# MODELED licensed PHY: geometry/timing assumptions, not silicon signoff
VERSION 5.8 ;
BUSBITCHARS "[]" ;
DIVIDERCHAR "/" ;
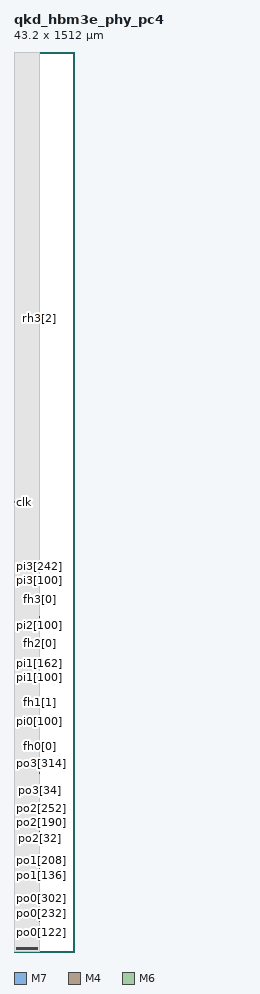
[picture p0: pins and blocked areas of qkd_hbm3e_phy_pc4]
MACRO qkd_hbm3e_phy_pc4
 CLASS BLOCK ;
 ORIGIN 0 0 ;
 SYMMETRY X Y ;
 SIZE 43.2 BY 1512 ;
 PIN clk
  DIRECTION INPUT ;
  USE CLOCK ;
  PORT
   LAYER M7 ;
   RECT 0.000000 755.904000 0.024000 756.096000 ;
  END
 END clk
 PIN rst_n
  DIRECTION INPUT ;
  USE SIGNAL ;
  PORT
   LAYER M7 ;
   RECT 0.000000 755.520000 0.024000 755.712000 ;
   RECT 0.000000 1485.984000 0.024000 1486.176000 ;
  END
 END rst_n
 PIN po0[0]
  DIRECTION INPUT ;
  USE SIGNAL ;
  PORT
   LAYER M4 ;
   RECT 43.008000 26.508000 43.200000 26.532000 ;
  END
 END po0[0]
 PIN po0[1]
  DIRECTION INPUT ;
  USE SIGNAL ;
  PORT
   LAYER M6 ;
   RECT 43.008000 26.352000 43.200000 26.384000 ;
  END
 END po0[1]
 PIN po0[2]
  DIRECTION INPUT ;
  USE SIGNAL ;
  PORT
   LAYER M4 ;
   RECT 43.008000 26.844000 43.200000 26.868000 ;
  END
 END po0[2]
 PIN po0[3]
  DIRECTION INPUT ;
  USE SIGNAL ;
  PORT
   LAYER M6 ;
   RECT 43.008000 26.608000 43.200000 26.640000 ;
  END
 END po0[3]
 PIN po0[4]
  DIRECTION INPUT ;
  USE SIGNAL ;
  PORT
   LAYER M4 ;
   RECT 43.008000 27.180000 43.200000 27.204000 ;
  END
 END po0[4]
 PIN po0[5]
  DIRECTION INPUT ;
  USE SIGNAL ;
  PORT
   LAYER M6 ;
   RECT 43.008000 26.864000 43.200000 26.896000 ;
  END
 END po0[5]
 PIN po0[6]
  DIRECTION INPUT ;
  USE SIGNAL ;
  PORT
   LAYER M4 ;
   RECT 43.008000 27.516000 43.200000 27.540000 ;
  END
 END po0[6]
 PIN po0[7]
  DIRECTION INPUT ;
  USE SIGNAL ;
  PORT
   LAYER M6 ;
   RECT 43.008000 27.120000 43.200000 27.152000 ;
  END
 END po0[7]
 PIN po0[8]
  DIRECTION INPUT ;
  USE SIGNAL ;
  PORT
   LAYER M4 ;
   RECT 43.008000 27.804000 43.200000 27.828000 ;
  END
 END po0[8]
 PIN po0[9]
  DIRECTION INPUT ;
  USE SIGNAL ;
  PORT
   LAYER M6 ;
   RECT 43.008000 27.376000 43.200000 27.408000 ;
  END
 END po0[9]
 PIN po0[10]
  DIRECTION INPUT ;
  USE SIGNAL ;
  PORT
   LAYER M4 ;
   RECT 43.008000 28.140000 43.200000 28.164000 ;
  END
 END po0[10]
 PIN po0[11]
  DIRECTION INPUT ;
  USE SIGNAL ;
  PORT
   LAYER M6 ;
   RECT 43.008000 28.592000 43.200000 28.624000 ;
  END
 END po0[11]
 PIN po0[12]
  DIRECTION INPUT ;
  USE SIGNAL ;
  PORT
   LAYER M4 ;
   RECT 43.008000 28.476000 43.200000 28.500000 ;
  END
 END po0[12]
 PIN po0[13]
  DIRECTION INPUT ;
  USE SIGNAL ;
  PORT
   LAYER M6 ;
   RECT 43.008000 28.848000 43.200000 28.880000 ;
  END
 END po0[13]
 PIN po0[14]
  DIRECTION INPUT ;
  USE SIGNAL ;
  PORT
   LAYER M4 ;
   RECT 43.008000 28.812000 43.200000 28.836000 ;
  END
 END po0[14]
 PIN po0[15]
  DIRECTION INPUT ;
  USE SIGNAL ;
  PORT
   LAYER M6 ;
   RECT 43.008000 29.104000 43.200000 29.136000 ;
  END
 END po0[15]
 PIN po0[16]
  DIRECTION INPUT ;
  USE SIGNAL ;
  PORT
   LAYER M4 ;
   RECT 43.008000 29.148000 43.200000 29.172000 ;
  END
 END po0[16]
 PIN po0[17]
  DIRECTION INPUT ;
  USE SIGNAL ;
  PORT
   LAYER M6 ;
   RECT 43.008000 29.360000 43.200000 29.392000 ;
  END
 END po0[17]
 PIN po0[18]
  DIRECTION INPUT ;
  USE SIGNAL ;
  PORT
   LAYER M4 ;
   RECT 43.008000 29.484000 43.200000 29.508000 ;
  END
 END po0[18]
 PIN po0[19]
  DIRECTION INPUT ;
  USE SIGNAL ;
  PORT
   LAYER M6 ;
   RECT 43.008000 29.616000 43.200000 29.648000 ;
  END
 END po0[19]
 PIN po0[20]
  DIRECTION INPUT ;
  USE SIGNAL ;
  PORT
   LAYER M4 ;
   RECT 43.008000 29.820000 43.200000 29.844000 ;
  END
 END po0[20]
 PIN po0[21]
  DIRECTION INPUT ;
  USE SIGNAL ;
  PORT
   LAYER M6 ;
   RECT 43.008000 29.872000 43.200000 29.904000 ;
  END
 END po0[21]
 PIN po0[22]
  DIRECTION INPUT ;
  USE SIGNAL ;
  PORT
   LAYER M4 ;
   RECT 43.008000 30.156000 43.200000 30.180000 ;
  END
 END po0[22]
 PIN po0[23]
  DIRECTION INPUT ;
  USE SIGNAL ;
  PORT
   LAYER M6 ;
   RECT 43.008000 30.128000 43.200000 30.160000 ;
  END
 END po0[23]
 PIN po0[24]
  DIRECTION INPUT ;
  USE SIGNAL ;
  PORT
   LAYER M4 ;
   RECT 43.008000 30.492000 43.200000 30.516000 ;
  END
 END po0[24]
 PIN po0[25]
  DIRECTION INPUT ;
  USE SIGNAL ;
  PORT
   LAYER M6 ;
   RECT 43.008000 30.384000 43.200000 30.416000 ;
  END
 END po0[25]
 PIN po0[26]
  DIRECTION INPUT ;
  USE SIGNAL ;
  PORT
   LAYER M4 ;
   RECT 43.008000 30.828000 43.200000 30.852000 ;
  END
 END po0[26]
 PIN po0[27]
  DIRECTION INPUT ;
  USE SIGNAL ;
  PORT
   LAYER M6 ;
   RECT 43.008000 30.640000 43.200000 30.672000 ;
  END
 END po0[27]
 PIN po0[28]
  DIRECTION INPUT ;
  USE SIGNAL ;
  PORT
   LAYER M4 ;
   RECT 43.008000 31.164000 43.200000 31.188000 ;
  END
 END po0[28]
 PIN po0[29]
  DIRECTION INPUT ;
  USE SIGNAL ;
  PORT
   LAYER M6 ;
   RECT 43.008000 30.896000 43.200000 30.928000 ;
  END
 END po0[29]
 PIN po0[30]
  DIRECTION INPUT ;
  USE SIGNAL ;
  PORT
   LAYER M4 ;
   RECT 43.008000 31.500000 43.200000 31.524000 ;
  END
 END po0[30]
 PIN po0[31]
  DIRECTION INPUT ;
  USE SIGNAL ;
  PORT
   LAYER M6 ;
   RECT 43.008000 31.152000 43.200000 31.184000 ;
  END
 END po0[31]
 PIN po0[32]
  DIRECTION INPUT ;
  USE SIGNAL ;
  PORT
   LAYER M4 ;
   RECT 43.008000 31.836000 43.200000 31.860000 ;
  END
 END po0[32]
 PIN po0[33]
  DIRECTION INPUT ;
  USE SIGNAL ;
  PORT
   LAYER M6 ;
   RECT 43.008000 31.408000 43.200000 31.440000 ;
  END
 END po0[33]
 PIN po0[34]
  DIRECTION INPUT ;
  USE SIGNAL ;
  PORT
   LAYER M4 ;
   RECT 43.008000 32.124000 43.200000 32.148000 ;
  END
 END po0[34]
 PIN po0[35]
  DIRECTION INPUT ;
  USE SIGNAL ;
  PORT
   LAYER M6 ;
   RECT 43.008000 31.664000 43.200000 31.696000 ;
  END
 END po0[35]
 PIN po0[36]
  DIRECTION INPUT ;
  USE SIGNAL ;
  PORT
   LAYER M4 ;
   RECT 43.008000 32.460000 43.200000 32.484000 ;
  END
 END po0[36]
 PIN po0[37]
  DIRECTION INPUT ;
  USE SIGNAL ;
  PORT
   LAYER M6 ;
   RECT 43.008000 32.880000 43.200000 32.912000 ;
  END
 END po0[37]
 PIN po0[38]
  DIRECTION INPUT ;
  USE SIGNAL ;
  PORT
   LAYER M4 ;
   RECT 43.008000 32.796000 43.200000 32.820000 ;
  END
 END po0[38]
 PIN po0[39]
  DIRECTION INPUT ;
  USE SIGNAL ;
  PORT
   LAYER M6 ;
   RECT 43.008000 33.200000 43.200000 33.232000 ;
  END
 END po0[39]
 PIN po0[40]
  DIRECTION INPUT ;
  USE SIGNAL ;
  PORT
   LAYER M4 ;
   RECT 43.008000 33.132000 43.200000 33.156000 ;
  END
 END po0[40]
 PIN po0[41]
  DIRECTION INPUT ;
  USE SIGNAL ;
  PORT
   LAYER M6 ;
   RECT 43.008000 33.456000 43.200000 33.488000 ;
  END
 END po0[41]
 PIN po0[42]
  DIRECTION INPUT ;
  USE SIGNAL ;
  PORT
   LAYER M4 ;
   RECT 43.008000 33.468000 43.200000 33.492000 ;
  END
 END po0[42]
 PIN po0[43]
  DIRECTION INPUT ;
  USE SIGNAL ;
  PORT
   LAYER M6 ;
   RECT 43.008000 33.712000 43.200000 33.744000 ;
  END
 END po0[43]
 PIN po0[44]
  DIRECTION INPUT ;
  USE SIGNAL ;
  PORT
   LAYER M4 ;
   RECT 43.008000 33.804000 43.200000 33.828000 ;
  END
 END po0[44]
 PIN po0[45]
  DIRECTION INPUT ;
  USE SIGNAL ;
  PORT
   LAYER M6 ;
   RECT 43.008000 33.968000 43.200000 34.000000 ;
  END
 END po0[45]
 PIN po0[46]
  DIRECTION INPUT ;
  USE SIGNAL ;
  PORT
   LAYER M4 ;
   RECT 43.008000 34.140000 43.200000 34.164000 ;
  END
 END po0[46]
 PIN po0[47]
  DIRECTION INPUT ;
  USE SIGNAL ;
  PORT
   LAYER M6 ;
   RECT 43.008000 34.224000 43.200000 34.256000 ;
  END
 END po0[47]
 PIN po0[48]
  DIRECTION INPUT ;
  USE SIGNAL ;
  PORT
   LAYER M4 ;
   RECT 43.008000 34.476000 43.200000 34.500000 ;
  END
 END po0[48]
 PIN po0[49]
  DIRECTION INPUT ;
  USE SIGNAL ;
  PORT
   LAYER M6 ;
   RECT 43.008000 34.480000 43.200000 34.512000 ;
  END
 END po0[49]
 PIN po0[50]
  DIRECTION INPUT ;
  USE SIGNAL ;
  PORT
   LAYER M4 ;
   RECT 43.008000 34.812000 43.200000 34.836000 ;
  END
 END po0[50]
 PIN po0[51]
  DIRECTION INPUT ;
  USE SIGNAL ;
  PORT
   LAYER M6 ;
   RECT 43.008000 34.736000 43.200000 34.768000 ;
  END
 END po0[51]
 PIN po0[52]
  DIRECTION INPUT ;
  USE SIGNAL ;
  PORT
   LAYER M4 ;
   RECT 43.008000 35.148000 43.200000 35.172000 ;
  END
 END po0[52]
 PIN po0[53]
  DIRECTION INPUT ;
  USE SIGNAL ;
  PORT
   LAYER M6 ;
   RECT 43.008000 34.992000 43.200000 35.024000 ;
  END
 END po0[53]
 PIN po0[54]
  DIRECTION INPUT ;
  USE SIGNAL ;
  PORT
   LAYER M4 ;
   RECT 43.008000 35.484000 43.200000 35.508000 ;
  END
 END po0[54]
 PIN po0[55]
  DIRECTION INPUT ;
  USE SIGNAL ;
  PORT
   LAYER M6 ;
   RECT 43.008000 35.248000 43.200000 35.280000 ;
  END
 END po0[55]
 PIN po0[56]
  DIRECTION INPUT ;
  USE SIGNAL ;
  PORT
   LAYER M4 ;
   RECT 43.008000 35.820000 43.200000 35.844000 ;
  END
 END po0[56]
 PIN po0[57]
  DIRECTION INPUT ;
  USE SIGNAL ;
  PORT
   LAYER M6 ;
   RECT 43.008000 35.504000 43.200000 35.536000 ;
  END
 END po0[57]
 PIN po0[58]
  DIRECTION INPUT ;
  USE SIGNAL ;
  PORT
   LAYER M4 ;
   RECT 43.008000 36.156000 43.200000 36.180000 ;
  END
 END po0[58]
 PIN po0[59]
  DIRECTION INPUT ;
  USE SIGNAL ;
  PORT
   LAYER M6 ;
   RECT 43.008000 35.760000 43.200000 35.792000 ;
  END
 END po0[59]
 PIN po0[60]
  DIRECTION INPUT ;
  USE SIGNAL ;
  PORT
   LAYER M4 ;
   RECT 43.008000 36.444000 43.200000 36.468000 ;
  END
 END po0[60]
 PIN po0[61]
  DIRECTION INPUT ;
  USE SIGNAL ;
  PORT
   LAYER M6 ;
   RECT 43.008000 36.016000 43.200000 36.048000 ;
  END
 END po0[61]
 PIN po0[62]
  DIRECTION INPUT ;
  USE SIGNAL ;
  PORT
   LAYER M4 ;
   RECT 43.008000 36.780000 43.200000 36.804000 ;
  END
 END po0[62]
 PIN po0[63]
  DIRECTION INPUT ;
  USE SIGNAL ;
  PORT
   LAYER M6 ;
   RECT 43.008000 37.232000 43.200000 37.264000 ;
  END
 END po0[63]
 PIN po0[64]
  DIRECTION INPUT ;
  USE SIGNAL ;
  PORT
   LAYER M4 ;
   RECT 43.008000 37.116000 43.200000 37.140000 ;
  END
 END po0[64]
 PIN po0[65]
  DIRECTION INPUT ;
  USE SIGNAL ;
  PORT
   LAYER M6 ;
   RECT 43.008000 37.488000 43.200000 37.520000 ;
  END
 END po0[65]
 PIN po0[66]
  DIRECTION INPUT ;
  USE SIGNAL ;
  PORT
   LAYER M4 ;
   RECT 43.008000 37.452000 43.200000 37.476000 ;
  END
 END po0[66]
 PIN po0[67]
  DIRECTION INPUT ;
  USE SIGNAL ;
  PORT
   LAYER M6 ;
   RECT 43.008000 37.744000 43.200000 37.776000 ;
  END
 END po0[67]
 PIN po0[68]
  DIRECTION INPUT ;
  USE SIGNAL ;
  PORT
   LAYER M4 ;
   RECT 43.008000 37.788000 43.200000 37.812000 ;
  END
 END po0[68]
 PIN po0[69]
  DIRECTION INPUT ;
  USE SIGNAL ;
  PORT
   LAYER M6 ;
   RECT 43.008000 38.000000 43.200000 38.032000 ;
  END
 END po0[69]
 PIN po0[70]
  DIRECTION INPUT ;
  USE SIGNAL ;
  PORT
   LAYER M4 ;
   RECT 43.008000 38.124000 43.200000 38.148000 ;
  END
 END po0[70]
 PIN po0[71]
  DIRECTION INPUT ;
  USE SIGNAL ;
  PORT
   LAYER M6 ;
   RECT 43.008000 38.256000 43.200000 38.288000 ;
  END
 END po0[71]
 PIN po0[72]
  DIRECTION INPUT ;
  USE SIGNAL ;
  PORT
   LAYER M4 ;
   RECT 43.008000 38.460000 43.200000 38.484000 ;
  END
 END po0[72]
 PIN po0[73]
  DIRECTION INPUT ;
  USE SIGNAL ;
  PORT
   LAYER M6 ;
   RECT 43.008000 38.512000 43.200000 38.544000 ;
  END
 END po0[73]
 PIN po0[74]
  DIRECTION INPUT ;
  USE SIGNAL ;
  PORT
   LAYER M4 ;
   RECT 43.008000 38.796000 43.200000 38.820000 ;
  END
 END po0[74]
 PIN po0[75]
  DIRECTION INPUT ;
  USE SIGNAL ;
  PORT
   LAYER M6 ;
   RECT 43.008000 38.832000 43.200000 38.864000 ;
  END
 END po0[75]
 PIN po0[76]
  DIRECTION INPUT ;
  USE SIGNAL ;
  PORT
   LAYER M4 ;
   RECT 43.008000 39.132000 43.200000 39.156000 ;
  END
 END po0[76]
 PIN po0[77]
  DIRECTION INPUT ;
  USE SIGNAL ;
  PORT
   LAYER M6 ;
   RECT 43.008000 39.088000 43.200000 39.120000 ;
  END
 END po0[77]
 PIN po0[78]
  DIRECTION INPUT ;
  USE SIGNAL ;
  PORT
   LAYER M4 ;
   RECT 43.008000 39.468000 43.200000 39.492000 ;
  END
 END po0[78]
 PIN po0[79]
  DIRECTION INPUT ;
  USE SIGNAL ;
  PORT
   LAYER M6 ;
   RECT 43.008000 39.344000 43.200000 39.376000 ;
  END
 END po0[79]
 PIN po0[80]
  DIRECTION INPUT ;
  USE SIGNAL ;
  PORT
   LAYER M4 ;
   RECT 43.008000 39.804000 43.200000 39.828000 ;
  END
 END po0[80]
 PIN po0[81]
  DIRECTION INPUT ;
  USE SIGNAL ;
  PORT
   LAYER M6 ;
   RECT 43.008000 39.600000 43.200000 39.632000 ;
  END
 END po0[81]
 PIN po0[82]
  DIRECTION INPUT ;
  USE SIGNAL ;
  PORT
   LAYER M4 ;
   RECT 43.008000 40.140000 43.200000 40.164000 ;
  END
 END po0[82]
 PIN po0[83]
  DIRECTION INPUT ;
  USE SIGNAL ;
  PORT
   LAYER M6 ;
   RECT 43.008000 39.856000 43.200000 39.888000 ;
  END
 END po0[83]
 PIN po0[84]
  DIRECTION INPUT ;
  USE SIGNAL ;
  PORT
   LAYER M4 ;
   RECT 43.008000 40.476000 43.200000 40.500000 ;
  END
 END po0[84]
 PIN po0[85]
  DIRECTION INPUT ;
  USE SIGNAL ;
  PORT
   LAYER M6 ;
   RECT 43.008000 40.112000 43.200000 40.144000 ;
  END
 END po0[85]
 PIN po0[86]
  DIRECTION INPUT ;
  USE SIGNAL ;
  PORT
   LAYER M4 ;
   RECT 43.008000 40.812000 43.200000 40.836000 ;
  END
 END po0[86]
 PIN po0[87]
  DIRECTION INPUT ;
  USE SIGNAL ;
  PORT
   LAYER M6 ;
   RECT 43.008000 40.368000 43.200000 40.400000 ;
  END
 END po0[87]
 PIN po0[88]
  DIRECTION INPUT ;
  USE SIGNAL ;
  PORT
   LAYER M4 ;
   RECT 43.008000 41.100000 43.200000 41.124000 ;
  END
 END po0[88]
 PIN po0[89]
  DIRECTION INPUT ;
  USE SIGNAL ;
  PORT
   LAYER M6 ;
   RECT 43.008000 41.584000 43.200000 41.616000 ;
  END
 END po0[89]
 PIN po0[90]
  DIRECTION INPUT ;
  USE SIGNAL ;
  PORT
   LAYER M4 ;
   RECT 43.008000 41.436000 43.200000 41.460000 ;
  END
 END po0[90]
 PIN po0[91]
  DIRECTION INPUT ;
  USE SIGNAL ;
  PORT
   LAYER M6 ;
   RECT 43.008000 41.840000 43.200000 41.872000 ;
  END
 END po0[91]
 PIN po0[92]
  DIRECTION INPUT ;
  USE SIGNAL ;
  PORT
   LAYER M4 ;
   RECT 43.008000 41.772000 43.200000 41.796000 ;
  END
 END po0[92]
 PIN po0[93]
  DIRECTION INPUT ;
  USE SIGNAL ;
  PORT
   LAYER M6 ;
   RECT 43.008000 42.096000 43.200000 42.128000 ;
  END
 END po0[93]
 PIN po0[94]
  DIRECTION INPUT ;
  USE SIGNAL ;
  PORT
   LAYER M4 ;
   RECT 43.008000 42.108000 43.200000 42.132000 ;
  END
 END po0[94]
 PIN po0[95]
  DIRECTION INPUT ;
  USE SIGNAL ;
  PORT
   LAYER M6 ;
   RECT 43.008000 42.352000 43.200000 42.384000 ;
  END
 END po0[95]
 PIN po0[96]
  DIRECTION INPUT ;
  USE SIGNAL ;
  PORT
   LAYER M4 ;
   RECT 43.008000 42.444000 43.200000 42.468000 ;
  END
 END po0[96]
 PIN po0[97]
  DIRECTION INPUT ;
  USE SIGNAL ;
  PORT
   LAYER M6 ;
   RECT 43.008000 42.608000 43.200000 42.640000 ;
  END
 END po0[97]
 PIN po0[98]
  DIRECTION INPUT ;
  USE SIGNAL ;
  PORT
   LAYER M4 ;
   RECT 43.008000 42.780000 43.200000 42.804000 ;
  END
 END po0[98]
 PIN po0[99]
  DIRECTION INPUT ;
  USE SIGNAL ;
  PORT
   LAYER M6 ;
   RECT 43.008000 42.864000 43.200000 42.896000 ;
  END
 END po0[99]
 PIN po0[100]
  DIRECTION INPUT ;
  USE SIGNAL ;
  PORT
   LAYER M4 ;
   RECT 43.008000 43.116000 43.200000 43.140000 ;
  END
 END po0[100]
 PIN po0[101]
  DIRECTION INPUT ;
  USE SIGNAL ;
  PORT
   LAYER M6 ;
   RECT 43.008000 43.120000 43.200000 43.152000 ;
  END
 END po0[101]
 PIN po0[102]
  DIRECTION INPUT ;
  USE SIGNAL ;
  PORT
   LAYER M4 ;
   RECT 43.008000 43.452000 43.200000 43.476000 ;
  END
 END po0[102]
 PIN po0[103]
  DIRECTION INPUT ;
  USE SIGNAL ;
  PORT
   LAYER M6 ;
   RECT 43.008000 43.376000 43.200000 43.408000 ;
  END
 END po0[103]
 PIN po0[104]
  DIRECTION INPUT ;
  USE SIGNAL ;
  PORT
   LAYER M4 ;
   RECT 43.008000 43.788000 43.200000 43.812000 ;
  END
 END po0[104]
 PIN po0[105]
  DIRECTION INPUT ;
  USE SIGNAL ;
  PORT
   LAYER M6 ;
   RECT 43.008000 43.632000 43.200000 43.664000 ;
  END
 END po0[105]
 PIN po0[106]
  DIRECTION INPUT ;
  USE SIGNAL ;
  PORT
   LAYER M4 ;
   RECT 43.008000 44.124000 43.200000 44.148000 ;
  END
 END po0[106]
 PIN po0[107]
  DIRECTION INPUT ;
  USE SIGNAL ;
  PORT
   LAYER M6 ;
   RECT 43.008000 43.888000 43.200000 43.920000 ;
  END
 END po0[107]
 PIN po0[108]
  DIRECTION INPUT ;
  USE SIGNAL ;
  PORT
   LAYER M4 ;
   RECT 43.008000 44.460000 43.200000 44.484000 ;
  END
 END po0[108]
 PIN po0[109]
  DIRECTION INPUT ;
  USE SIGNAL ;
  PORT
   LAYER M6 ;
   RECT 43.008000 44.144000 43.200000 44.176000 ;
  END
 END po0[109]
 PIN po0[110]
  DIRECTION INPUT ;
  USE SIGNAL ;
  PORT
   LAYER M4 ;
   RECT 43.008000 44.796000 43.200000 44.820000 ;
  END
 END po0[110]
 PIN po0[111]
  DIRECTION INPUT ;
  USE SIGNAL ;
  PORT
   LAYER M6 ;
   RECT 43.008000 44.464000 43.200000 44.496000 ;
  END
 END po0[111]
 PIN po0[112]
  DIRECTION INPUT ;
  USE SIGNAL ;
  PORT
   LAYER M4 ;
   RECT 43.008000 45.132000 43.200000 45.156000 ;
  END
 END po0[112]
 PIN po0[113]
  DIRECTION INPUT ;
  USE SIGNAL ;
  PORT
   LAYER M6 ;
   RECT 43.008000 44.720000 43.200000 44.752000 ;
  END
 END po0[113]
 PIN po0[114]
  DIRECTION INPUT ;
  USE SIGNAL ;
  PORT
   LAYER M4 ;
   RECT 43.008000 45.420000 43.200000 45.444000 ;
  END
 END po0[114]
 PIN po0[115]
  DIRECTION INPUT ;
  USE SIGNAL ;
  PORT
   LAYER M6 ;
   RECT 43.008000 45.936000 43.200000 45.968000 ;
  END
 END po0[115]
 PIN po0[116]
  DIRECTION INPUT ;
  USE SIGNAL ;
  PORT
   LAYER M4 ;
   RECT 43.008000 45.756000 43.200000 45.780000 ;
  END
 END po0[116]
 PIN po0[117]
  DIRECTION INPUT ;
  USE SIGNAL ;
  PORT
   LAYER M6 ;
   RECT 43.008000 46.192000 43.200000 46.224000 ;
  END
 END po0[117]
 PIN po0[118]
  DIRECTION INPUT ;
  USE SIGNAL ;
  PORT
   LAYER M4 ;
   RECT 43.008000 46.092000 43.200000 46.116000 ;
  END
 END po0[118]
 PIN po0[119]
  DIRECTION INPUT ;
  USE SIGNAL ;
  PORT
   LAYER M6 ;
   RECT 43.008000 46.448000 43.200000 46.480000 ;
  END
 END po0[119]
 PIN po0[120]
  DIRECTION INPUT ;
  USE SIGNAL ;
  PORT
   LAYER M4 ;
   RECT 43.008000 46.428000 43.200000 46.452000 ;
  END
 END po0[120]
 PIN po0[121]
  DIRECTION INPUT ;
  USE SIGNAL ;
  PORT
   LAYER M6 ;
   RECT 43.008000 46.704000 43.200000 46.736000 ;
  END
 END po0[121]
 PIN po0[122]
  DIRECTION INPUT ;
  USE SIGNAL ;
  PORT
   LAYER M4 ;
   RECT 43.008000 46.764000 43.200000 46.788000 ;
  END
 END po0[122]
 PIN po0[123]
  DIRECTION INPUT ;
  USE SIGNAL ;
  PORT
   LAYER M6 ;
   RECT 43.008000 46.960000 43.200000 46.992000 ;
  END
 END po0[123]
 PIN po0[124]
  DIRECTION INPUT ;
  USE SIGNAL ;
  PORT
   LAYER M4 ;
   RECT 43.008000 47.100000 43.200000 47.124000 ;
  END
 END po0[124]
 PIN po0[125]
  DIRECTION INPUT ;
  USE SIGNAL ;
  PORT
   LAYER M6 ;
   RECT 43.008000 47.216000 43.200000 47.248000 ;
  END
 END po0[125]
 PIN po0[126]
  DIRECTION INPUT ;
  USE SIGNAL ;
  PORT
   LAYER M4 ;
   RECT 43.008000 47.436000 43.200000 47.460000 ;
  END
 END po0[126]
 PIN po0[127]
  DIRECTION INPUT ;
  USE SIGNAL ;
  PORT
   LAYER M6 ;
   RECT 43.008000 47.472000 43.200000 47.504000 ;
  END
 END po0[127]
 PIN po0[128]
  DIRECTION INPUT ;
  USE SIGNAL ;
  PORT
   LAYER M4 ;
   RECT 43.008000 47.772000 43.200000 47.796000 ;
  END
 END po0[128]
 PIN po0[129]
  DIRECTION INPUT ;
  USE SIGNAL ;
  PORT
   LAYER M6 ;
   RECT 43.008000 47.728000 43.200000 47.760000 ;
  END
 END po0[129]
 PIN po0[130]
  DIRECTION INPUT ;
  USE SIGNAL ;
  PORT
   LAYER M4 ;
   RECT 43.008000 48.108000 43.200000 48.132000 ;
  END
 END po0[130]
 PIN po0[131]
  DIRECTION INPUT ;
  USE SIGNAL ;
  PORT
   LAYER M6 ;
   RECT 43.008000 47.984000 43.200000 48.016000 ;
  END
 END po0[131]
 PIN po0[132]
  DIRECTION INPUT ;
  USE SIGNAL ;
  PORT
   LAYER M4 ;
   RECT 43.008000 48.444000 43.200000 48.468000 ;
  END
 END po0[132]
 PIN po0[133]
  DIRECTION INPUT ;
  USE SIGNAL ;
  PORT
   LAYER M6 ;
   RECT 43.008000 48.240000 43.200000 48.272000 ;
  END
 END po0[133]
 PIN po0[134]
  DIRECTION INPUT ;
  USE SIGNAL ;
  PORT
   LAYER M4 ;
   RECT 43.008000 48.780000 43.200000 48.804000 ;
  END
 END po0[134]
 PIN po0[135]
  DIRECTION INPUT ;
  USE SIGNAL ;
  PORT
   LAYER M6 ;
   RECT 43.008000 48.496000 43.200000 48.528000 ;
  END
 END po0[135]
 PIN po0[136]
  DIRECTION INPUT ;
  USE SIGNAL ;
  PORT
   LAYER M4 ;
   RECT 43.008000 49.116000 43.200000 49.140000 ;
  END
 END po0[136]
 PIN po0[137]
  DIRECTION INPUT ;
  USE SIGNAL ;
  PORT
   LAYER M6 ;
   RECT 43.008000 48.752000 43.200000 48.784000 ;
  END
 END po0[137]
 PIN po0[138]
  DIRECTION INPUT ;
  USE SIGNAL ;
  PORT
   LAYER M4 ;
   RECT 43.008000 49.452000 43.200000 49.476000 ;
  END
 END po0[138]
 PIN po0[139]
  DIRECTION INPUT ;
  USE SIGNAL ;
  PORT
   LAYER M6 ;
   RECT 43.008000 49.008000 43.200000 49.040000 ;
  END
 END po0[139]
 PIN po0[140]
  DIRECTION INPUT ;
  USE SIGNAL ;
  PORT
   LAYER M4 ;
   RECT 43.008000 49.740000 43.200000 49.764000 ;
  END
 END po0[140]
 PIN po0[141]
  DIRECTION INPUT ;
  USE SIGNAL ;
  PORT
   LAYER M6 ;
   RECT 43.008000 50.224000 43.200000 50.256000 ;
  END
 END po0[141]
 PIN po0[142]
  DIRECTION INPUT ;
  USE SIGNAL ;
  PORT
   LAYER M4 ;
   RECT 43.008000 50.076000 43.200000 50.100000 ;
  END
 END po0[142]
 PIN po0[143]
  DIRECTION INPUT ;
  USE SIGNAL ;
  PORT
   LAYER M6 ;
   RECT 43.008000 50.480000 43.200000 50.512000 ;
  END
 END po0[143]
 PIN po0[144]
  DIRECTION INPUT ;
  USE SIGNAL ;
  PORT
   LAYER M4 ;
   RECT 43.008000 50.412000 43.200000 50.436000 ;
  END
 END po0[144]
 PIN po0[145]
  DIRECTION INPUT ;
  USE SIGNAL ;
  PORT
   LAYER M6 ;
   RECT 43.008000 50.736000 43.200000 50.768000 ;
  END
 END po0[145]
 PIN po0[146]
  DIRECTION INPUT ;
  USE SIGNAL ;
  PORT
   LAYER M4 ;
   RECT 43.008000 50.748000 43.200000 50.772000 ;
  END
 END po0[146]
 PIN po0[147]
  DIRECTION INPUT ;
  USE SIGNAL ;
  PORT
   LAYER M6 ;
   RECT 43.008000 51.056000 43.200000 51.088000 ;
  END
 END po0[147]
 PIN po0[148]
  DIRECTION INPUT ;
  USE SIGNAL ;
  PORT
   LAYER M4 ;
   RECT 43.008000 51.084000 43.200000 51.108000 ;
  END
 END po0[148]
 PIN po0[149]
  DIRECTION INPUT ;
  USE SIGNAL ;
  PORT
   LAYER M6 ;
   RECT 43.008000 51.312000 43.200000 51.344000 ;
  END
 END po0[149]
 PIN po0[150]
  DIRECTION INPUT ;
  USE SIGNAL ;
  PORT
   LAYER M4 ;
   RECT 43.008000 51.420000 43.200000 51.444000 ;
  END
 END po0[150]
 PIN po0[151]
  DIRECTION INPUT ;
  USE SIGNAL ;
  PORT
   LAYER M6 ;
   RECT 43.008000 51.568000 43.200000 51.600000 ;
  END
 END po0[151]
 PIN po0[152]
  DIRECTION INPUT ;
  USE SIGNAL ;
  PORT
   LAYER M4 ;
   RECT 43.008000 51.756000 43.200000 51.780000 ;
  END
 END po0[152]
 PIN po0[153]
  DIRECTION INPUT ;
  USE SIGNAL ;
  PORT
   LAYER M6 ;
   RECT 43.008000 51.824000 43.200000 51.856000 ;
  END
 END po0[153]
 PIN po0[154]
  DIRECTION INPUT ;
  USE SIGNAL ;
  PORT
   LAYER M4 ;
   RECT 43.008000 52.092000 43.200000 52.116000 ;
  END
 END po0[154]
 PIN po0[155]
  DIRECTION INPUT ;
  USE SIGNAL ;
  PORT
   LAYER M6 ;
   RECT 43.008000 52.080000 43.200000 52.112000 ;
  END
 END po0[155]
 PIN po0[156]
  DIRECTION INPUT ;
  USE SIGNAL ;
  PORT
   LAYER M4 ;
   RECT 43.008000 52.428000 43.200000 52.452000 ;
  END
 END po0[156]
 PIN po0[157]
  DIRECTION INPUT ;
  USE SIGNAL ;
  PORT
   LAYER M6 ;
   RECT 43.008000 52.336000 43.200000 52.368000 ;
  END
 END po0[157]
 PIN po0[158]
  DIRECTION INPUT ;
  USE SIGNAL ;
  PORT
   LAYER M4 ;
   RECT 43.008000 52.764000 43.200000 52.788000 ;
  END
 END po0[158]
 PIN po0[159]
  DIRECTION INPUT ;
  USE SIGNAL ;
  PORT
   LAYER M6 ;
   RECT 43.008000 52.592000 43.200000 52.624000 ;
  END
 END po0[159]
 PIN po0[160]
  DIRECTION INPUT ;
  USE SIGNAL ;
  PORT
   LAYER M4 ;
   RECT 43.008000 53.100000 43.200000 53.124000 ;
  END
 END po0[160]
 PIN po0[161]
  DIRECTION INPUT ;
  USE SIGNAL ;
  PORT
   LAYER M6 ;
   RECT 43.008000 52.848000 43.200000 52.880000 ;
  END
 END po0[161]
 PIN po0[162]
  DIRECTION INPUT ;
  USE SIGNAL ;
  PORT
   LAYER M4 ;
   RECT 43.008000 53.436000 43.200000 53.460000 ;
  END
 END po0[162]
 PIN po0[163]
  DIRECTION INPUT ;
  USE SIGNAL ;
  PORT
   LAYER M6 ;
   RECT 43.008000 53.104000 43.200000 53.136000 ;
  END
 END po0[163]
 PIN po0[164]
  DIRECTION INPUT ;
  USE SIGNAL ;
  PORT
   LAYER M4 ;
   RECT 43.008000 53.772000 43.200000 53.796000 ;
  END
 END po0[164]
 PIN po0[165]
  DIRECTION INPUT ;
  USE SIGNAL ;
  PORT
   LAYER M6 ;
   RECT 43.008000 53.424000 43.200000 53.456000 ;
  END
 END po0[165]
 PIN po0[166]
  DIRECTION INPUT ;
  USE SIGNAL ;
  PORT
   LAYER M4 ;
   RECT 43.008000 54.108000 43.200000 54.132000 ;
  END
 END po0[166]
 PIN po0[167]
  DIRECTION INPUT ;
  USE SIGNAL ;
  PORT
   LAYER M6 ;
   RECT 43.008000 54.640000 43.200000 54.672000 ;
  END
 END po0[167]
 PIN po0[168]
  DIRECTION INPUT ;
  USE SIGNAL ;
  PORT
   LAYER M4 ;
   RECT 43.008000 54.396000 43.200000 54.420000 ;
  END
 END po0[168]
 PIN po0[169]
  DIRECTION INPUT ;
  USE SIGNAL ;
  PORT
   LAYER M6 ;
   RECT 43.008000 54.896000 43.200000 54.928000 ;
  END
 END po0[169]
 PIN po0[170]
  DIRECTION INPUT ;
  USE SIGNAL ;
  PORT
   LAYER M4 ;
   RECT 43.008000 54.732000 43.200000 54.756000 ;
  END
 END po0[170]
 PIN po0[171]
  DIRECTION INPUT ;
  USE SIGNAL ;
  PORT
   LAYER M6 ;
   RECT 43.008000 55.152000 43.200000 55.184000 ;
  END
 END po0[171]
 PIN po0[172]
  DIRECTION INPUT ;
  USE SIGNAL ;
  PORT
   LAYER M4 ;
   RECT 43.008000 55.068000 43.200000 55.092000 ;
  END
 END po0[172]
 PIN po0[173]
  DIRECTION INPUT ;
  USE SIGNAL ;
  PORT
   LAYER M6 ;
   RECT 43.008000 55.408000 43.200000 55.440000 ;
  END
 END po0[173]
 PIN po0[174]
  DIRECTION INPUT ;
  USE SIGNAL ;
  PORT
   LAYER M4 ;
   RECT 43.008000 55.404000 43.200000 55.428000 ;
  END
 END po0[174]
 PIN po0[175]
  DIRECTION INPUT ;
  USE SIGNAL ;
  PORT
   LAYER M6 ;
   RECT 43.008000 55.664000 43.200000 55.696000 ;
  END
 END po0[175]
 PIN po0[176]
  DIRECTION INPUT ;
  USE SIGNAL ;
  PORT
   LAYER M4 ;
   RECT 43.008000 55.740000 43.200000 55.764000 ;
  END
 END po0[176]
 PIN po0[177]
  DIRECTION INPUT ;
  USE SIGNAL ;
  PORT
   LAYER M6 ;
   RECT 43.008000 55.920000 43.200000 55.952000 ;
  END
 END po0[177]
 PIN po0[178]
  DIRECTION INPUT ;
  USE SIGNAL ;
  PORT
   LAYER M4 ;
   RECT 43.008000 56.076000 43.200000 56.100000 ;
  END
 END po0[178]
 PIN po0[179]
  DIRECTION INPUT ;
  USE SIGNAL ;
  PORT
   LAYER M6 ;
   RECT 43.008000 56.176000 43.200000 56.208000 ;
  END
 END po0[179]
 PIN po0[180]
  DIRECTION INPUT ;
  USE SIGNAL ;
  PORT
   LAYER M4 ;
   RECT 43.008000 56.412000 43.200000 56.436000 ;
  END
 END po0[180]
 PIN po0[181]
  DIRECTION INPUT ;
  USE SIGNAL ;
  PORT
   LAYER M6 ;
   RECT 43.008000 56.432000 43.200000 56.464000 ;
  END
 END po0[181]
 PIN po0[182]
  DIRECTION INPUT ;
  USE SIGNAL ;
  PORT
   LAYER M4 ;
   RECT 43.008000 56.748000 43.200000 56.772000 ;
  END
 END po0[182]
 PIN po0[183]
  DIRECTION INPUT ;
  USE SIGNAL ;
  PORT
   LAYER M6 ;
   RECT 43.008000 56.752000 43.200000 56.784000 ;
  END
 END po0[183]
 PIN po0[184]
  DIRECTION INPUT ;
  USE SIGNAL ;
  PORT
   LAYER M4 ;
   RECT 43.008000 57.084000 43.200000 57.108000 ;
  END
 END po0[184]
 PIN po0[185]
  DIRECTION INPUT ;
  USE SIGNAL ;
  PORT
   LAYER M6 ;
   RECT 43.008000 57.008000 43.200000 57.040000 ;
  END
 END po0[185]
 PIN po0[186]
  DIRECTION INPUT ;
  USE SIGNAL ;
  PORT
   LAYER M4 ;
   RECT 43.008000 57.420000 43.200000 57.444000 ;
  END
 END po0[186]
 PIN po0[187]
  DIRECTION INPUT ;
  USE SIGNAL ;
  PORT
   LAYER M6 ;
   RECT 43.008000 57.264000 43.200000 57.296000 ;
  END
 END po0[187]
 PIN po0[188]
  DIRECTION INPUT ;
  USE SIGNAL ;
  PORT
   LAYER M4 ;
   RECT 43.008000 57.756000 43.200000 57.780000 ;
  END
 END po0[188]
 PIN po0[189]
  DIRECTION INPUT ;
  USE SIGNAL ;
  PORT
   LAYER M6 ;
   RECT 43.008000 57.520000 43.200000 57.552000 ;
  END
 END po0[189]
 PIN po0[190]
  DIRECTION INPUT ;
  USE SIGNAL ;
  PORT
   LAYER M4 ;
   RECT 43.008000 58.092000 43.200000 58.116000 ;
  END
 END po0[190]
 PIN po0[191]
  DIRECTION INPUT ;
  USE SIGNAL ;
  PORT
   LAYER M6 ;
   RECT 43.008000 57.776000 43.200000 57.808000 ;
  END
 END po0[191]
 PIN po0[192]
  DIRECTION INPUT ;
  USE SIGNAL ;
  PORT
   LAYER M4 ;
   RECT 43.008000 58.428000 43.200000 58.452000 ;
  END
 END po0[192]
 PIN po0[193]
  DIRECTION INPUT ;
  USE SIGNAL ;
  PORT
   LAYER M6 ;
   RECT 43.008000 58.992000 43.200000 59.024000 ;
  END
 END po0[193]
 PIN po0[194]
  DIRECTION INPUT ;
  USE SIGNAL ;
  PORT
   LAYER M4 ;
   RECT 43.008000 58.716000 43.200000 58.740000 ;
  END
 END po0[194]
 PIN po0[195]
  DIRECTION INPUT ;
  USE SIGNAL ;
  PORT
   LAYER M6 ;
   RECT 43.008000 59.248000 43.200000 59.280000 ;
  END
 END po0[195]
 PIN po0[196]
  DIRECTION INPUT ;
  USE SIGNAL ;
  PORT
   LAYER M4 ;
   RECT 43.008000 59.052000 43.200000 59.076000 ;
  END
 END po0[196]
 PIN po0[197]
  DIRECTION INPUT ;
  USE SIGNAL ;
  PORT
   LAYER M6 ;
   RECT 43.008000 59.504000 43.200000 59.536000 ;
  END
 END po0[197]
 PIN po0[198]
  DIRECTION INPUT ;
  USE SIGNAL ;
  PORT
   LAYER M4 ;
   RECT 43.008000 59.388000 43.200000 59.412000 ;
  END
 END po0[198]
 PIN po0[199]
  DIRECTION INPUT ;
  USE SIGNAL ;
  PORT
   LAYER M6 ;
   RECT 43.008000 59.760000 43.200000 59.792000 ;
  END
 END po0[199]
 PIN po0[200]
  DIRECTION INPUT ;
  USE SIGNAL ;
  PORT
   LAYER M4 ;
   RECT 43.008000 59.724000 43.200000 59.748000 ;
  END
 END po0[200]
 PIN po0[201]
  DIRECTION INPUT ;
  USE SIGNAL ;
  PORT
   LAYER M6 ;
   RECT 43.008000 60.016000 43.200000 60.048000 ;
  END
 END po0[201]
 PIN po0[202]
  DIRECTION INPUT ;
  USE SIGNAL ;
  PORT
   LAYER M4 ;
   RECT 43.008000 60.060000 43.200000 60.084000 ;
  END
 END po0[202]
 PIN po0[203]
  DIRECTION INPUT ;
  USE SIGNAL ;
  PORT
   LAYER M6 ;
   RECT 43.008000 60.272000 43.200000 60.304000 ;
  END
 END po0[203]
 PIN po0[204]
  DIRECTION INPUT ;
  USE SIGNAL ;
  PORT
   LAYER M4 ;
   RECT 43.008000 60.396000 43.200000 60.420000 ;
  END
 END po0[204]
 PIN po0[205]
  DIRECTION INPUT ;
  USE SIGNAL ;
  PORT
   LAYER M6 ;
   RECT 43.008000 60.528000 43.200000 60.560000 ;
  END
 END po0[205]
 PIN po0[206]
  DIRECTION INPUT ;
  USE SIGNAL ;
  PORT
   LAYER M4 ;
   RECT 43.008000 60.732000 43.200000 60.756000 ;
  END
 END po0[206]
 PIN po0[207]
  DIRECTION INPUT ;
  USE SIGNAL ;
  PORT
   LAYER M6 ;
   RECT 43.008000 60.784000 43.200000 60.816000 ;
  END
 END po0[207]
 PIN po0[208]
  DIRECTION INPUT ;
  USE SIGNAL ;
  PORT
   LAYER M4 ;
   RECT 43.008000 61.068000 43.200000 61.092000 ;
  END
 END po0[208]
 PIN po0[209]
  DIRECTION INPUT ;
  USE SIGNAL ;
  PORT
   LAYER M6 ;
   RECT 43.008000 61.040000 43.200000 61.072000 ;
  END
 END po0[209]
 PIN po0[210]
  DIRECTION INPUT ;
  USE SIGNAL ;
  PORT
   LAYER M4 ;
   RECT 43.008000 61.404000 43.200000 61.428000 ;
  END
 END po0[210]
 PIN po0[211]
  DIRECTION INPUT ;
  USE SIGNAL ;
  PORT
   LAYER M6 ;
   RECT 43.008000 61.296000 43.200000 61.328000 ;
  END
 END po0[211]
 PIN po0[212]
  DIRECTION INPUT ;
  USE SIGNAL ;
  PORT
   LAYER M4 ;
   RECT 43.008000 61.740000 43.200000 61.764000 ;
  END
 END po0[212]
 PIN po0[213]
  DIRECTION INPUT ;
  USE SIGNAL ;
  PORT
   LAYER M6 ;
   RECT 43.008000 61.552000 43.200000 61.584000 ;
  END
 END po0[213]
 PIN po0[214]
  DIRECTION INPUT ;
  USE SIGNAL ;
  PORT
   LAYER M4 ;
   RECT 43.008000 62.076000 43.200000 62.100000 ;
  END
 END po0[214]
 PIN po0[215]
  DIRECTION INPUT ;
  USE SIGNAL ;
  PORT
   LAYER M6 ;
   RECT 43.008000 61.808000 43.200000 61.840000 ;
  END
 END po0[215]
 PIN po0[216]
  DIRECTION INPUT ;
  USE SIGNAL ;
  PORT
   LAYER M4 ;
   RECT 43.008000 62.412000 43.200000 62.436000 ;
  END
 END po0[216]
 PIN po0[217]
  DIRECTION INPUT ;
  USE SIGNAL ;
  PORT
   LAYER M6 ;
   RECT 43.008000 62.064000 43.200000 62.096000 ;
  END
 END po0[217]
 PIN po0[218]
  DIRECTION INPUT ;
  USE SIGNAL ;
  PORT
   LAYER M4 ;
   RECT 43.008000 62.748000 43.200000 62.772000 ;
  END
 END po0[218]
 PIN po0[219]
  DIRECTION INPUT ;
  USE SIGNAL ;
  PORT
   LAYER M6 ;
   RECT 43.008000 63.344000 43.200000 63.376000 ;
  END
 END po0[219]
 PIN po0[220]
  DIRECTION INPUT ;
  USE SIGNAL ;
  PORT
   LAYER M4 ;
   RECT 43.008000 63.084000 43.200000 63.108000 ;
  END
 END po0[220]
 PIN po0[221]
  DIRECTION INPUT ;
  USE SIGNAL ;
  PORT
   LAYER M6 ;
   RECT 43.008000 63.600000 43.200000 63.632000 ;
  END
 END po0[221]
 PIN po0[222]
  DIRECTION INPUT ;
  USE SIGNAL ;
  PORT
   LAYER M4 ;
   RECT 43.008000 63.372000 43.200000 63.396000 ;
  END
 END po0[222]
 PIN po0[223]
  DIRECTION INPUT ;
  USE SIGNAL ;
  PORT
   LAYER M6 ;
   RECT 43.008000 63.856000 43.200000 63.888000 ;
  END
 END po0[223]
 PIN po0[224]
  DIRECTION INPUT ;
  USE SIGNAL ;
  PORT
   LAYER M4 ;
   RECT 43.008000 63.708000 43.200000 63.732000 ;
  END
 END po0[224]
 PIN po0[225]
  DIRECTION INPUT ;
  USE SIGNAL ;
  PORT
   LAYER M6 ;
   RECT 43.008000 64.112000 43.200000 64.144000 ;
  END
 END po0[225]
 PIN po0[226]
  DIRECTION INPUT ;
  USE SIGNAL ;
  PORT
   LAYER M4 ;
   RECT 43.008000 64.044000 43.200000 64.068000 ;
  END
 END po0[226]
 PIN po0[227]
  DIRECTION INPUT ;
  USE SIGNAL ;
  PORT
   LAYER M6 ;
   RECT 43.008000 64.368000 43.200000 64.400000 ;
  END
 END po0[227]
 PIN po0[228]
  DIRECTION INPUT ;
  USE SIGNAL ;
  PORT
   LAYER M4 ;
   RECT 43.008000 64.380000 43.200000 64.404000 ;
  END
 END po0[228]
 PIN po0[229]
  DIRECTION INPUT ;
  USE SIGNAL ;
  PORT
   LAYER M6 ;
   RECT 43.008000 64.624000 43.200000 64.656000 ;
  END
 END po0[229]
 PIN po0[230]
  DIRECTION INPUT ;
  USE SIGNAL ;
  PORT
   LAYER M4 ;
   RECT 43.008000 64.716000 43.200000 64.740000 ;
  END
 END po0[230]
 PIN po0[231]
  DIRECTION INPUT ;
  USE SIGNAL ;
  PORT
   LAYER M6 ;
   RECT 43.008000 64.880000 43.200000 64.912000 ;
  END
 END po0[231]
 PIN po0[232]
  DIRECTION INPUT ;
  USE SIGNAL ;
  PORT
   LAYER M4 ;
   RECT 43.008000 65.052000 43.200000 65.076000 ;
  END
 END po0[232]
 PIN po0[233]
  DIRECTION INPUT ;
  USE SIGNAL ;
  PORT
   LAYER M6 ;
   RECT 43.008000 65.136000 43.200000 65.168000 ;
  END
 END po0[233]
 PIN po0[234]
  DIRECTION INPUT ;
  USE SIGNAL ;
  PORT
   LAYER M4 ;
   RECT 43.008000 65.388000 43.200000 65.412000 ;
  END
 END po0[234]
 PIN po0[235]
  DIRECTION INPUT ;
  USE SIGNAL ;
  PORT
   LAYER M6 ;
   RECT 43.008000 65.392000 43.200000 65.424000 ;
  END
 END po0[235]
 PIN po0[236]
  DIRECTION INPUT ;
  USE SIGNAL ;
  PORT
   LAYER M4 ;
   RECT 43.008000 65.724000 43.200000 65.748000 ;
  END
 END po0[236]
 PIN po0[237]
  DIRECTION INPUT ;
  USE SIGNAL ;
  PORT
   LAYER M6 ;
   RECT 43.008000 65.648000 43.200000 65.680000 ;
  END
 END po0[237]
 PIN po0[238]
  DIRECTION INPUT ;
  USE SIGNAL ;
  PORT
   LAYER M4 ;
   RECT 43.008000 66.060000 43.200000 66.084000 ;
  END
 END po0[238]
 PIN po0[239]
  DIRECTION INPUT ;
  USE SIGNAL ;
  PORT
   LAYER M6 ;
   RECT 43.008000 65.904000 43.200000 65.936000 ;
  END
 END po0[239]
 PIN po0[240]
  DIRECTION INPUT ;
  USE SIGNAL ;
  PORT
   LAYER M4 ;
   RECT 43.008000 66.396000 43.200000 66.420000 ;
  END
 END po0[240]
 PIN po0[241]
  DIRECTION INPUT ;
  USE SIGNAL ;
  PORT
   LAYER M6 ;
   RECT 43.008000 66.160000 43.200000 66.192000 ;
  END
 END po0[241]
 PIN po0[242]
  DIRECTION INPUT ;
  USE SIGNAL ;
  PORT
   LAYER M4 ;
   RECT 43.008000 66.732000 43.200000 66.756000 ;
  END
 END po0[242]
 PIN po0[243]
  DIRECTION INPUT ;
  USE SIGNAL ;
  PORT
   LAYER M6 ;
   RECT 43.008000 66.416000 43.200000 66.448000 ;
  END
 END po0[243]
 PIN po0[244]
  DIRECTION INPUT ;
  USE SIGNAL ;
  PORT
   LAYER M4 ;
   RECT 43.008000 67.068000 43.200000 67.092000 ;
  END
 END po0[244]
 PIN po0[245]
  DIRECTION INPUT ;
  USE SIGNAL ;
  PORT
   LAYER M6 ;
   RECT 43.008000 67.632000 43.200000 67.664000 ;
  END
 END po0[245]
 PIN po0[246]
  DIRECTION INPUT ;
  USE SIGNAL ;
  PORT
   LAYER M4 ;
   RECT 43.008000 67.404000 43.200000 67.428000 ;
  END
 END po0[246]
 PIN po0[247]
  DIRECTION INPUT ;
  USE SIGNAL ;
  PORT
   LAYER M6 ;
   RECT 43.008000 67.888000 43.200000 67.920000 ;
  END
 END po0[247]
 PIN po0[248]
  DIRECTION INPUT ;
  USE SIGNAL ;
  PORT
   LAYER M4 ;
   RECT 43.008000 67.692000 43.200000 67.716000 ;
  END
 END po0[248]
 PIN po0[249]
  DIRECTION INPUT ;
  USE SIGNAL ;
  PORT
   LAYER M6 ;
   RECT 43.008000 68.144000 43.200000 68.176000 ;
  END
 END po0[249]
 PIN po0[250]
  DIRECTION INPUT ;
  USE SIGNAL ;
  PORT
   LAYER M4 ;
   RECT 43.008000 68.028000 43.200000 68.052000 ;
  END
 END po0[250]
 PIN po0[251]
  DIRECTION INPUT ;
  USE SIGNAL ;
  PORT
   LAYER M6 ;
   RECT 43.008000 68.400000 43.200000 68.432000 ;
  END
 END po0[251]
 PIN po0[252]
  DIRECTION INPUT ;
  USE SIGNAL ;
  PORT
   LAYER M4 ;
   RECT 43.008000 68.364000 43.200000 68.388000 ;
  END
 END po0[252]
 PIN po0[253]
  DIRECTION INPUT ;
  USE SIGNAL ;
  PORT
   LAYER M6 ;
   RECT 43.008000 68.656000 43.200000 68.688000 ;
  END
 END po0[253]
 PIN po0[254]
  DIRECTION INPUT ;
  USE SIGNAL ;
  PORT
   LAYER M4 ;
   RECT 43.008000 68.700000 43.200000 68.724000 ;
  END
 END po0[254]
 PIN po0[255]
  DIRECTION INPUT ;
  USE SIGNAL ;
  PORT
   LAYER M6 ;
   RECT 43.008000 68.976000 43.200000 69.008000 ;
  END
 END po0[255]
 PIN po0[256]
  DIRECTION INPUT ;
  USE SIGNAL ;
  PORT
   LAYER M4 ;
   RECT 43.008000 69.036000 43.200000 69.060000 ;
  END
 END po0[256]
 PIN po0[257]
  DIRECTION INPUT ;
  USE SIGNAL ;
  PORT
   LAYER M6 ;
   RECT 43.008000 69.232000 43.200000 69.264000 ;
  END
 END po0[257]
 PIN po0[258]
  DIRECTION INPUT ;
  USE SIGNAL ;
  PORT
   LAYER M4 ;
   RECT 43.008000 69.372000 43.200000 69.396000 ;
  END
 END po0[258]
 PIN po0[259]
  DIRECTION INPUT ;
  USE SIGNAL ;
  PORT
   LAYER M6 ;
   RECT 43.008000 69.488000 43.200000 69.520000 ;
  END
 END po0[259]
 PIN po0[260]
  DIRECTION INPUT ;
  USE SIGNAL ;
  PORT
   LAYER M4 ;
   RECT 43.008000 69.708000 43.200000 69.732000 ;
  END
 END po0[260]
 PIN po0[261]
  DIRECTION INPUT ;
  USE SIGNAL ;
  PORT
   LAYER M6 ;
   RECT 43.008000 69.744000 43.200000 69.776000 ;
  END
 END po0[261]
 PIN po0[262]
  DIRECTION INPUT ;
  USE SIGNAL ;
  PORT
   LAYER M4 ;
   RECT 43.008000 70.044000 43.200000 70.068000 ;
  END
 END po0[262]
 PIN po0[263]
  DIRECTION INPUT ;
  USE SIGNAL ;
  PORT
   LAYER M6 ;
   RECT 43.008000 70.000000 43.200000 70.032000 ;
  END
 END po0[263]
 PIN po0[264]
  DIRECTION INPUT ;
  USE SIGNAL ;
  PORT
   LAYER M4 ;
   RECT 43.008000 70.380000 43.200000 70.404000 ;
  END
 END po0[264]
 PIN po0[265]
  DIRECTION INPUT ;
  USE SIGNAL ;
  PORT
   LAYER M6 ;
   RECT 43.008000 70.256000 43.200000 70.288000 ;
  END
 END po0[265]
 PIN po0[266]
  DIRECTION INPUT ;
  USE SIGNAL ;
  PORT
   LAYER M4 ;
   RECT 43.008000 70.716000 43.200000 70.740000 ;
  END
 END po0[266]
 PIN po0[267]
  DIRECTION INPUT ;
  USE SIGNAL ;
  PORT
   LAYER M6 ;
   RECT 43.008000 70.512000 43.200000 70.544000 ;
  END
 END po0[267]
 PIN po0[268]
  DIRECTION INPUT ;
  USE SIGNAL ;
  PORT
   LAYER M4 ;
   RECT 43.008000 71.052000 43.200000 71.076000 ;
  END
 END po0[268]
 PIN po0[269]
  DIRECTION INPUT ;
  USE SIGNAL ;
  PORT
   LAYER M6 ;
   RECT 43.008000 70.768000 43.200000 70.800000 ;
  END
 END po0[269]
 PIN po0[270]
  DIRECTION INPUT ;
  USE SIGNAL ;
  PORT
   LAYER M4 ;
   RECT 43.008000 71.388000 43.200000 71.412000 ;
  END
 END po0[270]
 PIN po0[271]
  DIRECTION INPUT ;
  USE SIGNAL ;
  PORT
   LAYER M6 ;
   RECT 43.008000 71.984000 43.200000 72.016000 ;
  END
 END po0[271]
 PIN po0[272]
  DIRECTION INPUT ;
  USE SIGNAL ;
  PORT
   LAYER M4 ;
   RECT 43.008000 71.724000 43.200000 71.748000 ;
  END
 END po0[272]
 PIN po0[273]
  DIRECTION INPUT ;
  USE SIGNAL ;
  PORT
   LAYER M6 ;
   RECT 43.008000 72.240000 43.200000 72.272000 ;
  END
 END po0[273]
 PIN po0[274]
  DIRECTION INPUT ;
  USE SIGNAL ;
  PORT
   LAYER M4 ;
   RECT 43.008000 72.012000 43.200000 72.036000 ;
  END
 END po0[274]
 PIN po0[275]
  DIRECTION INPUT ;
  USE SIGNAL ;
  PORT
   LAYER M6 ;
   RECT 43.008000 72.496000 43.200000 72.528000 ;
  END
 END po0[275]
 PIN po0[276]
  DIRECTION INPUT ;
  USE SIGNAL ;
  PORT
   LAYER M4 ;
   RECT 43.008000 72.348000 43.200000 72.372000 ;
  END
 END po0[276]
 PIN po0[277]
  DIRECTION INPUT ;
  USE SIGNAL ;
  PORT
   LAYER M6 ;
   RECT 43.008000 72.752000 43.200000 72.784000 ;
  END
 END po0[277]
 PIN po0[278]
  DIRECTION INPUT ;
  USE SIGNAL ;
  PORT
   LAYER M4 ;
   RECT 43.008000 72.684000 43.200000 72.708000 ;
  END
 END po0[278]
 PIN po0[279]
  DIRECTION INPUT ;
  USE SIGNAL ;
  PORT
   LAYER M6 ;
   RECT 43.008000 73.008000 43.200000 73.040000 ;
  END
 END po0[279]
 PIN po0[280]
  DIRECTION INPUT ;
  USE SIGNAL ;
  PORT
   LAYER M4 ;
   RECT 43.008000 73.020000 43.200000 73.044000 ;
  END
 END po0[280]
 PIN po0[281]
  DIRECTION INPUT ;
  USE SIGNAL ;
  PORT
   LAYER M6 ;
   RECT 43.008000 73.264000 43.200000 73.296000 ;
  END
 END po0[281]
 PIN po0[282]
  DIRECTION INPUT ;
  USE SIGNAL ;
  PORT
   LAYER M4 ;
   RECT 43.008000 73.356000 43.200000 73.380000 ;
  END
 END po0[282]
 PIN po0[283]
  DIRECTION INPUT ;
  USE SIGNAL ;
  PORT
   LAYER M6 ;
   RECT 43.008000 73.520000 43.200000 73.552000 ;
  END
 END po0[283]
 PIN po0[284]
  DIRECTION INPUT ;
  USE SIGNAL ;
  PORT
   LAYER M4 ;
   RECT 43.008000 73.692000 43.200000 73.716000 ;
  END
 END po0[284]
 PIN po0[285]
  DIRECTION INPUT ;
  USE SIGNAL ;
  PORT
   LAYER M6 ;
   RECT 43.008000 73.776000 43.200000 73.808000 ;
  END
 END po0[285]
 PIN po0[286]
  DIRECTION INPUT ;
  USE SIGNAL ;
  PORT
   LAYER M4 ;
   RECT 43.008000 74.028000 43.200000 74.052000 ;
  END
 END po0[286]
 PIN po0[287]
  DIRECTION INPUT ;
  USE SIGNAL ;
  PORT
   LAYER M6 ;
   RECT 43.008000 74.032000 43.200000 74.064000 ;
  END
 END po0[287]
 PIN po0[288]
  DIRECTION INPUT ;
  USE SIGNAL ;
  PORT
   LAYER M4 ;
   RECT 43.008000 74.364000 43.200000 74.388000 ;
  END
 END po0[288]
 PIN po0[289]
  DIRECTION INPUT ;
  USE SIGNAL ;
  PORT
   LAYER M6 ;
   RECT 43.008000 74.288000 43.200000 74.320000 ;
  END
 END po0[289]
 PIN po0[290]
  DIRECTION INPUT ;
  USE SIGNAL ;
  PORT
   LAYER M4 ;
   RECT 43.008000 74.700000 43.200000 74.724000 ;
  END
 END po0[290]
 PIN po0[291]
  DIRECTION INPUT ;
  USE SIGNAL ;
  PORT
   LAYER M6 ;
   RECT 43.008000 74.608000 43.200000 74.640000 ;
  END
 END po0[291]
 PIN po0[292]
  DIRECTION INPUT ;
  USE SIGNAL ;
  PORT
   LAYER M4 ;
   RECT 43.008000 75.036000 43.200000 75.060000 ;
  END
 END po0[292]
 PIN po0[293]
  DIRECTION INPUT ;
  USE SIGNAL ;
  PORT
   LAYER M6 ;
   RECT 43.008000 74.864000 43.200000 74.896000 ;
  END
 END po0[293]
 PIN po0[294]
  DIRECTION INPUT ;
  USE SIGNAL ;
  PORT
   LAYER M4 ;
   RECT 43.008000 75.372000 43.200000 75.396000 ;
  END
 END po0[294]
 PIN po0[295]
  DIRECTION INPUT ;
  USE SIGNAL ;
  PORT
   LAYER M6 ;
   RECT 43.008000 76.080000 43.200000 76.112000 ;
  END
 END po0[295]
 PIN po0[296]
  DIRECTION INPUT ;
  USE SIGNAL ;
  PORT
   LAYER M4 ;
   RECT 43.008000 75.708000 43.200000 75.732000 ;
  END
 END po0[296]
 PIN po0[297]
  DIRECTION INPUT ;
  USE SIGNAL ;
  PORT
   LAYER M6 ;
   RECT 43.008000 76.336000 43.200000 76.368000 ;
  END
 END po0[297]
 PIN po0[298]
  DIRECTION INPUT ;
  USE SIGNAL ;
  PORT
   LAYER M4 ;
   RECT 43.008000 76.044000 43.200000 76.068000 ;
  END
 END po0[298]
 PIN po0[299]
  DIRECTION INPUT ;
  USE SIGNAL ;
  PORT
   LAYER M6 ;
   RECT 43.008000 76.592000 43.200000 76.624000 ;
  END
 END po0[299]
 PIN po0[300]
  DIRECTION INPUT ;
  USE SIGNAL ;
  PORT
   LAYER M4 ;
   RECT 43.008000 76.380000 43.200000 76.404000 ;
  END
 END po0[300]
 PIN po0[301]
  DIRECTION INPUT ;
  USE SIGNAL ;
  PORT
   LAYER M6 ;
   RECT 43.008000 76.848000 43.200000 76.880000 ;
  END
 END po0[301]
 PIN po0[302]
  DIRECTION INPUT ;
  USE SIGNAL ;
  PORT
   LAYER M4 ;
   RECT 43.008000 76.668000 43.200000 76.692000 ;
  END
 END po0[302]
 PIN po0[303]
  DIRECTION INPUT ;
  USE SIGNAL ;
  PORT
   LAYER M6 ;
   RECT 43.008000 77.104000 43.200000 77.136000 ;
  END
 END po0[303]
 PIN po0[304]
  DIRECTION INPUT ;
  USE SIGNAL ;
  PORT
   LAYER M4 ;
   RECT 43.008000 77.004000 43.200000 77.028000 ;
  END
 END po0[304]
 PIN po0[305]
  DIRECTION INPUT ;
  USE SIGNAL ;
  PORT
   LAYER M6 ;
   RECT 43.008000 77.360000 43.200000 77.392000 ;
  END
 END po0[305]
 PIN po0[306]
  DIRECTION INPUT ;
  USE SIGNAL ;
  PORT
   LAYER M4 ;
   RECT 43.008000 77.340000 43.200000 77.364000 ;
  END
 END po0[306]
 PIN po0[307]
  DIRECTION INPUT ;
  USE SIGNAL ;
  PORT
   LAYER M6 ;
   RECT 43.008000 77.616000 43.200000 77.648000 ;
  END
 END po0[307]
 PIN po0[308]
  DIRECTION INPUT ;
  USE SIGNAL ;
  PORT
   LAYER M4 ;
   RECT 43.008000 77.676000 43.200000 77.700000 ;
  END
 END po0[308]
 PIN po0[309]
  DIRECTION INPUT ;
  USE SIGNAL ;
  PORT
   LAYER M6 ;
   RECT 43.008000 77.872000 43.200000 77.904000 ;
  END
 END po0[309]
 PIN po0[310]
  DIRECTION INPUT ;
  USE SIGNAL ;
  PORT
   LAYER M4 ;
   RECT 43.008000 78.012000 43.200000 78.036000 ;
  END
 END po0[310]
 PIN po0[311]
  DIRECTION INPUT ;
  USE SIGNAL ;
  PORT
   LAYER M6 ;
   RECT 43.008000 78.128000 43.200000 78.160000 ;
  END
 END po0[311]
 PIN po0[312]
  DIRECTION INPUT ;
  USE SIGNAL ;
  PORT
   LAYER M4 ;
   RECT 43.008000 78.348000 43.200000 78.372000 ;
  END
 END po0[312]
 PIN po0[313]
  DIRECTION INPUT ;
  USE SIGNAL ;
  PORT
   LAYER M6 ;
   RECT 43.008000 78.384000 43.200000 78.416000 ;
  END
 END po0[313]
 PIN po0[314]
  DIRECTION INPUT ;
  USE SIGNAL ;
  PORT
   LAYER M4 ;
   RECT 43.008000 78.684000 43.200000 78.708000 ;
  END
 END po0[314]
 PIN po0[315]
  DIRECTION INPUT ;
  USE SIGNAL ;
  PORT
   LAYER M6 ;
   RECT 43.008000 78.640000 43.200000 78.672000 ;
  END
 END po0[315]
 PIN po0[316]
  DIRECTION INPUT ;
  USE SIGNAL ;
  PORT
   LAYER M4 ;
   RECT 43.008000 79.020000 43.200000 79.044000 ;
  END
 END po0[316]
 PIN po0[317]
  DIRECTION INPUT ;
  USE SIGNAL ;
  PORT
   LAYER M6 ;
   RECT 43.008000 78.896000 43.200000 78.928000 ;
  END
 END po0[317]
 PIN po0[318]
  DIRECTION INPUT ;
  USE SIGNAL ;
  PORT
   LAYER M4 ;
   RECT 43.008000 79.356000 43.200000 79.380000 ;
  END
 END po0[318]
 PIN po0[319]
  DIRECTION INPUT ;
  USE SIGNAL ;
  PORT
   LAYER M6 ;
   RECT 43.008000 79.152000 43.200000 79.184000 ;
  END
 END po0[319]
 PIN po0[320]
  DIRECTION INPUT ;
  USE SIGNAL ;
  PORT
   LAYER M4 ;
   RECT 43.008000 79.692000 43.200000 79.716000 ;
  END
 END po0[320]
 PIN po0[321]
  DIRECTION INPUT ;
  USE SIGNAL ;
  PORT
   LAYER M6 ;
   RECT 43.008000 79.408000 43.200000 79.440000 ;
  END
 END po0[321]
 PIN po0[322]
  DIRECTION INPUT ;
  USE SIGNAL ;
  PORT
   LAYER M4 ;
   RECT 43.008000 80.028000 43.200000 80.052000 ;
  END
 END po0[322]
 PIN po0[323]
  DIRECTION INPUT ;
  USE SIGNAL ;
  PORT
   LAYER M6 ;
   RECT 43.008000 80.624000 43.200000 80.656000 ;
  END
 END po0[323]
 PIN po0[324]
  DIRECTION INPUT ;
  USE SIGNAL ;
  PORT
   LAYER M4 ;
   RECT 43.008000 80.364000 43.200000 80.388000 ;
  END
 END po0[324]
 PIN po0[325]
  DIRECTION INPUT ;
  USE SIGNAL ;
  PORT
   LAYER M6 ;
   RECT 43.008000 80.880000 43.200000 80.912000 ;
  END
 END po0[325]
 PIN po0[326]
  DIRECTION INPUT ;
  USE SIGNAL ;
  PORT
   LAYER M4 ;
   RECT 43.008000 80.700000 43.200000 80.724000 ;
  END
 END po0[326]
 PIN po0[327]
  DIRECTION INPUT ;
  USE SIGNAL ;
  PORT
   LAYER M6 ;
   RECT 43.008000 81.136000 43.200000 81.168000 ;
  END
 END po0[327]
 PIN pi0[0]
  DIRECTION OUTPUT ;
  USE SIGNAL ;
  PORT
   LAYER M4 ;
   RECT 43.008000 345.228000 43.200000 345.252000 ;
  END
 END pi0[0]
 PIN pi0[1]
  DIRECTION OUTPUT ;
  USE SIGNAL ;
  PORT
   LAYER M6 ;
   RECT 43.008000 345.328000 43.200000 345.360000 ;
  END
 END pi0[1]
 PIN pi0[2]
  DIRECTION OUTPUT ;
  USE SIGNAL ;
  PORT
   LAYER M4 ;
   RECT 43.008000 345.516000 43.200000 345.540000 ;
  END
 END pi0[2]
 PIN pi0[3]
  DIRECTION OUTPUT ;
  USE SIGNAL ;
  PORT
   LAYER M6 ;
   RECT 43.008000 345.648000 43.200000 345.680000 ;
  END
 END pi0[3]
 PIN pi0[4]
  DIRECTION OUTPUT ;
  USE SIGNAL ;
  PORT
   LAYER M4 ;
   RECT 43.008000 345.852000 43.200000 345.876000 ;
  END
 END pi0[4]
 PIN pi0[5]
  DIRECTION OUTPUT ;
  USE SIGNAL ;
  PORT
   LAYER M6 ;
   RECT 43.008000 346.032000 43.200000 346.064000 ;
  END
 END pi0[5]
 PIN pi0[6]
  DIRECTION OUTPUT ;
  USE SIGNAL ;
  PORT
   LAYER M4 ;
   RECT 43.008000 346.188000 43.200000 346.212000 ;
  END
 END pi0[6]
 PIN pi0[7]
  DIRECTION OUTPUT ;
  USE SIGNAL ;
  PORT
   LAYER M6 ;
   RECT 43.008000 346.352000 43.200000 346.384000 ;
  END
 END pi0[7]
 PIN pi0[8]
  DIRECTION OUTPUT ;
  USE SIGNAL ;
  PORT
   LAYER M4 ;
   RECT 43.008000 346.476000 43.200000 346.500000 ;
  END
 END pi0[8]
 PIN pi0[9]
  DIRECTION OUTPUT ;
  USE SIGNAL ;
  PORT
   LAYER M6 ;
   RECT 43.008000 346.736000 43.200000 346.768000 ;
  END
 END pi0[9]
 PIN pi0[10]
  DIRECTION OUTPUT ;
  USE SIGNAL ;
  PORT
   LAYER M4 ;
   RECT 43.008000 346.812000 43.200000 346.836000 ;
  END
 END pi0[10]
 PIN pi0[11]
  DIRECTION OUTPUT ;
  USE SIGNAL ;
  PORT
   LAYER M6 ;
   RECT 43.008000 347.120000 43.200000 347.152000 ;
  END
 END pi0[11]
 PIN pi0[12]
  DIRECTION OUTPUT ;
  USE SIGNAL ;
  PORT
   LAYER M4 ;
   RECT 43.008000 372.108000 43.200000 372.132000 ;
  END
 END pi0[12]
 PIN pi0[13]
  DIRECTION OUTPUT ;
  USE SIGNAL ;
  PORT
   LAYER M6 ;
   RECT 43.008000 372.144000 43.200000 372.176000 ;
  END
 END pi0[13]
 PIN pi0[14]
  DIRECTION OUTPUT ;
  USE SIGNAL ;
  PORT
   LAYER M4 ;
   RECT 43.008000 372.444000 43.200000 372.468000 ;
  END
 END pi0[14]
 PIN pi0[15]
  DIRECTION OUTPUT ;
  USE SIGNAL ;
  PORT
   LAYER M6 ;
   RECT 43.008000 372.464000 43.200000 372.496000 ;
  END
 END pi0[15]
 PIN pi0[16]
  DIRECTION OUTPUT ;
  USE SIGNAL ;
  PORT
   LAYER M4 ;
   RECT 43.008000 372.780000 43.200000 372.804000 ;
  END
 END pi0[16]
 PIN pi0[17]
  DIRECTION OUTPUT ;
  USE SIGNAL ;
  PORT
   LAYER M6 ;
   RECT 43.008000 372.784000 43.200000 372.816000 ;
  END
 END pi0[17]
 PIN pi0[18]
  DIRECTION OUTPUT ;
  USE SIGNAL ;
  PORT
   LAYER M4 ;
   RECT 43.008000 373.116000 43.200000 373.140000 ;
  END
 END pi0[18]
 PIN pi0[19]
  DIRECTION OUTPUT ;
  USE SIGNAL ;
  PORT
   LAYER M6 ;
   RECT 43.008000 373.104000 43.200000 373.136000 ;
  END
 END pi0[19]
 PIN pi0[20]
  DIRECTION OUTPUT ;
  USE SIGNAL ;
  PORT
   LAYER M4 ;
   RECT 43.008000 373.452000 43.200000 373.476000 ;
  END
 END pi0[20]
 PIN pi0[21]
  DIRECTION OUTPUT ;
  USE SIGNAL ;
  PORT
   LAYER M6 ;
   RECT 43.008000 373.168000 43.200000 373.200000 ;
  END
 END pi0[21]
 PIN pi0[22]
  DIRECTION OUTPUT ;
  USE SIGNAL ;
  PORT
   LAYER M4 ;
   RECT 43.008000 373.788000 43.200000 373.812000 ;
  END
 END pi0[22]
 PIN pi0[23]
  DIRECTION OUTPUT ;
  USE SIGNAL ;
  PORT
   LAYER M6 ;
   RECT 43.008000 374.192000 43.200000 374.224000 ;
  END
 END pi0[23]
 PIN pi0[24]
  DIRECTION OUTPUT ;
  USE SIGNAL ;
  PORT
   LAYER M4 ;
   RECT 43.008000 374.124000 43.200000 374.148000 ;
  END
 END pi0[24]
 PIN pi0[25]
  DIRECTION OUTPUT ;
  USE SIGNAL ;
  PORT
   LAYER M6 ;
   RECT 43.008000 374.256000 43.200000 374.288000 ;
  END
 END pi0[25]
 PIN pi0[26]
  DIRECTION OUTPUT ;
  USE SIGNAL ;
  PORT
   LAYER M4 ;
   RECT 43.008000 374.460000 43.200000 374.484000 ;
  END
 END pi0[26]
 PIN pi0[27]
  DIRECTION OUTPUT ;
  USE SIGNAL ;
  PORT
   LAYER M6 ;
   RECT 43.008000 374.448000 43.200000 374.480000 ;
  END
 END pi0[27]
 PIN pi0[28]
  DIRECTION OUTPUT ;
  USE SIGNAL ;
  PORT
   LAYER M4 ;
   RECT 43.008000 374.796000 43.200000 374.820000 ;
  END
 END pi0[28]
 PIN pi0[29]
  DIRECTION OUTPUT ;
  USE SIGNAL ;
  PORT
   LAYER M6 ;
   RECT 43.008000 374.768000 43.200000 374.800000 ;
  END
 END pi0[29]
 PIN pi0[30]
  DIRECTION OUTPUT ;
  USE SIGNAL ;
  PORT
   LAYER M4 ;
   RECT 43.008000 375.132000 43.200000 375.156000 ;
  END
 END pi0[30]
 PIN pi0[31]
  DIRECTION OUTPUT ;
  USE SIGNAL ;
  PORT
   LAYER M6 ;
   RECT 43.008000 375.088000 43.200000 375.120000 ;
  END
 END pi0[31]
 PIN pi0[32]
  DIRECTION OUTPUT ;
  USE SIGNAL ;
  PORT
   LAYER M4 ;
   RECT 43.008000 375.468000 43.200000 375.492000 ;
  END
 END pi0[32]
 PIN pi0[33]
  DIRECTION OUTPUT ;
  USE SIGNAL ;
  PORT
   LAYER M6 ;
   RECT 43.008000 375.472000 43.200000 375.504000 ;
  END
 END pi0[33]
 PIN pi0[34]
  DIRECTION OUTPUT ;
  USE SIGNAL ;
  PORT
   LAYER M4 ;
   RECT 43.008000 375.804000 43.200000 375.828000 ;
  END
 END pi0[34]
 PIN pi0[35]
  DIRECTION OUTPUT ;
  USE SIGNAL ;
  PORT
   LAYER M6 ;
   RECT 43.008000 375.792000 43.200000 375.824000 ;
  END
 END pi0[35]
 PIN pi0[36]
  DIRECTION OUTPUT ;
  USE SIGNAL ;
  PORT
   LAYER M4 ;
   RECT 43.008000 376.140000 43.200000 376.164000 ;
  END
 END pi0[36]
 PIN pi0[37]
  DIRECTION OUTPUT ;
  USE SIGNAL ;
  PORT
   LAYER M6 ;
   RECT 43.008000 376.112000 43.200000 376.144000 ;
  END
 END pi0[37]
 PIN pi0[38]
  DIRECTION OUTPUT ;
  USE SIGNAL ;
  PORT
   LAYER M4 ;
   RECT 43.008000 376.476000 43.200000 376.500000 ;
  END
 END pi0[38]
 PIN pi0[39]
  DIRECTION OUTPUT ;
  USE SIGNAL ;
  PORT
   LAYER M6 ;
   RECT 43.008000 376.432000 43.200000 376.464000 ;
  END
 END pi0[39]
 PIN pi0[40]
  DIRECTION OUTPUT ;
  USE SIGNAL ;
  PORT
   LAYER M4 ;
   RECT 43.008000 376.764000 43.200000 376.788000 ;
  END
 END pi0[40]
 PIN pi0[41]
  DIRECTION OUTPUT ;
  USE SIGNAL ;
  PORT
   LAYER M6 ;
   RECT 43.008000 376.752000 43.200000 376.784000 ;
  END
 END pi0[41]
 PIN pi0[42]
  DIRECTION OUTPUT ;
  USE SIGNAL ;
  PORT
   LAYER M4 ;
   RECT 43.008000 377.100000 43.200000 377.124000 ;
  END
 END pi0[42]
 PIN pi0[43]
  DIRECTION OUTPUT ;
  USE SIGNAL ;
  PORT
   LAYER M6 ;
   RECT 43.008000 377.136000 43.200000 377.168000 ;
  END
 END pi0[43]
 PIN pi0[44]
  DIRECTION OUTPUT ;
  USE SIGNAL ;
  PORT
   LAYER M4 ;
   RECT 43.008000 377.436000 43.200000 377.460000 ;
  END
 END pi0[44]
 PIN pi0[45]
  DIRECTION OUTPUT ;
  USE SIGNAL ;
  PORT
   LAYER M6 ;
   RECT 43.008000 377.456000 43.200000 377.488000 ;
  END
 END pi0[45]
 PIN pi0[46]
  DIRECTION OUTPUT ;
  USE SIGNAL ;
  PORT
   LAYER M4 ;
   RECT 43.008000 377.772000 43.200000 377.796000 ;
  END
 END pi0[46]
 PIN pi0[47]
  DIRECTION OUTPUT ;
  USE SIGNAL ;
  PORT
   LAYER M6 ;
   RECT 43.008000 378.480000 43.200000 378.512000 ;
  END
 END pi0[47]
 PIN pi0[48]
  DIRECTION OUTPUT ;
  USE SIGNAL ;
  PORT
   LAYER M4 ;
   RECT 43.008000 378.108000 43.200000 378.132000 ;
  END
 END pi0[48]
 PIN pi0[49]
  DIRECTION OUTPUT ;
  USE SIGNAL ;
  PORT
   LAYER M6 ;
   RECT 43.008000 378.544000 43.200000 378.576000 ;
  END
 END pi0[49]
 PIN pi0[50]
  DIRECTION OUTPUT ;
  USE SIGNAL ;
  PORT
   LAYER M4 ;
   RECT 43.008000 378.444000 43.200000 378.468000 ;
  END
 END pi0[50]
 PIN pi0[51]
  DIRECTION OUTPUT ;
  USE SIGNAL ;
  PORT
   LAYER M6 ;
   RECT 43.008000 378.608000 43.200000 378.640000 ;
  END
 END pi0[51]
 PIN pi0[52]
  DIRECTION OUTPUT ;
  USE SIGNAL ;
  PORT
   LAYER M4 ;
   RECT 43.008000 378.780000 43.200000 378.804000 ;
  END
 END pi0[52]
 PIN pi0[53]
  DIRECTION OUTPUT ;
  USE SIGNAL ;
  PORT
   LAYER M6 ;
   RECT 43.008000 378.800000 43.200000 378.832000 ;
  END
 END pi0[53]
 PIN pi0[54]
  DIRECTION OUTPUT ;
  USE SIGNAL ;
  PORT
   LAYER M4 ;
   RECT 43.008000 379.116000 43.200000 379.140000 ;
  END
 END pi0[54]
 PIN pi0[55]
  DIRECTION OUTPUT ;
  USE SIGNAL ;
  PORT
   LAYER M6 ;
   RECT 43.008000 379.120000 43.200000 379.152000 ;
  END
 END pi0[55]
 PIN pi0[56]
  DIRECTION OUTPUT ;
  USE SIGNAL ;
  PORT
   LAYER M4 ;
   RECT 43.008000 379.452000 43.200000 379.476000 ;
  END
 END pi0[56]
 PIN pi0[57]
  DIRECTION OUTPUT ;
  USE SIGNAL ;
  PORT
   LAYER M6 ;
   RECT 43.008000 379.440000 43.200000 379.472000 ;
  END
 END pi0[57]
 PIN pi0[58]
  DIRECTION OUTPUT ;
  USE SIGNAL ;
  PORT
   LAYER M4 ;
   RECT 43.008000 379.788000 43.200000 379.812000 ;
  END
 END pi0[58]
 PIN pi0[59]
  DIRECTION OUTPUT ;
  USE SIGNAL ;
  PORT
   LAYER M6 ;
   RECT 43.008000 379.760000 43.200000 379.792000 ;
  END
 END pi0[59]
 PIN pi0[60]
  DIRECTION OUTPUT ;
  USE SIGNAL ;
  PORT
   LAYER M4 ;
   RECT 43.008000 380.124000 43.200000 380.148000 ;
  END
 END pi0[60]
 PIN pi0[61]
  DIRECTION OUTPUT ;
  USE SIGNAL ;
  PORT
   LAYER M6 ;
   RECT 43.008000 380.144000 43.200000 380.176000 ;
  END
 END pi0[61]
 PIN pi0[62]
  DIRECTION OUTPUT ;
  USE SIGNAL ;
  PORT
   LAYER M4 ;
   RECT 43.008000 380.460000 43.200000 380.484000 ;
  END
 END pi0[62]
 PIN pi0[63]
  DIRECTION OUTPUT ;
  USE SIGNAL ;
  PORT
   LAYER M6 ;
   RECT 43.008000 380.464000 43.200000 380.496000 ;
  END
 END pi0[63]
 PIN pi0[64]
  DIRECTION OUTPUT ;
  USE SIGNAL ;
  PORT
   LAYER M4 ;
   RECT 43.008000 380.796000 43.200000 380.820000 ;
  END
 END pi0[64]
 PIN pi0[65]
  DIRECTION OUTPUT ;
  USE SIGNAL ;
  PORT
   LAYER M6 ;
   RECT 43.008000 380.784000 43.200000 380.816000 ;
  END
 END pi0[65]
 PIN pi0[66]
  DIRECTION OUTPUT ;
  USE SIGNAL ;
  PORT
   LAYER M4 ;
   RECT 43.008000 381.132000 43.200000 381.156000 ;
  END
 END pi0[66]
 PIN pi0[67]
  DIRECTION OUTPUT ;
  USE SIGNAL ;
  PORT
   LAYER M6 ;
   RECT 43.008000 381.104000 43.200000 381.136000 ;
  END
 END pi0[67]
 PIN pi0[68]
  DIRECTION OUTPUT ;
  USE SIGNAL ;
  PORT
   LAYER M4 ;
   RECT 43.008000 381.468000 43.200000 381.492000 ;
  END
 END pi0[68]
 PIN pi0[69]
  DIRECTION OUTPUT ;
  USE SIGNAL ;
  PORT
   LAYER M6 ;
   RECT 43.008000 381.424000 43.200000 381.456000 ;
  END
 END pi0[69]
 PIN pi0[70]
  DIRECTION OUTPUT ;
  USE SIGNAL ;
  PORT
   LAYER M4 ;
   RECT 43.008000 381.804000 43.200000 381.828000 ;
  END
 END pi0[70]
 PIN pi0[71]
  DIRECTION OUTPUT ;
  USE SIGNAL ;
  PORT
   LAYER M6 ;
   RECT 43.008000 381.808000 43.200000 381.840000 ;
  END
 END pi0[71]
 PIN pi0[72]
  DIRECTION OUTPUT ;
  USE SIGNAL ;
  PORT
   LAYER M4 ;
   RECT 43.008000 382.140000 43.200000 382.164000 ;
  END
 END pi0[72]
 PIN pi0[73]
  DIRECTION OUTPUT ;
  USE SIGNAL ;
  PORT
   LAYER M6 ;
   RECT 43.008000 382.832000 43.200000 382.864000 ;
  END
 END pi0[73]
 PIN pi0[74]
  DIRECTION OUTPUT ;
  USE SIGNAL ;
  PORT
   LAYER M4 ;
   RECT 43.008000 382.476000 43.200000 382.500000 ;
  END
 END pi0[74]
 PIN pi0[75]
  DIRECTION OUTPUT ;
  USE SIGNAL ;
  PORT
   LAYER M6 ;
   RECT 43.008000 382.896000 43.200000 382.928000 ;
  END
 END pi0[75]
 PIN pi0[76]
  DIRECTION OUTPUT ;
  USE SIGNAL ;
  PORT
   LAYER M4 ;
   RECT 43.008000 382.764000 43.200000 382.788000 ;
  END
 END pi0[76]
 PIN pi0[77]
  DIRECTION OUTPUT ;
  USE SIGNAL ;
  PORT
   LAYER M6 ;
   RECT 43.008000 382.960000 43.200000 382.992000 ;
  END
 END pi0[77]
 PIN pi0[78]
  DIRECTION OUTPUT ;
  USE SIGNAL ;
  PORT
   LAYER M4 ;
   RECT 43.008000 383.100000 43.200000 383.124000 ;
  END
 END pi0[78]
 PIN pi0[79]
  DIRECTION OUTPUT ;
  USE SIGNAL ;
  PORT
   LAYER M6 ;
   RECT 43.008000 383.088000 43.200000 383.120000 ;
  END
 END pi0[79]
 PIN pi0[80]
  DIRECTION OUTPUT ;
  USE SIGNAL ;
  PORT
   LAYER M4 ;
   RECT 43.008000 383.436000 43.200000 383.460000 ;
  END
 END pi0[80]
 PIN pi0[81]
  DIRECTION OUTPUT ;
  USE SIGNAL ;
  PORT
   LAYER M6 ;
   RECT 43.008000 383.472000 43.200000 383.504000 ;
  END
 END pi0[81]
 PIN pi0[82]
  DIRECTION OUTPUT ;
  USE SIGNAL ;
  PORT
   LAYER M4 ;
   RECT 43.008000 383.772000 43.200000 383.796000 ;
  END
 END pi0[82]
 PIN pi0[83]
  DIRECTION OUTPUT ;
  USE SIGNAL ;
  PORT
   LAYER M6 ;
   RECT 43.008000 383.792000 43.200000 383.824000 ;
  END
 END pi0[83]
 PIN pi0[84]
  DIRECTION OUTPUT ;
  USE SIGNAL ;
  PORT
   LAYER M4 ;
   RECT 43.008000 384.108000 43.200000 384.132000 ;
  END
 END pi0[84]
 PIN pi0[85]
  DIRECTION OUTPUT ;
  USE SIGNAL ;
  PORT
   LAYER M6 ;
   RECT 43.008000 384.112000 43.200000 384.144000 ;
  END
 END pi0[85]
 PIN pi0[86]
  DIRECTION OUTPUT ;
  USE SIGNAL ;
  PORT
   LAYER M4 ;
   RECT 43.008000 384.444000 43.200000 384.468000 ;
  END
 END pi0[86]
 PIN pi0[87]
  DIRECTION OUTPUT ;
  USE SIGNAL ;
  PORT
   LAYER M6 ;
   RECT 43.008000 384.432000 43.200000 384.464000 ;
  END
 END pi0[87]
 PIN pi0[88]
  DIRECTION OUTPUT ;
  USE SIGNAL ;
  PORT
   LAYER M4 ;
   RECT 43.008000 384.780000 43.200000 384.804000 ;
  END
 END pi0[88]
 PIN pi0[89]
  DIRECTION OUTPUT ;
  USE SIGNAL ;
  PORT
   LAYER M6 ;
   RECT 43.008000 384.752000 43.200000 384.784000 ;
  END
 END pi0[89]
 PIN pi0[90]
  DIRECTION OUTPUT ;
  USE SIGNAL ;
  PORT
   LAYER M4 ;
   RECT 43.008000 385.116000 43.200000 385.140000 ;
  END
 END pi0[90]
 PIN pi0[91]
  DIRECTION OUTPUT ;
  USE SIGNAL ;
  PORT
   LAYER M6 ;
   RECT 43.008000 385.136000 43.200000 385.168000 ;
  END
 END pi0[91]
 PIN pi0[92]
  DIRECTION OUTPUT ;
  USE SIGNAL ;
  PORT
   LAYER M4 ;
   RECT 43.008000 385.452000 43.200000 385.476000 ;
  END
 END pi0[92]
 PIN pi0[93]
  DIRECTION OUTPUT ;
  USE SIGNAL ;
  PORT
   LAYER M6 ;
   RECT 43.008000 385.456000 43.200000 385.488000 ;
  END
 END pi0[93]
 PIN pi0[94]
  DIRECTION OUTPUT ;
  USE SIGNAL ;
  PORT
   LAYER M4 ;
   RECT 43.008000 385.788000 43.200000 385.812000 ;
  END
 END pi0[94]
 PIN pi0[95]
  DIRECTION OUTPUT ;
  USE SIGNAL ;
  PORT
   LAYER M6 ;
   RECT 43.008000 385.776000 43.200000 385.808000 ;
  END
 END pi0[95]
 PIN pi0[96]
  DIRECTION OUTPUT ;
  USE SIGNAL ;
  PORT
   LAYER M4 ;
   RECT 43.008000 386.124000 43.200000 386.148000 ;
  END
 END pi0[96]
 PIN pi0[97]
  DIRECTION OUTPUT ;
  USE SIGNAL ;
  PORT
   LAYER M6 ;
   RECT 43.008000 386.096000 43.200000 386.128000 ;
  END
 END pi0[97]
 PIN pi0[98]
  DIRECTION OUTPUT ;
  USE SIGNAL ;
  PORT
   LAYER M4 ;
   RECT 43.008000 386.460000 43.200000 386.484000 ;
  END
 END pi0[98]
 PIN pi0[99]
  DIRECTION OUTPUT ;
  USE SIGNAL ;
  PORT
   LAYER M6 ;
   RECT 43.008000 387.120000 43.200000 387.152000 ;
  END
 END pi0[99]
 PIN pi0[100]
  DIRECTION OUTPUT ;
  USE SIGNAL ;
  PORT
   LAYER M4 ;
   RECT 43.008000 386.796000 43.200000 386.820000 ;
  END
 END pi0[100]
 PIN pi0[101]
  DIRECTION OUTPUT ;
  USE SIGNAL ;
  PORT
   LAYER M6 ;
   RECT 43.008000 387.184000 43.200000 387.216000 ;
  END
 END pi0[101]
 PIN pi0[102]
  DIRECTION OUTPUT ;
  USE SIGNAL ;
  PORT
   LAYER M4 ;
   RECT 43.008000 387.132000 43.200000 387.156000 ;
  END
 END pi0[102]
 PIN pi0[103]
  DIRECTION OUTPUT ;
  USE SIGNAL ;
  PORT
   LAYER M6 ;
   RECT 43.008000 387.248000 43.200000 387.280000 ;
  END
 END pi0[103]
 PIN pi0[104]
  DIRECTION OUTPUT ;
  USE SIGNAL ;
  PORT
   LAYER M4 ;
   RECT 43.008000 387.468000 43.200000 387.492000 ;
  END
 END pi0[104]
 PIN pi0[105]
  DIRECTION OUTPUT ;
  USE SIGNAL ;
  PORT
   LAYER M6 ;
   RECT 43.008000 387.440000 43.200000 387.472000 ;
  END
 END pi0[105]
 PIN pi0[106]
  DIRECTION OUTPUT ;
  USE SIGNAL ;
  PORT
   LAYER M4 ;
   RECT 43.008000 387.804000 43.200000 387.828000 ;
  END
 END pi0[106]
 PIN pi0[107]
  DIRECTION OUTPUT ;
  USE SIGNAL ;
  PORT
   LAYER M6 ;
   RECT 43.008000 387.760000 43.200000 387.792000 ;
  END
 END pi0[107]
 PIN pi0[108]
  DIRECTION OUTPUT ;
  USE SIGNAL ;
  PORT
   LAYER M4 ;
   RECT 43.008000 388.140000 43.200000 388.164000 ;
  END
 END pi0[108]
 PIN pi0[109]
  DIRECTION OUTPUT ;
  USE SIGNAL ;
  PORT
   LAYER M6 ;
   RECT 43.008000 388.144000 43.200000 388.176000 ;
  END
 END pi0[109]
 PIN pi0[110]
  DIRECTION OUTPUT ;
  USE SIGNAL ;
  PORT
   LAYER M4 ;
   RECT 43.008000 388.476000 43.200000 388.500000 ;
  END
 END pi0[110]
 PIN pi0[111]
  DIRECTION OUTPUT ;
  USE SIGNAL ;
  PORT
   LAYER M6 ;
   RECT 43.008000 388.464000 43.200000 388.496000 ;
  END
 END pi0[111]
 PIN pi0[112]
  DIRECTION OUTPUT ;
  USE SIGNAL ;
  PORT
   LAYER M4 ;
   RECT 43.008000 388.764000 43.200000 388.788000 ;
  END
 END pi0[112]
 PIN pi0[113]
  DIRECTION OUTPUT ;
  USE SIGNAL ;
  PORT
   LAYER M6 ;
   RECT 43.008000 388.784000 43.200000 388.816000 ;
  END
 END pi0[113]
 PIN pi0[114]
  DIRECTION OUTPUT ;
  USE SIGNAL ;
  PORT
   LAYER M4 ;
   RECT 43.008000 389.100000 43.200000 389.124000 ;
  END
 END pi0[114]
 PIN pi0[115]
  DIRECTION OUTPUT ;
  USE SIGNAL ;
  PORT
   LAYER M6 ;
   RECT 43.008000 389.104000 43.200000 389.136000 ;
  END
 END pi0[115]
 PIN pi0[116]
  DIRECTION OUTPUT ;
  USE SIGNAL ;
  PORT
   LAYER M4 ;
   RECT 43.008000 389.436000 43.200000 389.460000 ;
  END
 END pi0[116]
 PIN pi0[117]
  DIRECTION OUTPUT ;
  USE SIGNAL ;
  PORT
   LAYER M6 ;
   RECT 43.008000 389.424000 43.200000 389.456000 ;
  END
 END pi0[117]
 PIN pi0[118]
  DIRECTION OUTPUT ;
  USE SIGNAL ;
  PORT
   LAYER M4 ;
   RECT 43.008000 389.772000 43.200000 389.796000 ;
  END
 END pi0[118]
 PIN pi0[119]
  DIRECTION OUTPUT ;
  USE SIGNAL ;
  PORT
   LAYER M6 ;
   RECT 43.008000 389.808000 43.200000 389.840000 ;
  END
 END pi0[119]
 PIN pi0[120]
  DIRECTION OUTPUT ;
  USE SIGNAL ;
  PORT
   LAYER M4 ;
   RECT 43.008000 390.108000 43.200000 390.132000 ;
  END
 END pi0[120]
 PIN pi0[121]
  DIRECTION OUTPUT ;
  USE SIGNAL ;
  PORT
   LAYER M6 ;
   RECT 43.008000 390.128000 43.200000 390.160000 ;
  END
 END pi0[121]
 PIN pi0[122]
  DIRECTION OUTPUT ;
  USE SIGNAL ;
  PORT
   LAYER M4 ;
   RECT 43.008000 390.444000 43.200000 390.468000 ;
  END
 END pi0[122]
 PIN pi0[123]
  DIRECTION OUTPUT ;
  USE SIGNAL ;
  PORT
   LAYER M6 ;
   RECT 43.008000 390.448000 43.200000 390.480000 ;
  END
 END pi0[123]
 PIN pi0[124]
  DIRECTION OUTPUT ;
  USE SIGNAL ;
  PORT
   LAYER M4 ;
   RECT 43.008000 390.780000 43.200000 390.804000 ;
  END
 END pi0[124]
 PIN pi0[125]
  DIRECTION OUTPUT ;
  USE SIGNAL ;
  PORT
   LAYER M6 ;
   RECT 43.008000 391.472000 43.200000 391.504000 ;
  END
 END pi0[125]
 PIN pi0[126]
  DIRECTION OUTPUT ;
  USE SIGNAL ;
  PORT
   LAYER M4 ;
   RECT 43.008000 391.116000 43.200000 391.140000 ;
  END
 END pi0[126]
 PIN pi0[127]
  DIRECTION OUTPUT ;
  USE SIGNAL ;
  PORT
   LAYER M6 ;
   RECT 43.008000 391.536000 43.200000 391.568000 ;
  END
 END pi0[127]
 PIN pi0[128]
  DIRECTION OUTPUT ;
  USE SIGNAL ;
  PORT
   LAYER M4 ;
   RECT 43.008000 391.452000 43.200000 391.476000 ;
  END
 END pi0[128]
 PIN pi0[129]
  DIRECTION OUTPUT ;
  USE SIGNAL ;
  PORT
   LAYER M6 ;
   RECT 43.008000 391.600000 43.200000 391.632000 ;
  END
 END pi0[129]
 PIN pi0[130]
  DIRECTION OUTPUT ;
  USE SIGNAL ;
  PORT
   LAYER M4 ;
   RECT 43.008000 391.788000 43.200000 391.812000 ;
  END
 END pi0[130]
 PIN pi0[131]
  DIRECTION OUTPUT ;
  USE SIGNAL ;
  PORT
   LAYER M6 ;
   RECT 43.008000 391.792000 43.200000 391.824000 ;
  END
 END pi0[131]
 PIN pi0[132]
  DIRECTION OUTPUT ;
  USE SIGNAL ;
  PORT
   LAYER M4 ;
   RECT 43.008000 392.124000 43.200000 392.148000 ;
  END
 END pi0[132]
 PIN pi0[133]
  DIRECTION OUTPUT ;
  USE SIGNAL ;
  PORT
   LAYER M6 ;
   RECT 43.008000 392.112000 43.200000 392.144000 ;
  END
 END pi0[133]
 PIN pi0[134]
  DIRECTION OUTPUT ;
  USE SIGNAL ;
  PORT
   LAYER M4 ;
   RECT 43.008000 392.460000 43.200000 392.484000 ;
  END
 END pi0[134]
 PIN pi0[135]
  DIRECTION OUTPUT ;
  USE SIGNAL ;
  PORT
   LAYER M6 ;
   RECT 43.008000 392.432000 43.200000 392.464000 ;
  END
 END pi0[135]
 PIN pi0[136]
  DIRECTION OUTPUT ;
  USE SIGNAL ;
  PORT
   LAYER M4 ;
   RECT 43.008000 392.796000 43.200000 392.820000 ;
  END
 END pi0[136]
 PIN pi0[137]
  DIRECTION OUTPUT ;
  USE SIGNAL ;
  PORT
   LAYER M6 ;
   RECT 43.008000 392.752000 43.200000 392.784000 ;
  END
 END pi0[137]
 PIN pi0[138]
  DIRECTION OUTPUT ;
  USE SIGNAL ;
  PORT
   LAYER M4 ;
   RECT 43.008000 393.132000 43.200000 393.156000 ;
  END
 END pi0[138]
 PIN pi0[139]
  DIRECTION OUTPUT ;
  USE SIGNAL ;
  PORT
   LAYER M6 ;
   RECT 43.008000 393.136000 43.200000 393.168000 ;
  END
 END pi0[139]
 PIN pi0[140]
  DIRECTION OUTPUT ;
  USE SIGNAL ;
  PORT
   LAYER M4 ;
   RECT 43.008000 393.468000 43.200000 393.492000 ;
  END
 END pi0[140]
 PIN pi0[141]
  DIRECTION OUTPUT ;
  USE SIGNAL ;
  PORT
   LAYER M6 ;
   RECT 43.008000 393.456000 43.200000 393.488000 ;
  END
 END pi0[141]
 PIN pi0[142]
  DIRECTION OUTPUT ;
  USE SIGNAL ;
  PORT
   LAYER M4 ;
   RECT 43.008000 393.804000 43.200000 393.828000 ;
  END
 END pi0[142]
 PIN pi0[143]
  DIRECTION OUTPUT ;
  USE SIGNAL ;
  PORT
   LAYER M6 ;
   RECT 43.008000 393.776000 43.200000 393.808000 ;
  END
 END pi0[143]
 PIN pi0[144]
  DIRECTION OUTPUT ;
  USE SIGNAL ;
  PORT
   LAYER M4 ;
   RECT 43.008000 394.140000 43.200000 394.164000 ;
  END
 END pi0[144]
 PIN pi0[145]
  DIRECTION OUTPUT ;
  USE SIGNAL ;
  PORT
   LAYER M6 ;
   RECT 43.008000 394.096000 43.200000 394.128000 ;
  END
 END pi0[145]
 PIN pi0[146]
  DIRECTION OUTPUT ;
  USE SIGNAL ;
  PORT
   LAYER M4 ;
   RECT 43.008000 394.476000 43.200000 394.500000 ;
  END
 END pi0[146]
 PIN pi0[147]
  DIRECTION OUTPUT ;
  USE SIGNAL ;
  PORT
   LAYER M6 ;
   RECT 43.008000 394.480000 43.200000 394.512000 ;
  END
 END pi0[147]
 PIN pi0[148]
  DIRECTION OUTPUT ;
  USE SIGNAL ;
  PORT
   LAYER M4 ;
   RECT 43.008000 394.764000 43.200000 394.788000 ;
  END
 END pi0[148]
 PIN pi0[149]
  DIRECTION OUTPUT ;
  USE SIGNAL ;
  PORT
   LAYER M6 ;
   RECT 43.008000 394.736000 43.200000 394.768000 ;
  END
 END pi0[149]
 PIN pi0[150]
  DIRECTION OUTPUT ;
  USE SIGNAL ;
  PORT
   LAYER M4 ;
   RECT 43.008000 395.100000 43.200000 395.124000 ;
  END
 END pi0[150]
 PIN pi0[151]
  DIRECTION OUTPUT ;
  USE SIGNAL ;
  PORT
   LAYER M6 ;
   RECT 43.008000 395.760000 43.200000 395.792000 ;
  END
 END pi0[151]
 PIN pi0[152]
  DIRECTION OUTPUT ;
  USE SIGNAL ;
  PORT
   LAYER M4 ;
   RECT 43.008000 395.436000 43.200000 395.460000 ;
  END
 END pi0[152]
 PIN pi0[153]
  DIRECTION OUTPUT ;
  USE SIGNAL ;
  PORT
   LAYER M6 ;
   RECT 43.008000 395.824000 43.200000 395.856000 ;
  END
 END pi0[153]
 PIN pi0[154]
  DIRECTION OUTPUT ;
  USE SIGNAL ;
  PORT
   LAYER M4 ;
   RECT 43.008000 395.772000 43.200000 395.796000 ;
  END
 END pi0[154]
 PIN pi0[155]
  DIRECTION OUTPUT ;
  USE SIGNAL ;
  PORT
   LAYER M6 ;
   RECT 43.008000 395.888000 43.200000 395.920000 ;
  END
 END pi0[155]
 PIN pi0[156]
  DIRECTION OUTPUT ;
  USE SIGNAL ;
  PORT
   LAYER M4 ;
   RECT 43.008000 396.108000 43.200000 396.132000 ;
  END
 END pi0[156]
 PIN pi0[157]
  DIRECTION OUTPUT ;
  USE SIGNAL ;
  PORT
   LAYER M6 ;
   RECT 43.008000 396.144000 43.200000 396.176000 ;
  END
 END pi0[157]
 PIN pi0[158]
  DIRECTION OUTPUT ;
  USE SIGNAL ;
  PORT
   LAYER M4 ;
   RECT 43.008000 396.444000 43.200000 396.468000 ;
  END
 END pi0[158]
 PIN pi0[159]
  DIRECTION OUTPUT ;
  USE SIGNAL ;
  PORT
   LAYER M6 ;
   RECT 43.008000 396.464000 43.200000 396.496000 ;
  END
 END pi0[159]
 PIN pi0[160]
  DIRECTION OUTPUT ;
  USE SIGNAL ;
  PORT
   LAYER M4 ;
   RECT 43.008000 396.780000 43.200000 396.804000 ;
  END
 END pi0[160]
 PIN pi0[161]
  DIRECTION OUTPUT ;
  USE SIGNAL ;
  PORT
   LAYER M6 ;
   RECT 43.008000 396.784000 43.200000 396.816000 ;
  END
 END pi0[161]
 PIN pi0[162]
  DIRECTION OUTPUT ;
  USE SIGNAL ;
  PORT
   LAYER M4 ;
   RECT 43.008000 397.116000 43.200000 397.140000 ;
  END
 END pi0[162]
 PIN pi0[163]
  DIRECTION OUTPUT ;
  USE SIGNAL ;
  PORT
   LAYER M6 ;
   RECT 43.008000 397.104000 43.200000 397.136000 ;
  END
 END pi0[163]
 PIN pi0[164]
  DIRECTION OUTPUT ;
  USE SIGNAL ;
  PORT
   LAYER M4 ;
   RECT 43.008000 397.452000 43.200000 397.476000 ;
  END
 END pi0[164]
 PIN pi0[165]
  DIRECTION OUTPUT ;
  USE SIGNAL ;
  PORT
   LAYER M6 ;
   RECT 43.008000 397.424000 43.200000 397.456000 ;
  END
 END pi0[165]
 PIN pi0[166]
  DIRECTION OUTPUT ;
  USE SIGNAL ;
  PORT
   LAYER M4 ;
   RECT 43.008000 397.788000 43.200000 397.812000 ;
  END
 END pi0[166]
 PIN pi0[167]
  DIRECTION OUTPUT ;
  USE SIGNAL ;
  PORT
   LAYER M6 ;
   RECT 43.008000 397.808000 43.200000 397.840000 ;
  END
 END pi0[167]
 PIN pi0[168]
  DIRECTION OUTPUT ;
  USE SIGNAL ;
  PORT
   LAYER M4 ;
   RECT 43.008000 398.124000 43.200000 398.148000 ;
  END
 END pi0[168]
 PIN pi0[169]
  DIRECTION OUTPUT ;
  USE SIGNAL ;
  PORT
   LAYER M6 ;
   RECT 43.008000 398.128000 43.200000 398.160000 ;
  END
 END pi0[169]
 PIN pi0[170]
  DIRECTION OUTPUT ;
  USE SIGNAL ;
  PORT
   LAYER M4 ;
   RECT 43.008000 398.460000 43.200000 398.484000 ;
  END
 END pi0[170]
 PIN pi0[171]
  DIRECTION OUTPUT ;
  USE SIGNAL ;
  PORT
   LAYER M6 ;
   RECT 43.008000 398.448000 43.200000 398.480000 ;
  END
 END pi0[171]
 PIN pi0[172]
  DIRECTION OUTPUT ;
  USE SIGNAL ;
  PORT
   LAYER M4 ;
   RECT 43.008000 398.796000 43.200000 398.820000 ;
  END
 END pi0[172]
 PIN pi0[173]
  DIRECTION OUTPUT ;
  USE SIGNAL ;
  PORT
   LAYER M6 ;
   RECT 43.008000 398.768000 43.200000 398.800000 ;
  END
 END pi0[173]
 PIN pi0[174]
  DIRECTION OUTPUT ;
  USE SIGNAL ;
  PORT
   LAYER M4 ;
   RECT 43.008000 399.132000 43.200000 399.156000 ;
  END
 END pi0[174]
 PIN pi0[175]
  DIRECTION OUTPUT ;
  USE SIGNAL ;
  PORT
   LAYER M6 ;
   RECT 43.008000 398.960000 43.200000 398.992000 ;
  END
 END pi0[175]
 PIN pi0[176]
  DIRECTION OUTPUT ;
  USE SIGNAL ;
  PORT
   LAYER M4 ;
   RECT 43.008000 399.468000 43.200000 399.492000 ;
  END
 END pi0[176]
 PIN pi0[177]
  DIRECTION OUTPUT ;
  USE SIGNAL ;
  PORT
   LAYER M6 ;
   RECT 43.008000 399.024000 43.200000 399.056000 ;
  END
 END pi0[177]
 PIN pi0[178]
  DIRECTION OUTPUT ;
  USE SIGNAL ;
  PORT
   LAYER M4 ;
   RECT 43.008000 399.804000 43.200000 399.828000 ;
  END
 END pi0[178]
 PIN pi0[179]
  DIRECTION OUTPUT ;
  USE SIGNAL ;
  PORT
   LAYER M6 ;
   RECT 43.008000 399.088000 43.200000 399.120000 ;
  END
 END pi0[179]
 PIN pi0[180]
  DIRECTION OUTPUT ;
  USE SIGNAL ;
  PORT
   LAYER M4 ;
   RECT 43.008000 400.140000 43.200000 400.164000 ;
  END
 END pi0[180]
 PIN pi0[181]
  DIRECTION OUTPUT ;
  USE SIGNAL ;
  PORT
   LAYER M6 ;
   RECT 43.008000 400.112000 43.200000 400.144000 ;
  END
 END pi0[181]
 PIN pi0[182]
  DIRECTION OUTPUT ;
  USE SIGNAL ;
  PORT
   LAYER M4 ;
   RECT 43.008000 400.476000 43.200000 400.500000 ;
  END
 END pi0[182]
 PIN pi0[183]
  DIRECTION OUTPUT ;
  USE SIGNAL ;
  PORT
   LAYER M6 ;
   RECT 43.008000 400.432000 43.200000 400.464000 ;
  END
 END pi0[183]
 PIN pi0[184]
  DIRECTION OUTPUT ;
  USE SIGNAL ;
  PORT
   LAYER M4 ;
   RECT 43.008000 400.764000 43.200000 400.788000 ;
  END
 END pi0[184]
 PIN pi0[185]
  DIRECTION OUTPUT ;
  USE SIGNAL ;
  PORT
   LAYER M6 ;
   RECT 43.008000 400.752000 43.200000 400.784000 ;
  END
 END pi0[185]
 PIN pi0[186]
  DIRECTION OUTPUT ;
  USE SIGNAL ;
  PORT
   LAYER M4 ;
   RECT 43.008000 401.100000 43.200000 401.124000 ;
  END
 END pi0[186]
 PIN pi0[187]
  DIRECTION OUTPUT ;
  USE SIGNAL ;
  PORT
   LAYER M6 ;
   RECT 43.008000 401.136000 43.200000 401.168000 ;
  END
 END pi0[187]
 PIN pi0[188]
  DIRECTION OUTPUT ;
  USE SIGNAL ;
  PORT
   LAYER M4 ;
   RECT 43.008000 401.436000 43.200000 401.460000 ;
  END
 END pi0[188]
 PIN pi0[189]
  DIRECTION OUTPUT ;
  USE SIGNAL ;
  PORT
   LAYER M6 ;
   RECT 43.008000 401.456000 43.200000 401.488000 ;
  END
 END pi0[189]
 PIN pi0[190]
  DIRECTION OUTPUT ;
  USE SIGNAL ;
  PORT
   LAYER M4 ;
   RECT 43.008000 401.772000 43.200000 401.796000 ;
  END
 END pi0[190]
 PIN pi0[191]
  DIRECTION OUTPUT ;
  USE SIGNAL ;
  PORT
   LAYER M6 ;
   RECT 43.008000 401.776000 43.200000 401.808000 ;
  END
 END pi0[191]
 PIN pi0[192]
  DIRECTION OUTPUT ;
  USE SIGNAL ;
  PORT
   LAYER M4 ;
   RECT 43.008000 402.108000 43.200000 402.132000 ;
  END
 END pi0[192]
 PIN pi0[193]
  DIRECTION OUTPUT ;
  USE SIGNAL ;
  PORT
   LAYER M6 ;
   RECT 43.008000 402.096000 43.200000 402.128000 ;
  END
 END pi0[193]
 PIN pi0[194]
  DIRECTION OUTPUT ;
  USE SIGNAL ;
  PORT
   LAYER M4 ;
   RECT 43.008000 402.444000 43.200000 402.468000 ;
  END
 END pi0[194]
 PIN pi0[195]
  DIRECTION OUTPUT ;
  USE SIGNAL ;
  PORT
   LAYER M6 ;
   RECT 43.008000 402.480000 43.200000 402.512000 ;
  END
 END pi0[195]
 PIN pi0[196]
  DIRECTION OUTPUT ;
  USE SIGNAL ;
  PORT
   LAYER M4 ;
   RECT 43.008000 402.780000 43.200000 402.804000 ;
  END
 END pi0[196]
 PIN pi0[197]
  DIRECTION OUTPUT ;
  USE SIGNAL ;
  PORT
   LAYER M6 ;
   RECT 43.008000 402.800000 43.200000 402.832000 ;
  END
 END pi0[197]
 PIN pi0[198]
  DIRECTION OUTPUT ;
  USE SIGNAL ;
  PORT
   LAYER M4 ;
   RECT 43.008000 403.116000 43.200000 403.140000 ;
  END
 END pi0[198]
 PIN pi0[199]
  DIRECTION OUTPUT ;
  USE SIGNAL ;
  PORT
   LAYER M6 ;
   RECT 43.008000 403.120000 43.200000 403.152000 ;
  END
 END pi0[199]
 PIN pi0[200]
  DIRECTION OUTPUT ;
  USE SIGNAL ;
  PORT
   LAYER M4 ;
   RECT 43.008000 403.452000 43.200000 403.476000 ;
  END
 END pi0[200]
 PIN pi0[201]
  DIRECTION OUTPUT ;
  USE SIGNAL ;
  PORT
   LAYER M6 ;
   RECT 43.008000 403.312000 43.200000 403.344000 ;
  END
 END pi0[201]
 PIN pi0[202]
  DIRECTION OUTPUT ;
  USE SIGNAL ;
  PORT
   LAYER M4 ;
   RECT 43.008000 403.788000 43.200000 403.812000 ;
  END
 END pi0[202]
 PIN pi0[203]
  DIRECTION OUTPUT ;
  USE SIGNAL ;
  PORT
   LAYER M6 ;
   RECT 43.008000 403.376000 43.200000 403.408000 ;
  END
 END pi0[203]
 PIN pi0[204]
  DIRECTION OUTPUT ;
  USE SIGNAL ;
  PORT
   LAYER M4 ;
   RECT 43.008000 404.124000 43.200000 404.148000 ;
  END
 END pi0[204]
 PIN pi0[205]
  DIRECTION OUTPUT ;
  USE SIGNAL ;
  PORT
   LAYER M6 ;
   RECT 43.008000 404.400000 43.200000 404.432000 ;
  END
 END pi0[205]
 PIN pi0[206]
  DIRECTION OUTPUT ;
  USE SIGNAL ;
  PORT
   LAYER M4 ;
   RECT 43.008000 404.460000 43.200000 404.484000 ;
  END
 END pi0[206]
 PIN pi0[207]
  DIRECTION OUTPUT ;
  USE SIGNAL ;
  PORT
   LAYER M6 ;
   RECT 43.008000 404.464000 43.200000 404.496000 ;
  END
 END pi0[207]
 PIN pi0[208]
  DIRECTION OUTPUT ;
  USE SIGNAL ;
  PORT
   LAYER M4 ;
   RECT 43.008000 404.796000 43.200000 404.820000 ;
  END
 END pi0[208]
 PIN pi0[209]
  DIRECTION OUTPUT ;
  USE SIGNAL ;
  PORT
   LAYER M6 ;
   RECT 43.008000 404.784000 43.200000 404.816000 ;
  END
 END pi0[209]
 PIN pi0[210]
  DIRECTION OUTPUT ;
  USE SIGNAL ;
  PORT
   LAYER M4 ;
   RECT 43.008000 405.132000 43.200000 405.156000 ;
  END
 END pi0[210]
 PIN pi0[211]
  DIRECTION OUTPUT ;
  USE SIGNAL ;
  PORT
   LAYER M6 ;
   RECT 43.008000 405.104000 43.200000 405.136000 ;
  END
 END pi0[211]
 PIN pi0[212]
  DIRECTION OUTPUT ;
  USE SIGNAL ;
  PORT
   LAYER M4 ;
   RECT 43.008000 405.468000 43.200000 405.492000 ;
  END
 END pi0[212]
 PIN pi0[213]
  DIRECTION OUTPUT ;
  USE SIGNAL ;
  PORT
   LAYER M6 ;
   RECT 43.008000 405.424000 43.200000 405.456000 ;
  END
 END pi0[213]
 PIN pi0[214]
  DIRECTION OUTPUT ;
  USE SIGNAL ;
  PORT
   LAYER M4 ;
   RECT 43.008000 405.804000 43.200000 405.828000 ;
  END
 END pi0[214]
 PIN pi0[215]
  DIRECTION OUTPUT ;
  USE SIGNAL ;
  PORT
   LAYER M6 ;
   RECT 43.008000 405.808000 43.200000 405.840000 ;
  END
 END pi0[215]
 PIN pi0[216]
  DIRECTION OUTPUT ;
  USE SIGNAL ;
  PORT
   LAYER M4 ;
   RECT 43.008000 406.140000 43.200000 406.164000 ;
  END
 END pi0[216]
 PIN pi0[217]
  DIRECTION OUTPUT ;
  USE SIGNAL ;
  PORT
   LAYER M6 ;
   RECT 43.008000 406.128000 43.200000 406.160000 ;
  END
 END pi0[217]
 PIN pi0[218]
  DIRECTION OUTPUT ;
  USE SIGNAL ;
  PORT
   LAYER M4 ;
   RECT 43.008000 406.476000 43.200000 406.500000 ;
  END
 END pi0[218]
 PIN pi0[219]
  DIRECTION OUTPUT ;
  USE SIGNAL ;
  PORT
   LAYER M6 ;
   RECT 43.008000 406.448000 43.200000 406.480000 ;
  END
 END pi0[219]
 PIN pi0[220]
  DIRECTION OUTPUT ;
  USE SIGNAL ;
  PORT
   LAYER M4 ;
   RECT 43.008000 406.812000 43.200000 406.836000 ;
  END
 END pi0[220]
 PIN pi0[221]
  DIRECTION OUTPUT ;
  USE SIGNAL ;
  PORT
   LAYER M6 ;
   RECT 43.008000 406.768000 43.200000 406.800000 ;
  END
 END pi0[221]
 PIN pi0[222]
  DIRECTION OUTPUT ;
  USE SIGNAL ;
  PORT
   LAYER M4 ;
   RECT 43.008000 407.100000 43.200000 407.124000 ;
  END
 END pi0[222]
 PIN pi0[223]
  DIRECTION OUTPUT ;
  USE SIGNAL ;
  PORT
   LAYER M6 ;
   RECT 43.008000 407.088000 43.200000 407.120000 ;
  END
 END pi0[223]
 PIN pi0[224]
  DIRECTION OUTPUT ;
  USE SIGNAL ;
  PORT
   LAYER M4 ;
   RECT 43.008000 407.436000 43.200000 407.460000 ;
  END
 END pi0[224]
 PIN pi0[225]
  DIRECTION OUTPUT ;
  USE SIGNAL ;
  PORT
   LAYER M6 ;
   RECT 43.008000 407.472000 43.200000 407.504000 ;
  END
 END pi0[225]
 PIN pi0[226]
  DIRECTION OUTPUT ;
  USE SIGNAL ;
  PORT
   LAYER M4 ;
   RECT 43.008000 407.772000 43.200000 407.796000 ;
  END
 END pi0[226]
 PIN pi0[227]
  DIRECTION OUTPUT ;
  USE SIGNAL ;
  PORT
   LAYER M6 ;
   RECT 43.008000 407.664000 43.200000 407.696000 ;
  END
 END pi0[227]
 PIN pi0[228]
  DIRECTION OUTPUT ;
  USE SIGNAL ;
  PORT
   LAYER M4 ;
   RECT 43.008000 408.108000 43.200000 408.132000 ;
  END
 END pi0[228]
 PIN pi0[229]
  DIRECTION OUTPUT ;
  USE SIGNAL ;
  PORT
   LAYER M6 ;
   RECT 43.008000 407.728000 43.200000 407.760000 ;
  END
 END pi0[229]
 PIN pi0[230]
  DIRECTION OUTPUT ;
  USE SIGNAL ;
  PORT
   LAYER M4 ;
   RECT 43.008000 408.444000 43.200000 408.468000 ;
  END
 END pi0[230]
 PIN pi0[231]
  DIRECTION OUTPUT ;
  USE SIGNAL ;
  PORT
   LAYER M6 ;
   RECT 43.008000 408.752000 43.200000 408.784000 ;
  END
 END pi0[231]
 PIN pi0[232]
  DIRECTION OUTPUT ;
  USE SIGNAL ;
  PORT
   LAYER M4 ;
   RECT 43.008000 408.780000 43.200000 408.804000 ;
  END
 END pi0[232]
 PIN pi0[233]
  DIRECTION OUTPUT ;
  USE SIGNAL ;
  PORT
   LAYER M6 ;
   RECT 43.008000 408.816000 43.200000 408.848000 ;
  END
 END pi0[233]
 PIN pi0[234]
  DIRECTION OUTPUT ;
  USE SIGNAL ;
  PORT
   LAYER M4 ;
   RECT 43.008000 409.116000 43.200000 409.140000 ;
  END
 END pi0[234]
 PIN pi0[235]
  DIRECTION OUTPUT ;
  USE SIGNAL ;
  PORT
   LAYER M6 ;
   RECT 43.008000 409.136000 43.200000 409.168000 ;
  END
 END pi0[235]
 PIN pi0[236]
  DIRECTION OUTPUT ;
  USE SIGNAL ;
  PORT
   LAYER M4 ;
   RECT 43.008000 409.452000 43.200000 409.476000 ;
  END
 END pi0[236]
 PIN pi0[237]
  DIRECTION OUTPUT ;
  USE SIGNAL ;
  PORT
   LAYER M6 ;
   RECT 43.008000 409.456000 43.200000 409.488000 ;
  END
 END pi0[237]
 PIN pi0[238]
  DIRECTION OUTPUT ;
  USE SIGNAL ;
  PORT
   LAYER M4 ;
   RECT 43.008000 409.788000 43.200000 409.812000 ;
  END
 END pi0[238]
 PIN pi0[239]
  DIRECTION OUTPUT ;
  USE SIGNAL ;
  PORT
   LAYER M6 ;
   RECT 43.008000 409.776000 43.200000 409.808000 ;
  END
 END pi0[239]
 PIN pi0[240]
  DIRECTION OUTPUT ;
  USE SIGNAL ;
  PORT
   LAYER M4 ;
   RECT 43.008000 410.124000 43.200000 410.148000 ;
  END
 END pi0[240]
 PIN pi0[241]
  DIRECTION OUTPUT ;
  USE SIGNAL ;
  PORT
   LAYER M6 ;
   RECT 43.008000 410.096000 43.200000 410.128000 ;
  END
 END pi0[241]
 PIN pi0[242]
  DIRECTION OUTPUT ;
  USE SIGNAL ;
  PORT
   LAYER M4 ;
   RECT 43.008000 410.460000 43.200000 410.484000 ;
  END
 END pi0[242]
 PIN pi0[243]
  DIRECTION OUTPUT ;
  USE SIGNAL ;
  PORT
   LAYER M6 ;
   RECT 43.008000 410.480000 43.200000 410.512000 ;
  END
 END pi0[243]
 PIN pi0[244]
  DIRECTION OUTPUT ;
  USE SIGNAL ;
  PORT
   LAYER M4 ;
   RECT 43.008000 410.796000 43.200000 410.820000 ;
  END
 END pi0[244]
 PIN pi0[245]
  DIRECTION OUTPUT ;
  USE SIGNAL ;
  PORT
   LAYER M6 ;
   RECT 43.008000 410.800000 43.200000 410.832000 ;
  END
 END pi0[245]
 PIN pi0[246]
  DIRECTION OUTPUT ;
  USE SIGNAL ;
  PORT
   LAYER M4 ;
   RECT 43.008000 411.132000 43.200000 411.156000 ;
  END
 END pi0[246]
 PIN pi0[247]
  DIRECTION OUTPUT ;
  USE SIGNAL ;
  PORT
   LAYER M6 ;
   RECT 43.008000 411.120000 43.200000 411.152000 ;
  END
 END pi0[247]
 PIN pi0[248]
  DIRECTION OUTPUT ;
  USE SIGNAL ;
  PORT
   LAYER M4 ;
   RECT 43.008000 411.468000 43.200000 411.492000 ;
  END
 END pi0[248]
 PIN pi0[249]
  DIRECTION OUTPUT ;
  USE SIGNAL ;
  PORT
   LAYER M6 ;
   RECT 43.008000 411.440000 43.200000 411.472000 ;
  END
 END pi0[249]
 PIN pi0[250]
  DIRECTION OUTPUT ;
  USE SIGNAL ;
  PORT
   LAYER M4 ;
   RECT 43.008000 411.804000 43.200000 411.828000 ;
  END
 END pi0[250]
 PIN pi0[251]
  DIRECTION OUTPUT ;
  USE SIGNAL ;
  PORT
   LAYER M6 ;
   RECT 43.008000 411.760000 43.200000 411.792000 ;
  END
 END pi0[251]
 PIN pi0[252]
  DIRECTION OUTPUT ;
  USE SIGNAL ;
  PORT
   LAYER M4 ;
   RECT 43.008000 412.140000 43.200000 412.164000 ;
  END
 END pi0[252]
 PIN pi0[253]
  DIRECTION OUTPUT ;
  USE SIGNAL ;
  PORT
   LAYER M6 ;
   RECT 43.008000 411.952000 43.200000 411.984000 ;
  END
 END pi0[253]
 PIN pi0[254]
  DIRECTION OUTPUT ;
  USE SIGNAL ;
  PORT
   LAYER M4 ;
   RECT 43.008000 412.476000 43.200000 412.500000 ;
  END
 END pi0[254]
 PIN pi0[255]
  DIRECTION OUTPUT ;
  USE SIGNAL ;
  PORT
   LAYER M6 ;
   RECT 43.008000 412.016000 43.200000 412.048000 ;
  END
 END pi0[255]
 PIN pi0[256]
  DIRECTION OUTPUT ;
  USE SIGNAL ;
  PORT
   LAYER M4 ;
   RECT 43.008000 412.812000 43.200000 412.836000 ;
  END
 END pi0[256]
 PIN pi0[257]
  DIRECTION OUTPUT ;
  USE SIGNAL ;
  PORT
   LAYER M6 ;
   RECT 43.008000 413.040000 43.200000 413.072000 ;
  END
 END pi0[257]
 PIN pi0[258]
  DIRECTION OUTPUT ;
  USE SIGNAL ;
  PORT
   LAYER M4 ;
   RECT 43.008000 413.100000 43.200000 413.124000 ;
  END
 END pi0[258]
 PIN pi0[259]
  DIRECTION OUTPUT ;
  USE SIGNAL ;
  PORT
   LAYER M6 ;
   RECT 43.008000 413.104000 43.200000 413.136000 ;
  END
 END pi0[259]
 PIN pi0[260]
  DIRECTION OUTPUT ;
  USE SIGNAL ;
  PORT
   LAYER M4 ;
   RECT 43.008000 413.436000 43.200000 413.460000 ;
  END
 END pi0[260]
 PIN pi0[261]
  DIRECTION OUTPUT ;
  USE SIGNAL ;
  PORT
   LAYER M6 ;
   RECT 43.008000 413.424000 43.200000 413.456000 ;
  END
 END pi0[261]
 PIN pi0[262]
  DIRECTION OUTPUT ;
  USE SIGNAL ;
  PORT
   LAYER M4 ;
   RECT 43.008000 413.772000 43.200000 413.796000 ;
  END
 END pi0[262]
 PIN pi0[263]
  DIRECTION OUTPUT ;
  USE SIGNAL ;
  PORT
   LAYER M6 ;
   RECT 43.008000 413.808000 43.200000 413.840000 ;
  END
 END pi0[263]
 PIN pi0[264]
  DIRECTION OUTPUT ;
  USE SIGNAL ;
  PORT
   LAYER M4 ;
   RECT 43.008000 414.108000 43.200000 414.132000 ;
  END
 END pi0[264]
 PIN pi0[265]
  DIRECTION OUTPUT ;
  USE SIGNAL ;
  PORT
   LAYER M6 ;
   RECT 43.008000 414.128000 43.200000 414.160000 ;
  END
 END pi0[265]
 PIN pi0[266]
  DIRECTION OUTPUT ;
  USE SIGNAL ;
  PORT
   LAYER M4 ;
   RECT 43.008000 414.444000 43.200000 414.468000 ;
  END
 END pi0[266]
 PIN pi0[267]
  DIRECTION OUTPUT ;
  USE SIGNAL ;
  PORT
   LAYER M6 ;
   RECT 43.008000 414.448000 43.200000 414.480000 ;
  END
 END pi0[267]
 PIN pi0[268]
  DIRECTION OUTPUT ;
  USE SIGNAL ;
  PORT
   LAYER M4 ;
   RECT 43.008000 414.780000 43.200000 414.804000 ;
  END
 END pi0[268]
 PIN pi0[269]
  DIRECTION OUTPUT ;
  USE SIGNAL ;
  PORT
   LAYER M6 ;
   RECT 43.008000 414.768000 43.200000 414.800000 ;
  END
 END pi0[269]
 PIN pi0[270]
  DIRECTION OUTPUT ;
  USE SIGNAL ;
  PORT
   LAYER M4 ;
   RECT 43.008000 415.116000 43.200000 415.140000 ;
  END
 END pi0[270]
 PIN pi0[271]
  DIRECTION OUTPUT ;
  USE SIGNAL ;
  PORT
   LAYER M6 ;
   RECT 43.008000 415.088000 43.200000 415.120000 ;
  END
 END pi0[271]
 PIN pi0[272]
  DIRECTION OUTPUT ;
  USE SIGNAL ;
  PORT
   LAYER M4 ;
   RECT 43.008000 415.452000 43.200000 415.476000 ;
  END
 END pi0[272]
 PIN pi0[273]
  DIRECTION OUTPUT ;
  USE SIGNAL ;
  PORT
   LAYER M6 ;
   RECT 43.008000 415.472000 43.200000 415.504000 ;
  END
 END pi0[273]
 PIN pi0[274]
  DIRECTION OUTPUT ;
  USE SIGNAL ;
  PORT
   LAYER M4 ;
   RECT 43.008000 415.788000 43.200000 415.812000 ;
  END
 END pi0[274]
 PIN pi0[275]
  DIRECTION OUTPUT ;
  USE SIGNAL ;
  PORT
   LAYER M6 ;
   RECT 43.008000 415.792000 43.200000 415.824000 ;
  END
 END pi0[275]
 PIN pi0[276]
  DIRECTION OUTPUT ;
  USE SIGNAL ;
  PORT
   LAYER M4 ;
   RECT 43.008000 416.124000 43.200000 416.148000 ;
  END
 END pi0[276]
 PIN pi0[277]
  DIRECTION OUTPUT ;
  USE SIGNAL ;
  PORT
   LAYER M6 ;
   RECT 43.008000 416.112000 43.200000 416.144000 ;
  END
 END pi0[277]
 PIN pi0[278]
  DIRECTION OUTPUT ;
  USE SIGNAL ;
  PORT
   LAYER M4 ;
   RECT 43.008000 416.460000 43.200000 416.484000 ;
  END
 END pi0[278]
 PIN pi0[279]
  DIRECTION OUTPUT ;
  USE SIGNAL ;
  PORT
   LAYER M6 ;
   RECT 43.008000 416.304000 43.200000 416.336000 ;
  END
 END pi0[279]
 PIN pi0[280]
  DIRECTION OUTPUT ;
  USE SIGNAL ;
  PORT
   LAYER M4 ;
   RECT 43.008000 416.796000 43.200000 416.820000 ;
  END
 END pi0[280]
 PIN pi0[281]
  DIRECTION OUTPUT ;
  USE SIGNAL ;
  PORT
   LAYER M6 ;
   RECT 43.008000 416.368000 43.200000 416.400000 ;
  END
 END pi0[281]
 PIN pi0[282]
  DIRECTION OUTPUT ;
  USE SIGNAL ;
  PORT
   LAYER M4 ;
   RECT 43.008000 417.132000 43.200000 417.156000 ;
  END
 END pi0[282]
 PIN pi0[283]
  DIRECTION OUTPUT ;
  USE SIGNAL ;
  PORT
   LAYER M6 ;
   RECT 43.008000 417.392000 43.200000 417.424000 ;
  END
 END pi0[283]
 PIN pi0[284]
  DIRECTION OUTPUT ;
  USE SIGNAL ;
  PORT
   LAYER M4 ;
   RECT 43.008000 417.468000 43.200000 417.492000 ;
  END
 END pi0[284]
 PIN pi0[285]
  DIRECTION OUTPUT ;
  USE SIGNAL ;
  PORT
   LAYER M6 ;
   RECT 43.008000 417.456000 43.200000 417.488000 ;
  END
 END pi0[285]
 PIN pi0[286]
  DIRECTION OUTPUT ;
  USE SIGNAL ;
  PORT
   LAYER M4 ;
   RECT 43.008000 417.804000 43.200000 417.828000 ;
  END
 END pi0[286]
 PIN pi0[287]
  DIRECTION OUTPUT ;
  USE SIGNAL ;
  PORT
   LAYER M6 ;
   RECT 43.008000 417.776000 43.200000 417.808000 ;
  END
 END pi0[287]
 PIN pi0[288]
  DIRECTION OUTPUT ;
  USE SIGNAL ;
  PORT
   LAYER M4 ;
   RECT 43.008000 418.140000 43.200000 418.164000 ;
  END
 END pi0[288]
 PIN fh0[0]
  DIRECTION OUTPUT ;
  USE SIGNAL ;
  PORT
   LAYER M4 ;
   RECT 43.008000 344.604000 43.200000 344.628000 ;
  END
 END fh0[0]
 PIN fh0[1]
  DIRECTION OUTPUT ;
  USE SIGNAL ;
  PORT
   LAYER M6 ;
   RECT 43.008000 344.624000 43.200000 344.656000 ;
  END
 END fh0[1]
 PIN fh0[2]
  DIRECTION OUTPUT ;
  USE SIGNAL ;
  PORT
   LAYER M4 ;
   RECT 43.008000 344.892000 43.200000 344.916000 ;
  END
 END fh0[2]
 PIN fh0[3]
  DIRECTION OUTPUT ;
  USE SIGNAL ;
  PORT
   LAYER M6 ;
   RECT 43.008000 344.944000 43.200000 344.976000 ;
  END
 END fh0[3]
 PIN rh0[0]
  DIRECTION OUTPUT ;
  USE SIGNAL ;
  PORT
   LAYER M6 ;
   RECT 43.008000 418.096000 43.200000 418.128000 ;
  END
 END rh0[0]
 PIN rh0[1]
  DIRECTION OUTPUT ;
  USE SIGNAL ;
  PORT
   LAYER M4 ;
   RECT 43.008000 418.476000 43.200000 418.500000 ;
  END
 END rh0[1]
 PIN rh0[2]
  DIRECTION OUTPUT ;
  USE SIGNAL ;
  PORT
   LAYER M6 ;
   RECT 43.008000 418.480000 43.200000 418.512000 ;
  END
 END rh0[2]
 PIN rh0[3]
  DIRECTION OUTPUT ;
  USE SIGNAL ;
  PORT
   LAYER M4 ;
   RECT 43.008000 418.812000 43.200000 418.836000 ;
  END
 END rh0[3]
 PIN po1[0]
  DIRECTION INPUT ;
  USE SIGNAL ;
  PORT
   LAYER M4 ;
   RECT 43.008000 105.996000 43.200000 106.020000 ;
  END
 END po1[0]
 PIN po1[1]
  DIRECTION INPUT ;
  USE SIGNAL ;
  PORT
   LAYER M6 ;
   RECT 43.008000 106.352000 43.200000 106.384000 ;
  END
 END po1[1]
 PIN po1[2]
  DIRECTION INPUT ;
  USE SIGNAL ;
  PORT
   LAYER M4 ;
   RECT 43.008000 106.332000 43.200000 106.356000 ;
  END
 END po1[2]
 PIN po1[3]
  DIRECTION INPUT ;
  USE SIGNAL ;
  PORT
   LAYER M6 ;
   RECT 43.008000 106.416000 43.200000 106.448000 ;
  END
 END po1[3]
 PIN po1[4]
  DIRECTION INPUT ;
  USE SIGNAL ;
  PORT
   LAYER M4 ;
   RECT 43.008000 106.668000 43.200000 106.692000 ;
  END
 END po1[4]
 PIN po1[5]
  DIRECTION INPUT ;
  USE SIGNAL ;
  PORT
   LAYER M6 ;
   RECT 43.008000 106.672000 43.200000 106.704000 ;
  END
 END po1[5]
 PIN po1[6]
  DIRECTION INPUT ;
  USE SIGNAL ;
  PORT
   LAYER M4 ;
   RECT 43.008000 107.004000 43.200000 107.028000 ;
  END
 END po1[6]
 PIN po1[7]
  DIRECTION INPUT ;
  USE SIGNAL ;
  PORT
   LAYER M6 ;
   RECT 43.008000 106.992000 43.200000 107.024000 ;
  END
 END po1[7]
 PIN po1[8]
  DIRECTION INPUT ;
  USE SIGNAL ;
  PORT
   LAYER M4 ;
   RECT 43.008000 107.340000 43.200000 107.364000 ;
  END
 END po1[8]
 PIN po1[9]
  DIRECTION INPUT ;
  USE SIGNAL ;
  PORT
   LAYER M6 ;
   RECT 43.008000 107.376000 43.200000 107.408000 ;
  END
 END po1[9]
 PIN po1[10]
  DIRECTION INPUT ;
  USE SIGNAL ;
  PORT
   LAYER M4 ;
   RECT 43.008000 107.676000 43.200000 107.700000 ;
  END
 END po1[10]
 PIN po1[11]
  DIRECTION INPUT ;
  USE SIGNAL ;
  PORT
   LAYER M6 ;
   RECT 43.008000 107.696000 43.200000 107.728000 ;
  END
 END po1[11]
 PIN po1[12]
  DIRECTION INPUT ;
  USE SIGNAL ;
  PORT
   LAYER M4 ;
   RECT 43.008000 108.012000 43.200000 108.036000 ;
  END
 END po1[12]
 PIN po1[13]
  DIRECTION INPUT ;
  USE SIGNAL ;
  PORT
   LAYER M6 ;
   RECT 43.008000 108.016000 43.200000 108.048000 ;
  END
 END po1[13]
 PIN po1[14]
  DIRECTION INPUT ;
  USE SIGNAL ;
  PORT
   LAYER M4 ;
   RECT 43.008000 108.348000 43.200000 108.372000 ;
  END
 END po1[14]
 PIN po1[15]
  DIRECTION INPUT ;
  USE SIGNAL ;
  PORT
   LAYER M6 ;
   RECT 43.008000 108.336000 43.200000 108.368000 ;
  END
 END po1[15]
 PIN po1[16]
  DIRECTION INPUT ;
  USE SIGNAL ;
  PORT
   LAYER M4 ;
   RECT 43.008000 108.684000 43.200000 108.708000 ;
  END
 END po1[16]
 PIN po1[17]
  DIRECTION INPUT ;
  USE SIGNAL ;
  PORT
   LAYER M6 ;
   RECT 43.008000 108.720000 43.200000 108.752000 ;
  END
 END po1[17]
 PIN po1[18]
  DIRECTION INPUT ;
  USE SIGNAL ;
  PORT
   LAYER M4 ;
   RECT 43.008000 109.020000 43.200000 109.044000 ;
  END
 END po1[18]
 PIN po1[19]
  DIRECTION INPUT ;
  USE SIGNAL ;
  PORT
   LAYER M6 ;
   RECT 43.008000 109.040000 43.200000 109.072000 ;
  END
 END po1[19]
 PIN po1[20]
  DIRECTION INPUT ;
  USE SIGNAL ;
  PORT
   LAYER M4 ;
   RECT 43.008000 109.356000 43.200000 109.380000 ;
  END
 END po1[20]
 PIN po1[21]
  DIRECTION INPUT ;
  USE SIGNAL ;
  PORT
   LAYER M6 ;
   RECT 43.008000 109.360000 43.200000 109.392000 ;
  END
 END po1[21]
 PIN po1[22]
  DIRECTION INPUT ;
  USE SIGNAL ;
  PORT
   LAYER M4 ;
   RECT 43.008000 109.692000 43.200000 109.716000 ;
  END
 END po1[22]
 PIN po1[23]
  DIRECTION INPUT ;
  USE SIGNAL ;
  PORT
   LAYER M6 ;
   RECT 43.008000 109.616000 43.200000 109.648000 ;
  END
 END po1[23]
 PIN po1[24]
  DIRECTION INPUT ;
  USE SIGNAL ;
  PORT
   LAYER M4 ;
   RECT 43.008000 110.028000 43.200000 110.052000 ;
  END
 END po1[24]
 PIN po1[25]
  DIRECTION INPUT ;
  USE SIGNAL ;
  PORT
   LAYER M6 ;
   RECT 43.008000 110.640000 43.200000 110.672000 ;
  END
 END po1[25]
 PIN po1[26]
  DIRECTION INPUT ;
  USE SIGNAL ;
  PORT
   LAYER M4 ;
   RECT 43.008000 110.364000 43.200000 110.388000 ;
  END
 END po1[26]
 PIN po1[27]
  DIRECTION INPUT ;
  USE SIGNAL ;
  PORT
   LAYER M6 ;
   RECT 43.008000 110.704000 43.200000 110.736000 ;
  END
 END po1[27]
 PIN po1[28]
  DIRECTION INPUT ;
  USE SIGNAL ;
  PORT
   LAYER M4 ;
   RECT 43.008000 110.652000 43.200000 110.676000 ;
  END
 END po1[28]
 PIN po1[29]
  DIRECTION INPUT ;
  USE SIGNAL ;
  PORT
   LAYER M6 ;
   RECT 43.008000 110.768000 43.200000 110.800000 ;
  END
 END po1[29]
 PIN po1[30]
  DIRECTION INPUT ;
  USE SIGNAL ;
  PORT
   LAYER M4 ;
   RECT 43.008000 110.988000 43.200000 111.012000 ;
  END
 END po1[30]
 PIN po1[31]
  DIRECTION INPUT ;
  USE SIGNAL ;
  PORT
   LAYER M6 ;
   RECT 43.008000 111.024000 43.200000 111.056000 ;
  END
 END po1[31]
 PIN po1[32]
  DIRECTION INPUT ;
  USE SIGNAL ;
  PORT
   LAYER M4 ;
   RECT 43.008000 111.324000 43.200000 111.348000 ;
  END
 END po1[32]
 PIN po1[33]
  DIRECTION INPUT ;
  USE SIGNAL ;
  PORT
   LAYER M6 ;
   RECT 43.008000 111.344000 43.200000 111.376000 ;
  END
 END po1[33]
 PIN po1[34]
  DIRECTION INPUT ;
  USE SIGNAL ;
  PORT
   LAYER M4 ;
   RECT 43.008000 111.660000 43.200000 111.684000 ;
  END
 END po1[34]
 PIN po1[35]
  DIRECTION INPUT ;
  USE SIGNAL ;
  PORT
   LAYER M6 ;
   RECT 43.008000 111.728000 43.200000 111.760000 ;
  END
 END po1[35]
 PIN po1[36]
  DIRECTION INPUT ;
  USE SIGNAL ;
  PORT
   LAYER M4 ;
   RECT 43.008000 111.996000 43.200000 112.020000 ;
  END
 END po1[36]
 PIN po1[37]
  DIRECTION INPUT ;
  USE SIGNAL ;
  PORT
   LAYER M6 ;
   RECT 43.008000 112.048000 43.200000 112.080000 ;
  END
 END po1[37]
 PIN po1[38]
  DIRECTION INPUT ;
  USE SIGNAL ;
  PORT
   LAYER M4 ;
   RECT 43.008000 112.332000 43.200000 112.356000 ;
  END
 END po1[38]
 PIN po1[39]
  DIRECTION INPUT ;
  USE SIGNAL ;
  PORT
   LAYER M6 ;
   RECT 43.008000 112.368000 43.200000 112.400000 ;
  END
 END po1[39]
 PIN po1[40]
  DIRECTION INPUT ;
  USE SIGNAL ;
  PORT
   LAYER M4 ;
   RECT 43.008000 112.668000 43.200000 112.692000 ;
  END
 END po1[40]
 PIN po1[41]
  DIRECTION INPUT ;
  USE SIGNAL ;
  PORT
   LAYER M6 ;
   RECT 43.008000 112.688000 43.200000 112.720000 ;
  END
 END po1[41]
 PIN po1[42]
  DIRECTION INPUT ;
  USE SIGNAL ;
  PORT
   LAYER M4 ;
   RECT 43.008000 113.004000 43.200000 113.028000 ;
  END
 END po1[42]
 PIN po1[43]
  DIRECTION INPUT ;
  USE SIGNAL ;
  PORT
   LAYER M6 ;
   RECT 43.008000 113.072000 43.200000 113.104000 ;
  END
 END po1[43]
 PIN po1[44]
  DIRECTION INPUT ;
  USE SIGNAL ;
  PORT
   LAYER M4 ;
   RECT 43.008000 113.340000 43.200000 113.364000 ;
  END
 END po1[44]
 PIN po1[45]
  DIRECTION INPUT ;
  USE SIGNAL ;
  PORT
   LAYER M6 ;
   RECT 43.008000 113.392000 43.200000 113.424000 ;
  END
 END po1[45]
 PIN po1[46]
  DIRECTION INPUT ;
  USE SIGNAL ;
  PORT
   LAYER M4 ;
   RECT 43.008000 113.676000 43.200000 113.700000 ;
  END
 END po1[46]
 PIN po1[47]
  DIRECTION INPUT ;
  USE SIGNAL ;
  PORT
   LAYER M6 ;
   RECT 43.008000 113.712000 43.200000 113.744000 ;
  END
 END po1[47]
 PIN po1[48]
  DIRECTION INPUT ;
  USE SIGNAL ;
  PORT
   LAYER M4 ;
   RECT 43.008000 114.012000 43.200000 114.036000 ;
  END
 END po1[48]
 PIN po1[49]
  DIRECTION INPUT ;
  USE SIGNAL ;
  PORT
   LAYER M6 ;
   RECT 43.008000 113.968000 43.200000 114.000000 ;
  END
 END po1[49]
 PIN po1[50]
  DIRECTION INPUT ;
  USE SIGNAL ;
  PORT
   LAYER M4 ;
   RECT 43.008000 114.348000 43.200000 114.372000 ;
  END
 END po1[50]
 PIN po1[51]
  DIRECTION INPUT ;
  USE SIGNAL ;
  PORT
   LAYER M6 ;
   RECT 43.008000 114.992000 43.200000 115.024000 ;
  END
 END po1[51]
 PIN po1[52]
  DIRECTION INPUT ;
  USE SIGNAL ;
  PORT
   LAYER M4 ;
   RECT 43.008000 114.684000 43.200000 114.708000 ;
  END
 END po1[52]
 PIN po1[53]
  DIRECTION INPUT ;
  USE SIGNAL ;
  PORT
   LAYER M6 ;
   RECT 43.008000 115.056000 43.200000 115.088000 ;
  END
 END po1[53]
 PIN po1[54]
  DIRECTION INPUT ;
  USE SIGNAL ;
  PORT
   LAYER M4 ;
   RECT 43.008000 114.972000 43.200000 114.996000 ;
  END
 END po1[54]
 PIN po1[55]
  DIRECTION INPUT ;
  USE SIGNAL ;
  PORT
   LAYER M6 ;
   RECT 43.008000 115.120000 43.200000 115.152000 ;
  END
 END po1[55]
 PIN po1[56]
  DIRECTION INPUT ;
  USE SIGNAL ;
  PORT
   LAYER M4 ;
   RECT 43.008000 115.308000 43.200000 115.332000 ;
  END
 END po1[56]
 PIN po1[57]
  DIRECTION INPUT ;
  USE SIGNAL ;
  PORT
   LAYER M6 ;
   RECT 43.008000 115.376000 43.200000 115.408000 ;
  END
 END po1[57]
 PIN po1[58]
  DIRECTION INPUT ;
  USE SIGNAL ;
  PORT
   LAYER M4 ;
   RECT 43.008000 115.644000 43.200000 115.668000 ;
  END
 END po1[58]
 PIN po1[59]
  DIRECTION INPUT ;
  USE SIGNAL ;
  PORT
   LAYER M6 ;
   RECT 43.008000 115.696000 43.200000 115.728000 ;
  END
 END po1[59]
 PIN po1[60]
  DIRECTION INPUT ;
  USE SIGNAL ;
  PORT
   LAYER M4 ;
   RECT 43.008000 115.980000 43.200000 116.004000 ;
  END
 END po1[60]
 PIN po1[61]
  DIRECTION INPUT ;
  USE SIGNAL ;
  PORT
   LAYER M6 ;
   RECT 43.008000 116.080000 43.200000 116.112000 ;
  END
 END po1[61]
 PIN po1[62]
  DIRECTION INPUT ;
  USE SIGNAL ;
  PORT
   LAYER M4 ;
   RECT 43.008000 116.316000 43.200000 116.340000 ;
  END
 END po1[62]
 PIN po1[63]
  DIRECTION INPUT ;
  USE SIGNAL ;
  PORT
   LAYER M6 ;
   RECT 43.008000 116.400000 43.200000 116.432000 ;
  END
 END po1[63]
 PIN po1[64]
  DIRECTION INPUT ;
  USE SIGNAL ;
  PORT
   LAYER M4 ;
   RECT 43.008000 116.652000 43.200000 116.676000 ;
  END
 END po1[64]
 PIN po1[65]
  DIRECTION INPUT ;
  USE SIGNAL ;
  PORT
   LAYER M6 ;
   RECT 43.008000 116.720000 43.200000 116.752000 ;
  END
 END po1[65]
 PIN po1[66]
  DIRECTION INPUT ;
  USE SIGNAL ;
  PORT
   LAYER M4 ;
   RECT 43.008000 116.988000 43.200000 117.012000 ;
  END
 END po1[66]
 PIN po1[67]
  DIRECTION INPUT ;
  USE SIGNAL ;
  PORT
   LAYER M6 ;
   RECT 43.008000 117.040000 43.200000 117.072000 ;
  END
 END po1[67]
 PIN po1[68]
  DIRECTION INPUT ;
  USE SIGNAL ;
  PORT
   LAYER M4 ;
   RECT 43.008000 117.324000 43.200000 117.348000 ;
  END
 END po1[68]
 PIN po1[69]
  DIRECTION INPUT ;
  USE SIGNAL ;
  PORT
   LAYER M6 ;
   RECT 43.008000 117.360000 43.200000 117.392000 ;
  END
 END po1[69]
 PIN po1[70]
  DIRECTION INPUT ;
  USE SIGNAL ;
  PORT
   LAYER M4 ;
   RECT 43.008000 117.660000 43.200000 117.684000 ;
  END
 END po1[70]
 PIN po1[71]
  DIRECTION INPUT ;
  USE SIGNAL ;
  PORT
   LAYER M6 ;
   RECT 43.008000 117.744000 43.200000 117.776000 ;
  END
 END po1[71]
 PIN po1[72]
  DIRECTION INPUT ;
  USE SIGNAL ;
  PORT
   LAYER M4 ;
   RECT 43.008000 117.996000 43.200000 118.020000 ;
  END
 END po1[72]
 PIN po1[73]
  DIRECTION INPUT ;
  USE SIGNAL ;
  PORT
   LAYER M6 ;
   RECT 43.008000 118.064000 43.200000 118.096000 ;
  END
 END po1[73]
 PIN po1[74]
  DIRECTION INPUT ;
  USE SIGNAL ;
  PORT
   LAYER M4 ;
   RECT 43.008000 118.332000 43.200000 118.356000 ;
  END
 END po1[74]
 PIN po1[75]
  DIRECTION INPUT ;
  USE SIGNAL ;
  PORT
   LAYER M6 ;
   RECT 43.008000 118.256000 43.200000 118.288000 ;
  END
 END po1[75]
 PIN po1[76]
  DIRECTION INPUT ;
  USE SIGNAL ;
  PORT
   LAYER M4 ;
   RECT 43.008000 118.668000 43.200000 118.692000 ;
  END
 END po1[76]
 PIN po1[77]
  DIRECTION INPUT ;
  USE SIGNAL ;
  PORT
   LAYER M6 ;
   RECT 43.008000 119.280000 43.200000 119.312000 ;
  END
 END po1[77]
 PIN po1[78]
  DIRECTION INPUT ;
  USE SIGNAL ;
  PORT
   LAYER M4 ;
   RECT 43.008000 119.004000 43.200000 119.028000 ;
  END
 END po1[78]
 PIN po1[79]
  DIRECTION INPUT ;
  USE SIGNAL ;
  PORT
   LAYER M6 ;
   RECT 43.008000 119.344000 43.200000 119.376000 ;
  END
 END po1[79]
 PIN po1[80]
  DIRECTION INPUT ;
  USE SIGNAL ;
  PORT
   LAYER M4 ;
   RECT 43.008000 119.340000 43.200000 119.364000 ;
  END
 END po1[80]
 PIN po1[81]
  DIRECTION INPUT ;
  USE SIGNAL ;
  PORT
   LAYER M6 ;
   RECT 43.008000 119.408000 43.200000 119.440000 ;
  END
 END po1[81]
 PIN po1[82]
  DIRECTION INPUT ;
  USE SIGNAL ;
  PORT
   LAYER M4 ;
   RECT 43.008000 119.628000 43.200000 119.652000 ;
  END
 END po1[82]
 PIN po1[83]
  DIRECTION INPUT ;
  USE SIGNAL ;
  PORT
   LAYER M6 ;
   RECT 43.008000 119.728000 43.200000 119.760000 ;
  END
 END po1[83]
 PIN po1[84]
  DIRECTION INPUT ;
  USE SIGNAL ;
  PORT
   LAYER M4 ;
   RECT 43.008000 119.964000 43.200000 119.988000 ;
  END
 END po1[84]
 PIN po1[85]
  DIRECTION INPUT ;
  USE SIGNAL ;
  PORT
   LAYER M6 ;
   RECT 43.008000 120.048000 43.200000 120.080000 ;
  END
 END po1[85]
 PIN po1[86]
  DIRECTION INPUT ;
  USE SIGNAL ;
  PORT
   LAYER M4 ;
   RECT 43.008000 120.300000 43.200000 120.324000 ;
  END
 END po1[86]
 PIN po1[87]
  DIRECTION INPUT ;
  USE SIGNAL ;
  PORT
   LAYER M6 ;
   RECT 43.008000 120.368000 43.200000 120.400000 ;
  END
 END po1[87]
 PIN po1[88]
  DIRECTION INPUT ;
  USE SIGNAL ;
  PORT
   LAYER M4 ;
   RECT 43.008000 120.636000 43.200000 120.660000 ;
  END
 END po1[88]
 PIN po1[89]
  DIRECTION INPUT ;
  USE SIGNAL ;
  PORT
   LAYER M6 ;
   RECT 43.008000 120.752000 43.200000 120.784000 ;
  END
 END po1[89]
 PIN po1[90]
  DIRECTION INPUT ;
  USE SIGNAL ;
  PORT
   LAYER M4 ;
   RECT 43.008000 120.972000 43.200000 120.996000 ;
  END
 END po1[90]
 PIN po1[91]
  DIRECTION INPUT ;
  USE SIGNAL ;
  PORT
   LAYER M6 ;
   RECT 43.008000 121.072000 43.200000 121.104000 ;
  END
 END po1[91]
 PIN po1[92]
  DIRECTION INPUT ;
  USE SIGNAL ;
  PORT
   LAYER M4 ;
   RECT 43.008000 121.308000 43.200000 121.332000 ;
  END
 END po1[92]
 PIN po1[93]
  DIRECTION INPUT ;
  USE SIGNAL ;
  PORT
   LAYER M6 ;
   RECT 43.008000 121.392000 43.200000 121.424000 ;
  END
 END po1[93]
 PIN po1[94]
  DIRECTION INPUT ;
  USE SIGNAL ;
  PORT
   LAYER M4 ;
   RECT 43.008000 121.644000 43.200000 121.668000 ;
  END
 END po1[94]
 PIN po1[95]
  DIRECTION INPUT ;
  USE SIGNAL ;
  PORT
   LAYER M6 ;
   RECT 43.008000 121.712000 43.200000 121.744000 ;
  END
 END po1[95]
 PIN po1[96]
  DIRECTION INPUT ;
  USE SIGNAL ;
  PORT
   LAYER M4 ;
   RECT 43.008000 121.980000 43.200000 122.004000 ;
  END
 END po1[96]
 PIN po1[97]
  DIRECTION INPUT ;
  USE SIGNAL ;
  PORT
   LAYER M6 ;
   RECT 43.008000 122.096000 43.200000 122.128000 ;
  END
 END po1[97]
 PIN po1[98]
  DIRECTION INPUT ;
  USE SIGNAL ;
  PORT
   LAYER M4 ;
   RECT 43.008000 122.316000 43.200000 122.340000 ;
  END
 END po1[98]
 PIN po1[99]
  DIRECTION INPUT ;
  USE SIGNAL ;
  PORT
   LAYER M6 ;
   RECT 43.008000 122.416000 43.200000 122.448000 ;
  END
 END po1[99]
 PIN po1[100]
  DIRECTION INPUT ;
  USE SIGNAL ;
  PORT
   LAYER M4 ;
   RECT 43.008000 122.652000 43.200000 122.676000 ;
  END
 END po1[100]
 PIN po1[101]
  DIRECTION INPUT ;
  USE SIGNAL ;
  PORT
   LAYER M6 ;
   RECT 43.008000 122.608000 43.200000 122.640000 ;
  END
 END po1[101]
 PIN po1[102]
  DIRECTION INPUT ;
  USE SIGNAL ;
  PORT
   LAYER M4 ;
   RECT 43.008000 122.988000 43.200000 123.012000 ;
  END
 END po1[102]
 PIN po1[103]
  DIRECTION INPUT ;
  USE SIGNAL ;
  PORT
   LAYER M6 ;
   RECT 43.008000 123.632000 43.200000 123.664000 ;
  END
 END po1[103]
 PIN po1[104]
  DIRECTION INPUT ;
  USE SIGNAL ;
  PORT
   LAYER M4 ;
   RECT 43.008000 123.324000 43.200000 123.348000 ;
  END
 END po1[104]
 PIN po1[105]
  DIRECTION INPUT ;
  USE SIGNAL ;
  PORT
   LAYER M6 ;
   RECT 43.008000 123.696000 43.200000 123.728000 ;
  END
 END po1[105]
 PIN po1[106]
  DIRECTION INPUT ;
  USE SIGNAL ;
  PORT
   LAYER M4 ;
   RECT 43.008000 123.660000 43.200000 123.684000 ;
  END
 END po1[106]
 PIN po1[107]
  DIRECTION INPUT ;
  USE SIGNAL ;
  PORT
   LAYER M6 ;
   RECT 43.008000 123.760000 43.200000 123.792000 ;
  END
 END po1[107]
 PIN po1[108]
  DIRECTION INPUT ;
  USE SIGNAL ;
  PORT
   LAYER M4 ;
   RECT 43.008000 123.948000 43.200000 123.972000 ;
  END
 END po1[108]
 PIN po1[109]
  DIRECTION INPUT ;
  USE SIGNAL ;
  PORT
   LAYER M6 ;
   RECT 43.008000 124.080000 43.200000 124.112000 ;
  END
 END po1[109]
 PIN po1[110]
  DIRECTION INPUT ;
  USE SIGNAL ;
  PORT
   LAYER M4 ;
   RECT 43.008000 124.284000 43.200000 124.308000 ;
  END
 END po1[110]
 PIN po1[111]
  DIRECTION INPUT ;
  USE SIGNAL ;
  PORT
   LAYER M6 ;
   RECT 43.008000 124.400000 43.200000 124.432000 ;
  END
 END po1[111]
 PIN po1[112]
  DIRECTION INPUT ;
  USE SIGNAL ;
  PORT
   LAYER M4 ;
   RECT 43.008000 124.620000 43.200000 124.644000 ;
  END
 END po1[112]
 PIN po1[113]
  DIRECTION INPUT ;
  USE SIGNAL ;
  PORT
   LAYER M6 ;
   RECT 43.008000 124.720000 43.200000 124.752000 ;
  END
 END po1[113]
 PIN po1[114]
  DIRECTION INPUT ;
  USE SIGNAL ;
  PORT
   LAYER M4 ;
   RECT 43.008000 124.956000 43.200000 124.980000 ;
  END
 END po1[114]
 PIN po1[115]
  DIRECTION INPUT ;
  USE SIGNAL ;
  PORT
   LAYER M6 ;
   RECT 43.008000 125.104000 43.200000 125.136000 ;
  END
 END po1[115]
 PIN po1[116]
  DIRECTION INPUT ;
  USE SIGNAL ;
  PORT
   LAYER M4 ;
   RECT 43.008000 125.292000 43.200000 125.316000 ;
  END
 END po1[116]
 PIN po1[117]
  DIRECTION INPUT ;
  USE SIGNAL ;
  PORT
   LAYER M6 ;
   RECT 43.008000 125.424000 43.200000 125.456000 ;
  END
 END po1[117]
 PIN po1[118]
  DIRECTION INPUT ;
  USE SIGNAL ;
  PORT
   LAYER M4 ;
   RECT 43.008000 125.628000 43.200000 125.652000 ;
  END
 END po1[118]
 PIN po1[119]
  DIRECTION INPUT ;
  USE SIGNAL ;
  PORT
   LAYER M6 ;
   RECT 43.008000 125.744000 43.200000 125.776000 ;
  END
 END po1[119]
 PIN po1[120]
  DIRECTION INPUT ;
  USE SIGNAL ;
  PORT
   LAYER M4 ;
   RECT 43.008000 125.964000 43.200000 125.988000 ;
  END
 END po1[120]
 PIN po1[121]
  DIRECTION INPUT ;
  USE SIGNAL ;
  PORT
   LAYER M6 ;
   RECT 43.008000 126.064000 43.200000 126.096000 ;
  END
 END po1[121]
 PIN po1[122]
  DIRECTION INPUT ;
  USE SIGNAL ;
  PORT
   LAYER M4 ;
   RECT 43.008000 126.300000 43.200000 126.324000 ;
  END
 END po1[122]
 PIN po1[123]
  DIRECTION INPUT ;
  USE SIGNAL ;
  PORT
   LAYER M6 ;
   RECT 43.008000 126.448000 43.200000 126.480000 ;
  END
 END po1[123]
 PIN po1[124]
  DIRECTION INPUT ;
  USE SIGNAL ;
  PORT
   LAYER M4 ;
   RECT 43.008000 126.636000 43.200000 126.660000 ;
  END
 END po1[124]
 PIN po1[125]
  DIRECTION INPUT ;
  USE SIGNAL ;
  PORT
   LAYER M6 ;
   RECT 43.008000 126.768000 43.200000 126.800000 ;
  END
 END po1[125]
 PIN po1[126]
  DIRECTION INPUT ;
  USE SIGNAL ;
  PORT
   LAYER M4 ;
   RECT 43.008000 126.972000 43.200000 126.996000 ;
  END
 END po1[126]
 PIN po1[127]
  DIRECTION INPUT ;
  USE SIGNAL ;
  PORT
   LAYER M6 ;
   RECT 43.008000 126.896000 43.200000 126.928000 ;
  END
 END po1[127]
 PIN po1[128]
  DIRECTION INPUT ;
  USE SIGNAL ;
  PORT
   LAYER M4 ;
   RECT 43.008000 127.308000 43.200000 127.332000 ;
  END
 END po1[128]
 PIN po1[129]
  DIRECTION INPUT ;
  USE SIGNAL ;
  PORT
   LAYER M6 ;
   RECT 43.008000 127.920000 43.200000 127.952000 ;
  END
 END po1[129]
 PIN po1[130]
  DIRECTION INPUT ;
  USE SIGNAL ;
  PORT
   LAYER M4 ;
   RECT 43.008000 127.644000 43.200000 127.668000 ;
  END
 END po1[130]
 PIN po1[131]
  DIRECTION INPUT ;
  USE SIGNAL ;
  PORT
   LAYER M6 ;
   RECT 43.008000 127.984000 43.200000 128.016000 ;
  END
 END po1[131]
 PIN po1[132]
  DIRECTION INPUT ;
  USE SIGNAL ;
  PORT
   LAYER M4 ;
   RECT 43.008000 127.980000 43.200000 128.004000 ;
  END
 END po1[132]
 PIN po1[133]
  DIRECTION INPUT ;
  USE SIGNAL ;
  PORT
   LAYER M6 ;
   RECT 43.008000 128.112000 43.200000 128.144000 ;
  END
 END po1[133]
 PIN po1[134]
  DIRECTION INPUT ;
  USE SIGNAL ;
  PORT
   LAYER M4 ;
   RECT 43.008000 128.268000 43.200000 128.292000 ;
  END
 END po1[134]
 PIN po1[135]
  DIRECTION INPUT ;
  USE SIGNAL ;
  PORT
   LAYER M6 ;
   RECT 43.008000 128.432000 43.200000 128.464000 ;
  END
 END po1[135]
 PIN po1[136]
  DIRECTION INPUT ;
  USE SIGNAL ;
  PORT
   LAYER M4 ;
   RECT 43.008000 128.604000 43.200000 128.628000 ;
  END
 END po1[136]
 PIN po1[137]
  DIRECTION INPUT ;
  USE SIGNAL ;
  PORT
   LAYER M6 ;
   RECT 43.008000 128.752000 43.200000 128.784000 ;
  END
 END po1[137]
 PIN po1[138]
  DIRECTION INPUT ;
  USE SIGNAL ;
  PORT
   LAYER M4 ;
   RECT 43.008000 128.940000 43.200000 128.964000 ;
  END
 END po1[138]
 PIN po1[139]
  DIRECTION INPUT ;
  USE SIGNAL ;
  PORT
   LAYER M6 ;
   RECT 43.008000 129.072000 43.200000 129.104000 ;
  END
 END po1[139]
 PIN po1[140]
  DIRECTION INPUT ;
  USE SIGNAL ;
  PORT
   LAYER M4 ;
   RECT 43.008000 129.276000 43.200000 129.300000 ;
  END
 END po1[140]
 PIN po1[141]
  DIRECTION INPUT ;
  USE SIGNAL ;
  PORT
   LAYER M6 ;
   RECT 43.008000 129.456000 43.200000 129.488000 ;
  END
 END po1[141]
 PIN po1[142]
  DIRECTION INPUT ;
  USE SIGNAL ;
  PORT
   LAYER M4 ;
   RECT 43.008000 129.612000 43.200000 129.636000 ;
  END
 END po1[142]
 PIN po1[143]
  DIRECTION INPUT ;
  USE SIGNAL ;
  PORT
   LAYER M6 ;
   RECT 43.008000 129.776000 43.200000 129.808000 ;
  END
 END po1[143]
 PIN po1[144]
  DIRECTION INPUT ;
  USE SIGNAL ;
  PORT
   LAYER M4 ;
   RECT 43.008000 129.948000 43.200000 129.972000 ;
  END
 END po1[144]
 PIN po1[145]
  DIRECTION INPUT ;
  USE SIGNAL ;
  PORT
   LAYER M6 ;
   RECT 43.008000 130.096000 43.200000 130.128000 ;
  END
 END po1[145]
 PIN po1[146]
  DIRECTION INPUT ;
  USE SIGNAL ;
  PORT
   LAYER M4 ;
   RECT 43.008000 130.284000 43.200000 130.308000 ;
  END
 END po1[146]
 PIN po1[147]
  DIRECTION INPUT ;
  USE SIGNAL ;
  PORT
   LAYER M6 ;
   RECT 43.008000 130.416000 43.200000 130.448000 ;
  END
 END po1[147]
 PIN po1[148]
  DIRECTION INPUT ;
  USE SIGNAL ;
  PORT
   LAYER M4 ;
   RECT 43.008000 130.620000 43.200000 130.644000 ;
  END
 END po1[148]
 PIN po1[149]
  DIRECTION INPUT ;
  USE SIGNAL ;
  PORT
   LAYER M6 ;
   RECT 43.008000 130.736000 43.200000 130.768000 ;
  END
 END po1[149]
 PIN po1[150]
  DIRECTION INPUT ;
  USE SIGNAL ;
  PORT
   LAYER M4 ;
   RECT 43.008000 130.956000 43.200000 130.980000 ;
  END
 END po1[150]
 PIN po1[151]
  DIRECTION INPUT ;
  USE SIGNAL ;
  PORT
   LAYER M6 ;
   RECT 43.008000 131.120000 43.200000 131.152000 ;
  END
 END po1[151]
 PIN po1[152]
  DIRECTION INPUT ;
  USE SIGNAL ;
  PORT
   LAYER M4 ;
   RECT 43.008000 131.292000 43.200000 131.316000 ;
  END
 END po1[152]
 PIN po1[153]
  DIRECTION INPUT ;
  USE SIGNAL ;
  PORT
   LAYER M6 ;
   RECT 43.008000 131.248000 43.200000 131.280000 ;
  END
 END po1[153]
 PIN po1[154]
  DIRECTION INPUT ;
  USE SIGNAL ;
  PORT
   LAYER M4 ;
   RECT 43.008000 131.628000 43.200000 131.652000 ;
  END
 END po1[154]
 PIN po1[155]
  DIRECTION INPUT ;
  USE SIGNAL ;
  PORT
   LAYER M6 ;
   RECT 43.008000 132.272000 43.200000 132.304000 ;
  END
 END po1[155]
 PIN po1[156]
  DIRECTION INPUT ;
  USE SIGNAL ;
  PORT
   LAYER M4 ;
   RECT 43.008000 131.964000 43.200000 131.988000 ;
  END
 END po1[156]
 PIN po1[157]
  DIRECTION INPUT ;
  USE SIGNAL ;
  PORT
   LAYER M6 ;
   RECT 43.008000 132.336000 43.200000 132.368000 ;
  END
 END po1[157]
 PIN po1[158]
  DIRECTION INPUT ;
  USE SIGNAL ;
  PORT
   LAYER M4 ;
   RECT 43.008000 132.300000 43.200000 132.324000 ;
  END
 END po1[158]
 PIN po1[159]
  DIRECTION INPUT ;
  USE SIGNAL ;
  PORT
   LAYER M6 ;
   RECT 43.008000 132.464000 43.200000 132.496000 ;
  END
 END po1[159]
 PIN po1[160]
  DIRECTION INPUT ;
  USE SIGNAL ;
  PORT
   LAYER M4 ;
   RECT 43.008000 132.636000 43.200000 132.660000 ;
  END
 END po1[160]
 PIN po1[161]
  DIRECTION INPUT ;
  USE SIGNAL ;
  PORT
   LAYER M6 ;
   RECT 43.008000 132.784000 43.200000 132.816000 ;
  END
 END po1[161]
 PIN po1[162]
  DIRECTION INPUT ;
  USE SIGNAL ;
  PORT
   LAYER M4 ;
   RECT 43.008000 132.924000 43.200000 132.948000 ;
  END
 END po1[162]
 PIN po1[163]
  DIRECTION INPUT ;
  USE SIGNAL ;
  PORT
   LAYER M6 ;
   RECT 43.008000 133.104000 43.200000 133.136000 ;
  END
 END po1[163]
 PIN po1[164]
  DIRECTION INPUT ;
  USE SIGNAL ;
  PORT
   LAYER M4 ;
   RECT 43.008000 133.260000 43.200000 133.284000 ;
  END
 END po1[164]
 PIN po1[165]
  DIRECTION INPUT ;
  USE SIGNAL ;
  PORT
   LAYER M6 ;
   RECT 43.008000 133.424000 43.200000 133.456000 ;
  END
 END po1[165]
 PIN po1[166]
  DIRECTION INPUT ;
  USE SIGNAL ;
  PORT
   LAYER M4 ;
   RECT 43.008000 133.596000 43.200000 133.620000 ;
  END
 END po1[166]
 PIN po1[167]
  DIRECTION INPUT ;
  USE SIGNAL ;
  PORT
   LAYER M6 ;
   RECT 43.008000 133.744000 43.200000 133.776000 ;
  END
 END po1[167]
 PIN po1[168]
  DIRECTION INPUT ;
  USE SIGNAL ;
  PORT
   LAYER M4 ;
   RECT 43.008000 133.932000 43.200000 133.956000 ;
  END
 END po1[168]
 PIN po1[169]
  DIRECTION INPUT ;
  USE SIGNAL ;
  PORT
   LAYER M6 ;
   RECT 43.008000 134.128000 43.200000 134.160000 ;
  END
 END po1[169]
 PIN po1[170]
  DIRECTION INPUT ;
  USE SIGNAL ;
  PORT
   LAYER M4 ;
   RECT 43.008000 134.268000 43.200000 134.292000 ;
  END
 END po1[170]
 PIN po1[171]
  DIRECTION INPUT ;
  USE SIGNAL ;
  PORT
   LAYER M6 ;
   RECT 43.008000 134.448000 43.200000 134.480000 ;
  END
 END po1[171]
 PIN po1[172]
  DIRECTION INPUT ;
  USE SIGNAL ;
  PORT
   LAYER M4 ;
   RECT 43.008000 134.604000 43.200000 134.628000 ;
  END
 END po1[172]
 PIN po1[173]
  DIRECTION INPUT ;
  USE SIGNAL ;
  PORT
   LAYER M6 ;
   RECT 43.008000 134.768000 43.200000 134.800000 ;
  END
 END po1[173]
 PIN po1[174]
  DIRECTION INPUT ;
  USE SIGNAL ;
  PORT
   LAYER M4 ;
   RECT 43.008000 134.940000 43.200000 134.964000 ;
  END
 END po1[174]
 PIN po1[175]
  DIRECTION INPUT ;
  USE SIGNAL ;
  PORT
   LAYER M6 ;
   RECT 43.008000 135.088000 43.200000 135.120000 ;
  END
 END po1[175]
 PIN po1[176]
  DIRECTION INPUT ;
  USE SIGNAL ;
  PORT
   LAYER M4 ;
   RECT 43.008000 135.276000 43.200000 135.300000 ;
  END
 END po1[176]
 PIN po1[177]
  DIRECTION INPUT ;
  USE SIGNAL ;
  PORT
   LAYER M6 ;
   RECT 43.008000 135.408000 43.200000 135.440000 ;
  END
 END po1[177]
 PIN po1[178]
  DIRECTION INPUT ;
  USE SIGNAL ;
  PORT
   LAYER M4 ;
   RECT 43.008000 135.612000 43.200000 135.636000 ;
  END
 END po1[178]
 PIN po1[179]
  DIRECTION INPUT ;
  USE SIGNAL ;
  PORT
   LAYER M6 ;
   RECT 43.008000 135.472000 43.200000 135.504000 ;
  END
 END po1[179]
 PIN po1[180]
  DIRECTION INPUT ;
  USE SIGNAL ;
  PORT
   LAYER M4 ;
   RECT 43.008000 135.948000 43.200000 135.972000 ;
  END
 END po1[180]
 PIN po1[181]
  DIRECTION INPUT ;
  USE SIGNAL ;
  PORT
   LAYER M6 ;
   RECT 43.008000 135.536000 43.200000 135.568000 ;
  END
 END po1[181]
 PIN po1[182]
  DIRECTION INPUT ;
  USE SIGNAL ;
  PORT
   LAYER M4 ;
   RECT 43.008000 136.284000 43.200000 136.308000 ;
  END
 END po1[182]
 PIN po1[183]
  DIRECTION INPUT ;
  USE SIGNAL ;
  PORT
   LAYER M6 ;
   RECT 43.008000 136.560000 43.200000 136.592000 ;
  END
 END po1[183]
 PIN po1[184]
  DIRECTION INPUT ;
  USE SIGNAL ;
  PORT
   LAYER M4 ;
   RECT 43.008000 136.620000 43.200000 136.644000 ;
  END
 END po1[184]
 PIN po1[185]
  DIRECTION INPUT ;
  USE SIGNAL ;
  PORT
   LAYER M6 ;
   RECT 43.008000 136.816000 43.200000 136.848000 ;
  END
 END po1[185]
 PIN po1[186]
  DIRECTION INPUT ;
  USE SIGNAL ;
  PORT
   LAYER M4 ;
   RECT 43.008000 136.956000 43.200000 136.980000 ;
  END
 END po1[186]
 PIN po1[187]
  DIRECTION INPUT ;
  USE SIGNAL ;
  PORT
   LAYER M6 ;
   RECT 43.008000 137.136000 43.200000 137.168000 ;
  END
 END po1[187]
 PIN po1[188]
  DIRECTION INPUT ;
  USE SIGNAL ;
  PORT
   LAYER M4 ;
   RECT 43.008000 137.244000 43.200000 137.268000 ;
  END
 END po1[188]
 PIN po1[189]
  DIRECTION INPUT ;
  USE SIGNAL ;
  PORT
   LAYER M6 ;
   RECT 43.008000 137.456000 43.200000 137.488000 ;
  END
 END po1[189]
 PIN po1[190]
  DIRECTION INPUT ;
  USE SIGNAL ;
  PORT
   LAYER M4 ;
   RECT 43.008000 137.580000 43.200000 137.604000 ;
  END
 END po1[190]
 PIN po1[191]
  DIRECTION INPUT ;
  USE SIGNAL ;
  PORT
   LAYER M6 ;
   RECT 43.008000 137.776000 43.200000 137.808000 ;
  END
 END po1[191]
 PIN po1[192]
  DIRECTION INPUT ;
  USE SIGNAL ;
  PORT
   LAYER M4 ;
   RECT 43.008000 137.916000 43.200000 137.940000 ;
  END
 END po1[192]
 PIN po1[193]
  DIRECTION INPUT ;
  USE SIGNAL ;
  PORT
   LAYER M6 ;
   RECT 43.008000 138.096000 43.200000 138.128000 ;
  END
 END po1[193]
 PIN po1[194]
  DIRECTION INPUT ;
  USE SIGNAL ;
  PORT
   LAYER M4 ;
   RECT 43.008000 138.252000 43.200000 138.276000 ;
  END
 END po1[194]
 PIN po1[195]
  DIRECTION INPUT ;
  USE SIGNAL ;
  PORT
   LAYER M6 ;
   RECT 43.008000 138.480000 43.200000 138.512000 ;
  END
 END po1[195]
 PIN po1[196]
  DIRECTION INPUT ;
  USE SIGNAL ;
  PORT
   LAYER M4 ;
   RECT 43.008000 138.588000 43.200000 138.612000 ;
  END
 END po1[196]
 PIN po1[197]
  DIRECTION INPUT ;
  USE SIGNAL ;
  PORT
   LAYER M6 ;
   RECT 43.008000 138.800000 43.200000 138.832000 ;
  END
 END po1[197]
 PIN po1[198]
  DIRECTION INPUT ;
  USE SIGNAL ;
  PORT
   LAYER M4 ;
   RECT 43.008000 138.924000 43.200000 138.948000 ;
  END
 END po1[198]
 PIN po1[199]
  DIRECTION INPUT ;
  USE SIGNAL ;
  PORT
   LAYER M6 ;
   RECT 43.008000 139.120000 43.200000 139.152000 ;
  END
 END po1[199]
 PIN po1[200]
  DIRECTION INPUT ;
  USE SIGNAL ;
  PORT
   LAYER M4 ;
   RECT 43.008000 139.260000 43.200000 139.284000 ;
  END
 END po1[200]
 PIN po1[201]
  DIRECTION INPUT ;
  USE SIGNAL ;
  PORT
   LAYER M6 ;
   RECT 43.008000 139.440000 43.200000 139.472000 ;
  END
 END po1[201]
 PIN po1[202]
  DIRECTION INPUT ;
  USE SIGNAL ;
  PORT
   LAYER M4 ;
   RECT 43.008000 139.596000 43.200000 139.620000 ;
  END
 END po1[202]
 PIN po1[203]
  DIRECTION INPUT ;
  USE SIGNAL ;
  PORT
   LAYER M6 ;
   RECT 43.008000 139.760000 43.200000 139.792000 ;
  END
 END po1[203]
 PIN po1[204]
  DIRECTION INPUT ;
  USE SIGNAL ;
  PORT
   LAYER M4 ;
   RECT 43.008000 139.932000 43.200000 139.956000 ;
  END
 END po1[204]
 PIN po1[205]
  DIRECTION INPUT ;
  USE SIGNAL ;
  PORT
   LAYER M6 ;
   RECT 43.008000 139.824000 43.200000 139.856000 ;
  END
 END po1[205]
 PIN po1[206]
  DIRECTION INPUT ;
  USE SIGNAL ;
  PORT
   LAYER M4 ;
   RECT 43.008000 140.268000 43.200000 140.292000 ;
  END
 END po1[206]
 PIN po1[207]
  DIRECTION INPUT ;
  USE SIGNAL ;
  PORT
   LAYER M6 ;
   RECT 43.008000 139.888000 43.200000 139.920000 ;
  END
 END po1[207]
 PIN po1[208]
  DIRECTION INPUT ;
  USE SIGNAL ;
  PORT
   LAYER M4 ;
   RECT 43.008000 140.604000 43.200000 140.628000 ;
  END
 END po1[208]
 PIN po1[209]
  DIRECTION INPUT ;
  USE SIGNAL ;
  PORT
   LAYER M6 ;
   RECT 43.008000 140.912000 43.200000 140.944000 ;
  END
 END po1[209]
 PIN po1[210]
  DIRECTION INPUT ;
  USE SIGNAL ;
  PORT
   LAYER M4 ;
   RECT 43.008000 140.940000 43.200000 140.964000 ;
  END
 END po1[210]
 PIN po1[211]
  DIRECTION INPUT ;
  USE SIGNAL ;
  PORT
   LAYER M6 ;
   RECT 43.008000 141.104000 43.200000 141.136000 ;
  END
 END po1[211]
 PIN po1[212]
  DIRECTION INPUT ;
  USE SIGNAL ;
  PORT
   LAYER M4 ;
   RECT 43.008000 141.276000 43.200000 141.300000 ;
  END
 END po1[212]
 PIN po1[213]
  DIRECTION INPUT ;
  USE SIGNAL ;
  PORT
   LAYER M6 ;
   RECT 43.008000 141.488000 43.200000 141.520000 ;
  END
 END po1[213]
 PIN po1[214]
  DIRECTION INPUT ;
  USE SIGNAL ;
  PORT
   LAYER M4 ;
   RECT 43.008000 141.564000 43.200000 141.588000 ;
  END
 END po1[214]
 PIN po1[215]
  DIRECTION INPUT ;
  USE SIGNAL ;
  PORT
   LAYER M6 ;
   RECT 43.008000 141.808000 43.200000 141.840000 ;
  END
 END po1[215]
 PIN po1[216]
  DIRECTION INPUT ;
  USE SIGNAL ;
  PORT
   LAYER M4 ;
   RECT 43.008000 141.900000 43.200000 141.924000 ;
  END
 END po1[216]
 PIN po1[217]
  DIRECTION INPUT ;
  USE SIGNAL ;
  PORT
   LAYER M6 ;
   RECT 43.008000 142.128000 43.200000 142.160000 ;
  END
 END po1[217]
 PIN po1[218]
  DIRECTION INPUT ;
  USE SIGNAL ;
  PORT
   LAYER M4 ;
   RECT 43.008000 142.236000 43.200000 142.260000 ;
  END
 END po1[218]
 PIN po1[219]
  DIRECTION INPUT ;
  USE SIGNAL ;
  PORT
   LAYER M6 ;
   RECT 43.008000 142.448000 43.200000 142.480000 ;
  END
 END po1[219]
 PIN po1[220]
  DIRECTION INPUT ;
  USE SIGNAL ;
  PORT
   LAYER M4 ;
   RECT 43.008000 142.572000 43.200000 142.596000 ;
  END
 END po1[220]
 PIN po1[221]
  DIRECTION INPUT ;
  USE SIGNAL ;
  PORT
   LAYER M6 ;
   RECT 43.008000 142.832000 43.200000 142.864000 ;
  END
 END po1[221]
 PIN po1[222]
  DIRECTION INPUT ;
  USE SIGNAL ;
  PORT
   LAYER M4 ;
   RECT 43.008000 142.908000 43.200000 142.932000 ;
  END
 END po1[222]
 PIN po1[223]
  DIRECTION INPUT ;
  USE SIGNAL ;
  PORT
   LAYER M6 ;
   RECT 43.008000 143.152000 43.200000 143.184000 ;
  END
 END po1[223]
 PIN po1[224]
  DIRECTION INPUT ;
  USE SIGNAL ;
  PORT
   LAYER M4 ;
   RECT 43.008000 143.244000 43.200000 143.268000 ;
  END
 END po1[224]
 PIN po1[225]
  DIRECTION INPUT ;
  USE SIGNAL ;
  PORT
   LAYER M6 ;
   RECT 43.008000 143.472000 43.200000 143.504000 ;
  END
 END po1[225]
 PIN po1[226]
  DIRECTION INPUT ;
  USE SIGNAL ;
  PORT
   LAYER M4 ;
   RECT 43.008000 143.580000 43.200000 143.604000 ;
  END
 END po1[226]
 PIN po1[227]
  DIRECTION INPUT ;
  USE SIGNAL ;
  PORT
   LAYER M6 ;
   RECT 43.008000 143.792000 43.200000 143.824000 ;
  END
 END po1[227]
 PIN po1[228]
  DIRECTION INPUT ;
  USE SIGNAL ;
  PORT
   LAYER M4 ;
   RECT 43.008000 143.916000 43.200000 143.940000 ;
  END
 END po1[228]
 PIN po1[229]
  DIRECTION INPUT ;
  USE SIGNAL ;
  PORT
   LAYER M6 ;
   RECT 43.008000 144.048000 43.200000 144.080000 ;
  END
 END po1[229]
 PIN po1[230]
  DIRECTION INPUT ;
  USE SIGNAL ;
  PORT
   LAYER M4 ;
   RECT 43.008000 144.252000 43.200000 144.276000 ;
  END
 END po1[230]
 PIN po1[231]
  DIRECTION INPUT ;
  USE SIGNAL ;
  PORT
   LAYER M6 ;
   RECT 43.008000 144.112000 43.200000 144.144000 ;
  END
 END po1[231]
 PIN po1[232]
  DIRECTION INPUT ;
  USE SIGNAL ;
  PORT
   LAYER M4 ;
   RECT 43.008000 144.588000 43.200000 144.612000 ;
  END
 END po1[232]
 PIN po1[233]
  DIRECTION INPUT ;
  USE SIGNAL ;
  PORT
   LAYER M6 ;
   RECT 43.008000 144.176000 43.200000 144.208000 ;
  END
 END po1[233]
 PIN po1[234]
  DIRECTION INPUT ;
  USE SIGNAL ;
  PORT
   LAYER M4 ;
   RECT 43.008000 144.924000 43.200000 144.948000 ;
  END
 END po1[234]
 PIN po1[235]
  DIRECTION INPUT ;
  USE SIGNAL ;
  PORT
   LAYER M6 ;
   RECT 43.008000 145.200000 43.200000 145.232000 ;
  END
 END po1[235]
 PIN po1[236]
  DIRECTION INPUT ;
  USE SIGNAL ;
  PORT
   LAYER M4 ;
   RECT 43.008000 145.260000 43.200000 145.284000 ;
  END
 END po1[236]
 PIN po1[237]
  DIRECTION INPUT ;
  USE SIGNAL ;
  PORT
   LAYER M6 ;
   RECT 43.008000 145.456000 43.200000 145.488000 ;
  END
 END po1[237]
 PIN po1[238]
  DIRECTION INPUT ;
  USE SIGNAL ;
  PORT
   LAYER M4 ;
   RECT 43.008000 145.596000 43.200000 145.620000 ;
  END
 END po1[238]
 PIN po1[239]
  DIRECTION INPUT ;
  USE SIGNAL ;
  PORT
   LAYER M6 ;
   RECT 43.008000 145.840000 43.200000 145.872000 ;
  END
 END po1[239]
 PIN po1[240]
  DIRECTION INPUT ;
  USE SIGNAL ;
  PORT
   LAYER M4 ;
   RECT 43.008000 145.932000 43.200000 145.956000 ;
  END
 END po1[240]
 PIN po1[241]
  DIRECTION INPUT ;
  USE SIGNAL ;
  PORT
   LAYER M6 ;
   RECT 43.008000 146.160000 43.200000 146.192000 ;
  END
 END po1[241]
 PIN po1[242]
  DIRECTION INPUT ;
  USE SIGNAL ;
  PORT
   LAYER M4 ;
   RECT 43.008000 146.220000 43.200000 146.244000 ;
  END
 END po1[242]
 PIN po1[243]
  DIRECTION INPUT ;
  USE SIGNAL ;
  PORT
   LAYER M6 ;
   RECT 43.008000 146.480000 43.200000 146.512000 ;
  END
 END po1[243]
 PIN po1[244]
  DIRECTION INPUT ;
  USE SIGNAL ;
  PORT
   LAYER M4 ;
   RECT 43.008000 146.556000 43.200000 146.580000 ;
  END
 END po1[244]
 PIN po1[245]
  DIRECTION INPUT ;
  USE SIGNAL ;
  PORT
   LAYER M6 ;
   RECT 43.008000 146.800000 43.200000 146.832000 ;
  END
 END po1[245]
 PIN po1[246]
  DIRECTION INPUT ;
  USE SIGNAL ;
  PORT
   LAYER M4 ;
   RECT 43.008000 146.892000 43.200000 146.916000 ;
  END
 END po1[246]
 PIN po1[247]
  DIRECTION INPUT ;
  USE SIGNAL ;
  PORT
   LAYER M6 ;
   RECT 43.008000 147.184000 43.200000 147.216000 ;
  END
 END po1[247]
 PIN po1[248]
  DIRECTION INPUT ;
  USE SIGNAL ;
  PORT
   LAYER M4 ;
   RECT 43.008000 147.228000 43.200000 147.252000 ;
  END
 END po1[248]
 PIN po1[249]
  DIRECTION INPUT ;
  USE SIGNAL ;
  PORT
   LAYER M6 ;
   RECT 43.008000 147.504000 43.200000 147.536000 ;
  END
 END po1[249]
 PIN po1[250]
  DIRECTION INPUT ;
  USE SIGNAL ;
  PORT
   LAYER M4 ;
   RECT 43.008000 147.564000 43.200000 147.588000 ;
  END
 END po1[250]
 PIN po1[251]
  DIRECTION INPUT ;
  USE SIGNAL ;
  PORT
   LAYER M6 ;
   RECT 43.008000 147.824000 43.200000 147.856000 ;
  END
 END po1[251]
 PIN po1[252]
  DIRECTION INPUT ;
  USE SIGNAL ;
  PORT
   LAYER M4 ;
   RECT 43.008000 147.900000 43.200000 147.924000 ;
  END
 END po1[252]
 PIN po1[253]
  DIRECTION INPUT ;
  USE SIGNAL ;
  PORT
   LAYER M6 ;
   RECT 43.008000 148.144000 43.200000 148.176000 ;
  END
 END po1[253]
 PIN po1[254]
  DIRECTION INPUT ;
  USE SIGNAL ;
  PORT
   LAYER M4 ;
   RECT 43.008000 148.236000 43.200000 148.260000 ;
  END
 END po1[254]
 PIN po1[255]
  DIRECTION INPUT ;
  USE SIGNAL ;
  PORT
   LAYER M6 ;
   RECT 43.008000 148.400000 43.200000 148.432000 ;
  END
 END po1[255]
 PIN po1[256]
  DIRECTION INPUT ;
  USE SIGNAL ;
  PORT
   LAYER M4 ;
   RECT 43.008000 148.572000 43.200000 148.596000 ;
  END
 END po1[256]
 PIN po1[257]
  DIRECTION INPUT ;
  USE SIGNAL ;
  PORT
   LAYER M6 ;
   RECT 43.008000 148.464000 43.200000 148.496000 ;
  END
 END po1[257]
 PIN po1[258]
  DIRECTION INPUT ;
  USE SIGNAL ;
  PORT
   LAYER M4 ;
   RECT 43.008000 148.908000 43.200000 148.932000 ;
  END
 END po1[258]
 PIN po1[259]
  DIRECTION INPUT ;
  USE SIGNAL ;
  PORT
   LAYER M6 ;
   RECT 43.008000 148.528000 43.200000 148.560000 ;
  END
 END po1[259]
 PIN po1[260]
  DIRECTION INPUT ;
  USE SIGNAL ;
  PORT
   LAYER M4 ;
   RECT 43.008000 149.244000 43.200000 149.268000 ;
  END
 END po1[260]
 PIN po1[261]
  DIRECTION INPUT ;
  USE SIGNAL ;
  PORT
   LAYER M6 ;
   RECT 43.008000 149.552000 43.200000 149.584000 ;
  END
 END po1[261]
 PIN po1[262]
  DIRECTION INPUT ;
  USE SIGNAL ;
  PORT
   LAYER M4 ;
   RECT 43.008000 149.580000 43.200000 149.604000 ;
  END
 END po1[262]
 PIN po1[263]
  DIRECTION INPUT ;
  USE SIGNAL ;
  PORT
   LAYER M6 ;
   RECT 43.008000 149.808000 43.200000 149.840000 ;
  END
 END po1[263]
 PIN po1[264]
  DIRECTION INPUT ;
  USE SIGNAL ;
  PORT
   LAYER M4 ;
   RECT 43.008000 149.916000 43.200000 149.940000 ;
  END
 END po1[264]
 PIN po1[265]
  DIRECTION INPUT ;
  USE SIGNAL ;
  PORT
   LAYER M6 ;
   RECT 43.008000 150.192000 43.200000 150.224000 ;
  END
 END po1[265]
 PIN po1[266]
  DIRECTION INPUT ;
  USE SIGNAL ;
  PORT
   LAYER M4 ;
   RECT 43.008000 150.252000 43.200000 150.276000 ;
  END
 END po1[266]
 PIN po1[267]
  DIRECTION INPUT ;
  USE SIGNAL ;
  PORT
   LAYER M6 ;
   RECT 43.008000 150.512000 43.200000 150.544000 ;
  END
 END po1[267]
 PIN po1[268]
  DIRECTION INPUT ;
  USE SIGNAL ;
  PORT
   LAYER M4 ;
   RECT 43.008000 150.540000 43.200000 150.564000 ;
  END
 END po1[268]
 PIN po1[269]
  DIRECTION INPUT ;
  USE SIGNAL ;
  PORT
   LAYER M6 ;
   RECT 43.008000 150.832000 43.200000 150.864000 ;
  END
 END po1[269]
 PIN po1[270]
  DIRECTION INPUT ;
  USE SIGNAL ;
  PORT
   LAYER M4 ;
   RECT 43.008000 150.876000 43.200000 150.900000 ;
  END
 END po1[270]
 PIN po1[271]
  DIRECTION INPUT ;
  USE SIGNAL ;
  PORT
   LAYER M6 ;
   RECT 43.008000 151.152000 43.200000 151.184000 ;
  END
 END po1[271]
 PIN po1[272]
  DIRECTION INPUT ;
  USE SIGNAL ;
  PORT
   LAYER M4 ;
   RECT 43.008000 151.212000 43.200000 151.236000 ;
  END
 END po1[272]
 PIN po1[273]
  DIRECTION INPUT ;
  USE SIGNAL ;
  PORT
   LAYER M6 ;
   RECT 43.008000 151.472000 43.200000 151.504000 ;
  END
 END po1[273]
 PIN po1[274]
  DIRECTION INPUT ;
  USE SIGNAL ;
  PORT
   LAYER M4 ;
   RECT 43.008000 151.548000 43.200000 151.572000 ;
  END
 END po1[274]
 PIN po1[275]
  DIRECTION INPUT ;
  USE SIGNAL ;
  PORT
   LAYER M6 ;
   RECT 43.008000 151.856000 43.200000 151.888000 ;
  END
 END po1[275]
 PIN po1[276]
  DIRECTION INPUT ;
  USE SIGNAL ;
  PORT
   LAYER M4 ;
   RECT 43.008000 151.884000 43.200000 151.908000 ;
  END
 END po1[276]
 PIN po1[277]
  DIRECTION INPUT ;
  USE SIGNAL ;
  PORT
   LAYER M6 ;
   RECT 43.008000 152.176000 43.200000 152.208000 ;
  END
 END po1[277]
 PIN po1[278]
  DIRECTION INPUT ;
  USE SIGNAL ;
  PORT
   LAYER M4 ;
   RECT 43.008000 152.220000 43.200000 152.244000 ;
  END
 END po1[278]
 PIN po1[279]
  DIRECTION INPUT ;
  USE SIGNAL ;
  PORT
   LAYER M6 ;
   RECT 43.008000 152.496000 43.200000 152.528000 ;
  END
 END po1[279]
 PIN po1[280]
  DIRECTION INPUT ;
  USE SIGNAL ;
  PORT
   LAYER M4 ;
   RECT 43.008000 152.556000 43.200000 152.580000 ;
  END
 END po1[280]
 PIN po1[281]
  DIRECTION INPUT ;
  USE SIGNAL ;
  PORT
   LAYER M6 ;
   RECT 43.008000 152.688000 43.200000 152.720000 ;
  END
 END po1[281]
 PIN po1[282]
  DIRECTION INPUT ;
  USE SIGNAL ;
  PORT
   LAYER M4 ;
   RECT 43.008000 152.892000 43.200000 152.916000 ;
  END
 END po1[282]
 PIN po1[283]
  DIRECTION INPUT ;
  USE SIGNAL ;
  PORT
   LAYER M6 ;
   RECT 43.008000 152.752000 43.200000 152.784000 ;
  END
 END po1[283]
 PIN po1[284]
  DIRECTION INPUT ;
  USE SIGNAL ;
  PORT
   LAYER M4 ;
   RECT 43.008000 153.228000 43.200000 153.252000 ;
  END
 END po1[284]
 PIN po1[285]
  DIRECTION INPUT ;
  USE SIGNAL ;
  PORT
   LAYER M6 ;
   RECT 43.008000 152.816000 43.200000 152.848000 ;
  END
 END po1[285]
 PIN po1[286]
  DIRECTION INPUT ;
  USE SIGNAL ;
  PORT
   LAYER M4 ;
   RECT 43.008000 153.564000 43.200000 153.588000 ;
  END
 END po1[286]
 PIN po1[287]
  DIRECTION INPUT ;
  USE SIGNAL ;
  PORT
   LAYER M6 ;
   RECT 43.008000 153.840000 43.200000 153.872000 ;
  END
 END po1[287]
 PIN po1[288]
  DIRECTION INPUT ;
  USE SIGNAL ;
  PORT
   LAYER M4 ;
   RECT 43.008000 153.900000 43.200000 153.924000 ;
  END
 END po1[288]
 PIN po1[289]
  DIRECTION INPUT ;
  USE SIGNAL ;
  PORT
   LAYER M6 ;
   RECT 43.008000 154.160000 43.200000 154.192000 ;
  END
 END po1[289]
 PIN po1[290]
  DIRECTION INPUT ;
  USE SIGNAL ;
  PORT
   LAYER M4 ;
   RECT 43.008000 154.236000 43.200000 154.260000 ;
  END
 END po1[290]
 PIN po1[291]
  DIRECTION INPUT ;
  USE SIGNAL ;
  PORT
   LAYER M6 ;
   RECT 43.008000 154.480000 43.200000 154.512000 ;
  END
 END po1[291]
 PIN po1[292]
  DIRECTION INPUT ;
  USE SIGNAL ;
  PORT
   LAYER M4 ;
   RECT 43.008000 154.572000 43.200000 154.596000 ;
  END
 END po1[292]
 PIN po1[293]
  DIRECTION INPUT ;
  USE SIGNAL ;
  PORT
   LAYER M6 ;
   RECT 43.008000 154.864000 43.200000 154.896000 ;
  END
 END po1[293]
 PIN po1[294]
  DIRECTION INPUT ;
  USE SIGNAL ;
  PORT
   LAYER M4 ;
   RECT 43.008000 154.908000 43.200000 154.932000 ;
  END
 END po1[294]
 PIN po1[295]
  DIRECTION INPUT ;
  USE SIGNAL ;
  PORT
   LAYER M6 ;
   RECT 43.008000 155.184000 43.200000 155.216000 ;
  END
 END po1[295]
 PIN po1[296]
  DIRECTION INPUT ;
  USE SIGNAL ;
  PORT
   LAYER M4 ;
   RECT 43.008000 155.196000 43.200000 155.220000 ;
  END
 END po1[296]
 PIN po1[297]
  DIRECTION INPUT ;
  USE SIGNAL ;
  PORT
   LAYER M6 ;
   RECT 43.008000 155.504000 43.200000 155.536000 ;
  END
 END po1[297]
 PIN po1[298]
  DIRECTION INPUT ;
  USE SIGNAL ;
  PORT
   LAYER M4 ;
   RECT 43.008000 155.532000 43.200000 155.556000 ;
  END
 END po1[298]
 PIN po1[299]
  DIRECTION INPUT ;
  USE SIGNAL ;
  PORT
   LAYER M6 ;
   RECT 43.008000 155.824000 43.200000 155.856000 ;
  END
 END po1[299]
 PIN po1[300]
  DIRECTION INPUT ;
  USE SIGNAL ;
  PORT
   LAYER M4 ;
   RECT 43.008000 155.868000 43.200000 155.892000 ;
  END
 END po1[300]
 PIN po1[301]
  DIRECTION INPUT ;
  USE SIGNAL ;
  PORT
   LAYER M6 ;
   RECT 43.008000 156.208000 43.200000 156.240000 ;
  END
 END po1[301]
 PIN po1[302]
  DIRECTION INPUT ;
  USE SIGNAL ;
  PORT
   LAYER M4 ;
   RECT 43.008000 156.204000 43.200000 156.228000 ;
  END
 END po1[302]
 PIN po1[303]
  DIRECTION INPUT ;
  USE SIGNAL ;
  PORT
   LAYER M6 ;
   RECT 43.008000 156.528000 43.200000 156.560000 ;
  END
 END po1[303]
 PIN po1[304]
  DIRECTION INPUT ;
  USE SIGNAL ;
  PORT
   LAYER M4 ;
   RECT 43.008000 156.540000 43.200000 156.564000 ;
  END
 END po1[304]
 PIN po1[305]
  DIRECTION INPUT ;
  USE SIGNAL ;
  PORT
   LAYER M6 ;
   RECT 43.008000 156.848000 43.200000 156.880000 ;
  END
 END po1[305]
 PIN po1[306]
  DIRECTION INPUT ;
  USE SIGNAL ;
  PORT
   LAYER M4 ;
   RECT 43.008000 156.876000 43.200000 156.900000 ;
  END
 END po1[306]
 PIN po1[307]
  DIRECTION INPUT ;
  USE SIGNAL ;
  PORT
   LAYER M6 ;
   RECT 43.008000 157.040000 43.200000 157.072000 ;
  END
 END po1[307]
 PIN po1[308]
  DIRECTION INPUT ;
  USE SIGNAL ;
  PORT
   LAYER M4 ;
   RECT 43.008000 157.212000 43.200000 157.236000 ;
  END
 END po1[308]
 PIN po1[309]
  DIRECTION INPUT ;
  USE SIGNAL ;
  PORT
   LAYER M6 ;
   RECT 43.008000 157.104000 43.200000 157.136000 ;
  END
 END po1[309]
 PIN po1[310]
  DIRECTION INPUT ;
  USE SIGNAL ;
  PORT
   LAYER M4 ;
   RECT 43.008000 157.548000 43.200000 157.572000 ;
  END
 END po1[310]
 PIN po1[311]
  DIRECTION INPUT ;
  USE SIGNAL ;
  PORT
   LAYER M6 ;
   RECT 43.008000 157.168000 43.200000 157.200000 ;
  END
 END po1[311]
 PIN po1[312]
  DIRECTION INPUT ;
  USE SIGNAL ;
  PORT
   LAYER M4 ;
   RECT 43.008000 157.884000 43.200000 157.908000 ;
  END
 END po1[312]
 PIN po1[313]
  DIRECTION INPUT ;
  USE SIGNAL ;
  PORT
   LAYER M6 ;
   RECT 43.008000 158.192000 43.200000 158.224000 ;
  END
 END po1[313]
 PIN po1[314]
  DIRECTION INPUT ;
  USE SIGNAL ;
  PORT
   LAYER M4 ;
   RECT 43.008000 158.220000 43.200000 158.244000 ;
  END
 END po1[314]
 PIN po1[315]
  DIRECTION INPUT ;
  USE SIGNAL ;
  PORT
   LAYER M6 ;
   RECT 43.008000 158.512000 43.200000 158.544000 ;
  END
 END po1[315]
 PIN po1[316]
  DIRECTION INPUT ;
  USE SIGNAL ;
  PORT
   LAYER M4 ;
   RECT 43.008000 158.556000 43.200000 158.580000 ;
  END
 END po1[316]
 PIN po1[317]
  DIRECTION INPUT ;
  USE SIGNAL ;
  PORT
   LAYER M6 ;
   RECT 43.008000 158.832000 43.200000 158.864000 ;
  END
 END po1[317]
 PIN po1[318]
  DIRECTION INPUT ;
  USE SIGNAL ;
  PORT
   LAYER M4 ;
   RECT 43.008000 158.892000 43.200000 158.916000 ;
  END
 END po1[318]
 PIN po1[319]
  DIRECTION INPUT ;
  USE SIGNAL ;
  PORT
   LAYER M6 ;
   RECT 43.008000 159.216000 43.200000 159.248000 ;
  END
 END po1[319]
 PIN po1[320]
  DIRECTION INPUT ;
  USE SIGNAL ;
  PORT
   LAYER M4 ;
   RECT 43.008000 159.228000 43.200000 159.252000 ;
  END
 END po1[320]
 PIN po1[321]
  DIRECTION INPUT ;
  USE SIGNAL ;
  PORT
   LAYER M6 ;
   RECT 43.008000 159.536000 43.200000 159.568000 ;
  END
 END po1[321]
 PIN po1[322]
  DIRECTION INPUT ;
  USE SIGNAL ;
  PORT
   LAYER M4 ;
   RECT 43.008000 159.516000 43.200000 159.540000 ;
  END
 END po1[322]
 PIN po1[323]
  DIRECTION INPUT ;
  USE SIGNAL ;
  PORT
   LAYER M6 ;
   RECT 43.008000 159.856000 43.200000 159.888000 ;
  END
 END po1[323]
 PIN po1[324]
  DIRECTION INPUT ;
  USE SIGNAL ;
  PORT
   LAYER M4 ;
   RECT 43.008000 159.852000 43.200000 159.876000 ;
  END
 END po1[324]
 PIN po1[325]
  DIRECTION INPUT ;
  USE SIGNAL ;
  PORT
   LAYER M6 ;
   RECT 43.008000 160.176000 43.200000 160.208000 ;
  END
 END po1[325]
 PIN po1[326]
  DIRECTION INPUT ;
  USE SIGNAL ;
  PORT
   LAYER M4 ;
   RECT 43.008000 160.188000 43.200000 160.212000 ;
  END
 END po1[326]
 PIN po1[327]
  DIRECTION INPUT ;
  USE SIGNAL ;
  PORT
   LAYER M6 ;
   RECT 43.008000 160.560000 43.200000 160.592000 ;
  END
 END po1[327]
 PIN pi1[0]
  DIRECTION OUTPUT ;
  USE SIGNAL ;
  PORT
   LAYER M6 ;
   RECT 43.008000 419.440000 43.200000 419.472000 ;
  END
 END pi1[0]
 PIN pi1[1]
  DIRECTION OUTPUT ;
  USE SIGNAL ;
  PORT
   LAYER M4 ;
   RECT 43.008000 419.772000 43.200000 419.796000 ;
  END
 END pi1[1]
 PIN pi1[2]
  DIRECTION OUTPUT ;
  USE SIGNAL ;
  PORT
   LAYER M6 ;
   RECT 43.008000 419.760000 43.200000 419.792000 ;
  END
 END pi1[2]
 PIN pi1[3]
  DIRECTION OUTPUT ;
  USE SIGNAL ;
  PORT
   LAYER M4 ;
   RECT 43.008000 420.108000 43.200000 420.132000 ;
  END
 END pi1[3]
 PIN pi1[4]
  DIRECTION OUTPUT ;
  USE SIGNAL ;
  PORT
   LAYER M4 ;
   RECT 43.008000 445.116000 43.200000 445.140000 ;
  END
 END pi1[4]
 PIN pi1[5]
  DIRECTION OUTPUT ;
  USE SIGNAL ;
  PORT
   LAYER M6 ;
   RECT 43.008000 444.976000 43.200000 445.008000 ;
  END
 END pi1[5]
 PIN pi1[6]
  DIRECTION OUTPUT ;
  USE SIGNAL ;
  PORT
   LAYER M4 ;
   RECT 43.008000 445.452000 43.200000 445.476000 ;
  END
 END pi1[6]
 PIN pi1[7]
  DIRECTION OUTPUT ;
  USE SIGNAL ;
  PORT
   LAYER M6 ;
   RECT 43.008000 445.232000 43.200000 445.264000 ;
  END
 END pi1[7]
 PIN pi1[8]
  DIRECTION OUTPUT ;
  USE SIGNAL ;
  PORT
   LAYER M4 ;
   RECT 43.008000 445.788000 43.200000 445.812000 ;
  END
 END pi1[8]
 PIN pi1[9]
  DIRECTION OUTPUT ;
  USE SIGNAL ;
  PORT
   LAYER M6 ;
   RECT 43.008000 445.488000 43.200000 445.520000 ;
  END
 END pi1[9]
 PIN pi1[10]
  DIRECTION OUTPUT ;
  USE SIGNAL ;
  PORT
   LAYER M4 ;
   RECT 43.008000 446.124000 43.200000 446.148000 ;
  END
 END pi1[10]
 PIN pi1[11]
  DIRECTION OUTPUT ;
  USE SIGNAL ;
  PORT
   LAYER M6 ;
   RECT 43.008000 445.744000 43.200000 445.776000 ;
  END
 END pi1[11]
 PIN pi1[12]
  DIRECTION OUTPUT ;
  USE SIGNAL ;
  PORT
   LAYER M4 ;
   RECT 43.008000 446.460000 43.200000 446.484000 ;
  END
 END pi1[12]
 PIN pi1[13]
  DIRECTION OUTPUT ;
  USE SIGNAL ;
  PORT
   LAYER M6 ;
   RECT 43.008000 446.000000 43.200000 446.032000 ;
  END
 END pi1[13]
 PIN pi1[14]
  DIRECTION OUTPUT ;
  USE SIGNAL ;
  PORT
   LAYER M4 ;
   RECT 43.008000 446.796000 43.200000 446.820000 ;
  END
 END pi1[14]
 PIN pi1[15]
  DIRECTION OUTPUT ;
  USE SIGNAL ;
  PORT
   LAYER M6 ;
   RECT 43.008000 446.256000 43.200000 446.288000 ;
  END
 END pi1[15]
 PIN pi1[16]
  DIRECTION OUTPUT ;
  USE SIGNAL ;
  PORT
   LAYER M4 ;
   RECT 43.008000 447.132000 43.200000 447.156000 ;
  END
 END pi1[16]
 PIN pi1[17]
  DIRECTION OUTPUT ;
  USE SIGNAL ;
  PORT
   LAYER M6 ;
   RECT 43.008000 446.512000 43.200000 446.544000 ;
  END
 END pi1[17]
 PIN pi1[18]
  DIRECTION OUTPUT ;
  USE SIGNAL ;
  PORT
   LAYER M4 ;
   RECT 43.008000 447.468000 43.200000 447.492000 ;
  END
 END pi1[18]
 PIN pi1[19]
  DIRECTION OUTPUT ;
  USE SIGNAL ;
  PORT
   LAYER M6 ;
   RECT 43.008000 447.728000 43.200000 447.760000 ;
  END
 END pi1[19]
 PIN pi1[20]
  DIRECTION OUTPUT ;
  USE SIGNAL ;
  PORT
   LAYER M4 ;
   RECT 43.008000 447.804000 43.200000 447.828000 ;
  END
 END pi1[20]
 PIN pi1[21]
  DIRECTION OUTPUT ;
  USE SIGNAL ;
  PORT
   LAYER M6 ;
   RECT 43.008000 447.984000 43.200000 448.016000 ;
  END
 END pi1[21]
 PIN pi1[22]
  DIRECTION OUTPUT ;
  USE SIGNAL ;
  PORT
   LAYER M4 ;
   RECT 43.008000 448.140000 43.200000 448.164000 ;
  END
 END pi1[22]
 PIN pi1[23]
  DIRECTION OUTPUT ;
  USE SIGNAL ;
  PORT
   LAYER M6 ;
   RECT 43.008000 448.240000 43.200000 448.272000 ;
  END
 END pi1[23]
 PIN pi1[24]
  DIRECTION OUTPUT ;
  USE SIGNAL ;
  PORT
   LAYER M4 ;
   RECT 43.008000 448.476000 43.200000 448.500000 ;
  END
 END pi1[24]
 PIN pi1[25]
  DIRECTION OUTPUT ;
  USE SIGNAL ;
  PORT
   LAYER M6 ;
   RECT 43.008000 448.496000 43.200000 448.528000 ;
  END
 END pi1[25]
 PIN pi1[26]
  DIRECTION OUTPUT ;
  USE SIGNAL ;
  PORT
   LAYER M4 ;
   RECT 43.008000 448.812000 43.200000 448.836000 ;
  END
 END pi1[26]
 PIN pi1[27]
  DIRECTION OUTPUT ;
  USE SIGNAL ;
  PORT
   LAYER M6 ;
   RECT 43.008000 448.816000 43.200000 448.848000 ;
  END
 END pi1[27]
 PIN pi1[28]
  DIRECTION OUTPUT ;
  USE SIGNAL ;
  PORT
   LAYER M4 ;
   RECT 43.008000 449.148000 43.200000 449.172000 ;
  END
 END pi1[28]
 PIN pi1[29]
  DIRECTION OUTPUT ;
  USE SIGNAL ;
  PORT
   LAYER M6 ;
   RECT 43.008000 449.072000 43.200000 449.104000 ;
  END
 END pi1[29]
 PIN pi1[30]
  DIRECTION OUTPUT ;
  USE SIGNAL ;
  PORT
   LAYER M4 ;
   RECT 43.008000 449.484000 43.200000 449.508000 ;
  END
 END pi1[30]
 PIN pi1[31]
  DIRECTION OUTPUT ;
  USE SIGNAL ;
  PORT
   LAYER M6 ;
   RECT 43.008000 449.328000 43.200000 449.360000 ;
  END
 END pi1[31]
 PIN pi1[32]
  DIRECTION OUTPUT ;
  USE SIGNAL ;
  PORT
   LAYER M4 ;
   RECT 43.008000 449.820000 43.200000 449.844000 ;
  END
 END pi1[32]
 PIN pi1[33]
  DIRECTION OUTPUT ;
  USE SIGNAL ;
  PORT
   LAYER M6 ;
   RECT 43.008000 449.584000 43.200000 449.616000 ;
  END
 END pi1[33]
 PIN pi1[34]
  DIRECTION OUTPUT ;
  USE SIGNAL ;
  PORT
   LAYER M4 ;
   RECT 43.008000 450.156000 43.200000 450.180000 ;
  END
 END pi1[34]
 PIN pi1[35]
  DIRECTION OUTPUT ;
  USE SIGNAL ;
  PORT
   LAYER M6 ;
   RECT 43.008000 449.840000 43.200000 449.872000 ;
  END
 END pi1[35]
 PIN pi1[36]
  DIRECTION OUTPUT ;
  USE SIGNAL ;
  PORT
   LAYER M4 ;
   RECT 43.008000 450.444000 43.200000 450.468000 ;
  END
 END pi1[36]
 PIN pi1[37]
  DIRECTION OUTPUT ;
  USE SIGNAL ;
  PORT
   LAYER M6 ;
   RECT 43.008000 450.096000 43.200000 450.128000 ;
  END
 END pi1[37]
 PIN pi1[38]
  DIRECTION OUTPUT ;
  USE SIGNAL ;
  PORT
   LAYER M4 ;
   RECT 43.008000 450.780000 43.200000 450.804000 ;
  END
 END pi1[38]
 PIN pi1[39]
  DIRECTION OUTPUT ;
  USE SIGNAL ;
  PORT
   LAYER M6 ;
   RECT 43.008000 450.352000 43.200000 450.384000 ;
  END
 END pi1[39]
 PIN pi1[40]
  DIRECTION OUTPUT ;
  USE SIGNAL ;
  PORT
   LAYER M4 ;
   RECT 43.008000 451.116000 43.200000 451.140000 ;
  END
 END pi1[40]
 PIN pi1[41]
  DIRECTION OUTPUT ;
  USE SIGNAL ;
  PORT
   LAYER M6 ;
   RECT 43.008000 450.608000 43.200000 450.640000 ;
  END
 END pi1[41]
 PIN pi1[42]
  DIRECTION OUTPUT ;
  USE SIGNAL ;
  PORT
   LAYER M4 ;
   RECT 43.008000 451.452000 43.200000 451.476000 ;
  END
 END pi1[42]
 PIN pi1[43]
  DIRECTION OUTPUT ;
  USE SIGNAL ;
  PORT
   LAYER M6 ;
   RECT 43.008000 450.864000 43.200000 450.896000 ;
  END
 END pi1[43]
 PIN pi1[44]
  DIRECTION OUTPUT ;
  USE SIGNAL ;
  PORT
   LAYER M4 ;
   RECT 43.008000 451.788000 43.200000 451.812000 ;
  END
 END pi1[44]
 PIN pi1[45]
  DIRECTION OUTPUT ;
  USE SIGNAL ;
  PORT
   LAYER M6 ;
   RECT 43.008000 452.080000 43.200000 452.112000 ;
  END
 END pi1[45]
 PIN pi1[46]
  DIRECTION OUTPUT ;
  USE SIGNAL ;
  PORT
   LAYER M4 ;
   RECT 43.008000 452.124000 43.200000 452.148000 ;
  END
 END pi1[46]
 PIN pi1[47]
  DIRECTION OUTPUT ;
  USE SIGNAL ;
  PORT
   LAYER M6 ;
   RECT 43.008000 452.400000 43.200000 452.432000 ;
  END
 END pi1[47]
 PIN pi1[48]
  DIRECTION OUTPUT ;
  USE SIGNAL ;
  PORT
   LAYER M4 ;
   RECT 43.008000 452.460000 43.200000 452.484000 ;
  END
 END pi1[48]
 PIN pi1[49]
  DIRECTION OUTPUT ;
  USE SIGNAL ;
  PORT
   LAYER M6 ;
   RECT 43.008000 452.656000 43.200000 452.688000 ;
  END
 END pi1[49]
 PIN pi1[50]
  DIRECTION OUTPUT ;
  USE SIGNAL ;
  PORT
   LAYER M4 ;
   RECT 43.008000 452.796000 43.200000 452.820000 ;
  END
 END pi1[50]
 PIN pi1[51]
  DIRECTION OUTPUT ;
  USE SIGNAL ;
  PORT
   LAYER M6 ;
   RECT 43.008000 452.912000 43.200000 452.944000 ;
  END
 END pi1[51]
 PIN pi1[52]
  DIRECTION OUTPUT ;
  USE SIGNAL ;
  PORT
   LAYER M4 ;
   RECT 43.008000 453.132000 43.200000 453.156000 ;
  END
 END pi1[52]
 PIN pi1[53]
  DIRECTION OUTPUT ;
  USE SIGNAL ;
  PORT
   LAYER M6 ;
   RECT 43.008000 453.168000 43.200000 453.200000 ;
  END
 END pi1[53]
 PIN pi1[54]
  DIRECTION OUTPUT ;
  USE SIGNAL ;
  PORT
   LAYER M4 ;
   RECT 43.008000 453.468000 43.200000 453.492000 ;
  END
 END pi1[54]
 PIN pi1[55]
  DIRECTION OUTPUT ;
  USE SIGNAL ;
  PORT
   LAYER M6 ;
   RECT 43.008000 453.424000 43.200000 453.456000 ;
  END
 END pi1[55]
 PIN pi1[56]
  DIRECTION OUTPUT ;
  USE SIGNAL ;
  PORT
   LAYER M4 ;
   RECT 43.008000 453.804000 43.200000 453.828000 ;
  END
 END pi1[56]
 PIN pi1[57]
  DIRECTION OUTPUT ;
  USE SIGNAL ;
  PORT
   LAYER M6 ;
   RECT 43.008000 453.680000 43.200000 453.712000 ;
  END
 END pi1[57]
 PIN pi1[58]
  DIRECTION OUTPUT ;
  USE SIGNAL ;
  PORT
   LAYER M4 ;
   RECT 43.008000 454.140000 43.200000 454.164000 ;
  END
 END pi1[58]
 PIN pi1[59]
  DIRECTION OUTPUT ;
  USE SIGNAL ;
  PORT
   LAYER M6 ;
   RECT 43.008000 453.936000 43.200000 453.968000 ;
  END
 END pi1[59]
 PIN pi1[60]
  DIRECTION OUTPUT ;
  USE SIGNAL ;
  PORT
   LAYER M4 ;
   RECT 43.008000 454.476000 43.200000 454.500000 ;
  END
 END pi1[60]
 PIN pi1[61]
  DIRECTION OUTPUT ;
  USE SIGNAL ;
  PORT
   LAYER M6 ;
   RECT 43.008000 454.192000 43.200000 454.224000 ;
  END
 END pi1[61]
 PIN pi1[62]
  DIRECTION OUTPUT ;
  USE SIGNAL ;
  PORT
   LAYER M4 ;
   RECT 43.008000 454.812000 43.200000 454.836000 ;
  END
 END pi1[62]
 PIN pi1[63]
  DIRECTION OUTPUT ;
  USE SIGNAL ;
  PORT
   LAYER M6 ;
   RECT 43.008000 454.448000 43.200000 454.480000 ;
  END
 END pi1[63]
 PIN pi1[64]
  DIRECTION OUTPUT ;
  USE SIGNAL ;
  PORT
   LAYER M4 ;
   RECT 43.008000 455.148000 43.200000 455.172000 ;
  END
 END pi1[64]
 PIN pi1[65]
  DIRECTION OUTPUT ;
  USE SIGNAL ;
  PORT
   LAYER M6 ;
   RECT 43.008000 454.704000 43.200000 454.736000 ;
  END
 END pi1[65]
 PIN pi1[66]
  DIRECTION OUTPUT ;
  USE SIGNAL ;
  PORT
   LAYER M4 ;
   RECT 43.008000 455.484000 43.200000 455.508000 ;
  END
 END pi1[66]
 PIN pi1[67]
  DIRECTION OUTPUT ;
  USE SIGNAL ;
  PORT
   LAYER M6 ;
   RECT 43.008000 455.024000 43.200000 455.056000 ;
  END
 END pi1[67]
 PIN pi1[68]
  DIRECTION OUTPUT ;
  USE SIGNAL ;
  PORT
   LAYER M4 ;
   RECT 43.008000 455.820000 43.200000 455.844000 ;
  END
 END pi1[68]
 PIN pi1[69]
  DIRECTION OUTPUT ;
  USE SIGNAL ;
  PORT
   LAYER M6 ;
   RECT 43.008000 456.240000 43.200000 456.272000 ;
  END
 END pi1[69]
 PIN pi1[70]
  DIRECTION OUTPUT ;
  USE SIGNAL ;
  PORT
   LAYER M4 ;
   RECT 43.008000 456.156000 43.200000 456.180000 ;
  END
 END pi1[70]
 PIN pi1[71]
  DIRECTION OUTPUT ;
  USE SIGNAL ;
  PORT
   LAYER M6 ;
   RECT 43.008000 456.496000 43.200000 456.528000 ;
  END
 END pi1[71]
 PIN pi1[72]
  DIRECTION OUTPUT ;
  USE SIGNAL ;
  PORT
   LAYER M4 ;
   RECT 43.008000 456.444000 43.200000 456.468000 ;
  END
 END pi1[72]
 PIN pi1[73]
  DIRECTION OUTPUT ;
  USE SIGNAL ;
  PORT
   LAYER M6 ;
   RECT 43.008000 456.752000 43.200000 456.784000 ;
  END
 END pi1[73]
 PIN pi1[74]
  DIRECTION OUTPUT ;
  USE SIGNAL ;
  PORT
   LAYER M4 ;
   RECT 43.008000 456.780000 43.200000 456.804000 ;
  END
 END pi1[74]
 PIN pi1[75]
  DIRECTION OUTPUT ;
  USE SIGNAL ;
  PORT
   LAYER M6 ;
   RECT 43.008000 457.008000 43.200000 457.040000 ;
  END
 END pi1[75]
 PIN pi1[76]
  DIRECTION OUTPUT ;
  USE SIGNAL ;
  PORT
   LAYER M4 ;
   RECT 43.008000 457.116000 43.200000 457.140000 ;
  END
 END pi1[76]
 PIN pi1[77]
  DIRECTION OUTPUT ;
  USE SIGNAL ;
  PORT
   LAYER M6 ;
   RECT 43.008000 457.264000 43.200000 457.296000 ;
  END
 END pi1[77]
 PIN pi1[78]
  DIRECTION OUTPUT ;
  USE SIGNAL ;
  PORT
   LAYER M4 ;
   RECT 43.008000 457.452000 43.200000 457.476000 ;
  END
 END pi1[78]
 PIN pi1[79]
  DIRECTION OUTPUT ;
  USE SIGNAL ;
  PORT
   LAYER M6 ;
   RECT 43.008000 457.520000 43.200000 457.552000 ;
  END
 END pi1[79]
 PIN pi1[80]
  DIRECTION OUTPUT ;
  USE SIGNAL ;
  PORT
   LAYER M4 ;
   RECT 43.008000 457.788000 43.200000 457.812000 ;
  END
 END pi1[80]
 PIN pi1[81]
  DIRECTION OUTPUT ;
  USE SIGNAL ;
  PORT
   LAYER M6 ;
   RECT 43.008000 457.776000 43.200000 457.808000 ;
  END
 END pi1[81]
 PIN pi1[82]
  DIRECTION OUTPUT ;
  USE SIGNAL ;
  PORT
   LAYER M4 ;
   RECT 43.008000 458.124000 43.200000 458.148000 ;
  END
 END pi1[82]
 PIN pi1[83]
  DIRECTION OUTPUT ;
  USE SIGNAL ;
  PORT
   LAYER M6 ;
   RECT 43.008000 458.032000 43.200000 458.064000 ;
  END
 END pi1[83]
 PIN pi1[84]
  DIRECTION OUTPUT ;
  USE SIGNAL ;
  PORT
   LAYER M4 ;
   RECT 43.008000 458.460000 43.200000 458.484000 ;
  END
 END pi1[84]
 PIN pi1[85]
  DIRECTION OUTPUT ;
  USE SIGNAL ;
  PORT
   LAYER M6 ;
   RECT 43.008000 458.288000 43.200000 458.320000 ;
  END
 END pi1[85]
 PIN pi1[86]
  DIRECTION OUTPUT ;
  USE SIGNAL ;
  PORT
   LAYER M4 ;
   RECT 43.008000 458.796000 43.200000 458.820000 ;
  END
 END pi1[86]
 PIN pi1[87]
  DIRECTION OUTPUT ;
  USE SIGNAL ;
  PORT
   LAYER M6 ;
   RECT 43.008000 458.544000 43.200000 458.576000 ;
  END
 END pi1[87]
 PIN pi1[88]
  DIRECTION OUTPUT ;
  USE SIGNAL ;
  PORT
   LAYER M4 ;
   RECT 43.008000 459.132000 43.200000 459.156000 ;
  END
 END pi1[88]
 PIN pi1[89]
  DIRECTION OUTPUT ;
  USE SIGNAL ;
  PORT
   LAYER M6 ;
   RECT 43.008000 458.864000 43.200000 458.896000 ;
  END
 END pi1[89]
 PIN pi1[90]
  DIRECTION OUTPUT ;
  USE SIGNAL ;
  PORT
   LAYER M4 ;
   RECT 43.008000 459.468000 43.200000 459.492000 ;
  END
 END pi1[90]
 PIN pi1[91]
  DIRECTION OUTPUT ;
  USE SIGNAL ;
  PORT
   LAYER M6 ;
   RECT 43.008000 459.120000 43.200000 459.152000 ;
  END
 END pi1[91]
 PIN pi1[92]
  DIRECTION OUTPUT ;
  USE SIGNAL ;
  PORT
   LAYER M4 ;
   RECT 43.008000 459.804000 43.200000 459.828000 ;
  END
 END pi1[92]
 PIN pi1[93]
  DIRECTION OUTPUT ;
  USE SIGNAL ;
  PORT
   LAYER M6 ;
   RECT 43.008000 459.376000 43.200000 459.408000 ;
  END
 END pi1[93]
 PIN pi1[94]
  DIRECTION OUTPUT ;
  USE SIGNAL ;
  PORT
   LAYER M4 ;
   RECT 43.008000 460.140000 43.200000 460.164000 ;
  END
 END pi1[94]
 PIN pi1[95]
  DIRECTION OUTPUT ;
  USE SIGNAL ;
  PORT
   LAYER M6 ;
   RECT 43.008000 460.592000 43.200000 460.624000 ;
  END
 END pi1[95]
 PIN pi1[96]
  DIRECTION OUTPUT ;
  USE SIGNAL ;
  PORT
   LAYER M4 ;
   RECT 43.008000 460.476000 43.200000 460.500000 ;
  END
 END pi1[96]
 PIN pi1[97]
  DIRECTION OUTPUT ;
  USE SIGNAL ;
  PORT
   LAYER M6 ;
   RECT 43.008000 460.848000 43.200000 460.880000 ;
  END
 END pi1[97]
 PIN pi1[98]
  DIRECTION OUTPUT ;
  USE SIGNAL ;
  PORT
   LAYER M4 ;
   RECT 43.008000 460.812000 43.200000 460.836000 ;
  END
 END pi1[98]
 PIN pi1[99]
  DIRECTION OUTPUT ;
  USE SIGNAL ;
  PORT
   LAYER M6 ;
   RECT 43.008000 461.104000 43.200000 461.136000 ;
  END
 END pi1[99]
 PIN pi1[100]
  DIRECTION OUTPUT ;
  USE SIGNAL ;
  PORT
   LAYER M4 ;
   RECT 43.008000 461.148000 43.200000 461.172000 ;
  END
 END pi1[100]
 PIN pi1[101]
  DIRECTION OUTPUT ;
  USE SIGNAL ;
  PORT
   LAYER M6 ;
   RECT 43.008000 461.360000 43.200000 461.392000 ;
  END
 END pi1[101]
 PIN pi1[102]
  DIRECTION OUTPUT ;
  USE SIGNAL ;
  PORT
   LAYER M4 ;
   RECT 43.008000 461.484000 43.200000 461.508000 ;
  END
 END pi1[102]
 PIN pi1[103]
  DIRECTION OUTPUT ;
  USE SIGNAL ;
  PORT
   LAYER M6 ;
   RECT 43.008000 461.616000 43.200000 461.648000 ;
  END
 END pi1[103]
 PIN pi1[104]
  DIRECTION OUTPUT ;
  USE SIGNAL ;
  PORT
   LAYER M4 ;
   RECT 43.008000 461.820000 43.200000 461.844000 ;
  END
 END pi1[104]
 PIN pi1[105]
  DIRECTION OUTPUT ;
  USE SIGNAL ;
  PORT
   LAYER M6 ;
   RECT 43.008000 461.872000 43.200000 461.904000 ;
  END
 END pi1[105]
 PIN pi1[106]
  DIRECTION OUTPUT ;
  USE SIGNAL ;
  PORT
   LAYER M4 ;
   RECT 43.008000 462.156000 43.200000 462.180000 ;
  END
 END pi1[106]
 PIN pi1[107]
  DIRECTION OUTPUT ;
  USE SIGNAL ;
  PORT
   LAYER M6 ;
   RECT 43.008000 462.128000 43.200000 462.160000 ;
  END
 END pi1[107]
 PIN pi1[108]
  DIRECTION OUTPUT ;
  USE SIGNAL ;
  PORT
   LAYER M4 ;
   RECT 43.008000 462.444000 43.200000 462.468000 ;
  END
 END pi1[108]
 PIN pi1[109]
  DIRECTION OUTPUT ;
  USE SIGNAL ;
  PORT
   LAYER M6 ;
   RECT 43.008000 462.448000 43.200000 462.480000 ;
  END
 END pi1[109]
 PIN pi1[110]
  DIRECTION OUTPUT ;
  USE SIGNAL ;
  PORT
   LAYER M4 ;
   RECT 43.008000 462.780000 43.200000 462.804000 ;
  END
 END pi1[110]
 PIN pi1[111]
  DIRECTION OUTPUT ;
  USE SIGNAL ;
  PORT
   LAYER M6 ;
   RECT 43.008000 462.704000 43.200000 462.736000 ;
  END
 END pi1[111]
 PIN pi1[112]
  DIRECTION OUTPUT ;
  USE SIGNAL ;
  PORT
   LAYER M4 ;
   RECT 43.008000 463.116000 43.200000 463.140000 ;
  END
 END pi1[112]
 PIN pi1[113]
  DIRECTION OUTPUT ;
  USE SIGNAL ;
  PORT
   LAYER M6 ;
   RECT 43.008000 462.960000 43.200000 462.992000 ;
  END
 END pi1[113]
 PIN pi1[114]
  DIRECTION OUTPUT ;
  USE SIGNAL ;
  PORT
   LAYER M4 ;
   RECT 43.008000 463.452000 43.200000 463.476000 ;
  END
 END pi1[114]
 PIN pi1[115]
  DIRECTION OUTPUT ;
  USE SIGNAL ;
  PORT
   LAYER M6 ;
   RECT 43.008000 463.216000 43.200000 463.248000 ;
  END
 END pi1[115]
 PIN pi1[116]
  DIRECTION OUTPUT ;
  USE SIGNAL ;
  PORT
   LAYER M4 ;
   RECT 43.008000 463.788000 43.200000 463.812000 ;
  END
 END pi1[116]
 PIN pi1[117]
  DIRECTION OUTPUT ;
  USE SIGNAL ;
  PORT
   LAYER M6 ;
   RECT 43.008000 463.472000 43.200000 463.504000 ;
  END
 END pi1[117]
 PIN pi1[118]
  DIRECTION OUTPUT ;
  USE SIGNAL ;
  PORT
   LAYER M4 ;
   RECT 43.008000 464.124000 43.200000 464.148000 ;
  END
 END pi1[118]
 PIN pi1[119]
  DIRECTION OUTPUT ;
  USE SIGNAL ;
  PORT
   LAYER M6 ;
   RECT 43.008000 463.728000 43.200000 463.760000 ;
  END
 END pi1[119]
 PIN pi1[120]
  DIRECTION OUTPUT ;
  USE SIGNAL ;
  PORT
   LAYER M4 ;
   RECT 43.008000 464.460000 43.200000 464.484000 ;
  END
 END pi1[120]
 PIN pi1[121]
  DIRECTION OUTPUT ;
  USE SIGNAL ;
  PORT
   LAYER M6 ;
   RECT 43.008000 464.944000 43.200000 464.976000 ;
  END
 END pi1[121]
 PIN pi1[122]
  DIRECTION OUTPUT ;
  USE SIGNAL ;
  PORT
   LAYER M4 ;
   RECT 43.008000 464.796000 43.200000 464.820000 ;
  END
 END pi1[122]
 PIN pi1[123]
  DIRECTION OUTPUT ;
  USE SIGNAL ;
  PORT
   LAYER M6 ;
   RECT 43.008000 465.200000 43.200000 465.232000 ;
  END
 END pi1[123]
 PIN pi1[124]
  DIRECTION OUTPUT ;
  USE SIGNAL ;
  PORT
   LAYER M4 ;
   RECT 43.008000 465.132000 43.200000 465.156000 ;
  END
 END pi1[124]
 PIN pi1[125]
  DIRECTION OUTPUT ;
  USE SIGNAL ;
  PORT
   LAYER M6 ;
   RECT 43.008000 465.456000 43.200000 465.488000 ;
  END
 END pi1[125]
 PIN pi1[126]
  DIRECTION OUTPUT ;
  USE SIGNAL ;
  PORT
   LAYER M4 ;
   RECT 43.008000 465.468000 43.200000 465.492000 ;
  END
 END pi1[126]
 PIN pi1[127]
  DIRECTION OUTPUT ;
  USE SIGNAL ;
  PORT
   LAYER M6 ;
   RECT 43.008000 465.712000 43.200000 465.744000 ;
  END
 END pi1[127]
 PIN pi1[128]
  DIRECTION OUTPUT ;
  USE SIGNAL ;
  PORT
   LAYER M4 ;
   RECT 43.008000 465.804000 43.200000 465.828000 ;
  END
 END pi1[128]
 PIN pi1[129]
  DIRECTION OUTPUT ;
  USE SIGNAL ;
  PORT
   LAYER M6 ;
   RECT 43.008000 466.032000 43.200000 466.064000 ;
  END
 END pi1[129]
 PIN pi1[130]
  DIRECTION OUTPUT ;
  USE SIGNAL ;
  PORT
   LAYER M4 ;
   RECT 43.008000 466.140000 43.200000 466.164000 ;
  END
 END pi1[130]
 PIN pi1[131]
  DIRECTION OUTPUT ;
  USE SIGNAL ;
  PORT
   LAYER M6 ;
   RECT 43.008000 466.288000 43.200000 466.320000 ;
  END
 END pi1[131]
 PIN pi1[132]
  DIRECTION OUTPUT ;
  USE SIGNAL ;
  PORT
   LAYER M4 ;
   RECT 43.008000 466.476000 43.200000 466.500000 ;
  END
 END pi1[132]
 PIN pi1[133]
  DIRECTION OUTPUT ;
  USE SIGNAL ;
  PORT
   LAYER M6 ;
   RECT 43.008000 466.544000 43.200000 466.576000 ;
  END
 END pi1[133]
 PIN pi1[134]
  DIRECTION OUTPUT ;
  USE SIGNAL ;
  PORT
   LAYER M4 ;
   RECT 43.008000 466.812000 43.200000 466.836000 ;
  END
 END pi1[134]
 PIN pi1[135]
  DIRECTION OUTPUT ;
  USE SIGNAL ;
  PORT
   LAYER M6 ;
   RECT 43.008000 466.800000 43.200000 466.832000 ;
  END
 END pi1[135]
 PIN pi1[136]
  DIRECTION OUTPUT ;
  USE SIGNAL ;
  PORT
   LAYER M4 ;
   RECT 43.008000 467.148000 43.200000 467.172000 ;
  END
 END pi1[136]
 PIN pi1[137]
  DIRECTION OUTPUT ;
  USE SIGNAL ;
  PORT
   LAYER M6 ;
   RECT 43.008000 467.056000 43.200000 467.088000 ;
  END
 END pi1[137]
 PIN pi1[138]
  DIRECTION OUTPUT ;
  USE SIGNAL ;
  PORT
   LAYER M4 ;
   RECT 43.008000 467.484000 43.200000 467.508000 ;
  END
 END pi1[138]
 PIN pi1[139]
  DIRECTION OUTPUT ;
  USE SIGNAL ;
  PORT
   LAYER M6 ;
   RECT 43.008000 467.312000 43.200000 467.344000 ;
  END
 END pi1[139]
 PIN pi1[140]
  DIRECTION OUTPUT ;
  USE SIGNAL ;
  PORT
   LAYER M4 ;
   RECT 43.008000 467.820000 43.200000 467.844000 ;
  END
 END pi1[140]
 PIN pi1[141]
  DIRECTION OUTPUT ;
  USE SIGNAL ;
  PORT
   LAYER M6 ;
   RECT 43.008000 467.568000 43.200000 467.600000 ;
  END
 END pi1[141]
 PIN pi1[142]
  DIRECTION OUTPUT ;
  USE SIGNAL ;
  PORT
   LAYER M4 ;
   RECT 43.008000 468.156000 43.200000 468.180000 ;
  END
 END pi1[142]
 PIN pi1[143]
  DIRECTION OUTPUT ;
  USE SIGNAL ;
  PORT
   LAYER M6 ;
   RECT 43.008000 467.824000 43.200000 467.856000 ;
  END
 END pi1[143]
 PIN pi1[144]
  DIRECTION OUTPUT ;
  USE SIGNAL ;
  PORT
   LAYER M4 ;
   RECT 43.008000 468.444000 43.200000 468.468000 ;
  END
 END pi1[144]
 PIN pi1[145]
  DIRECTION OUTPUT ;
  USE SIGNAL ;
  PORT
   LAYER M6 ;
   RECT 43.008000 468.080000 43.200000 468.112000 ;
  END
 END pi1[145]
 PIN pi1[146]
  DIRECTION OUTPUT ;
  USE SIGNAL ;
  PORT
   LAYER M4 ;
   RECT 43.008000 468.780000 43.200000 468.804000 ;
  END
 END pi1[146]
 PIN pi1[147]
  DIRECTION OUTPUT ;
  USE SIGNAL ;
  PORT
   LAYER M6 ;
   RECT 43.008000 469.296000 43.200000 469.328000 ;
  END
 END pi1[147]
 PIN pi1[148]
  DIRECTION OUTPUT ;
  USE SIGNAL ;
  PORT
   LAYER M4 ;
   RECT 43.008000 469.116000 43.200000 469.140000 ;
  END
 END pi1[148]
 PIN pi1[149]
  DIRECTION OUTPUT ;
  USE SIGNAL ;
  PORT
   LAYER M6 ;
   RECT 43.008000 469.616000 43.200000 469.648000 ;
  END
 END pi1[149]
 PIN pi1[150]
  DIRECTION OUTPUT ;
  USE SIGNAL ;
  PORT
   LAYER M4 ;
   RECT 43.008000 469.452000 43.200000 469.476000 ;
  END
 END pi1[150]
 PIN pi1[151]
  DIRECTION OUTPUT ;
  USE SIGNAL ;
  PORT
   LAYER M6 ;
   RECT 43.008000 469.936000 43.200000 469.968000 ;
  END
 END pi1[151]
 PIN pi1[152]
  DIRECTION OUTPUT ;
  USE SIGNAL ;
  PORT
   LAYER M4 ;
   RECT 43.008000 469.788000 43.200000 469.812000 ;
  END
 END pi1[152]
 PIN pi1[153]
  DIRECTION OUTPUT ;
  USE SIGNAL ;
  PORT
   LAYER M6 ;
   RECT 43.008000 470.192000 43.200000 470.224000 ;
  END
 END pi1[153]
 PIN pi1[154]
  DIRECTION OUTPUT ;
  USE SIGNAL ;
  PORT
   LAYER M4 ;
   RECT 43.008000 470.124000 43.200000 470.148000 ;
  END
 END pi1[154]
 PIN pi1[155]
  DIRECTION OUTPUT ;
  USE SIGNAL ;
  PORT
   LAYER M6 ;
   RECT 43.008000 470.448000 43.200000 470.480000 ;
  END
 END pi1[155]
 PIN pi1[156]
  DIRECTION OUTPUT ;
  USE SIGNAL ;
  PORT
   LAYER M4 ;
   RECT 43.008000 470.460000 43.200000 470.484000 ;
  END
 END pi1[156]
 PIN pi1[157]
  DIRECTION OUTPUT ;
  USE SIGNAL ;
  PORT
   LAYER M6 ;
   RECT 43.008000 470.704000 43.200000 470.736000 ;
  END
 END pi1[157]
 PIN pi1[158]
  DIRECTION OUTPUT ;
  USE SIGNAL ;
  PORT
   LAYER M4 ;
   RECT 43.008000 470.796000 43.200000 470.820000 ;
  END
 END pi1[158]
 PIN pi1[159]
  DIRECTION OUTPUT ;
  USE SIGNAL ;
  PORT
   LAYER M6 ;
   RECT 43.008000 470.960000 43.200000 470.992000 ;
  END
 END pi1[159]
 PIN pi1[160]
  DIRECTION OUTPUT ;
  USE SIGNAL ;
  PORT
   LAYER M4 ;
   RECT 43.008000 471.132000 43.200000 471.156000 ;
  END
 END pi1[160]
 PIN pi1[161]
  DIRECTION OUTPUT ;
  USE SIGNAL ;
  PORT
   LAYER M6 ;
   RECT 43.008000 471.216000 43.200000 471.248000 ;
  END
 END pi1[161]
 PIN pi1[162]
  DIRECTION OUTPUT ;
  USE SIGNAL ;
  PORT
   LAYER M4 ;
   RECT 43.008000 471.468000 43.200000 471.492000 ;
  END
 END pi1[162]
 PIN pi1[163]
  DIRECTION OUTPUT ;
  USE SIGNAL ;
  PORT
   LAYER M6 ;
   RECT 43.008000 471.472000 43.200000 471.504000 ;
  END
 END pi1[163]
 PIN pi1[164]
  DIRECTION OUTPUT ;
  USE SIGNAL ;
  PORT
   LAYER M4 ;
   RECT 43.008000 471.804000 43.200000 471.828000 ;
  END
 END pi1[164]
 PIN pi1[165]
  DIRECTION OUTPUT ;
  USE SIGNAL ;
  PORT
   LAYER M6 ;
   RECT 43.008000 471.728000 43.200000 471.760000 ;
  END
 END pi1[165]
 PIN pi1[166]
  DIRECTION OUTPUT ;
  USE SIGNAL ;
  PORT
   LAYER M4 ;
   RECT 43.008000 472.140000 43.200000 472.164000 ;
  END
 END pi1[166]
 PIN pi1[167]
  DIRECTION OUTPUT ;
  USE SIGNAL ;
  PORT
   LAYER M6 ;
   RECT 43.008000 471.984000 43.200000 472.016000 ;
  END
 END pi1[167]
 PIN pi1[168]
  DIRECTION OUTPUT ;
  USE SIGNAL ;
  PORT
   LAYER M4 ;
   RECT 43.008000 472.476000 43.200000 472.500000 ;
  END
 END pi1[168]
 PIN pi1[169]
  DIRECTION OUTPUT ;
  USE SIGNAL ;
  PORT
   LAYER M6 ;
   RECT 43.008000 472.240000 43.200000 472.272000 ;
  END
 END pi1[169]
 PIN pi1[170]
  DIRECTION OUTPUT ;
  USE SIGNAL ;
  PORT
   LAYER M4 ;
   RECT 43.008000 472.812000 43.200000 472.836000 ;
  END
 END pi1[170]
 PIN pi1[171]
  DIRECTION OUTPUT ;
  USE SIGNAL ;
  PORT
   LAYER M6 ;
   RECT 43.008000 473.520000 43.200000 473.552000 ;
  END
 END pi1[171]
 PIN pi1[172]
  DIRECTION OUTPUT ;
  USE SIGNAL ;
  PORT
   LAYER M4 ;
   RECT 43.008000 473.148000 43.200000 473.172000 ;
  END
 END pi1[172]
 PIN pi1[173]
  DIRECTION OUTPUT ;
  USE SIGNAL ;
  PORT
   LAYER M6 ;
   RECT 43.008000 473.776000 43.200000 473.808000 ;
  END
 END pi1[173]
 PIN pi1[174]
  DIRECTION OUTPUT ;
  USE SIGNAL ;
  PORT
   LAYER M4 ;
   RECT 43.008000 473.484000 43.200000 473.508000 ;
  END
 END pi1[174]
 PIN pi1[175]
  DIRECTION OUTPUT ;
  USE SIGNAL ;
  PORT
   LAYER M6 ;
   RECT 43.008000 474.032000 43.200000 474.064000 ;
  END
 END pi1[175]
 PIN pi1[176]
  DIRECTION OUTPUT ;
  USE SIGNAL ;
  PORT
   LAYER M4 ;
   RECT 43.008000 473.820000 43.200000 473.844000 ;
  END
 END pi1[176]
 PIN pi1[177]
  DIRECTION OUTPUT ;
  USE SIGNAL ;
  PORT
   LAYER M6 ;
   RECT 43.008000 474.288000 43.200000 474.320000 ;
  END
 END pi1[177]
 PIN pi1[178]
  DIRECTION OUTPUT ;
  USE SIGNAL ;
  PORT
   LAYER M4 ;
   RECT 43.008000 474.156000 43.200000 474.180000 ;
  END
 END pi1[178]
 PIN pi1[179]
  DIRECTION OUTPUT ;
  USE SIGNAL ;
  PORT
   LAYER M6 ;
   RECT 43.008000 474.544000 43.200000 474.576000 ;
  END
 END pi1[179]
 PIN pi1[180]
  DIRECTION OUTPUT ;
  USE SIGNAL ;
  PORT
   LAYER M4 ;
   RECT 43.008000 474.444000 43.200000 474.468000 ;
  END
 END pi1[180]
 PIN pi1[181]
  DIRECTION OUTPUT ;
  USE SIGNAL ;
  PORT
   LAYER M6 ;
   RECT 43.008000 474.800000 43.200000 474.832000 ;
  END
 END pi1[181]
 PIN pi1[182]
  DIRECTION OUTPUT ;
  USE SIGNAL ;
  PORT
   LAYER M4 ;
   RECT 43.008000 474.780000 43.200000 474.804000 ;
  END
 END pi1[182]
 PIN pi1[183]
  DIRECTION OUTPUT ;
  USE SIGNAL ;
  PORT
   LAYER M6 ;
   RECT 43.008000 475.056000 43.200000 475.088000 ;
  END
 END pi1[183]
 PIN pi1[184]
  DIRECTION OUTPUT ;
  USE SIGNAL ;
  PORT
   LAYER M4 ;
   RECT 43.008000 475.116000 43.200000 475.140000 ;
  END
 END pi1[184]
 PIN pi1[185]
  DIRECTION OUTPUT ;
  USE SIGNAL ;
  PORT
   LAYER M6 ;
   RECT 43.008000 475.312000 43.200000 475.344000 ;
  END
 END pi1[185]
 PIN pi1[186]
  DIRECTION OUTPUT ;
  USE SIGNAL ;
  PORT
   LAYER M4 ;
   RECT 43.008000 475.452000 43.200000 475.476000 ;
  END
 END pi1[186]
 PIN pi1[187]
  DIRECTION OUTPUT ;
  USE SIGNAL ;
  PORT
   LAYER M6 ;
   RECT 43.008000 475.568000 43.200000 475.600000 ;
  END
 END pi1[187]
 PIN pi1[188]
  DIRECTION OUTPUT ;
  USE SIGNAL ;
  PORT
   LAYER M4 ;
   RECT 43.008000 475.788000 43.200000 475.812000 ;
  END
 END pi1[188]
 PIN pi1[189]
  DIRECTION OUTPUT ;
  USE SIGNAL ;
  PORT
   LAYER M6 ;
   RECT 43.008000 475.824000 43.200000 475.856000 ;
  END
 END pi1[189]
 PIN pi1[190]
  DIRECTION OUTPUT ;
  USE SIGNAL ;
  PORT
   LAYER M4 ;
   RECT 43.008000 476.124000 43.200000 476.148000 ;
  END
 END pi1[190]
 PIN pi1[191]
  DIRECTION OUTPUT ;
  USE SIGNAL ;
  PORT
   LAYER M6 ;
   RECT 43.008000 476.144000 43.200000 476.176000 ;
  END
 END pi1[191]
 PIN pi1[192]
  DIRECTION OUTPUT ;
  USE SIGNAL ;
  PORT
   LAYER M4 ;
   RECT 43.008000 476.460000 43.200000 476.484000 ;
  END
 END pi1[192]
 PIN pi1[193]
  DIRECTION OUTPUT ;
  USE SIGNAL ;
  PORT
   LAYER M6 ;
   RECT 43.008000 476.400000 43.200000 476.432000 ;
  END
 END pi1[193]
 PIN pi1[194]
  DIRECTION OUTPUT ;
  USE SIGNAL ;
  PORT
   LAYER M4 ;
   RECT 43.008000 476.796000 43.200000 476.820000 ;
  END
 END pi1[194]
 PIN pi1[195]
  DIRECTION OUTPUT ;
  USE SIGNAL ;
  PORT
   LAYER M6 ;
   RECT 43.008000 476.656000 43.200000 476.688000 ;
  END
 END pi1[195]
 PIN pi1[196]
  DIRECTION OUTPUT ;
  USE SIGNAL ;
  PORT
   LAYER M4 ;
   RECT 43.008000 477.132000 43.200000 477.156000 ;
  END
 END pi1[196]
 PIN pi1[197]
  DIRECTION OUTPUT ;
  USE SIGNAL ;
  PORT
   LAYER M6 ;
   RECT 43.008000 477.872000 43.200000 477.904000 ;
  END
 END pi1[197]
 PIN pi1[198]
  DIRECTION OUTPUT ;
  USE SIGNAL ;
  PORT
   LAYER M4 ;
   RECT 43.008000 477.468000 43.200000 477.492000 ;
  END
 END pi1[198]
 PIN pi1[199]
  DIRECTION OUTPUT ;
  USE SIGNAL ;
  PORT
   LAYER M6 ;
   RECT 43.008000 478.128000 43.200000 478.160000 ;
  END
 END pi1[199]
 PIN pi1[200]
  DIRECTION OUTPUT ;
  USE SIGNAL ;
  PORT
   LAYER M4 ;
   RECT 43.008000 477.804000 43.200000 477.828000 ;
  END
 END pi1[200]
 PIN pi1[201]
  DIRECTION OUTPUT ;
  USE SIGNAL ;
  PORT
   LAYER M6 ;
   RECT 43.008000 478.384000 43.200000 478.416000 ;
  END
 END pi1[201]
 PIN pi1[202]
  DIRECTION OUTPUT ;
  USE SIGNAL ;
  PORT
   LAYER M4 ;
   RECT 43.008000 478.140000 43.200000 478.164000 ;
  END
 END pi1[202]
 PIN pi1[203]
  DIRECTION OUTPUT ;
  USE SIGNAL ;
  PORT
   LAYER M6 ;
   RECT 43.008000 478.640000 43.200000 478.672000 ;
  END
 END pi1[203]
 PIN pi1[204]
  DIRECTION OUTPUT ;
  USE SIGNAL ;
  PORT
   LAYER M4 ;
   RECT 43.008000 478.476000 43.200000 478.500000 ;
  END
 END pi1[204]
 PIN pi1[205]
  DIRECTION OUTPUT ;
  USE SIGNAL ;
  PORT
   LAYER M6 ;
   RECT 43.008000 478.896000 43.200000 478.928000 ;
  END
 END pi1[205]
 PIN pi1[206]
  DIRECTION OUTPUT ;
  USE SIGNAL ;
  PORT
   LAYER M4 ;
   RECT 43.008000 478.812000 43.200000 478.836000 ;
  END
 END pi1[206]
 PIN pi1[207]
  DIRECTION OUTPUT ;
  USE SIGNAL ;
  PORT
   LAYER M6 ;
   RECT 43.008000 479.152000 43.200000 479.184000 ;
  END
 END pi1[207]
 PIN pi1[208]
  DIRECTION OUTPUT ;
  USE SIGNAL ;
  PORT
   LAYER M4 ;
   RECT 43.008000 479.148000 43.200000 479.172000 ;
  END
 END pi1[208]
 PIN pi1[209]
  DIRECTION OUTPUT ;
  USE SIGNAL ;
  PORT
   LAYER M6 ;
   RECT 43.008000 479.408000 43.200000 479.440000 ;
  END
 END pi1[209]
 PIN pi1[210]
  DIRECTION OUTPUT ;
  USE SIGNAL ;
  PORT
   LAYER M4 ;
   RECT 43.008000 479.484000 43.200000 479.508000 ;
  END
 END pi1[210]
 PIN pi1[211]
  DIRECTION OUTPUT ;
  USE SIGNAL ;
  PORT
   LAYER M6 ;
   RECT 43.008000 479.728000 43.200000 479.760000 ;
  END
 END pi1[211]
 PIN pi1[212]
  DIRECTION OUTPUT ;
  USE SIGNAL ;
  PORT
   LAYER M4 ;
   RECT 43.008000 479.820000 43.200000 479.844000 ;
  END
 END pi1[212]
 PIN pi1[213]
  DIRECTION OUTPUT ;
  USE SIGNAL ;
  PORT
   LAYER M6 ;
   RECT 43.008000 479.984000 43.200000 480.016000 ;
  END
 END pi1[213]
 PIN pi1[214]
  DIRECTION OUTPUT ;
  USE SIGNAL ;
  PORT
   LAYER M4 ;
   RECT 43.008000 480.156000 43.200000 480.180000 ;
  END
 END pi1[214]
 PIN pi1[215]
  DIRECTION OUTPUT ;
  USE SIGNAL ;
  PORT
   LAYER M6 ;
   RECT 43.008000 480.240000 43.200000 480.272000 ;
  END
 END pi1[215]
 PIN pi1[216]
  DIRECTION OUTPUT ;
  USE SIGNAL ;
  PORT
   LAYER M4 ;
   RECT 43.008000 480.444000 43.200000 480.468000 ;
  END
 END pi1[216]
 PIN pi1[217]
  DIRECTION OUTPUT ;
  USE SIGNAL ;
  PORT
   LAYER M6 ;
   RECT 43.008000 480.496000 43.200000 480.528000 ;
  END
 END pi1[217]
 PIN pi1[218]
  DIRECTION OUTPUT ;
  USE SIGNAL ;
  PORT
   LAYER M4 ;
   RECT 43.008000 480.780000 43.200000 480.804000 ;
  END
 END pi1[218]
 PIN pi1[219]
  DIRECTION OUTPUT ;
  USE SIGNAL ;
  PORT
   LAYER M6 ;
   RECT 43.008000 480.752000 43.200000 480.784000 ;
  END
 END pi1[219]
 PIN pi1[220]
  DIRECTION OUTPUT ;
  USE SIGNAL ;
  PORT
   LAYER M4 ;
   RECT 43.008000 481.116000 43.200000 481.140000 ;
  END
 END pi1[220]
 PIN pi1[221]
  DIRECTION OUTPUT ;
  USE SIGNAL ;
  PORT
   LAYER M6 ;
   RECT 43.008000 481.008000 43.200000 481.040000 ;
  END
 END pi1[221]
 PIN pi1[222]
  DIRECTION OUTPUT ;
  USE SIGNAL ;
  PORT
   LAYER M4 ;
   RECT 43.008000 481.452000 43.200000 481.476000 ;
  END
 END pi1[222]
 PIN pi1[223]
  DIRECTION OUTPUT ;
  USE SIGNAL ;
  PORT
   LAYER M6 ;
   RECT 43.008000 482.224000 43.200000 482.256000 ;
  END
 END pi1[223]
 PIN pi1[224]
  DIRECTION OUTPUT ;
  USE SIGNAL ;
  PORT
   LAYER M4 ;
   RECT 43.008000 481.788000 43.200000 481.812000 ;
  END
 END pi1[224]
 PIN pi1[225]
  DIRECTION OUTPUT ;
  USE SIGNAL ;
  PORT
   LAYER M6 ;
   RECT 43.008000 482.480000 43.200000 482.512000 ;
  END
 END pi1[225]
 PIN pi1[226]
  DIRECTION OUTPUT ;
  USE SIGNAL ;
  PORT
   LAYER M4 ;
   RECT 43.008000 482.124000 43.200000 482.148000 ;
  END
 END pi1[226]
 PIN pi1[227]
  DIRECTION OUTPUT ;
  USE SIGNAL ;
  PORT
   LAYER M6 ;
   RECT 43.008000 482.736000 43.200000 482.768000 ;
  END
 END pi1[227]
 PIN pi1[228]
  DIRECTION OUTPUT ;
  USE SIGNAL ;
  PORT
   LAYER M4 ;
   RECT 43.008000 482.460000 43.200000 482.484000 ;
  END
 END pi1[228]
 PIN pi1[229]
  DIRECTION OUTPUT ;
  USE SIGNAL ;
  PORT
   LAYER M6 ;
   RECT 43.008000 482.992000 43.200000 483.024000 ;
  END
 END pi1[229]
 PIN pi1[230]
  DIRECTION OUTPUT ;
  USE SIGNAL ;
  PORT
   LAYER M4 ;
   RECT 43.008000 482.796000 43.200000 482.820000 ;
  END
 END pi1[230]
 PIN pi1[231]
  DIRECTION OUTPUT ;
  USE SIGNAL ;
  PORT
   LAYER M6 ;
   RECT 43.008000 483.248000 43.200000 483.280000 ;
  END
 END pi1[231]
 PIN pi1[232]
  DIRECTION OUTPUT ;
  USE SIGNAL ;
  PORT
   LAYER M4 ;
   RECT 43.008000 483.132000 43.200000 483.156000 ;
  END
 END pi1[232]
 PIN pi1[233]
  DIRECTION OUTPUT ;
  USE SIGNAL ;
  PORT
   LAYER M6 ;
   RECT 43.008000 483.568000 43.200000 483.600000 ;
  END
 END pi1[233]
 PIN pi1[234]
  DIRECTION OUTPUT ;
  USE SIGNAL ;
  PORT
   LAYER M4 ;
   RECT 43.008000 483.468000 43.200000 483.492000 ;
  END
 END pi1[234]
 PIN pi1[235]
  DIRECTION OUTPUT ;
  USE SIGNAL ;
  PORT
   LAYER M6 ;
   RECT 43.008000 483.824000 43.200000 483.856000 ;
  END
 END pi1[235]
 PIN pi1[236]
  DIRECTION OUTPUT ;
  USE SIGNAL ;
  PORT
   LAYER M4 ;
   RECT 43.008000 483.804000 43.200000 483.828000 ;
  END
 END pi1[236]
 PIN pi1[237]
  DIRECTION OUTPUT ;
  USE SIGNAL ;
  PORT
   LAYER M6 ;
   RECT 43.008000 484.080000 43.200000 484.112000 ;
  END
 END pi1[237]
 PIN pi1[238]
  DIRECTION OUTPUT ;
  USE SIGNAL ;
  PORT
   LAYER M4 ;
   RECT 43.008000 484.140000 43.200000 484.164000 ;
  END
 END pi1[238]
 PIN pi1[239]
  DIRECTION OUTPUT ;
  USE SIGNAL ;
  PORT
   LAYER M6 ;
   RECT 43.008000 484.336000 43.200000 484.368000 ;
  END
 END pi1[239]
 PIN pi1[240]
  DIRECTION OUTPUT ;
  USE SIGNAL ;
  PORT
   LAYER M4 ;
   RECT 43.008000 484.476000 43.200000 484.500000 ;
  END
 END pi1[240]
 PIN pi1[241]
  DIRECTION OUTPUT ;
  USE SIGNAL ;
  PORT
   LAYER M6 ;
   RECT 43.008000 484.592000 43.200000 484.624000 ;
  END
 END pi1[241]
 PIN pi1[242]
  DIRECTION OUTPUT ;
  USE SIGNAL ;
  PORT
   LAYER M4 ;
   RECT 43.008000 484.812000 43.200000 484.836000 ;
  END
 END pi1[242]
 PIN pi1[243]
  DIRECTION OUTPUT ;
  USE SIGNAL ;
  PORT
   LAYER M6 ;
   RECT 43.008000 484.848000 43.200000 484.880000 ;
  END
 END pi1[243]
 PIN pi1[244]
  DIRECTION OUTPUT ;
  USE SIGNAL ;
  PORT
   LAYER M4 ;
   RECT 43.008000 485.148000 43.200000 485.172000 ;
  END
 END pi1[244]
 PIN pi1[245]
  DIRECTION OUTPUT ;
  USE SIGNAL ;
  PORT
   LAYER M6 ;
   RECT 43.008000 485.104000 43.200000 485.136000 ;
  END
 END pi1[245]
 PIN pi1[246]
  DIRECTION OUTPUT ;
  USE SIGNAL ;
  PORT
   LAYER M4 ;
   RECT 43.008000 485.484000 43.200000 485.508000 ;
  END
 END pi1[246]
 PIN pi1[247]
  DIRECTION OUTPUT ;
  USE SIGNAL ;
  PORT
   LAYER M6 ;
   RECT 43.008000 485.360000 43.200000 485.392000 ;
  END
 END pi1[247]
 PIN pi1[248]
  DIRECTION OUTPUT ;
  USE SIGNAL ;
  PORT
   LAYER M4 ;
   RECT 43.008000 485.820000 43.200000 485.844000 ;
  END
 END pi1[248]
 PIN pi1[249]
  DIRECTION OUTPUT ;
  USE SIGNAL ;
  PORT
   LAYER M6 ;
   RECT 43.008000 486.576000 43.200000 486.608000 ;
  END
 END pi1[249]
 PIN pi1[250]
  DIRECTION OUTPUT ;
  USE SIGNAL ;
  PORT
   LAYER M4 ;
   RECT 43.008000 486.156000 43.200000 486.180000 ;
  END
 END pi1[250]
 PIN pi1[251]
  DIRECTION OUTPUT ;
  USE SIGNAL ;
  PORT
   LAYER M6 ;
   RECT 43.008000 486.832000 43.200000 486.864000 ;
  END
 END pi1[251]
 PIN pi1[252]
  DIRECTION OUTPUT ;
  USE SIGNAL ;
  PORT
   LAYER M4 ;
   RECT 43.008000 486.444000 43.200000 486.468000 ;
  END
 END pi1[252]
 PIN pi1[253]
  DIRECTION OUTPUT ;
  USE SIGNAL ;
  PORT
   LAYER M6 ;
   RECT 43.008000 487.152000 43.200000 487.184000 ;
  END
 END pi1[253]
 PIN pi1[254]
  DIRECTION OUTPUT ;
  USE SIGNAL ;
  PORT
   LAYER M4 ;
   RECT 43.008000 486.780000 43.200000 486.804000 ;
  END
 END pi1[254]
 PIN pi1[255]
  DIRECTION OUTPUT ;
  USE SIGNAL ;
  PORT
   LAYER M6 ;
   RECT 43.008000 487.408000 43.200000 487.440000 ;
  END
 END pi1[255]
 PIN pi1[256]
  DIRECTION OUTPUT ;
  USE SIGNAL ;
  PORT
   LAYER M4 ;
   RECT 43.008000 487.116000 43.200000 487.140000 ;
  END
 END pi1[256]
 PIN pi1[257]
  DIRECTION OUTPUT ;
  USE SIGNAL ;
  PORT
   LAYER M6 ;
   RECT 43.008000 487.664000 43.200000 487.696000 ;
  END
 END pi1[257]
 PIN pi1[258]
  DIRECTION OUTPUT ;
  USE SIGNAL ;
  PORT
   LAYER M4 ;
   RECT 43.008000 487.452000 43.200000 487.476000 ;
  END
 END pi1[258]
 PIN pi1[259]
  DIRECTION OUTPUT ;
  USE SIGNAL ;
  PORT
   LAYER M6 ;
   RECT 43.008000 487.920000 43.200000 487.952000 ;
  END
 END pi1[259]
 PIN pi1[260]
  DIRECTION OUTPUT ;
  USE SIGNAL ;
  PORT
   LAYER M4 ;
   RECT 43.008000 487.788000 43.200000 487.812000 ;
  END
 END pi1[260]
 PIN pi1[261]
  DIRECTION OUTPUT ;
  USE SIGNAL ;
  PORT
   LAYER M6 ;
   RECT 43.008000 488.176000 43.200000 488.208000 ;
  END
 END pi1[261]
 PIN pi1[262]
  DIRECTION OUTPUT ;
  USE SIGNAL ;
  PORT
   LAYER M4 ;
   RECT 43.008000 488.124000 43.200000 488.148000 ;
  END
 END pi1[262]
 PIN pi1[263]
  DIRECTION OUTPUT ;
  USE SIGNAL ;
  PORT
   LAYER M6 ;
   RECT 43.008000 488.432000 43.200000 488.464000 ;
  END
 END pi1[263]
 PIN pi1[264]
  DIRECTION OUTPUT ;
  USE SIGNAL ;
  PORT
   LAYER M4 ;
   RECT 43.008000 488.460000 43.200000 488.484000 ;
  END
 END pi1[264]
 PIN pi1[265]
  DIRECTION OUTPUT ;
  USE SIGNAL ;
  PORT
   LAYER M6 ;
   RECT 43.008000 488.688000 43.200000 488.720000 ;
  END
 END pi1[265]
 PIN pi1[266]
  DIRECTION OUTPUT ;
  USE SIGNAL ;
  PORT
   LAYER M4 ;
   RECT 43.008000 488.796000 43.200000 488.820000 ;
  END
 END pi1[266]
 PIN pi1[267]
  DIRECTION OUTPUT ;
  USE SIGNAL ;
  PORT
   LAYER M6 ;
   RECT 43.008000 488.944000 43.200000 488.976000 ;
  END
 END pi1[267]
 PIN pi1[268]
  DIRECTION OUTPUT ;
  USE SIGNAL ;
  PORT
   LAYER M4 ;
   RECT 43.008000 489.132000 43.200000 489.156000 ;
  END
 END pi1[268]
 PIN pi1[269]
  DIRECTION OUTPUT ;
  USE SIGNAL ;
  PORT
   LAYER M6 ;
   RECT 43.008000 489.200000 43.200000 489.232000 ;
  END
 END pi1[269]
 PIN pi1[270]
  DIRECTION OUTPUT ;
  USE SIGNAL ;
  PORT
   LAYER M4 ;
   RECT 43.008000 489.468000 43.200000 489.492000 ;
  END
 END pi1[270]
 PIN pi1[271]
  DIRECTION OUTPUT ;
  USE SIGNAL ;
  PORT
   LAYER M6 ;
   RECT 43.008000 489.456000 43.200000 489.488000 ;
  END
 END pi1[271]
 PIN pi1[272]
  DIRECTION OUTPUT ;
  USE SIGNAL ;
  PORT
   LAYER M4 ;
   RECT 43.008000 489.804000 43.200000 489.828000 ;
  END
 END pi1[272]
 PIN pi1[273]
  DIRECTION OUTPUT ;
  USE SIGNAL ;
  PORT
   LAYER M6 ;
   RECT 43.008000 489.776000 43.200000 489.808000 ;
  END
 END pi1[273]
 PIN pi1[274]
  DIRECTION OUTPUT ;
  USE SIGNAL ;
  PORT
   LAYER M4 ;
   RECT 43.008000 490.140000 43.200000 490.164000 ;
  END
 END pi1[274]
 PIN pi1[275]
  DIRECTION OUTPUT ;
  USE SIGNAL ;
  PORT
   LAYER M6 ;
   RECT 43.008000 490.992000 43.200000 491.024000 ;
  END
 END pi1[275]
 PIN pi1[276]
  DIRECTION OUTPUT ;
  USE SIGNAL ;
  PORT
   LAYER M4 ;
   RECT 43.008000 490.476000 43.200000 490.500000 ;
  END
 END pi1[276]
 PIN pi1[277]
  DIRECTION OUTPUT ;
  USE SIGNAL ;
  PORT
   LAYER M6 ;
   RECT 43.008000 491.248000 43.200000 491.280000 ;
  END
 END pi1[277]
 PIN pi1[278]
  DIRECTION OUTPUT ;
  USE SIGNAL ;
  PORT
   LAYER M4 ;
   RECT 43.008000 490.812000 43.200000 490.836000 ;
  END
 END pi1[278]
 PIN pi1[279]
  DIRECTION OUTPUT ;
  USE SIGNAL ;
  PORT
   LAYER M6 ;
   RECT 43.008000 491.504000 43.200000 491.536000 ;
  END
 END pi1[279]
 PIN pi1[280]
  DIRECTION OUTPUT ;
  USE SIGNAL ;
  PORT
   LAYER M4 ;
   RECT 43.008000 491.148000 43.200000 491.172000 ;
  END
 END pi1[280]
 PIN pi1[281]
  DIRECTION OUTPUT ;
  USE SIGNAL ;
  PORT
   LAYER M6 ;
   RECT 43.008000 491.760000 43.200000 491.792000 ;
  END
 END pi1[281]
 PIN pi1[282]
  DIRECTION OUTPUT ;
  USE SIGNAL ;
  PORT
   LAYER M4 ;
   RECT 43.008000 491.484000 43.200000 491.508000 ;
  END
 END pi1[282]
 PIN pi1[283]
  DIRECTION OUTPUT ;
  USE SIGNAL ;
  PORT
   LAYER M6 ;
   RECT 43.008000 492.016000 43.200000 492.048000 ;
  END
 END pi1[283]
 PIN pi1[284]
  DIRECTION OUTPUT ;
  USE SIGNAL ;
  PORT
   LAYER M4 ;
   RECT 43.008000 491.820000 43.200000 491.844000 ;
  END
 END pi1[284]
 PIN pi1[285]
  DIRECTION OUTPUT ;
  USE SIGNAL ;
  PORT
   LAYER M6 ;
   RECT 43.008000 492.272000 43.200000 492.304000 ;
  END
 END pi1[285]
 PIN pi1[286]
  DIRECTION OUTPUT ;
  USE SIGNAL ;
  PORT
   LAYER M4 ;
   RECT 43.008000 492.156000 43.200000 492.180000 ;
  END
 END pi1[286]
 PIN pi1[287]
  DIRECTION OUTPUT ;
  USE SIGNAL ;
  PORT
   LAYER M6 ;
   RECT 43.008000 492.528000 43.200000 492.560000 ;
  END
 END pi1[287]
 PIN pi1[288]
  DIRECTION OUTPUT ;
  USE SIGNAL ;
  PORT
   LAYER M4 ;
   RECT 43.008000 492.492000 43.200000 492.516000 ;
  END
 END pi1[288]
 PIN fh1[0]
  DIRECTION OUTPUT ;
  USE SIGNAL ;
  PORT
   LAYER M6 ;
   RECT 43.008000 418.800000 43.200000 418.832000 ;
  END
 END fh1[0]
 PIN fh1[1]
  DIRECTION OUTPUT ;
  USE SIGNAL ;
  PORT
   LAYER M4 ;
   RECT 43.008000 419.100000 43.200000 419.124000 ;
  END
 END fh1[1]
 PIN fh1[2]
  DIRECTION OUTPUT ;
  USE SIGNAL ;
  PORT
   LAYER M6 ;
   RECT 43.008000 419.120000 43.200000 419.152000 ;
  END
 END fh1[2]
 PIN fh1[3]
  DIRECTION OUTPUT ;
  USE SIGNAL ;
  PORT
   LAYER M4 ;
   RECT 43.008000 419.436000 43.200000 419.460000 ;
  END
 END fh1[3]
 PIN rh1[0]
  DIRECTION OUTPUT ;
  USE SIGNAL ;
  PORT
   LAYER M6 ;
   RECT 43.008000 492.784000 43.200000 492.816000 ;
  END
 END rh1[0]
 PIN rh1[1]
  DIRECTION OUTPUT ;
  USE SIGNAL ;
  PORT
   LAYER M4 ;
   RECT 43.008000 492.780000 43.200000 492.804000 ;
  END
 END rh1[1]
 PIN rh1[2]
  DIRECTION OUTPUT ;
  USE SIGNAL ;
  PORT
   LAYER M6 ;
   RECT 43.008000 493.040000 43.200000 493.072000 ;
  END
 END rh1[2]
 PIN rh1[3]
  DIRECTION OUTPUT ;
  USE SIGNAL ;
  PORT
   LAYER M4 ;
   RECT 43.008000 493.116000 43.200000 493.140000 ;
  END
 END rh1[3]
 PIN po2[0]
  DIRECTION INPUT ;
  USE SIGNAL ;
  PORT
   LAYER M4 ;
   RECT 43.008000 185.532000 43.200000 185.556000 ;
  END
 END po2[0]
 PIN po2[1]
  DIRECTION INPUT ;
  USE SIGNAL ;
  PORT
   LAYER M6 ;
   RECT 43.008000 185.520000 43.200000 185.552000 ;
  END
 END po2[1]
 PIN po2[2]
  DIRECTION INPUT ;
  USE SIGNAL ;
  PORT
   LAYER M4 ;
   RECT 43.008000 185.868000 43.200000 185.892000 ;
  END
 END po2[2]
 PIN po2[3]
  DIRECTION INPUT ;
  USE SIGNAL ;
  PORT
   LAYER M6 ;
   RECT 43.008000 185.904000 43.200000 185.936000 ;
  END
 END po2[3]
 PIN po2[4]
  DIRECTION INPUT ;
  USE SIGNAL ;
  PORT
   LAYER M4 ;
   RECT 43.008000 186.204000 43.200000 186.228000 ;
  END
 END po2[4]
 PIN po2[5]
  DIRECTION INPUT ;
  USE SIGNAL ;
  PORT
   LAYER M6 ;
   RECT 43.008000 186.224000 43.200000 186.256000 ;
  END
 END po2[5]
 PIN po2[6]
  DIRECTION INPUT ;
  USE SIGNAL ;
  PORT
   LAYER M4 ;
   RECT 43.008000 186.540000 43.200000 186.564000 ;
  END
 END po2[6]
 PIN po2[7]
  DIRECTION INPUT ;
  USE SIGNAL ;
  PORT
   LAYER M6 ;
   RECT 43.008000 186.544000 43.200000 186.576000 ;
  END
 END po2[7]
 PIN po2[8]
  DIRECTION INPUT ;
  USE SIGNAL ;
  PORT
   LAYER M4 ;
   RECT 43.008000 186.876000 43.200000 186.900000 ;
  END
 END po2[8]
 PIN po2[9]
  DIRECTION INPUT ;
  USE SIGNAL ;
  PORT
   LAYER M6 ;
   RECT 43.008000 186.864000 43.200000 186.896000 ;
  END
 END po2[9]
 PIN po2[10]
  DIRECTION INPUT ;
  USE SIGNAL ;
  PORT
   LAYER M4 ;
   RECT 43.008000 187.212000 43.200000 187.236000 ;
  END
 END po2[10]
 PIN po2[11]
  DIRECTION INPUT ;
  USE SIGNAL ;
  PORT
   LAYER M6 ;
   RECT 43.008000 187.184000 43.200000 187.216000 ;
  END
 END po2[11]
 PIN po2[12]
  DIRECTION INPUT ;
  USE SIGNAL ;
  PORT
   LAYER M4 ;
   RECT 43.008000 187.548000 43.200000 187.572000 ;
  END
 END po2[12]
 PIN po2[13]
  DIRECTION INPUT ;
  USE SIGNAL ;
  PORT
   LAYER M6 ;
   RECT 43.008000 187.376000 43.200000 187.408000 ;
  END
 END po2[13]
 PIN po2[14]
  DIRECTION INPUT ;
  USE SIGNAL ;
  PORT
   LAYER M4 ;
   RECT 43.008000 187.884000 43.200000 187.908000 ;
  END
 END po2[14]
 PIN po2[15]
  DIRECTION INPUT ;
  USE SIGNAL ;
  PORT
   LAYER M6 ;
   RECT 43.008000 188.400000 43.200000 188.432000 ;
  END
 END po2[15]
 PIN po2[16]
  DIRECTION INPUT ;
  USE SIGNAL ;
  PORT
   LAYER M4 ;
   RECT 43.008000 188.220000 43.200000 188.244000 ;
  END
 END po2[16]
 PIN po2[17]
  DIRECTION INPUT ;
  USE SIGNAL ;
  PORT
   LAYER M6 ;
   RECT 43.008000 188.464000 43.200000 188.496000 ;
  END
 END po2[17]
 PIN po2[18]
  DIRECTION INPUT ;
  USE SIGNAL ;
  PORT
   LAYER M4 ;
   RECT 43.008000 188.556000 43.200000 188.580000 ;
  END
 END po2[18]
 PIN po2[19]
  DIRECTION INPUT ;
  USE SIGNAL ;
  PORT
   LAYER M6 ;
   RECT 43.008000 188.528000 43.200000 188.560000 ;
  END
 END po2[19]
 PIN po2[20]
  DIRECTION INPUT ;
  USE SIGNAL ;
  PORT
   LAYER M4 ;
   RECT 43.008000 188.892000 43.200000 188.916000 ;
  END
 END po2[20]
 PIN po2[21]
  DIRECTION INPUT ;
  USE SIGNAL ;
  PORT
   LAYER M6 ;
   RECT 43.008000 188.912000 43.200000 188.944000 ;
  END
 END po2[21]
 PIN po2[22]
  DIRECTION INPUT ;
  USE SIGNAL ;
  PORT
   LAYER M4 ;
   RECT 43.008000 189.180000 43.200000 189.204000 ;
  END
 END po2[22]
 PIN po2[23]
  DIRECTION INPUT ;
  USE SIGNAL ;
  PORT
   LAYER M6 ;
   RECT 43.008000 189.232000 43.200000 189.264000 ;
  END
 END po2[23]
 PIN po2[24]
  DIRECTION INPUT ;
  USE SIGNAL ;
  PORT
   LAYER M4 ;
   RECT 43.008000 189.516000 43.200000 189.540000 ;
  END
 END po2[24]
 PIN po2[25]
  DIRECTION INPUT ;
  USE SIGNAL ;
  PORT
   LAYER M6 ;
   RECT 43.008000 189.552000 43.200000 189.584000 ;
  END
 END po2[25]
 PIN po2[26]
  DIRECTION INPUT ;
  USE SIGNAL ;
  PORT
   LAYER M4 ;
   RECT 43.008000 189.852000 43.200000 189.876000 ;
  END
 END po2[26]
 PIN po2[27]
  DIRECTION INPUT ;
  USE SIGNAL ;
  PORT
   LAYER M6 ;
   RECT 43.008000 189.872000 43.200000 189.904000 ;
  END
 END po2[27]
 PIN po2[28]
  DIRECTION INPUT ;
  USE SIGNAL ;
  PORT
   LAYER M4 ;
   RECT 43.008000 190.188000 43.200000 190.212000 ;
  END
 END po2[28]
 PIN po2[29]
  DIRECTION INPUT ;
  USE SIGNAL ;
  PORT
   LAYER M6 ;
   RECT 43.008000 190.192000 43.200000 190.224000 ;
  END
 END po2[29]
 PIN po2[30]
  DIRECTION INPUT ;
  USE SIGNAL ;
  PORT
   LAYER M4 ;
   RECT 43.008000 190.524000 43.200000 190.548000 ;
  END
 END po2[30]
 PIN po2[31]
  DIRECTION INPUT ;
  USE SIGNAL ;
  PORT
   LAYER M6 ;
   RECT 43.008000 190.576000 43.200000 190.608000 ;
  END
 END po2[31]
 PIN po2[32]
  DIRECTION INPUT ;
  USE SIGNAL ;
  PORT
   LAYER M4 ;
   RECT 43.008000 190.860000 43.200000 190.884000 ;
  END
 END po2[32]
 PIN po2[33]
  DIRECTION INPUT ;
  USE SIGNAL ;
  PORT
   LAYER M6 ;
   RECT 43.008000 190.896000 43.200000 190.928000 ;
  END
 END po2[33]
 PIN po2[34]
  DIRECTION INPUT ;
  USE SIGNAL ;
  PORT
   LAYER M4 ;
   RECT 43.008000 191.196000 43.200000 191.220000 ;
  END
 END po2[34]
 PIN po2[35]
  DIRECTION INPUT ;
  USE SIGNAL ;
  PORT
   LAYER M6 ;
   RECT 43.008000 191.216000 43.200000 191.248000 ;
  END
 END po2[35]
 PIN po2[36]
  DIRECTION INPUT ;
  USE SIGNAL ;
  PORT
   LAYER M4 ;
   RECT 43.008000 191.532000 43.200000 191.556000 ;
  END
 END po2[36]
 PIN po2[37]
  DIRECTION INPUT ;
  USE SIGNAL ;
  PORT
   LAYER M6 ;
   RECT 43.008000 191.536000 43.200000 191.568000 ;
  END
 END po2[37]
 PIN po2[38]
  DIRECTION INPUT ;
  USE SIGNAL ;
  PORT
   LAYER M4 ;
   RECT 43.008000 191.868000 43.200000 191.892000 ;
  END
 END po2[38]
 PIN po2[39]
  DIRECTION INPUT ;
  USE SIGNAL ;
  PORT
   LAYER M6 ;
   RECT 43.008000 191.728000 43.200000 191.760000 ;
  END
 END po2[39]
 PIN po2[40]
  DIRECTION INPUT ;
  USE SIGNAL ;
  PORT
   LAYER M4 ;
   RECT 43.008000 192.204000 43.200000 192.228000 ;
  END
 END po2[40]
 PIN po2[41]
  DIRECTION INPUT ;
  USE SIGNAL ;
  PORT
   LAYER M6 ;
   RECT 43.008000 192.752000 43.200000 192.784000 ;
  END
 END po2[41]
 PIN po2[42]
  DIRECTION INPUT ;
  USE SIGNAL ;
  PORT
   LAYER M4 ;
   RECT 43.008000 192.540000 43.200000 192.564000 ;
  END
 END po2[42]
 PIN po2[43]
  DIRECTION INPUT ;
  USE SIGNAL ;
  PORT
   LAYER M6 ;
   RECT 43.008000 192.816000 43.200000 192.848000 ;
  END
 END po2[43]
 PIN po2[44]
  DIRECTION INPUT ;
  USE SIGNAL ;
  PORT
   LAYER M4 ;
   RECT 43.008000 192.876000 43.200000 192.900000 ;
  END
 END po2[44]
 PIN po2[45]
  DIRECTION INPUT ;
  USE SIGNAL ;
  PORT
   LAYER M6 ;
   RECT 43.008000 192.880000 43.200000 192.912000 ;
  END
 END po2[45]
 PIN po2[46]
  DIRECTION INPUT ;
  USE SIGNAL ;
  PORT
   LAYER M4 ;
   RECT 43.008000 193.212000 43.200000 193.236000 ;
  END
 END po2[46]
 PIN po2[47]
  DIRECTION INPUT ;
  USE SIGNAL ;
  PORT
   LAYER M6 ;
   RECT 43.008000 193.264000 43.200000 193.296000 ;
  END
 END po2[47]
 PIN po2[48]
  DIRECTION INPUT ;
  USE SIGNAL ;
  PORT
   LAYER M4 ;
   RECT 43.008000 193.500000 43.200000 193.524000 ;
  END
 END po2[48]
 PIN po2[49]
  DIRECTION INPUT ;
  USE SIGNAL ;
  PORT
   LAYER M6 ;
   RECT 43.008000 193.584000 43.200000 193.616000 ;
  END
 END po2[49]
 PIN po2[50]
  DIRECTION INPUT ;
  USE SIGNAL ;
  PORT
   LAYER M4 ;
   RECT 43.008000 193.836000 43.200000 193.860000 ;
  END
 END po2[50]
 PIN po2[51]
  DIRECTION INPUT ;
  USE SIGNAL ;
  PORT
   LAYER M6 ;
   RECT 43.008000 193.904000 43.200000 193.936000 ;
  END
 END po2[51]
 PIN po2[52]
  DIRECTION INPUT ;
  USE SIGNAL ;
  PORT
   LAYER M4 ;
   RECT 43.008000 194.172000 43.200000 194.196000 ;
  END
 END po2[52]
 PIN po2[53]
  DIRECTION INPUT ;
  USE SIGNAL ;
  PORT
   LAYER M6 ;
   RECT 43.008000 194.224000 43.200000 194.256000 ;
  END
 END po2[53]
 PIN po2[54]
  DIRECTION INPUT ;
  USE SIGNAL ;
  PORT
   LAYER M4 ;
   RECT 43.008000 194.508000 43.200000 194.532000 ;
  END
 END po2[54]
 PIN po2[55]
  DIRECTION INPUT ;
  USE SIGNAL ;
  PORT
   LAYER M6 ;
   RECT 43.008000 194.544000 43.200000 194.576000 ;
  END
 END po2[55]
 PIN po2[56]
  DIRECTION INPUT ;
  USE SIGNAL ;
  PORT
   LAYER M4 ;
   RECT 43.008000 194.844000 43.200000 194.868000 ;
  END
 END po2[56]
 PIN po2[57]
  DIRECTION INPUT ;
  USE SIGNAL ;
  PORT
   LAYER M6 ;
   RECT 43.008000 194.928000 43.200000 194.960000 ;
  END
 END po2[57]
 PIN po2[58]
  DIRECTION INPUT ;
  USE SIGNAL ;
  PORT
   LAYER M4 ;
   RECT 43.008000 195.180000 43.200000 195.204000 ;
  END
 END po2[58]
 PIN po2[59]
  DIRECTION INPUT ;
  USE SIGNAL ;
  PORT
   LAYER M6 ;
   RECT 43.008000 195.248000 43.200000 195.280000 ;
  END
 END po2[59]
 PIN po2[60]
  DIRECTION INPUT ;
  USE SIGNAL ;
  PORT
   LAYER M4 ;
   RECT 43.008000 195.516000 43.200000 195.540000 ;
  END
 END po2[60]
 PIN po2[61]
  DIRECTION INPUT ;
  USE SIGNAL ;
  PORT
   LAYER M6 ;
   RECT 43.008000 195.568000 43.200000 195.600000 ;
  END
 END po2[61]
 PIN po2[62]
  DIRECTION INPUT ;
  USE SIGNAL ;
  PORT
   LAYER M4 ;
   RECT 43.008000 195.852000 43.200000 195.876000 ;
  END
 END po2[62]
 PIN po2[63]
  DIRECTION INPUT ;
  USE SIGNAL ;
  PORT
   LAYER M6 ;
   RECT 43.008000 195.888000 43.200000 195.920000 ;
  END
 END po2[63]
 PIN po2[64]
  DIRECTION INPUT ;
  USE SIGNAL ;
  PORT
   LAYER M4 ;
   RECT 43.008000 196.188000 43.200000 196.212000 ;
  END
 END po2[64]
 PIN po2[65]
  DIRECTION INPUT ;
  USE SIGNAL ;
  PORT
   LAYER M6 ;
   RECT 43.008000 196.016000 43.200000 196.048000 ;
  END
 END po2[65]
 PIN po2[66]
  DIRECTION INPUT ;
  USE SIGNAL ;
  PORT
   LAYER M4 ;
   RECT 43.008000 196.524000 43.200000 196.548000 ;
  END
 END po2[66]
 PIN po2[67]
  DIRECTION INPUT ;
  USE SIGNAL ;
  PORT
   LAYER M6 ;
   RECT 43.008000 197.040000 43.200000 197.072000 ;
  END
 END po2[67]
 PIN po2[68]
  DIRECTION INPUT ;
  USE SIGNAL ;
  PORT
   LAYER M4 ;
   RECT 43.008000 196.860000 43.200000 196.884000 ;
  END
 END po2[68]
 PIN po2[69]
  DIRECTION INPUT ;
  USE SIGNAL ;
  PORT
   LAYER M6 ;
   RECT 43.008000 197.104000 43.200000 197.136000 ;
  END
 END po2[69]
 PIN po2[70]
  DIRECTION INPUT ;
  USE SIGNAL ;
  PORT
   LAYER M4 ;
   RECT 43.008000 197.196000 43.200000 197.220000 ;
  END
 END po2[70]
 PIN po2[71]
  DIRECTION INPUT ;
  USE SIGNAL ;
  PORT
   LAYER M6 ;
   RECT 43.008000 197.232000 43.200000 197.264000 ;
  END
 END po2[71]
 PIN po2[72]
  DIRECTION INPUT ;
  USE SIGNAL ;
  PORT
   LAYER M4 ;
   RECT 43.008000 197.532000 43.200000 197.556000 ;
  END
 END po2[72]
 PIN po2[73]
  DIRECTION INPUT ;
  USE SIGNAL ;
  PORT
   LAYER M6 ;
   RECT 43.008000 197.552000 43.200000 197.584000 ;
  END
 END po2[73]
 PIN po2[74]
  DIRECTION INPUT ;
  USE SIGNAL ;
  PORT
   LAYER M4 ;
   RECT 43.008000 197.820000 43.200000 197.844000 ;
  END
 END po2[74]
 PIN po2[75]
  DIRECTION INPUT ;
  USE SIGNAL ;
  PORT
   LAYER M6 ;
   RECT 43.008000 197.936000 43.200000 197.968000 ;
  END
 END po2[75]
 PIN po2[76]
  DIRECTION INPUT ;
  USE SIGNAL ;
  PORT
   LAYER M4 ;
   RECT 43.008000 198.156000 43.200000 198.180000 ;
  END
 END po2[76]
 PIN po2[77]
  DIRECTION INPUT ;
  USE SIGNAL ;
  PORT
   LAYER M6 ;
   RECT 43.008000 198.256000 43.200000 198.288000 ;
  END
 END po2[77]
 PIN po2[78]
  DIRECTION INPUT ;
  USE SIGNAL ;
  PORT
   LAYER M4 ;
   RECT 43.008000 198.492000 43.200000 198.516000 ;
  END
 END po2[78]
 PIN po2[79]
  DIRECTION INPUT ;
  USE SIGNAL ;
  PORT
   LAYER M6 ;
   RECT 43.008000 198.576000 43.200000 198.608000 ;
  END
 END po2[79]
 PIN po2[80]
  DIRECTION INPUT ;
  USE SIGNAL ;
  PORT
   LAYER M4 ;
   RECT 43.008000 198.828000 43.200000 198.852000 ;
  END
 END po2[80]
 PIN po2[81]
  DIRECTION INPUT ;
  USE SIGNAL ;
  PORT
   LAYER M6 ;
   RECT 43.008000 198.896000 43.200000 198.928000 ;
  END
 END po2[81]
 PIN po2[82]
  DIRECTION INPUT ;
  USE SIGNAL ;
  PORT
   LAYER M4 ;
   RECT 43.008000 199.164000 43.200000 199.188000 ;
  END
 END po2[82]
 PIN po2[83]
  DIRECTION INPUT ;
  USE SIGNAL ;
  PORT
   LAYER M6 ;
   RECT 43.008000 199.280000 43.200000 199.312000 ;
  END
 END po2[83]
 PIN po2[84]
  DIRECTION INPUT ;
  USE SIGNAL ;
  PORT
   LAYER M4 ;
   RECT 43.008000 199.500000 43.200000 199.524000 ;
  END
 END po2[84]
 PIN po2[85]
  DIRECTION INPUT ;
  USE SIGNAL ;
  PORT
   LAYER M6 ;
   RECT 43.008000 199.600000 43.200000 199.632000 ;
  END
 END po2[85]
 PIN po2[86]
  DIRECTION INPUT ;
  USE SIGNAL ;
  PORT
   LAYER M4 ;
   RECT 43.008000 199.836000 43.200000 199.860000 ;
  END
 END po2[86]
 PIN po2[87]
  DIRECTION INPUT ;
  USE SIGNAL ;
  PORT
   LAYER M6 ;
   RECT 43.008000 199.920000 43.200000 199.952000 ;
  END
 END po2[87]
 PIN po2[88]
  DIRECTION INPUT ;
  USE SIGNAL ;
  PORT
   LAYER M4 ;
   RECT 43.008000 200.172000 43.200000 200.196000 ;
  END
 END po2[88]
 PIN po2[89]
  DIRECTION INPUT ;
  USE SIGNAL ;
  PORT
   LAYER M6 ;
   RECT 43.008000 200.240000 43.200000 200.272000 ;
  END
 END po2[89]
 PIN po2[90]
  DIRECTION INPUT ;
  USE SIGNAL ;
  PORT
   LAYER M4 ;
   RECT 43.008000 200.508000 43.200000 200.532000 ;
  END
 END po2[90]
 PIN po2[91]
  DIRECTION INPUT ;
  USE SIGNAL ;
  PORT
   LAYER M6 ;
   RECT 43.008000 200.368000 43.200000 200.400000 ;
  END
 END po2[91]
 PIN po2[92]
  DIRECTION INPUT ;
  USE SIGNAL ;
  PORT
   LAYER M4 ;
   RECT 43.008000 200.844000 43.200000 200.868000 ;
  END
 END po2[92]
 PIN po2[93]
  DIRECTION INPUT ;
  USE SIGNAL ;
  PORT
   LAYER M6 ;
   RECT 43.008000 201.392000 43.200000 201.424000 ;
  END
 END po2[93]
 PIN po2[94]
  DIRECTION INPUT ;
  USE SIGNAL ;
  PORT
   LAYER M4 ;
   RECT 43.008000 201.180000 43.200000 201.204000 ;
  END
 END po2[94]
 PIN po2[95]
  DIRECTION INPUT ;
  USE SIGNAL ;
  PORT
   LAYER M6 ;
   RECT 43.008000 201.456000 43.200000 201.488000 ;
  END
 END po2[95]
 PIN po2[96]
  DIRECTION INPUT ;
  USE SIGNAL ;
  PORT
   LAYER M4 ;
   RECT 43.008000 201.516000 43.200000 201.540000 ;
  END
 END po2[96]
 PIN po2[97]
  DIRECTION INPUT ;
  USE SIGNAL ;
  PORT
   LAYER M6 ;
   RECT 43.008000 201.584000 43.200000 201.616000 ;
  END
 END po2[97]
 PIN po2[98]
  DIRECTION INPUT ;
  USE SIGNAL ;
  PORT
   LAYER M4 ;
   RECT 43.008000 201.852000 43.200000 201.876000 ;
  END
 END po2[98]
 PIN po2[99]
  DIRECTION INPUT ;
  USE SIGNAL ;
  PORT
   LAYER M6 ;
   RECT 43.008000 201.904000 43.200000 201.936000 ;
  END
 END po2[99]
 PIN po2[100]
  DIRECTION INPUT ;
  USE SIGNAL ;
  PORT
   LAYER M4 ;
   RECT 43.008000 202.188000 43.200000 202.212000 ;
  END
 END po2[100]
 PIN po2[101]
  DIRECTION INPUT ;
  USE SIGNAL ;
  PORT
   LAYER M6 ;
   RECT 43.008000 202.288000 43.200000 202.320000 ;
  END
 END po2[101]
 PIN po2[102]
  DIRECTION INPUT ;
  USE SIGNAL ;
  PORT
   LAYER M4 ;
   RECT 43.008000 202.476000 43.200000 202.500000 ;
  END
 END po2[102]
 PIN po2[103]
  DIRECTION INPUT ;
  USE SIGNAL ;
  PORT
   LAYER M6 ;
   RECT 43.008000 202.608000 43.200000 202.640000 ;
  END
 END po2[103]
 PIN po2[104]
  DIRECTION INPUT ;
  USE SIGNAL ;
  PORT
   LAYER M4 ;
   RECT 43.008000 202.812000 43.200000 202.836000 ;
  END
 END po2[104]
 PIN po2[105]
  DIRECTION INPUT ;
  USE SIGNAL ;
  PORT
   LAYER M6 ;
   RECT 43.008000 202.928000 43.200000 202.960000 ;
  END
 END po2[105]
 PIN po2[106]
  DIRECTION INPUT ;
  USE SIGNAL ;
  PORT
   LAYER M4 ;
   RECT 43.008000 203.148000 43.200000 203.172000 ;
  END
 END po2[106]
 PIN po2[107]
  DIRECTION INPUT ;
  USE SIGNAL ;
  PORT
   LAYER M6 ;
   RECT 43.008000 203.248000 43.200000 203.280000 ;
  END
 END po2[107]
 PIN po2[108]
  DIRECTION INPUT ;
  USE SIGNAL ;
  PORT
   LAYER M4 ;
   RECT 43.008000 203.484000 43.200000 203.508000 ;
  END
 END po2[108]
 PIN po2[109]
  DIRECTION INPUT ;
  USE SIGNAL ;
  PORT
   LAYER M6 ;
   RECT 43.008000 203.632000 43.200000 203.664000 ;
  END
 END po2[109]
 PIN po2[110]
  DIRECTION INPUT ;
  USE SIGNAL ;
  PORT
   LAYER M4 ;
   RECT 43.008000 203.820000 43.200000 203.844000 ;
  END
 END po2[110]
 PIN po2[111]
  DIRECTION INPUT ;
  USE SIGNAL ;
  PORT
   LAYER M6 ;
   RECT 43.008000 203.952000 43.200000 203.984000 ;
  END
 END po2[111]
 PIN po2[112]
  DIRECTION INPUT ;
  USE SIGNAL ;
  PORT
   LAYER M4 ;
   RECT 43.008000 204.156000 43.200000 204.180000 ;
  END
 END po2[112]
 PIN po2[113]
  DIRECTION INPUT ;
  USE SIGNAL ;
  PORT
   LAYER M6 ;
   RECT 43.008000 204.272000 43.200000 204.304000 ;
  END
 END po2[113]
 PIN po2[114]
  DIRECTION INPUT ;
  USE SIGNAL ;
  PORT
   LAYER M4 ;
   RECT 43.008000 204.492000 43.200000 204.516000 ;
  END
 END po2[114]
 PIN po2[115]
  DIRECTION INPUT ;
  USE SIGNAL ;
  PORT
   LAYER M6 ;
   RECT 43.008000 204.592000 43.200000 204.624000 ;
  END
 END po2[115]
 PIN po2[116]
  DIRECTION INPUT ;
  USE SIGNAL ;
  PORT
   LAYER M4 ;
   RECT 43.008000 204.828000 43.200000 204.852000 ;
  END
 END po2[116]
 PIN po2[117]
  DIRECTION INPUT ;
  USE SIGNAL ;
  PORT
   LAYER M6 ;
   RECT 43.008000 204.656000 43.200000 204.688000 ;
  END
 END po2[117]
 PIN po2[118]
  DIRECTION INPUT ;
  USE SIGNAL ;
  PORT
   LAYER M4 ;
   RECT 43.008000 205.164000 43.200000 205.188000 ;
  END
 END po2[118]
 PIN po2[119]
  DIRECTION INPUT ;
  USE SIGNAL ;
  PORT
   LAYER M6 ;
   RECT 43.008000 205.680000 43.200000 205.712000 ;
  END
 END po2[119]
 PIN po2[120]
  DIRECTION INPUT ;
  USE SIGNAL ;
  PORT
   LAYER M4 ;
   RECT 43.008000 205.500000 43.200000 205.524000 ;
  END
 END po2[120]
 PIN po2[121]
  DIRECTION INPUT ;
  USE SIGNAL ;
  PORT
   LAYER M6 ;
   RECT 43.008000 205.744000 43.200000 205.776000 ;
  END
 END po2[121]
 PIN po2[122]
  DIRECTION INPUT ;
  USE SIGNAL ;
  PORT
   LAYER M4 ;
   RECT 43.008000 205.836000 43.200000 205.860000 ;
  END
 END po2[122]
 PIN po2[123]
  DIRECTION INPUT ;
  USE SIGNAL ;
  PORT
   LAYER M6 ;
   RECT 43.008000 205.936000 43.200000 205.968000 ;
  END
 END po2[123]
 PIN po2[124]
  DIRECTION INPUT ;
  USE SIGNAL ;
  PORT
   LAYER M4 ;
   RECT 43.008000 206.172000 43.200000 206.196000 ;
  END
 END po2[124]
 PIN po2[125]
  DIRECTION INPUT ;
  USE SIGNAL ;
  PORT
   LAYER M6 ;
   RECT 43.008000 206.256000 43.200000 206.288000 ;
  END
 END po2[125]
 PIN po2[126]
  DIRECTION INPUT ;
  USE SIGNAL ;
  PORT
   LAYER M4 ;
   RECT 43.008000 206.508000 43.200000 206.532000 ;
  END
 END po2[126]
 PIN po2[127]
  DIRECTION INPUT ;
  USE SIGNAL ;
  PORT
   LAYER M6 ;
   RECT 43.008000 206.640000 43.200000 206.672000 ;
  END
 END po2[127]
 PIN po2[128]
  DIRECTION INPUT ;
  USE SIGNAL ;
  PORT
   LAYER M4 ;
   RECT 43.008000 206.796000 43.200000 206.820000 ;
  END
 END po2[128]
 PIN po2[129]
  DIRECTION INPUT ;
  USE SIGNAL ;
  PORT
   LAYER M6 ;
   RECT 43.008000 206.960000 43.200000 206.992000 ;
  END
 END po2[129]
 PIN po2[130]
  DIRECTION INPUT ;
  USE SIGNAL ;
  PORT
   LAYER M4 ;
   RECT 43.008000 207.132000 43.200000 207.156000 ;
  END
 END po2[130]
 PIN po2[131]
  DIRECTION INPUT ;
  USE SIGNAL ;
  PORT
   LAYER M6 ;
   RECT 43.008000 207.280000 43.200000 207.312000 ;
  END
 END po2[131]
 PIN po2[132]
  DIRECTION INPUT ;
  USE SIGNAL ;
  PORT
   LAYER M4 ;
   RECT 43.008000 207.468000 43.200000 207.492000 ;
  END
 END po2[132]
 PIN po2[133]
  DIRECTION INPUT ;
  USE SIGNAL ;
  PORT
   LAYER M6 ;
   RECT 43.008000 207.600000 43.200000 207.632000 ;
  END
 END po2[133]
 PIN po2[134]
  DIRECTION INPUT ;
  USE SIGNAL ;
  PORT
   LAYER M4 ;
   RECT 43.008000 207.804000 43.200000 207.828000 ;
  END
 END po2[134]
 PIN po2[135]
  DIRECTION INPUT ;
  USE SIGNAL ;
  PORT
   LAYER M6 ;
   RECT 43.008000 207.920000 43.200000 207.952000 ;
  END
 END po2[135]
 PIN po2[136]
  DIRECTION INPUT ;
  USE SIGNAL ;
  PORT
   LAYER M4 ;
   RECT 43.008000 208.140000 43.200000 208.164000 ;
  END
 END po2[136]
 PIN po2[137]
  DIRECTION INPUT ;
  USE SIGNAL ;
  PORT
   LAYER M6 ;
   RECT 43.008000 208.304000 43.200000 208.336000 ;
  END
 END po2[137]
 PIN po2[138]
  DIRECTION INPUT ;
  USE SIGNAL ;
  PORT
   LAYER M4 ;
   RECT 43.008000 208.476000 43.200000 208.500000 ;
  END
 END po2[138]
 PIN po2[139]
  DIRECTION INPUT ;
  USE SIGNAL ;
  PORT
   LAYER M6 ;
   RECT 43.008000 208.624000 43.200000 208.656000 ;
  END
 END po2[139]
 PIN po2[140]
  DIRECTION INPUT ;
  USE SIGNAL ;
  PORT
   LAYER M4 ;
   RECT 43.008000 208.812000 43.200000 208.836000 ;
  END
 END po2[140]
 PIN po2[141]
  DIRECTION INPUT ;
  USE SIGNAL ;
  PORT
   LAYER M6 ;
   RECT 43.008000 208.944000 43.200000 208.976000 ;
  END
 END po2[141]
 PIN po2[142]
  DIRECTION INPUT ;
  USE SIGNAL ;
  PORT
   LAYER M4 ;
   RECT 43.008000 209.148000 43.200000 209.172000 ;
  END
 END po2[142]
 PIN po2[143]
  DIRECTION INPUT ;
  USE SIGNAL ;
  PORT
   LAYER M6 ;
   RECT 43.008000 209.008000 43.200000 209.040000 ;
  END
 END po2[143]
 PIN po2[144]
  DIRECTION INPUT ;
  USE SIGNAL ;
  PORT
   LAYER M4 ;
   RECT 43.008000 209.484000 43.200000 209.508000 ;
  END
 END po2[144]
 PIN po2[145]
  DIRECTION INPUT ;
  USE SIGNAL ;
  PORT
   LAYER M6 ;
   RECT 43.008000 210.032000 43.200000 210.064000 ;
  END
 END po2[145]
 PIN po2[146]
  DIRECTION INPUT ;
  USE SIGNAL ;
  PORT
   LAYER M4 ;
   RECT 43.008000 209.820000 43.200000 209.844000 ;
  END
 END po2[146]
 PIN po2[147]
  DIRECTION INPUT ;
  USE SIGNAL ;
  PORT
   LAYER M6 ;
   RECT 43.008000 210.096000 43.200000 210.128000 ;
  END
 END po2[147]
 PIN po2[148]
  DIRECTION INPUT ;
  USE SIGNAL ;
  PORT
   LAYER M4 ;
   RECT 43.008000 210.156000 43.200000 210.180000 ;
  END
 END po2[148]
 PIN po2[149]
  DIRECTION INPUT ;
  USE SIGNAL ;
  PORT
   LAYER M6 ;
   RECT 43.008000 210.288000 43.200000 210.320000 ;
  END
 END po2[149]
 PIN po2[150]
  DIRECTION INPUT ;
  USE SIGNAL ;
  PORT
   LAYER M4 ;
   RECT 43.008000 210.492000 43.200000 210.516000 ;
  END
 END po2[150]
 PIN po2[151]
  DIRECTION INPUT ;
  USE SIGNAL ;
  PORT
   LAYER M6 ;
   RECT 43.008000 210.608000 43.200000 210.640000 ;
  END
 END po2[151]
 PIN po2[152]
  DIRECTION INPUT ;
  USE SIGNAL ;
  PORT
   LAYER M4 ;
   RECT 43.008000 210.828000 43.200000 210.852000 ;
  END
 END po2[152]
 PIN po2[153]
  DIRECTION INPUT ;
  USE SIGNAL ;
  PORT
   LAYER M6 ;
   RECT 43.008000 210.928000 43.200000 210.960000 ;
  END
 END po2[153]
 PIN po2[154]
  DIRECTION INPUT ;
  USE SIGNAL ;
  PORT
   LAYER M4 ;
   RECT 43.008000 211.164000 43.200000 211.188000 ;
  END
 END po2[154]
 PIN po2[155]
  DIRECTION INPUT ;
  USE SIGNAL ;
  PORT
   LAYER M6 ;
   RECT 43.008000 211.312000 43.200000 211.344000 ;
  END
 END po2[155]
 PIN po2[156]
  DIRECTION INPUT ;
  USE SIGNAL ;
  PORT
   LAYER M4 ;
   RECT 43.008000 211.452000 43.200000 211.476000 ;
  END
 END po2[156]
 PIN po2[157]
  DIRECTION INPUT ;
  USE SIGNAL ;
  PORT
   LAYER M6 ;
   RECT 43.008000 211.632000 43.200000 211.664000 ;
  END
 END po2[157]
 PIN po2[158]
  DIRECTION INPUT ;
  USE SIGNAL ;
  PORT
   LAYER M4 ;
   RECT 43.008000 211.788000 43.200000 211.812000 ;
  END
 END po2[158]
 PIN po2[159]
  DIRECTION INPUT ;
  USE SIGNAL ;
  PORT
   LAYER M6 ;
   RECT 43.008000 211.952000 43.200000 211.984000 ;
  END
 END po2[159]
 PIN po2[160]
  DIRECTION INPUT ;
  USE SIGNAL ;
  PORT
   LAYER M4 ;
   RECT 43.008000 212.124000 43.200000 212.148000 ;
  END
 END po2[160]
 PIN po2[161]
  DIRECTION INPUT ;
  USE SIGNAL ;
  PORT
   LAYER M6 ;
   RECT 43.008000 212.272000 43.200000 212.304000 ;
  END
 END po2[161]
 PIN po2[162]
  DIRECTION INPUT ;
  USE SIGNAL ;
  PORT
   LAYER M4 ;
   RECT 43.008000 212.460000 43.200000 212.484000 ;
  END
 END po2[162]
 PIN po2[163]
  DIRECTION INPUT ;
  USE SIGNAL ;
  PORT
   LAYER M6 ;
   RECT 43.008000 212.656000 43.200000 212.688000 ;
  END
 END po2[163]
 PIN po2[164]
  DIRECTION INPUT ;
  USE SIGNAL ;
  PORT
   LAYER M4 ;
   RECT 43.008000 212.796000 43.200000 212.820000 ;
  END
 END po2[164]
 PIN po2[165]
  DIRECTION INPUT ;
  USE SIGNAL ;
  PORT
   LAYER M6 ;
   RECT 43.008000 212.976000 43.200000 213.008000 ;
  END
 END po2[165]
 PIN po2[166]
  DIRECTION INPUT ;
  USE SIGNAL ;
  PORT
   LAYER M4 ;
   RECT 43.008000 213.132000 43.200000 213.156000 ;
  END
 END po2[166]
 PIN po2[167]
  DIRECTION INPUT ;
  USE SIGNAL ;
  PORT
   LAYER M6 ;
   RECT 43.008000 213.168000 43.200000 213.200000 ;
  END
 END po2[167]
 PIN po2[168]
  DIRECTION INPUT ;
  USE SIGNAL ;
  PORT
   LAYER M4 ;
   RECT 43.008000 213.468000 43.200000 213.492000 ;
  END
 END po2[168]
 PIN po2[169]
  DIRECTION INPUT ;
  USE SIGNAL ;
  PORT
   LAYER M6 ;
   RECT 43.008000 213.232000 43.200000 213.264000 ;
  END
 END po2[169]
 PIN po2[170]
  DIRECTION INPUT ;
  USE SIGNAL ;
  PORT
   LAYER M4 ;
   RECT 43.008000 213.804000 43.200000 213.828000 ;
  END
 END po2[170]
 PIN po2[171]
  DIRECTION INPUT ;
  USE SIGNAL ;
  PORT
   LAYER M6 ;
   RECT 43.008000 213.296000 43.200000 213.328000 ;
  END
 END po2[171]
 PIN po2[172]
  DIRECTION INPUT ;
  USE SIGNAL ;
  PORT
   LAYER M4 ;
   RECT 43.008000 214.140000 43.200000 214.164000 ;
  END
 END po2[172]
 PIN po2[173]
  DIRECTION INPUT ;
  USE SIGNAL ;
  PORT
   LAYER M6 ;
   RECT 43.008000 214.320000 43.200000 214.352000 ;
  END
 END po2[173]
 PIN po2[174]
  DIRECTION INPUT ;
  USE SIGNAL ;
  PORT
   LAYER M4 ;
   RECT 43.008000 214.476000 43.200000 214.500000 ;
  END
 END po2[174]
 PIN po2[175]
  DIRECTION INPUT ;
  USE SIGNAL ;
  PORT
   LAYER M6 ;
   RECT 43.008000 214.640000 43.200000 214.672000 ;
  END
 END po2[175]
 PIN po2[176]
  DIRECTION INPUT ;
  USE SIGNAL ;
  PORT
   LAYER M4 ;
   RECT 43.008000 214.812000 43.200000 214.836000 ;
  END
 END po2[176]
 PIN po2[177]
  DIRECTION INPUT ;
  USE SIGNAL ;
  PORT
   LAYER M6 ;
   RECT 43.008000 214.960000 43.200000 214.992000 ;
  END
 END po2[177]
 PIN po2[178]
  DIRECTION INPUT ;
  USE SIGNAL ;
  PORT
   LAYER M4 ;
   RECT 43.008000 215.148000 43.200000 215.172000 ;
  END
 END po2[178]
 PIN po2[179]
  DIRECTION INPUT ;
  USE SIGNAL ;
  PORT
   LAYER M6 ;
   RECT 43.008000 215.280000 43.200000 215.312000 ;
  END
 END po2[179]
 PIN po2[180]
  DIRECTION INPUT ;
  USE SIGNAL ;
  PORT
   LAYER M4 ;
   RECT 43.008000 215.484000 43.200000 215.508000 ;
  END
 END po2[180]
 PIN po2[181]
  DIRECTION INPUT ;
  USE SIGNAL ;
  PORT
   LAYER M6 ;
   RECT 43.008000 215.664000 43.200000 215.696000 ;
  END
 END po2[181]
 PIN po2[182]
  DIRECTION INPUT ;
  USE SIGNAL ;
  PORT
   LAYER M4 ;
   RECT 43.008000 215.772000 43.200000 215.796000 ;
  END
 END po2[182]
 PIN po2[183]
  DIRECTION INPUT ;
  USE SIGNAL ;
  PORT
   LAYER M6 ;
   RECT 43.008000 215.984000 43.200000 216.016000 ;
  END
 END po2[183]
 PIN po2[184]
  DIRECTION INPUT ;
  USE SIGNAL ;
  PORT
   LAYER M4 ;
   RECT 43.008000 216.108000 43.200000 216.132000 ;
  END
 END po2[184]
 PIN po2[185]
  DIRECTION INPUT ;
  USE SIGNAL ;
  PORT
   LAYER M6 ;
   RECT 43.008000 216.304000 43.200000 216.336000 ;
  END
 END po2[185]
 PIN po2[186]
  DIRECTION INPUT ;
  USE SIGNAL ;
  PORT
   LAYER M4 ;
   RECT 43.008000 216.444000 43.200000 216.468000 ;
  END
 END po2[186]
 PIN po2[187]
  DIRECTION INPUT ;
  USE SIGNAL ;
  PORT
   LAYER M6 ;
   RECT 43.008000 216.624000 43.200000 216.656000 ;
  END
 END po2[187]
 PIN po2[188]
  DIRECTION INPUT ;
  USE SIGNAL ;
  PORT
   LAYER M4 ;
   RECT 43.008000 216.780000 43.200000 216.804000 ;
  END
 END po2[188]
 PIN po2[189]
  DIRECTION INPUT ;
  USE SIGNAL ;
  PORT
   LAYER M6 ;
   RECT 43.008000 217.008000 43.200000 217.040000 ;
  END
 END po2[189]
 PIN po2[190]
  DIRECTION INPUT ;
  USE SIGNAL ;
  PORT
   LAYER M4 ;
   RECT 43.008000 217.116000 43.200000 217.140000 ;
  END
 END po2[190]
 PIN po2[191]
  DIRECTION INPUT ;
  USE SIGNAL ;
  PORT
   LAYER M6 ;
   RECT 43.008000 217.328000 43.200000 217.360000 ;
  END
 END po2[191]
 PIN po2[192]
  DIRECTION INPUT ;
  USE SIGNAL ;
  PORT
   LAYER M4 ;
   RECT 43.008000 217.452000 43.200000 217.476000 ;
  END
 END po2[192]
 PIN po2[193]
  DIRECTION INPUT ;
  USE SIGNAL ;
  PORT
   LAYER M6 ;
   RECT 43.008000 217.520000 43.200000 217.552000 ;
  END
 END po2[193]
 PIN po2[194]
  DIRECTION INPUT ;
  USE SIGNAL ;
  PORT
   LAYER M4 ;
   RECT 43.008000 217.788000 43.200000 217.812000 ;
  END
 END po2[194]
 PIN po2[195]
  DIRECTION INPUT ;
  USE SIGNAL ;
  PORT
   LAYER M6 ;
   RECT 43.008000 217.584000 43.200000 217.616000 ;
  END
 END po2[195]
 PIN po2[196]
  DIRECTION INPUT ;
  USE SIGNAL ;
  PORT
   LAYER M4 ;
   RECT 43.008000 218.124000 43.200000 218.148000 ;
  END
 END po2[196]
 PIN po2[197]
  DIRECTION INPUT ;
  USE SIGNAL ;
  PORT
   LAYER M6 ;
   RECT 43.008000 217.648000 43.200000 217.680000 ;
  END
 END po2[197]
 PIN po2[198]
  DIRECTION INPUT ;
  USE SIGNAL ;
  PORT
   LAYER M4 ;
   RECT 43.008000 218.460000 43.200000 218.484000 ;
  END
 END po2[198]
 PIN po2[199]
  DIRECTION INPUT ;
  USE SIGNAL ;
  PORT
   LAYER M6 ;
   RECT 43.008000 218.672000 43.200000 218.704000 ;
  END
 END po2[199]
 PIN po2[200]
  DIRECTION INPUT ;
  USE SIGNAL ;
  PORT
   LAYER M4 ;
   RECT 43.008000 218.796000 43.200000 218.820000 ;
  END
 END po2[200]
 PIN po2[201]
  DIRECTION INPUT ;
  USE SIGNAL ;
  PORT
   LAYER M6 ;
   RECT 43.008000 218.992000 43.200000 219.024000 ;
  END
 END po2[201]
 PIN po2[202]
  DIRECTION INPUT ;
  USE SIGNAL ;
  PORT
   LAYER M4 ;
   RECT 43.008000 219.132000 43.200000 219.156000 ;
  END
 END po2[202]
 PIN po2[203]
  DIRECTION INPUT ;
  USE SIGNAL ;
  PORT
   LAYER M6 ;
   RECT 43.008000 219.312000 43.200000 219.344000 ;
  END
 END po2[203]
 PIN po2[204]
  DIRECTION INPUT ;
  USE SIGNAL ;
  PORT
   LAYER M4 ;
   RECT 43.008000 219.468000 43.200000 219.492000 ;
  END
 END po2[204]
 PIN po2[205]
  DIRECTION INPUT ;
  USE SIGNAL ;
  PORT
   LAYER M6 ;
   RECT 43.008000 219.632000 43.200000 219.664000 ;
  END
 END po2[205]
 PIN po2[206]
  DIRECTION INPUT ;
  USE SIGNAL ;
  PORT
   LAYER M4 ;
   RECT 43.008000 219.804000 43.200000 219.828000 ;
  END
 END po2[206]
 PIN po2[207]
  DIRECTION INPUT ;
  USE SIGNAL ;
  PORT
   LAYER M6 ;
   RECT 43.008000 220.016000 43.200000 220.048000 ;
  END
 END po2[207]
 PIN po2[208]
  DIRECTION INPUT ;
  USE SIGNAL ;
  PORT
   LAYER M4 ;
   RECT 43.008000 220.092000 43.200000 220.116000 ;
  END
 END po2[208]
 PIN po2[209]
  DIRECTION INPUT ;
  USE SIGNAL ;
  PORT
   LAYER M6 ;
   RECT 43.008000 220.336000 43.200000 220.368000 ;
  END
 END po2[209]
 PIN po2[210]
  DIRECTION INPUT ;
  USE SIGNAL ;
  PORT
   LAYER M4 ;
   RECT 43.008000 220.428000 43.200000 220.452000 ;
  END
 END po2[210]
 PIN po2[211]
  DIRECTION INPUT ;
  USE SIGNAL ;
  PORT
   LAYER M6 ;
   RECT 43.008000 220.656000 43.200000 220.688000 ;
  END
 END po2[211]
 PIN po2[212]
  DIRECTION INPUT ;
  USE SIGNAL ;
  PORT
   LAYER M4 ;
   RECT 43.008000 220.764000 43.200000 220.788000 ;
  END
 END po2[212]
 PIN po2[213]
  DIRECTION INPUT ;
  USE SIGNAL ;
  PORT
   LAYER M6 ;
   RECT 43.008000 220.976000 43.200000 221.008000 ;
  END
 END po2[213]
 PIN po2[214]
  DIRECTION INPUT ;
  USE SIGNAL ;
  PORT
   LAYER M4 ;
   RECT 43.008000 221.100000 43.200000 221.124000 ;
  END
 END po2[214]
 PIN po2[215]
  DIRECTION INPUT ;
  USE SIGNAL ;
  PORT
   LAYER M6 ;
   RECT 43.008000 221.296000 43.200000 221.328000 ;
  END
 END po2[215]
 PIN po2[216]
  DIRECTION INPUT ;
  USE SIGNAL ;
  PORT
   LAYER M4 ;
   RECT 43.008000 221.436000 43.200000 221.460000 ;
  END
 END po2[216]
 PIN po2[217]
  DIRECTION INPUT ;
  USE SIGNAL ;
  PORT
   LAYER M6 ;
   RECT 43.008000 221.680000 43.200000 221.712000 ;
  END
 END po2[217]
 PIN po2[218]
  DIRECTION INPUT ;
  USE SIGNAL ;
  PORT
   LAYER M4 ;
   RECT 43.008000 221.772000 43.200000 221.796000 ;
  END
 END po2[218]
 PIN po2[219]
  DIRECTION INPUT ;
  USE SIGNAL ;
  PORT
   LAYER M6 ;
   RECT 43.008000 221.872000 43.200000 221.904000 ;
  END
 END po2[219]
 PIN po2[220]
  DIRECTION INPUT ;
  USE SIGNAL ;
  PORT
   LAYER M4 ;
   RECT 43.008000 222.108000 43.200000 222.132000 ;
  END
 END po2[220]
 PIN po2[221]
  DIRECTION INPUT ;
  USE SIGNAL ;
  PORT
   LAYER M6 ;
   RECT 43.008000 221.936000 43.200000 221.968000 ;
  END
 END po2[221]
 PIN po2[222]
  DIRECTION INPUT ;
  USE SIGNAL ;
  PORT
   LAYER M4 ;
   RECT 43.008000 222.444000 43.200000 222.468000 ;
  END
 END po2[222]
 PIN po2[223]
  DIRECTION INPUT ;
  USE SIGNAL ;
  PORT
   LAYER M6 ;
   RECT 43.008000 222.960000 43.200000 222.992000 ;
  END
 END po2[223]
 PIN po2[224]
  DIRECTION INPUT ;
  USE SIGNAL ;
  PORT
   LAYER M4 ;
   RECT 43.008000 222.780000 43.200000 222.804000 ;
  END
 END po2[224]
 PIN po2[225]
  DIRECTION INPUT ;
  USE SIGNAL ;
  PORT
   LAYER M6 ;
   RECT 43.008000 223.024000 43.200000 223.056000 ;
  END
 END po2[225]
 PIN po2[226]
  DIRECTION INPUT ;
  USE SIGNAL ;
  PORT
   LAYER M4 ;
   RECT 43.008000 223.116000 43.200000 223.140000 ;
  END
 END po2[226]
 PIN po2[227]
  DIRECTION INPUT ;
  USE SIGNAL ;
  PORT
   LAYER M6 ;
   RECT 43.008000 223.344000 43.200000 223.376000 ;
  END
 END po2[227]
 PIN po2[228]
  DIRECTION INPUT ;
  USE SIGNAL ;
  PORT
   LAYER M4 ;
   RECT 43.008000 223.452000 43.200000 223.476000 ;
  END
 END po2[228]
 PIN po2[229]
  DIRECTION INPUT ;
  USE SIGNAL ;
  PORT
   LAYER M6 ;
   RECT 43.008000 223.664000 43.200000 223.696000 ;
  END
 END po2[229]
 PIN po2[230]
  DIRECTION INPUT ;
  USE SIGNAL ;
  PORT
   LAYER M4 ;
   RECT 43.008000 223.788000 43.200000 223.812000 ;
  END
 END po2[230]
 PIN po2[231]
  DIRECTION INPUT ;
  USE SIGNAL ;
  PORT
   LAYER M6 ;
   RECT 43.008000 223.984000 43.200000 224.016000 ;
  END
 END po2[231]
 PIN po2[232]
  DIRECTION INPUT ;
  USE SIGNAL ;
  PORT
   LAYER M4 ;
   RECT 43.008000 224.124000 43.200000 224.148000 ;
  END
 END po2[232]
 PIN po2[233]
  DIRECTION INPUT ;
  USE SIGNAL ;
  PORT
   LAYER M6 ;
   RECT 43.008000 224.368000 43.200000 224.400000 ;
  END
 END po2[233]
 PIN po2[234]
  DIRECTION INPUT ;
  USE SIGNAL ;
  PORT
   LAYER M4 ;
   RECT 43.008000 224.460000 43.200000 224.484000 ;
  END
 END po2[234]
 PIN po2[235]
  DIRECTION INPUT ;
  USE SIGNAL ;
  PORT
   LAYER M6 ;
   RECT 43.008000 224.688000 43.200000 224.720000 ;
  END
 END po2[235]
 PIN po2[236]
  DIRECTION INPUT ;
  USE SIGNAL ;
  PORT
   LAYER M4 ;
   RECT 43.008000 224.748000 43.200000 224.772000 ;
  END
 END po2[236]
 PIN po2[237]
  DIRECTION INPUT ;
  USE SIGNAL ;
  PORT
   LAYER M6 ;
   RECT 43.008000 225.008000 43.200000 225.040000 ;
  END
 END po2[237]
 PIN po2[238]
  DIRECTION INPUT ;
  USE SIGNAL ;
  PORT
   LAYER M4 ;
   RECT 43.008000 225.084000 43.200000 225.108000 ;
  END
 END po2[238]
 PIN po2[239]
  DIRECTION INPUT ;
  USE SIGNAL ;
  PORT
   LAYER M6 ;
   RECT 43.008000 225.328000 43.200000 225.360000 ;
  END
 END po2[239]
 PIN po2[240]
  DIRECTION INPUT ;
  USE SIGNAL ;
  PORT
   LAYER M4 ;
   RECT 43.008000 225.420000 43.200000 225.444000 ;
  END
 END po2[240]
 PIN po2[241]
  DIRECTION INPUT ;
  USE SIGNAL ;
  PORT
   LAYER M6 ;
   RECT 43.008000 225.648000 43.200000 225.680000 ;
  END
 END po2[241]
 PIN po2[242]
  DIRECTION INPUT ;
  USE SIGNAL ;
  PORT
   LAYER M4 ;
   RECT 43.008000 225.756000 43.200000 225.780000 ;
  END
 END po2[242]
 PIN po2[243]
  DIRECTION INPUT ;
  USE SIGNAL ;
  PORT
   LAYER M6 ;
   RECT 43.008000 226.032000 43.200000 226.064000 ;
  END
 END po2[243]
 PIN po2[244]
  DIRECTION INPUT ;
  USE SIGNAL ;
  PORT
   LAYER M4 ;
   RECT 43.008000 226.092000 43.200000 226.116000 ;
  END
 END po2[244]
 PIN po2[245]
  DIRECTION INPUT ;
  USE SIGNAL ;
  PORT
   LAYER M6 ;
   RECT 43.008000 226.224000 43.200000 226.256000 ;
  END
 END po2[245]
 PIN po2[246]
  DIRECTION INPUT ;
  USE SIGNAL ;
  PORT
   LAYER M4 ;
   RECT 43.008000 226.428000 43.200000 226.452000 ;
  END
 END po2[246]
 PIN po2[247]
  DIRECTION INPUT ;
  USE SIGNAL ;
  PORT
   LAYER M6 ;
   RECT 43.008000 226.288000 43.200000 226.320000 ;
  END
 END po2[247]
 PIN po2[248]
  DIRECTION INPUT ;
  USE SIGNAL ;
  PORT
   LAYER M4 ;
   RECT 43.008000 226.764000 43.200000 226.788000 ;
  END
 END po2[248]
 PIN po2[249]
  DIRECTION INPUT ;
  USE SIGNAL ;
  PORT
   LAYER M6 ;
   RECT 43.008000 227.312000 43.200000 227.344000 ;
  END
 END po2[249]
 PIN po2[250]
  DIRECTION INPUT ;
  USE SIGNAL ;
  PORT
   LAYER M4 ;
   RECT 43.008000 227.100000 43.200000 227.124000 ;
  END
 END po2[250]
 PIN po2[251]
  DIRECTION INPUT ;
  USE SIGNAL ;
  PORT
   LAYER M6 ;
   RECT 43.008000 227.376000 43.200000 227.408000 ;
  END
 END po2[251]
 PIN po2[252]
  DIRECTION INPUT ;
  USE SIGNAL ;
  PORT
   LAYER M4 ;
   RECT 43.008000 227.436000 43.200000 227.460000 ;
  END
 END po2[252]
 PIN po2[253]
  DIRECTION INPUT ;
  USE SIGNAL ;
  PORT
   LAYER M6 ;
   RECT 43.008000 227.696000 43.200000 227.728000 ;
  END
 END po2[253]
 PIN po2[254]
  DIRECTION INPUT ;
  USE SIGNAL ;
  PORT
   LAYER M4 ;
   RECT 43.008000 227.772000 43.200000 227.796000 ;
  END
 END po2[254]
 PIN po2[255]
  DIRECTION INPUT ;
  USE SIGNAL ;
  PORT
   LAYER M6 ;
   RECT 43.008000 228.016000 43.200000 228.048000 ;
  END
 END po2[255]
 PIN po2[256]
  DIRECTION INPUT ;
  USE SIGNAL ;
  PORT
   LAYER M4 ;
   RECT 43.008000 228.108000 43.200000 228.132000 ;
  END
 END po2[256]
 PIN po2[257]
  DIRECTION INPUT ;
  USE SIGNAL ;
  PORT
   LAYER M6 ;
   RECT 43.008000 228.336000 43.200000 228.368000 ;
  END
 END po2[257]
 PIN po2[258]
  DIRECTION INPUT ;
  USE SIGNAL ;
  PORT
   LAYER M4 ;
   RECT 43.008000 228.444000 43.200000 228.468000 ;
  END
 END po2[258]
 PIN po2[259]
  DIRECTION INPUT ;
  USE SIGNAL ;
  PORT
   LAYER M6 ;
   RECT 43.008000 228.656000 43.200000 228.688000 ;
  END
 END po2[259]
 PIN po2[260]
  DIRECTION INPUT ;
  USE SIGNAL ;
  PORT
   LAYER M4 ;
   RECT 43.008000 228.780000 43.200000 228.804000 ;
  END
 END po2[260]
 PIN po2[261]
  DIRECTION INPUT ;
  USE SIGNAL ;
  PORT
   LAYER M6 ;
   RECT 43.008000 229.040000 43.200000 229.072000 ;
  END
 END po2[261]
 PIN po2[262]
  DIRECTION INPUT ;
  USE SIGNAL ;
  PORT
   LAYER M4 ;
   RECT 43.008000 229.068000 43.200000 229.092000 ;
  END
 END po2[262]
 PIN po2[263]
  DIRECTION INPUT ;
  USE SIGNAL ;
  PORT
   LAYER M6 ;
   RECT 43.008000 229.360000 43.200000 229.392000 ;
  END
 END po2[263]
 PIN po2[264]
  DIRECTION INPUT ;
  USE SIGNAL ;
  PORT
   LAYER M4 ;
   RECT 43.008000 229.404000 43.200000 229.428000 ;
  END
 END po2[264]
 PIN po2[265]
  DIRECTION INPUT ;
  USE SIGNAL ;
  PORT
   LAYER M6 ;
   RECT 43.008000 229.680000 43.200000 229.712000 ;
  END
 END po2[265]
 PIN po2[266]
  DIRECTION INPUT ;
  USE SIGNAL ;
  PORT
   LAYER M4 ;
   RECT 43.008000 229.740000 43.200000 229.764000 ;
  END
 END po2[266]
 PIN po2[267]
  DIRECTION INPUT ;
  USE SIGNAL ;
  PORT
   LAYER M6 ;
   RECT 43.008000 230.000000 43.200000 230.032000 ;
  END
 END po2[267]
 PIN po2[268]
  DIRECTION INPUT ;
  USE SIGNAL ;
  PORT
   LAYER M4 ;
   RECT 43.008000 230.076000 43.200000 230.100000 ;
  END
 END po2[268]
 PIN po2[269]
  DIRECTION INPUT ;
  USE SIGNAL ;
  PORT
   LAYER M6 ;
   RECT 43.008000 230.384000 43.200000 230.416000 ;
  END
 END po2[269]
 PIN po2[270]
  DIRECTION INPUT ;
  USE SIGNAL ;
  PORT
   LAYER M4 ;
   RECT 43.008000 230.412000 43.200000 230.436000 ;
  END
 END po2[270]
 PIN po2[271]
  DIRECTION INPUT ;
  USE SIGNAL ;
  PORT
   LAYER M6 ;
   RECT 43.008000 230.512000 43.200000 230.544000 ;
  END
 END po2[271]
 PIN po2[272]
  DIRECTION INPUT ;
  USE SIGNAL ;
  PORT
   LAYER M4 ;
   RECT 43.008000 230.748000 43.200000 230.772000 ;
  END
 END po2[272]
 PIN po2[273]
  DIRECTION INPUT ;
  USE SIGNAL ;
  PORT
   LAYER M6 ;
   RECT 43.008000 230.576000 43.200000 230.608000 ;
  END
 END po2[273]
 PIN po2[274]
  DIRECTION INPUT ;
  USE SIGNAL ;
  PORT
   LAYER M4 ;
   RECT 43.008000 231.084000 43.200000 231.108000 ;
  END
 END po2[274]
 PIN po2[275]
  DIRECTION INPUT ;
  USE SIGNAL ;
  PORT
   LAYER M6 ;
   RECT 43.008000 231.600000 43.200000 231.632000 ;
  END
 END po2[275]
 PIN po2[276]
  DIRECTION INPUT ;
  USE SIGNAL ;
  PORT
   LAYER M4 ;
   RECT 43.008000 231.420000 43.200000 231.444000 ;
  END
 END po2[276]
 PIN po2[277]
  DIRECTION INPUT ;
  USE SIGNAL ;
  PORT
   LAYER M6 ;
   RECT 43.008000 231.664000 43.200000 231.696000 ;
  END
 END po2[277]
 PIN po2[278]
  DIRECTION INPUT ;
  USE SIGNAL ;
  PORT
   LAYER M4 ;
   RECT 43.008000 231.756000 43.200000 231.780000 ;
  END
 END po2[278]
 PIN po2[279]
  DIRECTION INPUT ;
  USE SIGNAL ;
  PORT
   LAYER M6 ;
   RECT 43.008000 232.048000 43.200000 232.080000 ;
  END
 END po2[279]
 PIN po2[280]
  DIRECTION INPUT ;
  USE SIGNAL ;
  PORT
   LAYER M4 ;
   RECT 43.008000 232.092000 43.200000 232.116000 ;
  END
 END po2[280]
 PIN po2[281]
  DIRECTION INPUT ;
  USE SIGNAL ;
  PORT
   LAYER M6 ;
   RECT 43.008000 232.368000 43.200000 232.400000 ;
  END
 END po2[281]
 PIN po2[282]
  DIRECTION INPUT ;
  USE SIGNAL ;
  PORT
   LAYER M4 ;
   RECT 43.008000 232.428000 43.200000 232.452000 ;
  END
 END po2[282]
 PIN po2[283]
  DIRECTION INPUT ;
  USE SIGNAL ;
  PORT
   LAYER M6 ;
   RECT 43.008000 232.688000 43.200000 232.720000 ;
  END
 END po2[283]
 PIN po2[284]
  DIRECTION INPUT ;
  USE SIGNAL ;
  PORT
   LAYER M4 ;
   RECT 43.008000 232.764000 43.200000 232.788000 ;
  END
 END po2[284]
 PIN po2[285]
  DIRECTION INPUT ;
  USE SIGNAL ;
  PORT
   LAYER M6 ;
   RECT 43.008000 233.008000 43.200000 233.040000 ;
  END
 END po2[285]
 PIN po2[286]
  DIRECTION INPUT ;
  USE SIGNAL ;
  PORT
   LAYER M4 ;
   RECT 43.008000 233.100000 43.200000 233.124000 ;
  END
 END po2[286]
 PIN po2[287]
  DIRECTION INPUT ;
  USE SIGNAL ;
  PORT
   LAYER M6 ;
   RECT 43.008000 233.392000 43.200000 233.424000 ;
  END
 END po2[287]
 PIN po2[288]
  DIRECTION INPUT ;
  USE SIGNAL ;
  PORT
   LAYER M4 ;
   RECT 43.008000 233.388000 43.200000 233.412000 ;
  END
 END po2[288]
 PIN po2[289]
  DIRECTION INPUT ;
  USE SIGNAL ;
  PORT
   LAYER M6 ;
   RECT 43.008000 233.712000 43.200000 233.744000 ;
  END
 END po2[289]
 PIN po2[290]
  DIRECTION INPUT ;
  USE SIGNAL ;
  PORT
   LAYER M4 ;
   RECT 43.008000 233.724000 43.200000 233.748000 ;
  END
 END po2[290]
 PIN po2[291]
  DIRECTION INPUT ;
  USE SIGNAL ;
  PORT
   LAYER M6 ;
   RECT 43.008000 234.032000 43.200000 234.064000 ;
  END
 END po2[291]
 PIN po2[292]
  DIRECTION INPUT ;
  USE SIGNAL ;
  PORT
   LAYER M4 ;
   RECT 43.008000 234.060000 43.200000 234.084000 ;
  END
 END po2[292]
 PIN po2[293]
  DIRECTION INPUT ;
  USE SIGNAL ;
  PORT
   LAYER M6 ;
   RECT 43.008000 234.352000 43.200000 234.384000 ;
  END
 END po2[293]
 PIN po2[294]
  DIRECTION INPUT ;
  USE SIGNAL ;
  PORT
   LAYER M4 ;
   RECT 43.008000 234.396000 43.200000 234.420000 ;
  END
 END po2[294]
 PIN po2[295]
  DIRECTION INPUT ;
  USE SIGNAL ;
  PORT
   LAYER M6 ;
   RECT 43.008000 234.736000 43.200000 234.768000 ;
  END
 END po2[295]
 PIN po2[296]
  DIRECTION INPUT ;
  USE SIGNAL ;
  PORT
   LAYER M4 ;
   RECT 43.008000 234.732000 43.200000 234.756000 ;
  END
 END po2[296]
 PIN po2[297]
  DIRECTION INPUT ;
  USE SIGNAL ;
  PORT
   LAYER M6 ;
   RECT 43.008000 234.864000 43.200000 234.896000 ;
  END
 END po2[297]
 PIN po2[298]
  DIRECTION INPUT ;
  USE SIGNAL ;
  PORT
   LAYER M4 ;
   RECT 43.008000 235.068000 43.200000 235.092000 ;
  END
 END po2[298]
 PIN po2[299]
  DIRECTION INPUT ;
  USE SIGNAL ;
  PORT
   LAYER M6 ;
   RECT 43.008000 234.928000 43.200000 234.960000 ;
  END
 END po2[299]
 PIN po2[300]
  DIRECTION INPUT ;
  USE SIGNAL ;
  PORT
   LAYER M4 ;
   RECT 43.008000 235.404000 43.200000 235.428000 ;
  END
 END po2[300]
 PIN po2[301]
  DIRECTION INPUT ;
  USE SIGNAL ;
  PORT
   LAYER M6 ;
   RECT 43.008000 235.952000 43.200000 235.984000 ;
  END
 END po2[301]
 PIN po2[302]
  DIRECTION INPUT ;
  USE SIGNAL ;
  PORT
   LAYER M4 ;
   RECT 43.008000 235.740000 43.200000 235.764000 ;
  END
 END po2[302]
 PIN po2[303]
  DIRECTION INPUT ;
  USE SIGNAL ;
  PORT
   LAYER M6 ;
   RECT 43.008000 236.016000 43.200000 236.048000 ;
  END
 END po2[303]
 PIN po2[304]
  DIRECTION INPUT ;
  USE SIGNAL ;
  PORT
   LAYER M4 ;
   RECT 43.008000 236.076000 43.200000 236.100000 ;
  END
 END po2[304]
 PIN po2[305]
  DIRECTION INPUT ;
  USE SIGNAL ;
  PORT
   LAYER M6 ;
   RECT 43.008000 236.400000 43.200000 236.432000 ;
  END
 END po2[305]
 PIN po2[306]
  DIRECTION INPUT ;
  USE SIGNAL ;
  PORT
   LAYER M4 ;
   RECT 43.008000 236.412000 43.200000 236.436000 ;
  END
 END po2[306]
 PIN po2[307]
  DIRECTION INPUT ;
  USE SIGNAL ;
  PORT
   LAYER M6 ;
   RECT 43.008000 236.720000 43.200000 236.752000 ;
  END
 END po2[307]
 PIN po2[308]
  DIRECTION INPUT ;
  USE SIGNAL ;
  PORT
   LAYER M4 ;
   RECT 43.008000 236.748000 43.200000 236.772000 ;
  END
 END po2[308]
 PIN po2[309]
  DIRECTION INPUT ;
  USE SIGNAL ;
  PORT
   LAYER M6 ;
   RECT 43.008000 237.040000 43.200000 237.072000 ;
  END
 END po2[309]
 PIN po2[310]
  DIRECTION INPUT ;
  USE SIGNAL ;
  PORT
   LAYER M4 ;
   RECT 43.008000 237.084000 43.200000 237.108000 ;
  END
 END po2[310]
 PIN po2[311]
  DIRECTION INPUT ;
  USE SIGNAL ;
  PORT
   LAYER M6 ;
   RECT 43.008000 237.360000 43.200000 237.392000 ;
  END
 END po2[311]
 PIN po2[312]
  DIRECTION INPUT ;
  USE SIGNAL ;
  PORT
   LAYER M4 ;
   RECT 43.008000 237.420000 43.200000 237.444000 ;
  END
 END po2[312]
 PIN po2[313]
  DIRECTION INPUT ;
  USE SIGNAL ;
  PORT
   LAYER M6 ;
   RECT 43.008000 237.744000 43.200000 237.776000 ;
  END
 END po2[313]
 PIN po2[314]
  DIRECTION INPUT ;
  USE SIGNAL ;
  PORT
   LAYER M4 ;
   RECT 43.008000 237.756000 43.200000 237.780000 ;
  END
 END po2[314]
 PIN po2[315]
  DIRECTION INPUT ;
  USE SIGNAL ;
  PORT
   LAYER M6 ;
   RECT 43.008000 238.064000 43.200000 238.096000 ;
  END
 END po2[315]
 PIN po2[316]
  DIRECTION INPUT ;
  USE SIGNAL ;
  PORT
   LAYER M4 ;
   RECT 43.008000 238.044000 43.200000 238.068000 ;
  END
 END po2[316]
 PIN po2[317]
  DIRECTION INPUT ;
  USE SIGNAL ;
  PORT
   LAYER M6 ;
   RECT 43.008000 238.384000 43.200000 238.416000 ;
  END
 END po2[317]
 PIN po2[318]
  DIRECTION INPUT ;
  USE SIGNAL ;
  PORT
   LAYER M4 ;
   RECT 43.008000 238.380000 43.200000 238.404000 ;
  END
 END po2[318]
 PIN po2[319]
  DIRECTION INPUT ;
  USE SIGNAL ;
  PORT
   LAYER M6 ;
   RECT 43.008000 238.704000 43.200000 238.736000 ;
  END
 END po2[319]
 PIN po2[320]
  DIRECTION INPUT ;
  USE SIGNAL ;
  PORT
   LAYER M4 ;
   RECT 43.008000 238.716000 43.200000 238.740000 ;
  END
 END po2[320]
 PIN po2[321]
  DIRECTION INPUT ;
  USE SIGNAL ;
  PORT
   LAYER M6 ;
   RECT 43.008000 239.024000 43.200000 239.056000 ;
  END
 END po2[321]
 PIN po2[322]
  DIRECTION INPUT ;
  USE SIGNAL ;
  PORT
   LAYER M4 ;
   RECT 43.008000 239.052000 43.200000 239.076000 ;
  END
 END po2[322]
 PIN po2[323]
  DIRECTION INPUT ;
  USE SIGNAL ;
  PORT
   LAYER M6 ;
   RECT 43.008000 239.088000 43.200000 239.120000 ;
  END
 END po2[323]
 PIN po2[324]
  DIRECTION INPUT ;
  USE SIGNAL ;
  PORT
   LAYER M4 ;
   RECT 43.008000 239.388000 43.200000 239.412000 ;
  END
 END po2[324]
 PIN po2[325]
  DIRECTION INPUT ;
  USE SIGNAL ;
  PORT
   LAYER M6 ;
   RECT 43.008000 239.152000 43.200000 239.184000 ;
  END
 END po2[325]
 PIN po2[326]
  DIRECTION INPUT ;
  USE SIGNAL ;
  PORT
   LAYER M4 ;
   RECT 43.008000 239.724000 43.200000 239.748000 ;
  END
 END po2[326]
 PIN po2[327]
  DIRECTION INPUT ;
  USE SIGNAL ;
  PORT
   LAYER M6 ;
   RECT 43.008000 239.216000 43.200000 239.248000 ;
  END
 END po2[327]
 PIN pi2[0]
  DIRECTION OUTPUT ;
  USE SIGNAL ;
  PORT
   LAYER M4 ;
   RECT 43.008000 518.796000 43.200000 518.820000 ;
  END
 END pi2[0]
 PIN pi2[1]
  DIRECTION OUTPUT ;
  USE SIGNAL ;
  PORT
   LAYER M6 ;
   RECT 43.008000 518.512000 43.200000 518.544000 ;
  END
 END pi2[1]
 PIN pi2[2]
  DIRECTION OUTPUT ;
  USE SIGNAL ;
  PORT
   LAYER M4 ;
   RECT 43.008000 519.132000 43.200000 519.156000 ;
  END
 END pi2[2]
 PIN pi2[3]
  DIRECTION OUTPUT ;
  USE SIGNAL ;
  PORT
   LAYER M6 ;
   RECT 43.008000 518.768000 43.200000 518.800000 ;
  END
 END pi2[3]
 PIN pi2[4]
  DIRECTION OUTPUT ;
  USE SIGNAL ;
  PORT
   LAYER M4 ;
   RECT 43.008000 519.468000 43.200000 519.492000 ;
  END
 END pi2[4]
 PIN pi2[5]
  DIRECTION OUTPUT ;
  USE SIGNAL ;
  PORT
   LAYER M6 ;
   RECT 43.008000 519.024000 43.200000 519.056000 ;
  END
 END pi2[5]
 PIN pi2[6]
  DIRECTION OUTPUT ;
  USE SIGNAL ;
  PORT
   LAYER M4 ;
   RECT 43.008000 519.804000 43.200000 519.828000 ;
  END
 END pi2[6]
 PIN pi2[7]
  DIRECTION OUTPUT ;
  USE SIGNAL ;
  PORT
   LAYER M6 ;
   RECT 43.008000 519.280000 43.200000 519.312000 ;
  END
 END pi2[7]
 PIN pi2[8]
  DIRECTION OUTPUT ;
  USE SIGNAL ;
  PORT
   LAYER M4 ;
   RECT 43.008000 520.140000 43.200000 520.164000 ;
  END
 END pi2[8]
 PIN pi2[9]
  DIRECTION OUTPUT ;
  USE SIGNAL ;
  PORT
   LAYER M6 ;
   RECT 43.008000 519.536000 43.200000 519.568000 ;
  END
 END pi2[9]
 PIN pi2[10]
  DIRECTION OUTPUT ;
  USE SIGNAL ;
  PORT
   LAYER M4 ;
   RECT 43.008000 520.476000 43.200000 520.500000 ;
  END
 END pi2[10]
 PIN pi2[11]
  DIRECTION OUTPUT ;
  USE SIGNAL ;
  PORT
   LAYER M6 ;
   RECT 43.008000 519.792000 43.200000 519.824000 ;
  END
 END pi2[11]
 PIN pi2[12]
  DIRECTION OUTPUT ;
  USE SIGNAL ;
  PORT
   LAYER M4 ;
   RECT 43.008000 520.812000 43.200000 520.836000 ;
  END
 END pi2[12]
 PIN pi2[13]
  DIRECTION OUTPUT ;
  USE SIGNAL ;
  PORT
   LAYER M6 ;
   RECT 43.008000 520.048000 43.200000 520.080000 ;
  END
 END pi2[13]
 PIN pi2[14]
  DIRECTION OUTPUT ;
  USE SIGNAL ;
  PORT
   LAYER M4 ;
   RECT 43.008000 521.148000 43.200000 521.172000 ;
  END
 END pi2[14]
 PIN pi2[15]
  DIRECTION OUTPUT ;
  USE SIGNAL ;
  PORT
   LAYER M6 ;
   RECT 43.008000 521.264000 43.200000 521.296000 ;
  END
 END pi2[15]
 PIN pi2[16]
  DIRECTION OUTPUT ;
  USE SIGNAL ;
  PORT
   LAYER M4 ;
   RECT 43.008000 521.484000 43.200000 521.508000 ;
  END
 END pi2[16]
 PIN pi2[17]
  DIRECTION OUTPUT ;
  USE SIGNAL ;
  PORT
   LAYER M6 ;
   RECT 43.008000 521.520000 43.200000 521.552000 ;
  END
 END pi2[17]
 PIN pi2[18]
  DIRECTION OUTPUT ;
  USE SIGNAL ;
  PORT
   LAYER M4 ;
   RECT 43.008000 521.820000 43.200000 521.844000 ;
  END
 END pi2[18]
 PIN pi2[19]
  DIRECTION OUTPUT ;
  USE SIGNAL ;
  PORT
   LAYER M6 ;
   RECT 43.008000 521.840000 43.200000 521.872000 ;
  END
 END pi2[19]
 PIN pi2[20]
  DIRECTION OUTPUT ;
  USE SIGNAL ;
  PORT
   LAYER M4 ;
   RECT 43.008000 522.156000 43.200000 522.180000 ;
  END
 END pi2[20]
 PIN pi2[21]
  DIRECTION OUTPUT ;
  USE SIGNAL ;
  PORT
   LAYER M6 ;
   RECT 43.008000 522.096000 43.200000 522.128000 ;
  END
 END pi2[21]
 PIN pi2[22]
  DIRECTION OUTPUT ;
  USE SIGNAL ;
  PORT
   LAYER M4 ;
   RECT 43.008000 522.492000 43.200000 522.516000 ;
  END
 END pi2[22]
 PIN pi2[23]
  DIRECTION OUTPUT ;
  USE SIGNAL ;
  PORT
   LAYER M6 ;
   RECT 43.008000 522.352000 43.200000 522.384000 ;
  END
 END pi2[23]
 PIN pi2[24]
  DIRECTION OUTPUT ;
  USE SIGNAL ;
  PORT
   LAYER M4 ;
   RECT 43.008000 522.828000 43.200000 522.852000 ;
  END
 END pi2[24]
 PIN pi2[25]
  DIRECTION OUTPUT ;
  USE SIGNAL ;
  PORT
   LAYER M6 ;
   RECT 43.008000 522.608000 43.200000 522.640000 ;
  END
 END pi2[25]
 PIN pi2[26]
  DIRECTION OUTPUT ;
  USE SIGNAL ;
  PORT
   LAYER M4 ;
   RECT 43.008000 523.164000 43.200000 523.188000 ;
  END
 END pi2[26]
 PIN pi2[27]
  DIRECTION OUTPUT ;
  USE SIGNAL ;
  PORT
   LAYER M6 ;
   RECT 43.008000 522.864000 43.200000 522.896000 ;
  END
 END pi2[27]
 PIN pi2[28]
  DIRECTION OUTPUT ;
  USE SIGNAL ;
  PORT
   LAYER M4 ;
   RECT 43.008000 523.500000 43.200000 523.524000 ;
  END
 END pi2[28]
 PIN pi2[29]
  DIRECTION OUTPUT ;
  USE SIGNAL ;
  PORT
   LAYER M6 ;
   RECT 43.008000 523.120000 43.200000 523.152000 ;
  END
 END pi2[29]
 PIN pi2[30]
  DIRECTION OUTPUT ;
  USE SIGNAL ;
  PORT
   LAYER M4 ;
   RECT 43.008000 523.836000 43.200000 523.860000 ;
  END
 END pi2[30]
 PIN pi2[31]
  DIRECTION OUTPUT ;
  USE SIGNAL ;
  PORT
   LAYER M6 ;
   RECT 43.008000 523.376000 43.200000 523.408000 ;
  END
 END pi2[31]
 PIN pi2[32]
  DIRECTION OUTPUT ;
  USE SIGNAL ;
  PORT
   LAYER M4 ;
   RECT 43.008000 524.124000 43.200000 524.148000 ;
  END
 END pi2[32]
 PIN pi2[33]
  DIRECTION OUTPUT ;
  USE SIGNAL ;
  PORT
   LAYER M6 ;
   RECT 43.008000 523.632000 43.200000 523.664000 ;
  END
 END pi2[33]
 PIN pi2[34]
  DIRECTION OUTPUT ;
  USE SIGNAL ;
  PORT
   LAYER M4 ;
   RECT 43.008000 524.460000 43.200000 524.484000 ;
  END
 END pi2[34]
 PIN pi2[35]
  DIRECTION OUTPUT ;
  USE SIGNAL ;
  PORT
   LAYER M6 ;
   RECT 43.008000 523.888000 43.200000 523.920000 ;
  END
 END pi2[35]
 PIN pi2[36]
  DIRECTION OUTPUT ;
  USE SIGNAL ;
  PORT
   LAYER M4 ;
   RECT 43.008000 524.796000 43.200000 524.820000 ;
  END
 END pi2[36]
 PIN pi2[37]
  DIRECTION OUTPUT ;
  USE SIGNAL ;
  PORT
   LAYER M6 ;
   RECT 43.008000 524.144000 43.200000 524.176000 ;
  END
 END pi2[37]
 PIN pi2[38]
  DIRECTION OUTPUT ;
  USE SIGNAL ;
  PORT
   LAYER M4 ;
   RECT 43.008000 525.132000 43.200000 525.156000 ;
  END
 END pi2[38]
 PIN pi2[39]
  DIRECTION OUTPUT ;
  USE SIGNAL ;
  PORT
   LAYER M6 ;
   RECT 43.008000 525.424000 43.200000 525.456000 ;
  END
 END pi2[39]
 PIN pi2[40]
  DIRECTION OUTPUT ;
  USE SIGNAL ;
  PORT
   LAYER M4 ;
   RECT 43.008000 525.468000 43.200000 525.492000 ;
  END
 END pi2[40]
 PIN pi2[41]
  DIRECTION OUTPUT ;
  USE SIGNAL ;
  PORT
   LAYER M6 ;
   RECT 43.008000 525.680000 43.200000 525.712000 ;
  END
 END pi2[41]
 PIN pi2[42]
  DIRECTION OUTPUT ;
  USE SIGNAL ;
  PORT
   LAYER M4 ;
   RECT 43.008000 525.804000 43.200000 525.828000 ;
  END
 END pi2[42]
 PIN pi2[43]
  DIRECTION OUTPUT ;
  USE SIGNAL ;
  PORT
   LAYER M6 ;
   RECT 43.008000 525.936000 43.200000 525.968000 ;
  END
 END pi2[43]
 PIN pi2[44]
  DIRECTION OUTPUT ;
  USE SIGNAL ;
  PORT
   LAYER M4 ;
   RECT 43.008000 526.140000 43.200000 526.164000 ;
  END
 END pi2[44]
 PIN pi2[45]
  DIRECTION OUTPUT ;
  USE SIGNAL ;
  PORT
   LAYER M6 ;
   RECT 43.008000 526.192000 43.200000 526.224000 ;
  END
 END pi2[45]
 PIN pi2[46]
  DIRECTION OUTPUT ;
  USE SIGNAL ;
  PORT
   LAYER M4 ;
   RECT 43.008000 526.476000 43.200000 526.500000 ;
  END
 END pi2[46]
 PIN pi2[47]
  DIRECTION OUTPUT ;
  USE SIGNAL ;
  PORT
   LAYER M6 ;
   RECT 43.008000 526.448000 43.200000 526.480000 ;
  END
 END pi2[47]
 PIN pi2[48]
  DIRECTION OUTPUT ;
  USE SIGNAL ;
  PORT
   LAYER M4 ;
   RECT 43.008000 526.812000 43.200000 526.836000 ;
  END
 END pi2[48]
 PIN pi2[49]
  DIRECTION OUTPUT ;
  USE SIGNAL ;
  PORT
   LAYER M6 ;
   RECT 43.008000 526.704000 43.200000 526.736000 ;
  END
 END pi2[49]
 PIN pi2[50]
  DIRECTION OUTPUT ;
  USE SIGNAL ;
  PORT
   LAYER M4 ;
   RECT 43.008000 527.148000 43.200000 527.172000 ;
  END
 END pi2[50]
 PIN pi2[51]
  DIRECTION OUTPUT ;
  USE SIGNAL ;
  PORT
   LAYER M6 ;
   RECT 43.008000 526.960000 43.200000 526.992000 ;
  END
 END pi2[51]
 PIN pi2[52]
  DIRECTION OUTPUT ;
  USE SIGNAL ;
  PORT
   LAYER M4 ;
   RECT 43.008000 527.484000 43.200000 527.508000 ;
  END
 END pi2[52]
 PIN pi2[53]
  DIRECTION OUTPUT ;
  USE SIGNAL ;
  PORT
   LAYER M6 ;
   RECT 43.008000 527.216000 43.200000 527.248000 ;
  END
 END pi2[53]
 PIN pi2[54]
  DIRECTION OUTPUT ;
  USE SIGNAL ;
  PORT
   LAYER M4 ;
   RECT 43.008000 527.820000 43.200000 527.844000 ;
  END
 END pi2[54]
 PIN pi2[55]
  DIRECTION OUTPUT ;
  USE SIGNAL ;
  PORT
   LAYER M6 ;
   RECT 43.008000 527.472000 43.200000 527.504000 ;
  END
 END pi2[55]
 PIN pi2[56]
  DIRECTION OUTPUT ;
  USE SIGNAL ;
  PORT
   LAYER M4 ;
   RECT 43.008000 528.156000 43.200000 528.180000 ;
  END
 END pi2[56]
 PIN pi2[57]
  DIRECTION OUTPUT ;
  USE SIGNAL ;
  PORT
   LAYER M6 ;
   RECT 43.008000 527.728000 43.200000 527.760000 ;
  END
 END pi2[57]
 PIN pi2[58]
  DIRECTION OUTPUT ;
  USE SIGNAL ;
  PORT
   LAYER M4 ;
   RECT 43.008000 528.492000 43.200000 528.516000 ;
  END
 END pi2[58]
 PIN pi2[59]
  DIRECTION OUTPUT ;
  USE SIGNAL ;
  PORT
   LAYER M6 ;
   RECT 43.008000 528.048000 43.200000 528.080000 ;
  END
 END pi2[59]
 PIN pi2[60]
  DIRECTION OUTPUT ;
  USE SIGNAL ;
  PORT
   LAYER M4 ;
   RECT 43.008000 528.828000 43.200000 528.852000 ;
  END
 END pi2[60]
 PIN pi2[61]
  DIRECTION OUTPUT ;
  USE SIGNAL ;
  PORT
   LAYER M6 ;
   RECT 43.008000 528.304000 43.200000 528.336000 ;
  END
 END pi2[61]
 PIN pi2[62]
  DIRECTION OUTPUT ;
  USE SIGNAL ;
  PORT
   LAYER M4 ;
   RECT 43.008000 529.164000 43.200000 529.188000 ;
  END
 END pi2[62]
 PIN pi2[63]
  DIRECTION OUTPUT ;
  USE SIGNAL ;
  PORT
   LAYER M6 ;
   RECT 43.008000 528.560000 43.200000 528.592000 ;
  END
 END pi2[63]
 PIN pi2[64]
  DIRECTION OUTPUT ;
  USE SIGNAL ;
  PORT
   LAYER M4 ;
   RECT 43.008000 529.500000 43.200000 529.524000 ;
  END
 END pi2[64]
 PIN pi2[65]
  DIRECTION OUTPUT ;
  USE SIGNAL ;
  PORT
   LAYER M6 ;
   RECT 43.008000 529.776000 43.200000 529.808000 ;
  END
 END pi2[65]
 PIN pi2[66]
  DIRECTION OUTPUT ;
  USE SIGNAL ;
  PORT
   LAYER M4 ;
   RECT 43.008000 529.836000 43.200000 529.860000 ;
  END
 END pi2[66]
 PIN pi2[67]
  DIRECTION OUTPUT ;
  USE SIGNAL ;
  PORT
   LAYER M6 ;
   RECT 43.008000 530.032000 43.200000 530.064000 ;
  END
 END pi2[67]
 PIN pi2[68]
  DIRECTION OUTPUT ;
  USE SIGNAL ;
  PORT
   LAYER M4 ;
   RECT 43.008000 530.172000 43.200000 530.196000 ;
  END
 END pi2[68]
 PIN pi2[69]
  DIRECTION OUTPUT ;
  USE SIGNAL ;
  PORT
   LAYER M6 ;
   RECT 43.008000 530.288000 43.200000 530.320000 ;
  END
 END pi2[69]
 PIN pi2[70]
  DIRECTION OUTPUT ;
  USE SIGNAL ;
  PORT
   LAYER M4 ;
   RECT 43.008000 530.460000 43.200000 530.484000 ;
  END
 END pi2[70]
 PIN pi2[71]
  DIRECTION OUTPUT ;
  USE SIGNAL ;
  PORT
   LAYER M6 ;
   RECT 43.008000 530.544000 43.200000 530.576000 ;
  END
 END pi2[71]
 PIN pi2[72]
  DIRECTION OUTPUT ;
  USE SIGNAL ;
  PORT
   LAYER M4 ;
   RECT 43.008000 530.796000 43.200000 530.820000 ;
  END
 END pi2[72]
 PIN pi2[73]
  DIRECTION OUTPUT ;
  USE SIGNAL ;
  PORT
   LAYER M6 ;
   RECT 43.008000 530.800000 43.200000 530.832000 ;
  END
 END pi2[73]
 PIN pi2[74]
  DIRECTION OUTPUT ;
  USE SIGNAL ;
  PORT
   LAYER M4 ;
   RECT 43.008000 531.132000 43.200000 531.156000 ;
  END
 END pi2[74]
 PIN pi2[75]
  DIRECTION OUTPUT ;
  USE SIGNAL ;
  PORT
   LAYER M6 ;
   RECT 43.008000 531.056000 43.200000 531.088000 ;
  END
 END pi2[75]
 PIN pi2[76]
  DIRECTION OUTPUT ;
  USE SIGNAL ;
  PORT
   LAYER M4 ;
   RECT 43.008000 531.468000 43.200000 531.492000 ;
  END
 END pi2[76]
 PIN pi2[77]
  DIRECTION OUTPUT ;
  USE SIGNAL ;
  PORT
   LAYER M6 ;
   RECT 43.008000 531.312000 43.200000 531.344000 ;
  END
 END pi2[77]
 PIN pi2[78]
  DIRECTION OUTPUT ;
  USE SIGNAL ;
  PORT
   LAYER M4 ;
   RECT 43.008000 531.804000 43.200000 531.828000 ;
  END
 END pi2[78]
 PIN pi2[79]
  DIRECTION OUTPUT ;
  USE SIGNAL ;
  PORT
   LAYER M6 ;
   RECT 43.008000 531.568000 43.200000 531.600000 ;
  END
 END pi2[79]
 PIN pi2[80]
  DIRECTION OUTPUT ;
  USE SIGNAL ;
  PORT
   LAYER M4 ;
   RECT 43.008000 532.140000 43.200000 532.164000 ;
  END
 END pi2[80]
 PIN pi2[81]
  DIRECTION OUTPUT ;
  USE SIGNAL ;
  PORT
   LAYER M6 ;
   RECT 43.008000 531.888000 43.200000 531.920000 ;
  END
 END pi2[81]
 PIN pi2[82]
  DIRECTION OUTPUT ;
  USE SIGNAL ;
  PORT
   LAYER M4 ;
   RECT 43.008000 532.476000 43.200000 532.500000 ;
  END
 END pi2[82]
 PIN pi2[83]
  DIRECTION OUTPUT ;
  USE SIGNAL ;
  PORT
   LAYER M6 ;
   RECT 43.008000 532.144000 43.200000 532.176000 ;
  END
 END pi2[83]
 PIN pi2[84]
  DIRECTION OUTPUT ;
  USE SIGNAL ;
  PORT
   LAYER M4 ;
   RECT 43.008000 532.812000 43.200000 532.836000 ;
  END
 END pi2[84]
 PIN pi2[85]
  DIRECTION OUTPUT ;
  USE SIGNAL ;
  PORT
   LAYER M6 ;
   RECT 43.008000 532.400000 43.200000 532.432000 ;
  END
 END pi2[85]
 PIN pi2[86]
  DIRECTION OUTPUT ;
  USE SIGNAL ;
  PORT
   LAYER M4 ;
   RECT 43.008000 533.148000 43.200000 533.172000 ;
  END
 END pi2[86]
 PIN pi2[87]
  DIRECTION OUTPUT ;
  USE SIGNAL ;
  PORT
   LAYER M6 ;
   RECT 43.008000 532.656000 43.200000 532.688000 ;
  END
 END pi2[87]
 PIN pi2[88]
  DIRECTION OUTPUT ;
  USE SIGNAL ;
  PORT
   LAYER M4 ;
   RECT 43.008000 533.484000 43.200000 533.508000 ;
  END
 END pi2[88]
 PIN pi2[89]
  DIRECTION OUTPUT ;
  USE SIGNAL ;
  PORT
   LAYER M6 ;
   RECT 43.008000 532.912000 43.200000 532.944000 ;
  END
 END pi2[89]
 PIN pi2[90]
  DIRECTION OUTPUT ;
  USE SIGNAL ;
  PORT
   LAYER M4 ;
   RECT 43.008000 533.820000 43.200000 533.844000 ;
  END
 END pi2[90]
 PIN pi2[91]
  DIRECTION OUTPUT ;
  USE SIGNAL ;
  PORT
   LAYER M6 ;
   RECT 43.008000 534.128000 43.200000 534.160000 ;
  END
 END pi2[91]
 PIN pi2[92]
  DIRECTION OUTPUT ;
  USE SIGNAL ;
  PORT
   LAYER M4 ;
   RECT 43.008000 534.156000 43.200000 534.180000 ;
  END
 END pi2[92]
 PIN pi2[93]
  DIRECTION OUTPUT ;
  USE SIGNAL ;
  PORT
   LAYER M6 ;
   RECT 43.008000 534.384000 43.200000 534.416000 ;
  END
 END pi2[93]
 PIN pi2[94]
  DIRECTION OUTPUT ;
  USE SIGNAL ;
  PORT
   LAYER M4 ;
   RECT 43.008000 534.492000 43.200000 534.516000 ;
  END
 END pi2[94]
 PIN pi2[95]
  DIRECTION OUTPUT ;
  USE SIGNAL ;
  PORT
   LAYER M6 ;
   RECT 43.008000 534.640000 43.200000 534.672000 ;
  END
 END pi2[95]
 PIN pi2[96]
  DIRECTION OUTPUT ;
  USE SIGNAL ;
  PORT
   LAYER M4 ;
   RECT 43.008000 534.828000 43.200000 534.852000 ;
  END
 END pi2[96]
 PIN pi2[97]
  DIRECTION OUTPUT ;
  USE SIGNAL ;
  PORT
   LAYER M6 ;
   RECT 43.008000 534.896000 43.200000 534.928000 ;
  END
 END pi2[97]
 PIN pi2[98]
  DIRECTION OUTPUT ;
  USE SIGNAL ;
  PORT
   LAYER M4 ;
   RECT 43.008000 535.164000 43.200000 535.188000 ;
  END
 END pi2[98]
 PIN pi2[99]
  DIRECTION OUTPUT ;
  USE SIGNAL ;
  PORT
   LAYER M6 ;
   RECT 43.008000 535.152000 43.200000 535.184000 ;
  END
 END pi2[99]
 PIN pi2[100]
  DIRECTION OUTPUT ;
  USE SIGNAL ;
  PORT
   LAYER M4 ;
   RECT 43.008000 535.500000 43.200000 535.524000 ;
  END
 END pi2[100]
 PIN pi2[101]
  DIRECTION OUTPUT ;
  USE SIGNAL ;
  PORT
   LAYER M6 ;
   RECT 43.008000 535.472000 43.200000 535.504000 ;
  END
 END pi2[101]
 PIN pi2[102]
  DIRECTION OUTPUT ;
  USE SIGNAL ;
  PORT
   LAYER M4 ;
   RECT 43.008000 535.836000 43.200000 535.860000 ;
  END
 END pi2[102]
 PIN pi2[103]
  DIRECTION OUTPUT ;
  USE SIGNAL ;
  PORT
   LAYER M6 ;
   RECT 43.008000 535.728000 43.200000 535.760000 ;
  END
 END pi2[103]
 PIN pi2[104]
  DIRECTION OUTPUT ;
  USE SIGNAL ;
  PORT
   LAYER M4 ;
   RECT 43.008000 536.172000 43.200000 536.196000 ;
  END
 END pi2[104]
 PIN pi2[105]
  DIRECTION OUTPUT ;
  USE SIGNAL ;
  PORT
   LAYER M6 ;
   RECT 43.008000 535.984000 43.200000 536.016000 ;
  END
 END pi2[105]
 PIN pi2[106]
  DIRECTION OUTPUT ;
  USE SIGNAL ;
  PORT
   LAYER M4 ;
   RECT 43.008000 536.508000 43.200000 536.532000 ;
  END
 END pi2[106]
 PIN pi2[107]
  DIRECTION OUTPUT ;
  USE SIGNAL ;
  PORT
   LAYER M6 ;
   RECT 43.008000 536.240000 43.200000 536.272000 ;
  END
 END pi2[107]
 PIN pi2[108]
  DIRECTION OUTPUT ;
  USE SIGNAL ;
  PORT
   LAYER M4 ;
   RECT 43.008000 536.796000 43.200000 536.820000 ;
  END
 END pi2[108]
 PIN pi2[109]
  DIRECTION OUTPUT ;
  USE SIGNAL ;
  PORT
   LAYER M6 ;
   RECT 43.008000 536.496000 43.200000 536.528000 ;
  END
 END pi2[109]
 PIN pi2[110]
  DIRECTION OUTPUT ;
  USE SIGNAL ;
  PORT
   LAYER M4 ;
   RECT 43.008000 537.132000 43.200000 537.156000 ;
  END
 END pi2[110]
 PIN pi2[111]
  DIRECTION OUTPUT ;
  USE SIGNAL ;
  PORT
   LAYER M6 ;
   RECT 43.008000 536.752000 43.200000 536.784000 ;
  END
 END pi2[111]
 PIN pi2[112]
  DIRECTION OUTPUT ;
  USE SIGNAL ;
  PORT
   LAYER M4 ;
   RECT 43.008000 537.468000 43.200000 537.492000 ;
  END
 END pi2[112]
 PIN pi2[113]
  DIRECTION OUTPUT ;
  USE SIGNAL ;
  PORT
   LAYER M6 ;
   RECT 43.008000 537.008000 43.200000 537.040000 ;
  END
 END pi2[113]
 PIN pi2[114]
  DIRECTION OUTPUT ;
  USE SIGNAL ;
  PORT
   LAYER M4 ;
   RECT 43.008000 537.804000 43.200000 537.828000 ;
  END
 END pi2[114]
 PIN pi2[115]
  DIRECTION OUTPUT ;
  USE SIGNAL ;
  PORT
   LAYER M6 ;
   RECT 43.008000 537.264000 43.200000 537.296000 ;
  END
 END pi2[115]
 PIN pi2[116]
  DIRECTION OUTPUT ;
  USE SIGNAL ;
  PORT
   LAYER M4 ;
   RECT 43.008000 538.140000 43.200000 538.164000 ;
  END
 END pi2[116]
 PIN pi2[117]
  DIRECTION OUTPUT ;
  USE SIGNAL ;
  PORT
   LAYER M6 ;
   RECT 43.008000 538.480000 43.200000 538.512000 ;
  END
 END pi2[117]
 PIN pi2[118]
  DIRECTION OUTPUT ;
  USE SIGNAL ;
  PORT
   LAYER M4 ;
   RECT 43.008000 538.476000 43.200000 538.500000 ;
  END
 END pi2[118]
 PIN pi2[119]
  DIRECTION OUTPUT ;
  USE SIGNAL ;
  PORT
   LAYER M6 ;
   RECT 43.008000 538.736000 43.200000 538.768000 ;
  END
 END pi2[119]
 PIN pi2[120]
  DIRECTION OUTPUT ;
  USE SIGNAL ;
  PORT
   LAYER M4 ;
   RECT 43.008000 538.812000 43.200000 538.836000 ;
  END
 END pi2[120]
 PIN pi2[121]
  DIRECTION OUTPUT ;
  USE SIGNAL ;
  PORT
   LAYER M6 ;
   RECT 43.008000 539.056000 43.200000 539.088000 ;
  END
 END pi2[121]
 PIN pi2[122]
  DIRECTION OUTPUT ;
  USE SIGNAL ;
  PORT
   LAYER M4 ;
   RECT 43.008000 539.148000 43.200000 539.172000 ;
  END
 END pi2[122]
 PIN pi2[123]
  DIRECTION OUTPUT ;
  USE SIGNAL ;
  PORT
   LAYER M6 ;
   RECT 43.008000 539.312000 43.200000 539.344000 ;
  END
 END pi2[123]
 PIN pi2[124]
  DIRECTION OUTPUT ;
  USE SIGNAL ;
  PORT
   LAYER M4 ;
   RECT 43.008000 539.484000 43.200000 539.508000 ;
  END
 END pi2[124]
 PIN pi2[125]
  DIRECTION OUTPUT ;
  USE SIGNAL ;
  PORT
   LAYER M6 ;
   RECT 43.008000 539.568000 43.200000 539.600000 ;
  END
 END pi2[125]
 PIN pi2[126]
  DIRECTION OUTPUT ;
  USE SIGNAL ;
  PORT
   LAYER M4 ;
   RECT 43.008000 539.820000 43.200000 539.844000 ;
  END
 END pi2[126]
 PIN pi2[127]
  DIRECTION OUTPUT ;
  USE SIGNAL ;
  PORT
   LAYER M6 ;
   RECT 43.008000 539.824000 43.200000 539.856000 ;
  END
 END pi2[127]
 PIN pi2[128]
  DIRECTION OUTPUT ;
  USE SIGNAL ;
  PORT
   LAYER M4 ;
   RECT 43.008000 540.156000 43.200000 540.180000 ;
  END
 END pi2[128]
 PIN pi2[129]
  DIRECTION OUTPUT ;
  USE SIGNAL ;
  PORT
   LAYER M6 ;
   RECT 43.008000 540.080000 43.200000 540.112000 ;
  END
 END pi2[129]
 PIN pi2[130]
  DIRECTION OUTPUT ;
  USE SIGNAL ;
  PORT
   LAYER M4 ;
   RECT 43.008000 540.492000 43.200000 540.516000 ;
  END
 END pi2[130]
 PIN pi2[131]
  DIRECTION OUTPUT ;
  USE SIGNAL ;
  PORT
   LAYER M6 ;
   RECT 43.008000 540.336000 43.200000 540.368000 ;
  END
 END pi2[131]
 PIN pi2[132]
  DIRECTION OUTPUT ;
  USE SIGNAL ;
  PORT
   LAYER M4 ;
   RECT 43.008000 540.828000 43.200000 540.852000 ;
  END
 END pi2[132]
 PIN pi2[133]
  DIRECTION OUTPUT ;
  USE SIGNAL ;
  PORT
   LAYER M6 ;
   RECT 43.008000 540.592000 43.200000 540.624000 ;
  END
 END pi2[133]
 PIN pi2[134]
  DIRECTION OUTPUT ;
  USE SIGNAL ;
  PORT
   LAYER M4 ;
   RECT 43.008000 541.164000 43.200000 541.188000 ;
  END
 END pi2[134]
 PIN pi2[135]
  DIRECTION OUTPUT ;
  USE SIGNAL ;
  PORT
   LAYER M6 ;
   RECT 43.008000 540.848000 43.200000 540.880000 ;
  END
 END pi2[135]
 PIN pi2[136]
  DIRECTION OUTPUT ;
  USE SIGNAL ;
  PORT
   LAYER M4 ;
   RECT 43.008000 541.500000 43.200000 541.524000 ;
  END
 END pi2[136]
 PIN pi2[137]
  DIRECTION OUTPUT ;
  USE SIGNAL ;
  PORT
   LAYER M6 ;
   RECT 43.008000 541.104000 43.200000 541.136000 ;
  END
 END pi2[137]
 PIN pi2[138]
  DIRECTION OUTPUT ;
  USE SIGNAL ;
  PORT
   LAYER M4 ;
   RECT 43.008000 541.836000 43.200000 541.860000 ;
  END
 END pi2[138]
 PIN pi2[139]
  DIRECTION OUTPUT ;
  USE SIGNAL ;
  PORT
   LAYER M6 ;
   RECT 43.008000 541.360000 43.200000 541.392000 ;
  END
 END pi2[139]
 PIN pi2[140]
  DIRECTION OUTPUT ;
  USE SIGNAL ;
  PORT
   LAYER M4 ;
   RECT 43.008000 542.172000 43.200000 542.196000 ;
  END
 END pi2[140]
 PIN pi2[141]
  DIRECTION OUTPUT ;
  USE SIGNAL ;
  PORT
   LAYER M6 ;
   RECT 43.008000 542.640000 43.200000 542.672000 ;
  END
 END pi2[141]
 PIN pi2[142]
  DIRECTION OUTPUT ;
  USE SIGNAL ;
  PORT
   LAYER M4 ;
   RECT 43.008000 542.508000 43.200000 542.532000 ;
  END
 END pi2[142]
 PIN pi2[143]
  DIRECTION OUTPUT ;
  USE SIGNAL ;
  PORT
   LAYER M6 ;
   RECT 43.008000 542.960000 43.200000 542.992000 ;
  END
 END pi2[143]
 PIN pi2[144]
  DIRECTION OUTPUT ;
  USE SIGNAL ;
  PORT
   LAYER M4 ;
   RECT 43.008000 542.844000 43.200000 542.868000 ;
  END
 END pi2[144]
 PIN pi2[145]
  DIRECTION OUTPUT ;
  USE SIGNAL ;
  PORT
   LAYER M6 ;
   RECT 43.008000 543.216000 43.200000 543.248000 ;
  END
 END pi2[145]
 PIN pi2[146]
  DIRECTION OUTPUT ;
  USE SIGNAL ;
  PORT
   LAYER M4 ;
   RECT 43.008000 543.132000 43.200000 543.156000 ;
  END
 END pi2[146]
 PIN pi2[147]
  DIRECTION OUTPUT ;
  USE SIGNAL ;
  PORT
   LAYER M6 ;
   RECT 43.008000 543.472000 43.200000 543.504000 ;
  END
 END pi2[147]
 PIN pi2[148]
  DIRECTION OUTPUT ;
  USE SIGNAL ;
  PORT
   LAYER M4 ;
   RECT 43.008000 543.468000 43.200000 543.492000 ;
  END
 END pi2[148]
 PIN pi2[149]
  DIRECTION OUTPUT ;
  USE SIGNAL ;
  PORT
   LAYER M6 ;
   RECT 43.008000 543.728000 43.200000 543.760000 ;
  END
 END pi2[149]
 PIN pi2[150]
  DIRECTION OUTPUT ;
  USE SIGNAL ;
  PORT
   LAYER M4 ;
   RECT 43.008000 543.804000 43.200000 543.828000 ;
  END
 END pi2[150]
 PIN pi2[151]
  DIRECTION OUTPUT ;
  USE SIGNAL ;
  PORT
   LAYER M6 ;
   RECT 43.008000 543.984000 43.200000 544.016000 ;
  END
 END pi2[151]
 PIN pi2[152]
  DIRECTION OUTPUT ;
  USE SIGNAL ;
  PORT
   LAYER M4 ;
   RECT 43.008000 544.140000 43.200000 544.164000 ;
  END
 END pi2[152]
 PIN pi2[153]
  DIRECTION OUTPUT ;
  USE SIGNAL ;
  PORT
   LAYER M6 ;
   RECT 43.008000 544.240000 43.200000 544.272000 ;
  END
 END pi2[153]
 PIN pi2[154]
  DIRECTION OUTPUT ;
  USE SIGNAL ;
  PORT
   LAYER M4 ;
   RECT 43.008000 544.476000 43.200000 544.500000 ;
  END
 END pi2[154]
 PIN pi2[155]
  DIRECTION OUTPUT ;
  USE SIGNAL ;
  PORT
   LAYER M6 ;
   RECT 43.008000 544.496000 43.200000 544.528000 ;
  END
 END pi2[155]
 PIN pi2[156]
  DIRECTION OUTPUT ;
  USE SIGNAL ;
  PORT
   LAYER M4 ;
   RECT 43.008000 544.812000 43.200000 544.836000 ;
  END
 END pi2[156]
 PIN pi2[157]
  DIRECTION OUTPUT ;
  USE SIGNAL ;
  PORT
   LAYER M6 ;
   RECT 43.008000 544.752000 43.200000 544.784000 ;
  END
 END pi2[157]
 PIN pi2[158]
  DIRECTION OUTPUT ;
  USE SIGNAL ;
  PORT
   LAYER M4 ;
   RECT 43.008000 545.148000 43.200000 545.172000 ;
  END
 END pi2[158]
 PIN pi2[159]
  DIRECTION OUTPUT ;
  USE SIGNAL ;
  PORT
   LAYER M6 ;
   RECT 43.008000 545.008000 43.200000 545.040000 ;
  END
 END pi2[159]
 PIN pi2[160]
  DIRECTION OUTPUT ;
  USE SIGNAL ;
  PORT
   LAYER M4 ;
   RECT 43.008000 545.484000 43.200000 545.508000 ;
  END
 END pi2[160]
 PIN pi2[161]
  DIRECTION OUTPUT ;
  USE SIGNAL ;
  PORT
   LAYER M6 ;
   RECT 43.008000 545.264000 43.200000 545.296000 ;
  END
 END pi2[161]
 PIN pi2[162]
  DIRECTION OUTPUT ;
  USE SIGNAL ;
  PORT
   LAYER M4 ;
   RECT 43.008000 545.820000 43.200000 545.844000 ;
  END
 END pi2[162]
 PIN pi2[163]
  DIRECTION OUTPUT ;
  USE SIGNAL ;
  PORT
   LAYER M6 ;
   RECT 43.008000 545.584000 43.200000 545.616000 ;
  END
 END pi2[163]
 PIN pi2[164]
  DIRECTION OUTPUT ;
  USE SIGNAL ;
  PORT
   LAYER M4 ;
   RECT 43.008000 546.156000 43.200000 546.180000 ;
  END
 END pi2[164]
 PIN pi2[165]
  DIRECTION OUTPUT ;
  USE SIGNAL ;
  PORT
   LAYER M6 ;
   RECT 43.008000 545.840000 43.200000 545.872000 ;
  END
 END pi2[165]
 PIN pi2[166]
  DIRECTION OUTPUT ;
  USE SIGNAL ;
  PORT
   LAYER M4 ;
   RECT 43.008000 546.492000 43.200000 546.516000 ;
  END
 END pi2[166]
 PIN pi2[167]
  DIRECTION OUTPUT ;
  USE SIGNAL ;
  PORT
   LAYER M6 ;
   RECT 43.008000 547.056000 43.200000 547.088000 ;
  END
 END pi2[167]
 PIN pi2[168]
  DIRECTION OUTPUT ;
  USE SIGNAL ;
  PORT
   LAYER M4 ;
   RECT 43.008000 546.828000 43.200000 546.852000 ;
  END
 END pi2[168]
 PIN pi2[169]
  DIRECTION OUTPUT ;
  USE SIGNAL ;
  PORT
   LAYER M6 ;
   RECT 43.008000 547.312000 43.200000 547.344000 ;
  END
 END pi2[169]
 PIN pi2[170]
  DIRECTION OUTPUT ;
  USE SIGNAL ;
  PORT
   LAYER M4 ;
   RECT 43.008000 547.164000 43.200000 547.188000 ;
  END
 END pi2[170]
 PIN pi2[171]
  DIRECTION OUTPUT ;
  USE SIGNAL ;
  PORT
   LAYER M6 ;
   RECT 43.008000 547.568000 43.200000 547.600000 ;
  END
 END pi2[171]
 PIN pi2[172]
  DIRECTION OUTPUT ;
  USE SIGNAL ;
  PORT
   LAYER M4 ;
   RECT 43.008000 547.500000 43.200000 547.524000 ;
  END
 END pi2[172]
 PIN pi2[173]
  DIRECTION OUTPUT ;
  USE SIGNAL ;
  PORT
   LAYER M6 ;
   RECT 43.008000 547.824000 43.200000 547.856000 ;
  END
 END pi2[173]
 PIN pi2[174]
  DIRECTION OUTPUT ;
  USE SIGNAL ;
  PORT
   LAYER M4 ;
   RECT 43.008000 547.836000 43.200000 547.860000 ;
  END
 END pi2[174]
 PIN pi2[175]
  DIRECTION OUTPUT ;
  USE SIGNAL ;
  PORT
   LAYER M6 ;
   RECT 43.008000 548.080000 43.200000 548.112000 ;
  END
 END pi2[175]
 PIN pi2[176]
  DIRECTION OUTPUT ;
  USE SIGNAL ;
  PORT
   LAYER M4 ;
   RECT 43.008000 548.172000 43.200000 548.196000 ;
  END
 END pi2[176]
 PIN pi2[177]
  DIRECTION OUTPUT ;
  USE SIGNAL ;
  PORT
   LAYER M6 ;
   RECT 43.008000 548.336000 43.200000 548.368000 ;
  END
 END pi2[177]
 PIN pi2[178]
  DIRECTION OUTPUT ;
  USE SIGNAL ;
  PORT
   LAYER M4 ;
   RECT 43.008000 548.508000 43.200000 548.532000 ;
  END
 END pi2[178]
 PIN pi2[179]
  DIRECTION OUTPUT ;
  USE SIGNAL ;
  PORT
   LAYER M6 ;
   RECT 43.008000 548.592000 43.200000 548.624000 ;
  END
 END pi2[179]
 PIN pi2[180]
  DIRECTION OUTPUT ;
  USE SIGNAL ;
  PORT
   LAYER M4 ;
   RECT 43.008000 548.844000 43.200000 548.868000 ;
  END
 END pi2[180]
 PIN pi2[181]
  DIRECTION OUTPUT ;
  USE SIGNAL ;
  PORT
   LAYER M6 ;
   RECT 43.008000 548.848000 43.200000 548.880000 ;
  END
 END pi2[181]
 PIN pi2[182]
  DIRECTION OUTPUT ;
  USE SIGNAL ;
  PORT
   LAYER M4 ;
   RECT 43.008000 549.180000 43.200000 549.204000 ;
  END
 END pi2[182]
 PIN pi2[183]
  DIRECTION OUTPUT ;
  USE SIGNAL ;
  PORT
   LAYER M6 ;
   RECT 43.008000 549.168000 43.200000 549.200000 ;
  END
 END pi2[183]
 PIN pi2[184]
  DIRECTION OUTPUT ;
  USE SIGNAL ;
  PORT
   LAYER M4 ;
   RECT 43.008000 549.468000 43.200000 549.492000 ;
  END
 END pi2[184]
 PIN pi2[185]
  DIRECTION OUTPUT ;
  USE SIGNAL ;
  PORT
   LAYER M6 ;
   RECT 43.008000 549.424000 43.200000 549.456000 ;
  END
 END pi2[185]
 PIN pi2[186]
  DIRECTION OUTPUT ;
  USE SIGNAL ;
  PORT
   LAYER M4 ;
   RECT 43.008000 549.804000 43.200000 549.828000 ;
  END
 END pi2[186]
 PIN pi2[187]
  DIRECTION OUTPUT ;
  USE SIGNAL ;
  PORT
   LAYER M6 ;
   RECT 43.008000 549.680000 43.200000 549.712000 ;
  END
 END pi2[187]
 PIN pi2[188]
  DIRECTION OUTPUT ;
  USE SIGNAL ;
  PORT
   LAYER M4 ;
   RECT 43.008000 550.140000 43.200000 550.164000 ;
  END
 END pi2[188]
 PIN pi2[189]
  DIRECTION OUTPUT ;
  USE SIGNAL ;
  PORT
   LAYER M6 ;
   RECT 43.008000 549.936000 43.200000 549.968000 ;
  END
 END pi2[189]
 PIN pi2[190]
  DIRECTION OUTPUT ;
  USE SIGNAL ;
  PORT
   LAYER M4 ;
   RECT 43.008000 550.476000 43.200000 550.500000 ;
  END
 END pi2[190]
 PIN pi2[191]
  DIRECTION OUTPUT ;
  USE SIGNAL ;
  PORT
   LAYER M6 ;
   RECT 43.008000 550.192000 43.200000 550.224000 ;
  END
 END pi2[191]
 PIN pi2[192]
  DIRECTION OUTPUT ;
  USE SIGNAL ;
  PORT
   LAYER M4 ;
   RECT 43.008000 550.812000 43.200000 550.836000 ;
  END
 END pi2[192]
 PIN pi2[193]
  DIRECTION OUTPUT ;
  USE SIGNAL ;
  PORT
   LAYER M6 ;
   RECT 43.008000 551.408000 43.200000 551.440000 ;
  END
 END pi2[193]
 PIN pi2[194]
  DIRECTION OUTPUT ;
  USE SIGNAL ;
  PORT
   LAYER M4 ;
   RECT 43.008000 551.148000 43.200000 551.172000 ;
  END
 END pi2[194]
 PIN pi2[195]
  DIRECTION OUTPUT ;
  USE SIGNAL ;
  PORT
   LAYER M6 ;
   RECT 43.008000 551.664000 43.200000 551.696000 ;
  END
 END pi2[195]
 PIN pi2[196]
  DIRECTION OUTPUT ;
  USE SIGNAL ;
  PORT
   LAYER M4 ;
   RECT 43.008000 551.484000 43.200000 551.508000 ;
  END
 END pi2[196]
 PIN pi2[197]
  DIRECTION OUTPUT ;
  USE SIGNAL ;
  PORT
   LAYER M6 ;
   RECT 43.008000 551.920000 43.200000 551.952000 ;
  END
 END pi2[197]
 PIN pi2[198]
  DIRECTION OUTPUT ;
  USE SIGNAL ;
  PORT
   LAYER M4 ;
   RECT 43.008000 551.820000 43.200000 551.844000 ;
  END
 END pi2[198]
 PIN pi2[199]
  DIRECTION OUTPUT ;
  USE SIGNAL ;
  PORT
   LAYER M6 ;
   RECT 43.008000 552.176000 43.200000 552.208000 ;
  END
 END pi2[199]
 PIN pi2[200]
  DIRECTION OUTPUT ;
  USE SIGNAL ;
  PORT
   LAYER M4 ;
   RECT 43.008000 552.156000 43.200000 552.180000 ;
  END
 END pi2[200]
 PIN pi2[201]
  DIRECTION OUTPUT ;
  USE SIGNAL ;
  PORT
   LAYER M6 ;
   RECT 43.008000 552.432000 43.200000 552.464000 ;
  END
 END pi2[201]
 PIN pi2[202]
  DIRECTION OUTPUT ;
  USE SIGNAL ;
  PORT
   LAYER M4 ;
   RECT 43.008000 552.492000 43.200000 552.516000 ;
  END
 END pi2[202]
 PIN pi2[203]
  DIRECTION OUTPUT ;
  USE SIGNAL ;
  PORT
   LAYER M6 ;
   RECT 43.008000 552.752000 43.200000 552.784000 ;
  END
 END pi2[203]
 PIN pi2[204]
  DIRECTION OUTPUT ;
  USE SIGNAL ;
  PORT
   LAYER M4 ;
   RECT 43.008000 552.828000 43.200000 552.852000 ;
  END
 END pi2[204]
 PIN pi2[205]
  DIRECTION OUTPUT ;
  USE SIGNAL ;
  PORT
   LAYER M6 ;
   RECT 43.008000 553.008000 43.200000 553.040000 ;
  END
 END pi2[205]
 PIN pi2[206]
  DIRECTION OUTPUT ;
  USE SIGNAL ;
  PORT
   LAYER M4 ;
   RECT 43.008000 553.164000 43.200000 553.188000 ;
  END
 END pi2[206]
 PIN pi2[207]
  DIRECTION OUTPUT ;
  USE SIGNAL ;
  PORT
   LAYER M6 ;
   RECT 43.008000 553.264000 43.200000 553.296000 ;
  END
 END pi2[207]
 PIN pi2[208]
  DIRECTION OUTPUT ;
  USE SIGNAL ;
  PORT
   LAYER M4 ;
   RECT 43.008000 553.500000 43.200000 553.524000 ;
  END
 END pi2[208]
 PIN pi2[209]
  DIRECTION OUTPUT ;
  USE SIGNAL ;
  PORT
   LAYER M6 ;
   RECT 43.008000 553.520000 43.200000 553.552000 ;
  END
 END pi2[209]
 PIN pi2[210]
  DIRECTION OUTPUT ;
  USE SIGNAL ;
  PORT
   LAYER M4 ;
   RECT 43.008000 553.836000 43.200000 553.860000 ;
  END
 END pi2[210]
 PIN pi2[211]
  DIRECTION OUTPUT ;
  USE SIGNAL ;
  PORT
   LAYER M6 ;
   RECT 43.008000 553.776000 43.200000 553.808000 ;
  END
 END pi2[211]
 PIN pi2[212]
  DIRECTION OUTPUT ;
  USE SIGNAL ;
  PORT
   LAYER M4 ;
   RECT 43.008000 554.172000 43.200000 554.196000 ;
  END
 END pi2[212]
 PIN pi2[213]
  DIRECTION OUTPUT ;
  USE SIGNAL ;
  PORT
   LAYER M6 ;
   RECT 43.008000 554.032000 43.200000 554.064000 ;
  END
 END pi2[213]
 PIN pi2[214]
  DIRECTION OUTPUT ;
  USE SIGNAL ;
  PORT
   LAYER M4 ;
   RECT 43.008000 554.508000 43.200000 554.532000 ;
  END
 END pi2[214]
 PIN pi2[215]
  DIRECTION OUTPUT ;
  USE SIGNAL ;
  PORT
   LAYER M6 ;
   RECT 43.008000 554.288000 43.200000 554.320000 ;
  END
 END pi2[215]
 PIN pi2[216]
  DIRECTION OUTPUT ;
  USE SIGNAL ;
  PORT
   LAYER M4 ;
   RECT 43.008000 554.844000 43.200000 554.868000 ;
  END
 END pi2[216]
 PIN pi2[217]
  DIRECTION OUTPUT ;
  USE SIGNAL ;
  PORT
   LAYER M6 ;
   RECT 43.008000 554.544000 43.200000 554.576000 ;
  END
 END pi2[217]
 PIN pi2[218]
  DIRECTION OUTPUT ;
  USE SIGNAL ;
  PORT
   LAYER M4 ;
   RECT 43.008000 555.180000 43.200000 555.204000 ;
  END
 END pi2[218]
 PIN pi2[219]
  DIRECTION OUTPUT ;
  USE SIGNAL ;
  PORT
   LAYER M6 ;
   RECT 43.008000 555.760000 43.200000 555.792000 ;
  END
 END pi2[219]
 PIN pi2[220]
  DIRECTION OUTPUT ;
  USE SIGNAL ;
  PORT
   LAYER M4 ;
   RECT 43.008000 555.516000 43.200000 555.540000 ;
  END
 END pi2[220]
 PIN pi2[221]
  DIRECTION OUTPUT ;
  USE SIGNAL ;
  PORT
   LAYER M6 ;
   RECT 43.008000 556.016000 43.200000 556.048000 ;
  END
 END pi2[221]
 PIN pi2[222]
  DIRECTION OUTPUT ;
  USE SIGNAL ;
  PORT
   LAYER M4 ;
   RECT 43.008000 555.804000 43.200000 555.828000 ;
  END
 END pi2[222]
 PIN pi2[223]
  DIRECTION OUTPUT ;
  USE SIGNAL ;
  PORT
   LAYER M6 ;
   RECT 43.008000 556.272000 43.200000 556.304000 ;
  END
 END pi2[223]
 PIN pi2[224]
  DIRECTION OUTPUT ;
  USE SIGNAL ;
  PORT
   LAYER M4 ;
   RECT 43.008000 556.140000 43.200000 556.164000 ;
  END
 END pi2[224]
 PIN pi2[225]
  DIRECTION OUTPUT ;
  USE SIGNAL ;
  PORT
   LAYER M6 ;
   RECT 43.008000 556.592000 43.200000 556.624000 ;
  END
 END pi2[225]
 PIN pi2[226]
  DIRECTION OUTPUT ;
  USE SIGNAL ;
  PORT
   LAYER M4 ;
   RECT 43.008000 556.476000 43.200000 556.500000 ;
  END
 END pi2[226]
 PIN pi2[227]
  DIRECTION OUTPUT ;
  USE SIGNAL ;
  PORT
   LAYER M6 ;
   RECT 43.008000 556.848000 43.200000 556.880000 ;
  END
 END pi2[227]
 PIN pi2[228]
  DIRECTION OUTPUT ;
  USE SIGNAL ;
  PORT
   LAYER M4 ;
   RECT 43.008000 556.812000 43.200000 556.836000 ;
  END
 END pi2[228]
 PIN pi2[229]
  DIRECTION OUTPUT ;
  USE SIGNAL ;
  PORT
   LAYER M6 ;
   RECT 43.008000 557.104000 43.200000 557.136000 ;
  END
 END pi2[229]
 PIN pi2[230]
  DIRECTION OUTPUT ;
  USE SIGNAL ;
  PORT
   LAYER M4 ;
   RECT 43.008000 557.148000 43.200000 557.172000 ;
  END
 END pi2[230]
 PIN pi2[231]
  DIRECTION OUTPUT ;
  USE SIGNAL ;
  PORT
   LAYER M6 ;
   RECT 43.008000 557.360000 43.200000 557.392000 ;
  END
 END pi2[231]
 PIN pi2[232]
  DIRECTION OUTPUT ;
  USE SIGNAL ;
  PORT
   LAYER M4 ;
   RECT 43.008000 557.484000 43.200000 557.508000 ;
  END
 END pi2[232]
 PIN pi2[233]
  DIRECTION OUTPUT ;
  USE SIGNAL ;
  PORT
   LAYER M6 ;
   RECT 43.008000 557.616000 43.200000 557.648000 ;
  END
 END pi2[233]
 PIN pi2[234]
  DIRECTION OUTPUT ;
  USE SIGNAL ;
  PORT
   LAYER M4 ;
   RECT 43.008000 557.820000 43.200000 557.844000 ;
  END
 END pi2[234]
 PIN pi2[235]
  DIRECTION OUTPUT ;
  USE SIGNAL ;
  PORT
   LAYER M6 ;
   RECT 43.008000 557.872000 43.200000 557.904000 ;
  END
 END pi2[235]
 PIN pi2[236]
  DIRECTION OUTPUT ;
  USE SIGNAL ;
  PORT
   LAYER M4 ;
   RECT 43.008000 558.156000 43.200000 558.180000 ;
  END
 END pi2[236]
 PIN pi2[237]
  DIRECTION OUTPUT ;
  USE SIGNAL ;
  PORT
   LAYER M6 ;
   RECT 43.008000 558.128000 43.200000 558.160000 ;
  END
 END pi2[237]
 PIN pi2[238]
  DIRECTION OUTPUT ;
  USE SIGNAL ;
  PORT
   LAYER M4 ;
   RECT 43.008000 558.492000 43.200000 558.516000 ;
  END
 END pi2[238]
 PIN pi2[239]
  DIRECTION OUTPUT ;
  USE SIGNAL ;
  PORT
   LAYER M6 ;
   RECT 43.008000 558.384000 43.200000 558.416000 ;
  END
 END pi2[239]
 PIN pi2[240]
  DIRECTION OUTPUT ;
  USE SIGNAL ;
  PORT
   LAYER M4 ;
   RECT 43.008000 558.828000 43.200000 558.852000 ;
  END
 END pi2[240]
 PIN pi2[241]
  DIRECTION OUTPUT ;
  USE SIGNAL ;
  PORT
   LAYER M6 ;
   RECT 43.008000 558.640000 43.200000 558.672000 ;
  END
 END pi2[241]
 PIN pi2[242]
  DIRECTION OUTPUT ;
  USE SIGNAL ;
  PORT
   LAYER M4 ;
   RECT 43.008000 559.164000 43.200000 559.188000 ;
  END
 END pi2[242]
 PIN pi2[243]
  DIRECTION OUTPUT ;
  USE SIGNAL ;
  PORT
   LAYER M6 ;
   RECT 43.008000 558.896000 43.200000 558.928000 ;
  END
 END pi2[243]
 PIN pi2[244]
  DIRECTION OUTPUT ;
  USE SIGNAL ;
  PORT
   LAYER M4 ;
   RECT 43.008000 559.500000 43.200000 559.524000 ;
  END
 END pi2[244]
 PIN pi2[245]
  DIRECTION OUTPUT ;
  USE SIGNAL ;
  PORT
   LAYER M6 ;
   RECT 43.008000 560.176000 43.200000 560.208000 ;
  END
 END pi2[245]
 PIN pi2[246]
  DIRECTION OUTPUT ;
  USE SIGNAL ;
  PORT
   LAYER M4 ;
   RECT 43.008000 559.836000 43.200000 559.860000 ;
  END
 END pi2[246]
 PIN pi2[247]
  DIRECTION OUTPUT ;
  USE SIGNAL ;
  PORT
   LAYER M6 ;
   RECT 43.008000 560.432000 43.200000 560.464000 ;
  END
 END pi2[247]
 PIN pi2[248]
  DIRECTION OUTPUT ;
  USE SIGNAL ;
  PORT
   LAYER M4 ;
   RECT 43.008000 560.172000 43.200000 560.196000 ;
  END
 END pi2[248]
 PIN pi2[249]
  DIRECTION OUTPUT ;
  USE SIGNAL ;
  PORT
   LAYER M6 ;
   RECT 43.008000 560.688000 43.200000 560.720000 ;
  END
 END pi2[249]
 PIN pi2[250]
  DIRECTION OUTPUT ;
  USE SIGNAL ;
  PORT
   LAYER M4 ;
   RECT 43.008000 560.508000 43.200000 560.532000 ;
  END
 END pi2[250]
 PIN pi2[251]
  DIRECTION OUTPUT ;
  USE SIGNAL ;
  PORT
   LAYER M6 ;
   RECT 43.008000 560.944000 43.200000 560.976000 ;
  END
 END pi2[251]
 PIN pi2[252]
  DIRECTION OUTPUT ;
  USE SIGNAL ;
  PORT
   LAYER M4 ;
   RECT 43.008000 560.844000 43.200000 560.868000 ;
  END
 END pi2[252]
 PIN pi2[253]
  DIRECTION OUTPUT ;
  USE SIGNAL ;
  PORT
   LAYER M6 ;
   RECT 43.008000 561.200000 43.200000 561.232000 ;
  END
 END pi2[253]
 PIN pi2[254]
  DIRECTION OUTPUT ;
  USE SIGNAL ;
  PORT
   LAYER M4 ;
   RECT 43.008000 561.180000 43.200000 561.204000 ;
  END
 END pi2[254]
 PIN pi2[255]
  DIRECTION OUTPUT ;
  USE SIGNAL ;
  PORT
   LAYER M6 ;
   RECT 43.008000 561.456000 43.200000 561.488000 ;
  END
 END pi2[255]
 PIN pi2[256]
  DIRECTION OUTPUT ;
  USE SIGNAL ;
  PORT
   LAYER M4 ;
   RECT 43.008000 561.516000 43.200000 561.540000 ;
  END
 END pi2[256]
 PIN pi2[257]
  DIRECTION OUTPUT ;
  USE SIGNAL ;
  PORT
   LAYER M6 ;
   RECT 43.008000 561.712000 43.200000 561.744000 ;
  END
 END pi2[257]
 PIN pi2[258]
  DIRECTION OUTPUT ;
  USE SIGNAL ;
  PORT
   LAYER M4 ;
   RECT 43.008000 561.852000 43.200000 561.876000 ;
  END
 END pi2[258]
 PIN pi2[259]
  DIRECTION OUTPUT ;
  USE SIGNAL ;
  PORT
   LAYER M6 ;
   RECT 43.008000 561.968000 43.200000 562.000000 ;
  END
 END pi2[259]
 PIN pi2[260]
  DIRECTION OUTPUT ;
  USE SIGNAL ;
  PORT
   LAYER M4 ;
   RECT 43.008000 562.140000 43.200000 562.164000 ;
  END
 END pi2[260]
 PIN pi2[261]
  DIRECTION OUTPUT ;
  USE SIGNAL ;
  PORT
   LAYER M6 ;
   RECT 43.008000 562.224000 43.200000 562.256000 ;
  END
 END pi2[261]
 PIN pi2[262]
  DIRECTION OUTPUT ;
  USE SIGNAL ;
  PORT
   LAYER M4 ;
   RECT 43.008000 562.476000 43.200000 562.500000 ;
  END
 END pi2[262]
 PIN pi2[263]
  DIRECTION OUTPUT ;
  USE SIGNAL ;
  PORT
   LAYER M6 ;
   RECT 43.008000 562.480000 43.200000 562.512000 ;
  END
 END pi2[263]
 PIN pi2[264]
  DIRECTION OUTPUT ;
  USE SIGNAL ;
  PORT
   LAYER M4 ;
   RECT 43.008000 562.812000 43.200000 562.836000 ;
  END
 END pi2[264]
 PIN pi2[265]
  DIRECTION OUTPUT ;
  USE SIGNAL ;
  PORT
   LAYER M6 ;
   RECT 43.008000 562.800000 43.200000 562.832000 ;
  END
 END pi2[265]
 PIN pi2[266]
  DIRECTION OUTPUT ;
  USE SIGNAL ;
  PORT
   LAYER M4 ;
   RECT 43.008000 563.148000 43.200000 563.172000 ;
  END
 END pi2[266]
 PIN pi2[267]
  DIRECTION OUTPUT ;
  USE SIGNAL ;
  PORT
   LAYER M6 ;
   RECT 43.008000 563.056000 43.200000 563.088000 ;
  END
 END pi2[267]
 PIN pi2[268]
  DIRECTION OUTPUT ;
  USE SIGNAL ;
  PORT
   LAYER M4 ;
   RECT 43.008000 563.484000 43.200000 563.508000 ;
  END
 END pi2[268]
 PIN pi2[269]
  DIRECTION OUTPUT ;
  USE SIGNAL ;
  PORT
   LAYER M6 ;
   RECT 43.008000 564.272000 43.200000 564.304000 ;
  END
 END pi2[269]
 PIN pi2[270]
  DIRECTION OUTPUT ;
  USE SIGNAL ;
  PORT
   LAYER M4 ;
   RECT 43.008000 563.820000 43.200000 563.844000 ;
  END
 END pi2[270]
 PIN pi2[271]
  DIRECTION OUTPUT ;
  USE SIGNAL ;
  PORT
   LAYER M6 ;
   RECT 43.008000 564.528000 43.200000 564.560000 ;
  END
 END pi2[271]
 PIN pi2[272]
  DIRECTION OUTPUT ;
  USE SIGNAL ;
  PORT
   LAYER M4 ;
   RECT 43.008000 564.156000 43.200000 564.180000 ;
  END
 END pi2[272]
 PIN pi2[273]
  DIRECTION OUTPUT ;
  USE SIGNAL ;
  PORT
   LAYER M6 ;
   RECT 43.008000 564.784000 43.200000 564.816000 ;
  END
 END pi2[273]
 PIN pi2[274]
  DIRECTION OUTPUT ;
  USE SIGNAL ;
  PORT
   LAYER M4 ;
   RECT 43.008000 564.492000 43.200000 564.516000 ;
  END
 END pi2[274]
 PIN pi2[275]
  DIRECTION OUTPUT ;
  USE SIGNAL ;
  PORT
   LAYER M6 ;
   RECT 43.008000 565.040000 43.200000 565.072000 ;
  END
 END pi2[275]
 PIN pi2[276]
  DIRECTION OUTPUT ;
  USE SIGNAL ;
  PORT
   LAYER M4 ;
   RECT 43.008000 564.828000 43.200000 564.852000 ;
  END
 END pi2[276]
 PIN pi2[277]
  DIRECTION OUTPUT ;
  USE SIGNAL ;
  PORT
   LAYER M6 ;
   RECT 43.008000 565.296000 43.200000 565.328000 ;
  END
 END pi2[277]
 PIN pi2[278]
  DIRECTION OUTPUT ;
  USE SIGNAL ;
  PORT
   LAYER M4 ;
   RECT 43.008000 565.164000 43.200000 565.188000 ;
  END
 END pi2[278]
 PIN pi2[279]
  DIRECTION OUTPUT ;
  USE SIGNAL ;
  PORT
   LAYER M6 ;
   RECT 43.008000 565.552000 43.200000 565.584000 ;
  END
 END pi2[279]
 PIN pi2[280]
  DIRECTION OUTPUT ;
  USE SIGNAL ;
  PORT
   LAYER M4 ;
   RECT 43.008000 565.500000 43.200000 565.524000 ;
  END
 END pi2[280]
 PIN pi2[281]
  DIRECTION OUTPUT ;
  USE SIGNAL ;
  PORT
   LAYER M6 ;
   RECT 43.008000 565.808000 43.200000 565.840000 ;
  END
 END pi2[281]
 PIN pi2[282]
  DIRECTION OUTPUT ;
  USE SIGNAL ;
  PORT
   LAYER M4 ;
   RECT 43.008000 565.836000 43.200000 565.860000 ;
  END
 END pi2[282]
 PIN pi2[283]
  DIRECTION OUTPUT ;
  USE SIGNAL ;
  PORT
   LAYER M6 ;
   RECT 43.008000 566.064000 43.200000 566.096000 ;
  END
 END pi2[283]
 PIN pi2[284]
  DIRECTION OUTPUT ;
  USE SIGNAL ;
  PORT
   LAYER M4 ;
   RECT 43.008000 566.172000 43.200000 566.196000 ;
  END
 END pi2[284]
 PIN pi2[285]
  DIRECTION OUTPUT ;
  USE SIGNAL ;
  PORT
   LAYER M4 ;
   RECT 43.008000 591.180000 43.200000 591.204000 ;
  END
 END pi2[285]
 PIN pi2[286]
  DIRECTION OUTPUT ;
  USE SIGNAL ;
  PORT
   LAYER M6 ;
   RECT 43.008000 591.024000 43.200000 591.056000 ;
  END
 END pi2[286]
 PIN pi2[287]
  DIRECTION OUTPUT ;
  USE SIGNAL ;
  PORT
   LAYER M4 ;
   RECT 43.008000 591.516000 43.200000 591.540000 ;
  END
 END pi2[287]
 PIN pi2[288]
  DIRECTION OUTPUT ;
  USE SIGNAL ;
  PORT
   LAYER M6 ;
   RECT 43.008000 591.280000 43.200000 591.312000 ;
  END
 END pi2[288]
 PIN fh2[0]
  DIRECTION OUTPUT ;
  USE SIGNAL ;
  PORT
   LAYER M4 ;
   RECT 43.008000 518.124000 43.200000 518.148000 ;
  END
 END fh2[0]
 PIN fh2[1]
  DIRECTION OUTPUT ;
  USE SIGNAL ;
  PORT
   LAYER M6 ;
   RECT 43.008000 518.000000 43.200000 518.032000 ;
  END
 END fh2[1]
 PIN fh2[2]
  DIRECTION OUTPUT ;
  USE SIGNAL ;
  PORT
   LAYER M4 ;
   RECT 43.008000 518.460000 43.200000 518.484000 ;
  END
 END fh2[2]
 PIN fh2[3]
  DIRECTION OUTPUT ;
  USE SIGNAL ;
  PORT
   LAYER M6 ;
   RECT 43.008000 518.256000 43.200000 518.288000 ;
  END
 END fh2[3]
 PIN rh2[0]
  DIRECTION OUTPUT ;
  USE SIGNAL ;
  PORT
   LAYER M4 ;
   RECT 43.008000 591.852000 43.200000 591.876000 ;
  END
 END rh2[0]
 PIN rh2[1]
  DIRECTION OUTPUT ;
  USE SIGNAL ;
  PORT
   LAYER M6 ;
   RECT 43.008000 591.536000 43.200000 591.568000 ;
  END
 END rh2[1]
 PIN rh2[2]
  DIRECTION OUTPUT ;
  USE SIGNAL ;
  PORT
   LAYER M4 ;
   RECT 43.008000 592.188000 43.200000 592.212000 ;
  END
 END rh2[2]
 PIN rh2[3]
  DIRECTION OUTPUT ;
  USE SIGNAL ;
  PORT
   LAYER M6 ;
   RECT 43.008000 591.792000 43.200000 591.824000 ;
  END
 END rh2[3]
 PIN po3[0]
  DIRECTION INPUT ;
  USE SIGNAL ;
  PORT
   LAYER M4 ;
   RECT 43.008000 265.068000 43.200000 265.092000 ;
  END
 END po3[0]
 PIN po3[1]
  DIRECTION INPUT ;
  USE SIGNAL ;
  PORT
   LAYER M6 ;
   RECT 43.008000 265.072000 43.200000 265.104000 ;
  END
 END po3[1]
 PIN po3[2]
  DIRECTION INPUT ;
  USE SIGNAL ;
  PORT
   LAYER M4 ;
   RECT 43.008000 265.404000 43.200000 265.428000 ;
  END
 END po3[2]
 PIN po3[3]
  DIRECTION INPUT ;
  USE SIGNAL ;
  PORT
   LAYER M6 ;
   RECT 43.008000 265.136000 43.200000 265.168000 ;
  END
 END po3[3]
 PIN po3[4]
  DIRECTION INPUT ;
  USE SIGNAL ;
  PORT
   LAYER M4 ;
   RECT 43.008000 265.740000 43.200000 265.764000 ;
  END
 END po3[4]
 PIN po3[5]
  DIRECTION INPUT ;
  USE SIGNAL ;
  PORT
   LAYER M6 ;
   RECT 43.008000 266.160000 43.200000 266.192000 ;
  END
 END po3[5]
 PIN po3[6]
  DIRECTION INPUT ;
  USE SIGNAL ;
  PORT
   LAYER M4 ;
   RECT 43.008000 266.076000 43.200000 266.100000 ;
  END
 END po3[6]
 PIN po3[7]
  DIRECTION INPUT ;
  USE SIGNAL ;
  PORT
   LAYER M6 ;
   RECT 43.008000 266.224000 43.200000 266.256000 ;
  END
 END po3[7]
 PIN po3[8]
  DIRECTION INPUT ;
  USE SIGNAL ;
  PORT
   LAYER M4 ;
   RECT 43.008000 266.412000 43.200000 266.436000 ;
  END
 END po3[8]
 PIN po3[9]
  DIRECTION INPUT ;
  USE SIGNAL ;
  PORT
   LAYER M6 ;
   RECT 43.008000 266.416000 43.200000 266.448000 ;
  END
 END po3[9]
 PIN po3[10]
  DIRECTION INPUT ;
  USE SIGNAL ;
  PORT
   LAYER M4 ;
   RECT 43.008000 266.748000 43.200000 266.772000 ;
  END
 END po3[10]
 PIN po3[11]
  DIRECTION INPUT ;
  USE SIGNAL ;
  PORT
   LAYER M6 ;
   RECT 43.008000 266.736000 43.200000 266.768000 ;
  END
 END po3[11]
 PIN po3[12]
  DIRECTION INPUT ;
  USE SIGNAL ;
  PORT
   LAYER M4 ;
   RECT 43.008000 267.084000 43.200000 267.108000 ;
  END
 END po3[12]
 PIN po3[13]
  DIRECTION INPUT ;
  USE SIGNAL ;
  PORT
   LAYER M6 ;
   RECT 43.008000 267.056000 43.200000 267.088000 ;
  END
 END po3[13]
 PIN po3[14]
  DIRECTION INPUT ;
  USE SIGNAL ;
  PORT
   LAYER M4 ;
   RECT 43.008000 267.420000 43.200000 267.444000 ;
  END
 END po3[14]
 PIN po3[15]
  DIRECTION INPUT ;
  USE SIGNAL ;
  PORT
   LAYER M6 ;
   RECT 43.008000 267.376000 43.200000 267.408000 ;
  END
 END po3[15]
 PIN po3[16]
  DIRECTION INPUT ;
  USE SIGNAL ;
  PORT
   LAYER M4 ;
   RECT 43.008000 267.708000 43.200000 267.732000 ;
  END
 END po3[16]
 PIN po3[17]
  DIRECTION INPUT ;
  USE SIGNAL ;
  PORT
   LAYER M6 ;
   RECT 43.008000 267.760000 43.200000 267.792000 ;
  END
 END po3[17]
 PIN po3[18]
  DIRECTION INPUT ;
  USE SIGNAL ;
  PORT
   LAYER M4 ;
   RECT 43.008000 268.044000 43.200000 268.068000 ;
  END
 END po3[18]
 PIN po3[19]
  DIRECTION INPUT ;
  USE SIGNAL ;
  PORT
   LAYER M6 ;
   RECT 43.008000 268.080000 43.200000 268.112000 ;
  END
 END po3[19]
 PIN po3[20]
  DIRECTION INPUT ;
  USE SIGNAL ;
  PORT
   LAYER M4 ;
   RECT 43.008000 268.380000 43.200000 268.404000 ;
  END
 END po3[20]
 PIN po3[21]
  DIRECTION INPUT ;
  USE SIGNAL ;
  PORT
   LAYER M6 ;
   RECT 43.008000 268.400000 43.200000 268.432000 ;
  END
 END po3[21]
 PIN po3[22]
  DIRECTION INPUT ;
  USE SIGNAL ;
  PORT
   LAYER M4 ;
   RECT 43.008000 268.716000 43.200000 268.740000 ;
  END
 END po3[22]
 PIN po3[23]
  DIRECTION INPUT ;
  USE SIGNAL ;
  PORT
   LAYER M6 ;
   RECT 43.008000 268.720000 43.200000 268.752000 ;
  END
 END po3[23]
 PIN po3[24]
  DIRECTION INPUT ;
  USE SIGNAL ;
  PORT
   LAYER M4 ;
   RECT 43.008000 269.052000 43.200000 269.076000 ;
  END
 END po3[24]
 PIN po3[25]
  DIRECTION INPUT ;
  USE SIGNAL ;
  PORT
   LAYER M6 ;
   RECT 43.008000 269.104000 43.200000 269.136000 ;
  END
 END po3[25]
 PIN po3[26]
  DIRECTION INPUT ;
  USE SIGNAL ;
  PORT
   LAYER M4 ;
   RECT 43.008000 269.388000 43.200000 269.412000 ;
  END
 END po3[26]
 PIN po3[27]
  DIRECTION INPUT ;
  USE SIGNAL ;
  PORT
   LAYER M6 ;
   RECT 43.008000 269.424000 43.200000 269.456000 ;
  END
 END po3[27]
 PIN po3[28]
  DIRECTION INPUT ;
  USE SIGNAL ;
  PORT
   LAYER M4 ;
   RECT 43.008000 269.724000 43.200000 269.748000 ;
  END
 END po3[28]
 PIN po3[29]
  DIRECTION INPUT ;
  USE SIGNAL ;
  PORT
   LAYER M6 ;
   RECT 43.008000 269.488000 43.200000 269.520000 ;
  END
 END po3[29]
 PIN po3[30]
  DIRECTION INPUT ;
  USE SIGNAL ;
  PORT
   LAYER M4 ;
   RECT 43.008000 270.060000 43.200000 270.084000 ;
  END
 END po3[30]
 PIN po3[31]
  DIRECTION INPUT ;
  USE SIGNAL ;
  PORT
   LAYER M6 ;
   RECT 43.008000 270.512000 43.200000 270.544000 ;
  END
 END po3[31]
 PIN po3[32]
  DIRECTION INPUT ;
  USE SIGNAL ;
  PORT
   LAYER M4 ;
   RECT 43.008000 270.396000 43.200000 270.420000 ;
  END
 END po3[32]
 PIN po3[33]
  DIRECTION INPUT ;
  USE SIGNAL ;
  PORT
   LAYER M6 ;
   RECT 43.008000 270.576000 43.200000 270.608000 ;
  END
 END po3[33]
 PIN po3[34]
  DIRECTION INPUT ;
  USE SIGNAL ;
  PORT
   LAYER M4 ;
   RECT 43.008000 270.732000 43.200000 270.756000 ;
  END
 END po3[34]
 PIN po3[35]
  DIRECTION INPUT ;
  USE SIGNAL ;
  PORT
   LAYER M6 ;
   RECT 43.008000 270.768000 43.200000 270.800000 ;
  END
 END po3[35]
 PIN po3[36]
  DIRECTION INPUT ;
  USE SIGNAL ;
  PORT
   LAYER M4 ;
   RECT 43.008000 271.068000 43.200000 271.092000 ;
  END
 END po3[36]
 PIN po3[37]
  DIRECTION INPUT ;
  USE SIGNAL ;
  PORT
   LAYER M6 ;
   RECT 43.008000 271.088000 43.200000 271.120000 ;
  END
 END po3[37]
 PIN po3[38]
  DIRECTION INPUT ;
  USE SIGNAL ;
  PORT
   LAYER M4 ;
   RECT 43.008000 271.404000 43.200000 271.428000 ;
  END
 END po3[38]
 PIN po3[39]
  DIRECTION INPUT ;
  USE SIGNAL ;
  PORT
   LAYER M6 ;
   RECT 43.008000 271.408000 43.200000 271.440000 ;
  END
 END po3[39]
 PIN po3[40]
  DIRECTION INPUT ;
  USE SIGNAL ;
  PORT
   LAYER M4 ;
   RECT 43.008000 271.740000 43.200000 271.764000 ;
  END
 END po3[40]
 PIN po3[41]
  DIRECTION INPUT ;
  USE SIGNAL ;
  PORT
   LAYER M6 ;
   RECT 43.008000 271.728000 43.200000 271.760000 ;
  END
 END po3[41]
 PIN po3[42]
  DIRECTION INPUT ;
  USE SIGNAL ;
  PORT
   LAYER M4 ;
   RECT 43.008000 272.028000 43.200000 272.052000 ;
  END
 END po3[42]
 PIN po3[43]
  DIRECTION INPUT ;
  USE SIGNAL ;
  PORT
   LAYER M6 ;
   RECT 43.008000 272.112000 43.200000 272.144000 ;
  END
 END po3[43]
 PIN po3[44]
  DIRECTION INPUT ;
  USE SIGNAL ;
  PORT
   LAYER M4 ;
   RECT 43.008000 272.364000 43.200000 272.388000 ;
  END
 END po3[44]
 PIN po3[45]
  DIRECTION INPUT ;
  USE SIGNAL ;
  PORT
   LAYER M6 ;
   RECT 43.008000 272.432000 43.200000 272.464000 ;
  END
 END po3[45]
 PIN po3[46]
  DIRECTION INPUT ;
  USE SIGNAL ;
  PORT
   LAYER M4 ;
   RECT 43.008000 272.700000 43.200000 272.724000 ;
  END
 END po3[46]
 PIN po3[47]
  DIRECTION INPUT ;
  USE SIGNAL ;
  PORT
   LAYER M6 ;
   RECT 43.008000 272.752000 43.200000 272.784000 ;
  END
 END po3[47]
 PIN po3[48]
  DIRECTION INPUT ;
  USE SIGNAL ;
  PORT
   LAYER M4 ;
   RECT 43.008000 273.036000 43.200000 273.060000 ;
  END
 END po3[48]
 PIN po3[49]
  DIRECTION INPUT ;
  USE SIGNAL ;
  PORT
   LAYER M6 ;
   RECT 43.008000 273.072000 43.200000 273.104000 ;
  END
 END po3[49]
 PIN po3[50]
  DIRECTION INPUT ;
  USE SIGNAL ;
  PORT
   LAYER M4 ;
   RECT 43.008000 273.372000 43.200000 273.396000 ;
  END
 END po3[50]
 PIN po3[51]
  DIRECTION INPUT ;
  USE SIGNAL ;
  PORT
   LAYER M6 ;
   RECT 43.008000 273.456000 43.200000 273.488000 ;
  END
 END po3[51]
 PIN po3[52]
  DIRECTION INPUT ;
  USE SIGNAL ;
  PORT
   LAYER M4 ;
   RECT 43.008000 273.708000 43.200000 273.732000 ;
  END
 END po3[52]
 PIN po3[53]
  DIRECTION INPUT ;
  USE SIGNAL ;
  PORT
   LAYER M6 ;
   RECT 43.008000 273.776000 43.200000 273.808000 ;
  END
 END po3[53]
 PIN po3[54]
  DIRECTION INPUT ;
  USE SIGNAL ;
  PORT
   LAYER M4 ;
   RECT 43.008000 274.044000 43.200000 274.068000 ;
  END
 END po3[54]
 PIN po3[55]
  DIRECTION INPUT ;
  USE SIGNAL ;
  PORT
   LAYER M6 ;
   RECT 43.008000 274.800000 43.200000 274.832000 ;
  END
 END po3[55]
 PIN po3[56]
  DIRECTION INPUT ;
  USE SIGNAL ;
  PORT
   LAYER M4 ;
   RECT 43.008000 274.380000 43.200000 274.404000 ;
  END
 END po3[56]
 PIN po3[57]
  DIRECTION INPUT ;
  USE SIGNAL ;
  PORT
   LAYER M6 ;
   RECT 43.008000 274.864000 43.200000 274.896000 ;
  END
 END po3[57]
 PIN po3[58]
  DIRECTION INPUT ;
  USE SIGNAL ;
  PORT
   LAYER M4 ;
   RECT 43.008000 274.716000 43.200000 274.740000 ;
  END
 END po3[58]
 PIN po3[59]
  DIRECTION INPUT ;
  USE SIGNAL ;
  PORT
   LAYER M6 ;
   RECT 43.008000 274.928000 43.200000 274.960000 ;
  END
 END po3[59]
 PIN po3[60]
  DIRECTION INPUT ;
  USE SIGNAL ;
  PORT
   LAYER M4 ;
   RECT 43.008000 275.052000 43.200000 275.076000 ;
  END
 END po3[60]
 PIN po3[61]
  DIRECTION INPUT ;
  USE SIGNAL ;
  PORT
   LAYER M6 ;
   RECT 43.008000 275.120000 43.200000 275.152000 ;
  END
 END po3[61]
 PIN po3[62]
  DIRECTION INPUT ;
  USE SIGNAL ;
  PORT
   LAYER M4 ;
   RECT 43.008000 275.388000 43.200000 275.412000 ;
  END
 END po3[62]
 PIN po3[63]
  DIRECTION INPUT ;
  USE SIGNAL ;
  PORT
   LAYER M6 ;
   RECT 43.008000 275.440000 43.200000 275.472000 ;
  END
 END po3[63]
 PIN po3[64]
  DIRECTION INPUT ;
  USE SIGNAL ;
  PORT
   LAYER M4 ;
   RECT 43.008000 275.724000 43.200000 275.748000 ;
  END
 END po3[64]
 PIN po3[65]
  DIRECTION INPUT ;
  USE SIGNAL ;
  PORT
   LAYER M6 ;
   RECT 43.008000 275.760000 43.200000 275.792000 ;
  END
 END po3[65]
 PIN po3[66]
  DIRECTION INPUT ;
  USE SIGNAL ;
  PORT
   LAYER M4 ;
   RECT 43.008000 276.060000 43.200000 276.084000 ;
  END
 END po3[66]
 PIN po3[67]
  DIRECTION INPUT ;
  USE SIGNAL ;
  PORT
   LAYER M6 ;
   RECT 43.008000 276.080000 43.200000 276.112000 ;
  END
 END po3[67]
 PIN po3[68]
  DIRECTION INPUT ;
  USE SIGNAL ;
  PORT
   LAYER M4 ;
   RECT 43.008000 276.348000 43.200000 276.372000 ;
  END
 END po3[68]
 PIN po3[69]
  DIRECTION INPUT ;
  USE SIGNAL ;
  PORT
   LAYER M6 ;
   RECT 43.008000 276.464000 43.200000 276.496000 ;
  END
 END po3[69]
 PIN po3[70]
  DIRECTION INPUT ;
  USE SIGNAL ;
  PORT
   LAYER M4 ;
   RECT 43.008000 276.684000 43.200000 276.708000 ;
  END
 END po3[70]
 PIN po3[71]
  DIRECTION INPUT ;
  USE SIGNAL ;
  PORT
   LAYER M6 ;
   RECT 43.008000 276.784000 43.200000 276.816000 ;
  END
 END po3[71]
 PIN po3[72]
  DIRECTION INPUT ;
  USE SIGNAL ;
  PORT
   LAYER M4 ;
   RECT 43.008000 277.020000 43.200000 277.044000 ;
  END
 END po3[72]
 PIN po3[73]
  DIRECTION INPUT ;
  USE SIGNAL ;
  PORT
   LAYER M6 ;
   RECT 43.008000 277.104000 43.200000 277.136000 ;
  END
 END po3[73]
 PIN po3[74]
  DIRECTION INPUT ;
  USE SIGNAL ;
  PORT
   LAYER M4 ;
   RECT 43.008000 277.356000 43.200000 277.380000 ;
  END
 END po3[74]
 PIN po3[75]
  DIRECTION INPUT ;
  USE SIGNAL ;
  PORT
   LAYER M6 ;
   RECT 43.008000 277.424000 43.200000 277.456000 ;
  END
 END po3[75]
 PIN po3[76]
  DIRECTION INPUT ;
  USE SIGNAL ;
  PORT
   LAYER M4 ;
   RECT 43.008000 277.692000 43.200000 277.716000 ;
  END
 END po3[76]
 PIN po3[77]
  DIRECTION INPUT ;
  USE SIGNAL ;
  PORT
   LAYER M6 ;
   RECT 43.008000 277.744000 43.200000 277.776000 ;
  END
 END po3[77]
 PIN po3[78]
  DIRECTION INPUT ;
  USE SIGNAL ;
  PORT
   LAYER M4 ;
   RECT 43.008000 278.028000 43.200000 278.052000 ;
  END
 END po3[78]
 PIN po3[79]
  DIRECTION INPUT ;
  USE SIGNAL ;
  PORT
   LAYER M6 ;
   RECT 43.008000 278.128000 43.200000 278.160000 ;
  END
 END po3[79]
 PIN po3[80]
  DIRECTION INPUT ;
  USE SIGNAL ;
  PORT
   LAYER M4 ;
   RECT 43.008000 278.364000 43.200000 278.388000 ;
  END
 END po3[80]
 PIN po3[81]
  DIRECTION INPUT ;
  USE SIGNAL ;
  PORT
   LAYER M6 ;
   RECT 43.008000 279.152000 43.200000 279.184000 ;
  END
 END po3[81]
 PIN po3[82]
  DIRECTION INPUT ;
  USE SIGNAL ;
  PORT
   LAYER M4 ;
   RECT 43.008000 278.700000 43.200000 278.724000 ;
  END
 END po3[82]
 PIN po3[83]
  DIRECTION INPUT ;
  USE SIGNAL ;
  PORT
   LAYER M6 ;
   RECT 43.008000 279.216000 43.200000 279.248000 ;
  END
 END po3[83]
 PIN po3[84]
  DIRECTION INPUT ;
  USE SIGNAL ;
  PORT
   LAYER M4 ;
   RECT 43.008000 279.036000 43.200000 279.060000 ;
  END
 END po3[84]
 PIN po3[85]
  DIRECTION INPUT ;
  USE SIGNAL ;
  PORT
   LAYER M6 ;
   RECT 43.008000 279.280000 43.200000 279.312000 ;
  END
 END po3[85]
 PIN po3[86]
  DIRECTION INPUT ;
  USE SIGNAL ;
  PORT
   LAYER M4 ;
   RECT 43.008000 279.372000 43.200000 279.396000 ;
  END
 END po3[86]
 PIN po3[87]
  DIRECTION INPUT ;
  USE SIGNAL ;
  PORT
   LAYER M6 ;
   RECT 43.008000 279.472000 43.200000 279.504000 ;
  END
 END po3[87]
 PIN po3[88]
  DIRECTION INPUT ;
  USE SIGNAL ;
  PORT
   LAYER M4 ;
   RECT 43.008000 279.708000 43.200000 279.732000 ;
  END
 END po3[88]
 PIN po3[89]
  DIRECTION INPUT ;
  USE SIGNAL ;
  PORT
   LAYER M6 ;
   RECT 43.008000 279.792000 43.200000 279.824000 ;
  END
 END po3[89]
 PIN po3[90]
  DIRECTION INPUT ;
  USE SIGNAL ;
  PORT
   LAYER M4 ;
   RECT 43.008000 280.044000 43.200000 280.068000 ;
  END
 END po3[90]
 PIN po3[91]
  DIRECTION INPUT ;
  USE SIGNAL ;
  PORT
   LAYER M6 ;
   RECT 43.008000 280.112000 43.200000 280.144000 ;
  END
 END po3[91]
 PIN po3[92]
  DIRECTION INPUT ;
  USE SIGNAL ;
  PORT
   LAYER M4 ;
   RECT 43.008000 280.380000 43.200000 280.404000 ;
  END
 END po3[92]
 PIN po3[93]
  DIRECTION INPUT ;
  USE SIGNAL ;
  PORT
   LAYER M6 ;
   RECT 43.008000 280.432000 43.200000 280.464000 ;
  END
 END po3[93]
 PIN po3[94]
  DIRECTION INPUT ;
  USE SIGNAL ;
  PORT
   LAYER M4 ;
   RECT 43.008000 280.716000 43.200000 280.740000 ;
  END
 END po3[94]
 PIN po3[95]
  DIRECTION INPUT ;
  USE SIGNAL ;
  PORT
   LAYER M6 ;
   RECT 43.008000 280.816000 43.200000 280.848000 ;
  END
 END po3[95]
 PIN po3[96]
  DIRECTION INPUT ;
  USE SIGNAL ;
  PORT
   LAYER M4 ;
   RECT 43.008000 281.004000 43.200000 281.028000 ;
  END
 END po3[96]
 PIN po3[97]
  DIRECTION INPUT ;
  USE SIGNAL ;
  PORT
   LAYER M6 ;
   RECT 43.008000 281.136000 43.200000 281.168000 ;
  END
 END po3[97]
 PIN po3[98]
  DIRECTION INPUT ;
  USE SIGNAL ;
  PORT
   LAYER M4 ;
   RECT 43.008000 281.340000 43.200000 281.364000 ;
  END
 END po3[98]
 PIN po3[99]
  DIRECTION INPUT ;
  USE SIGNAL ;
  PORT
   LAYER M6 ;
   RECT 43.008000 281.456000 43.200000 281.488000 ;
  END
 END po3[99]
 PIN po3[100]
  DIRECTION INPUT ;
  USE SIGNAL ;
  PORT
   LAYER M4 ;
   RECT 43.008000 281.676000 43.200000 281.700000 ;
  END
 END po3[100]
 PIN po3[101]
  DIRECTION INPUT ;
  USE SIGNAL ;
  PORT
   LAYER M6 ;
   RECT 43.008000 281.776000 43.200000 281.808000 ;
  END
 END po3[101]
 PIN po3[102]
  DIRECTION INPUT ;
  USE SIGNAL ;
  PORT
   LAYER M4 ;
   RECT 43.008000 282.012000 43.200000 282.036000 ;
  END
 END po3[102]
 PIN po3[103]
  DIRECTION INPUT ;
  USE SIGNAL ;
  PORT
   LAYER M6 ;
   RECT 43.008000 282.096000 43.200000 282.128000 ;
  END
 END po3[103]
 PIN po3[104]
  DIRECTION INPUT ;
  USE SIGNAL ;
  PORT
   LAYER M4 ;
   RECT 43.008000 282.348000 43.200000 282.372000 ;
  END
 END po3[104]
 PIN po3[105]
  DIRECTION INPUT ;
  USE SIGNAL ;
  PORT
   LAYER M6 ;
   RECT 43.008000 282.416000 43.200000 282.448000 ;
  END
 END po3[105]
 PIN po3[106]
  DIRECTION INPUT ;
  USE SIGNAL ;
  PORT
   LAYER M4 ;
   RECT 43.008000 282.684000 43.200000 282.708000 ;
  END
 END po3[106]
 PIN po3[107]
  DIRECTION INPUT ;
  USE SIGNAL ;
  PORT
   LAYER M6 ;
   RECT 43.008000 283.440000 43.200000 283.472000 ;
  END
 END po3[107]
 PIN po3[108]
  DIRECTION INPUT ;
  USE SIGNAL ;
  PORT
   LAYER M4 ;
   RECT 43.008000 283.020000 43.200000 283.044000 ;
  END
 END po3[108]
 PIN po3[109]
  DIRECTION INPUT ;
  USE SIGNAL ;
  PORT
   LAYER M6 ;
   RECT 43.008000 283.504000 43.200000 283.536000 ;
  END
 END po3[109]
 PIN po3[110]
  DIRECTION INPUT ;
  USE SIGNAL ;
  PORT
   LAYER M4 ;
   RECT 43.008000 283.356000 43.200000 283.380000 ;
  END
 END po3[110]
 PIN po3[111]
  DIRECTION INPUT ;
  USE SIGNAL ;
  PORT
   LAYER M6 ;
   RECT 43.008000 283.568000 43.200000 283.600000 ;
  END
 END po3[111]
 PIN po3[112]
  DIRECTION INPUT ;
  USE SIGNAL ;
  PORT
   LAYER M4 ;
   RECT 43.008000 283.692000 43.200000 283.716000 ;
  END
 END po3[112]
 PIN po3[113]
  DIRECTION INPUT ;
  USE SIGNAL ;
  PORT
   LAYER M6 ;
   RECT 43.008000 283.824000 43.200000 283.856000 ;
  END
 END po3[113]
 PIN po3[114]
  DIRECTION INPUT ;
  USE SIGNAL ;
  PORT
   LAYER M4 ;
   RECT 43.008000 284.028000 43.200000 284.052000 ;
  END
 END po3[114]
 PIN po3[115]
  DIRECTION INPUT ;
  USE SIGNAL ;
  PORT
   LAYER M6 ;
   RECT 43.008000 284.144000 43.200000 284.176000 ;
  END
 END po3[115]
 PIN po3[116]
  DIRECTION INPUT ;
  USE SIGNAL ;
  PORT
   LAYER M4 ;
   RECT 43.008000 284.364000 43.200000 284.388000 ;
  END
 END po3[116]
 PIN po3[117]
  DIRECTION INPUT ;
  USE SIGNAL ;
  PORT
   LAYER M6 ;
   RECT 43.008000 284.464000 43.200000 284.496000 ;
  END
 END po3[117]
 PIN po3[118]
  DIRECTION INPUT ;
  USE SIGNAL ;
  PORT
   LAYER M4 ;
   RECT 43.008000 284.700000 43.200000 284.724000 ;
  END
 END po3[118]
 PIN po3[119]
  DIRECTION INPUT ;
  USE SIGNAL ;
  PORT
   LAYER M6 ;
   RECT 43.008000 284.784000 43.200000 284.816000 ;
  END
 END po3[119]
 PIN po3[120]
  DIRECTION INPUT ;
  USE SIGNAL ;
  PORT
   LAYER M4 ;
   RECT 43.008000 285.036000 43.200000 285.060000 ;
  END
 END po3[120]
 PIN po3[121]
  DIRECTION INPUT ;
  USE SIGNAL ;
  PORT
   LAYER M6 ;
   RECT 43.008000 285.104000 43.200000 285.136000 ;
  END
 END po3[121]
 PIN po3[122]
  DIRECTION INPUT ;
  USE SIGNAL ;
  PORT
   LAYER M4 ;
   RECT 43.008000 285.324000 43.200000 285.348000 ;
  END
 END po3[122]
 PIN po3[123]
  DIRECTION INPUT ;
  USE SIGNAL ;
  PORT
   LAYER M6 ;
   RECT 43.008000 285.488000 43.200000 285.520000 ;
  END
 END po3[123]
 PIN po3[124]
  DIRECTION INPUT ;
  USE SIGNAL ;
  PORT
   LAYER M4 ;
   RECT 43.008000 285.660000 43.200000 285.684000 ;
  END
 END po3[124]
 PIN po3[125]
  DIRECTION INPUT ;
  USE SIGNAL ;
  PORT
   LAYER M6 ;
   RECT 43.008000 285.808000 43.200000 285.840000 ;
  END
 END po3[125]
 PIN po3[126]
  DIRECTION INPUT ;
  USE SIGNAL ;
  PORT
   LAYER M4 ;
   RECT 43.008000 285.996000 43.200000 286.020000 ;
  END
 END po3[126]
 PIN po3[127]
  DIRECTION INPUT ;
  USE SIGNAL ;
  PORT
   LAYER M6 ;
   RECT 43.008000 286.128000 43.200000 286.160000 ;
  END
 END po3[127]
 PIN po3[128]
  DIRECTION INPUT ;
  USE SIGNAL ;
  PORT
   LAYER M4 ;
   RECT 43.008000 286.332000 43.200000 286.356000 ;
  END
 END po3[128]
 PIN po3[129]
  DIRECTION INPUT ;
  USE SIGNAL ;
  PORT
   LAYER M6 ;
   RECT 43.008000 286.448000 43.200000 286.480000 ;
  END
 END po3[129]
 PIN po3[130]
  DIRECTION INPUT ;
  USE SIGNAL ;
  PORT
   LAYER M4 ;
   RECT 43.008000 286.668000 43.200000 286.692000 ;
  END
 END po3[130]
 PIN po3[131]
  DIRECTION INPUT ;
  USE SIGNAL ;
  PORT
   LAYER M6 ;
   RECT 43.008000 286.768000 43.200000 286.800000 ;
  END
 END po3[131]
 PIN po3[132]
  DIRECTION INPUT ;
  USE SIGNAL ;
  PORT
   LAYER M4 ;
   RECT 43.008000 287.004000 43.200000 287.028000 ;
  END
 END po3[132]
 PIN po3[133]
  DIRECTION INPUT ;
  USE SIGNAL ;
  PORT
   LAYER M6 ;
   RECT 43.008000 287.792000 43.200000 287.824000 ;
  END
 END po3[133]
 PIN po3[134]
  DIRECTION INPUT ;
  USE SIGNAL ;
  PORT
   LAYER M4 ;
   RECT 43.008000 287.340000 43.200000 287.364000 ;
  END
 END po3[134]
 PIN po3[135]
  DIRECTION INPUT ;
  USE SIGNAL ;
  PORT
   LAYER M6 ;
   RECT 43.008000 287.856000 43.200000 287.888000 ;
  END
 END po3[135]
 PIN po3[136]
  DIRECTION INPUT ;
  USE SIGNAL ;
  PORT
   LAYER M4 ;
   RECT 43.008000 287.676000 43.200000 287.700000 ;
  END
 END po3[136]
 PIN po3[137]
  DIRECTION INPUT ;
  USE SIGNAL ;
  PORT
   LAYER M6 ;
   RECT 43.008000 287.920000 43.200000 287.952000 ;
  END
 END po3[137]
 PIN po3[138]
  DIRECTION INPUT ;
  USE SIGNAL ;
  PORT
   LAYER M4 ;
   RECT 43.008000 288.012000 43.200000 288.036000 ;
  END
 END po3[138]
 PIN po3[139]
  DIRECTION INPUT ;
  USE SIGNAL ;
  PORT
   LAYER M6 ;
   RECT 43.008000 288.112000 43.200000 288.144000 ;
  END
 END po3[139]
 PIN po3[140]
  DIRECTION INPUT ;
  USE SIGNAL ;
  PORT
   LAYER M4 ;
   RECT 43.008000 288.348000 43.200000 288.372000 ;
  END
 END po3[140]
 PIN po3[141]
  DIRECTION INPUT ;
  USE SIGNAL ;
  PORT
   LAYER M6 ;
   RECT 43.008000 288.496000 43.200000 288.528000 ;
  END
 END po3[141]
 PIN po3[142]
  DIRECTION INPUT ;
  USE SIGNAL ;
  PORT
   LAYER M4 ;
   RECT 43.008000 288.684000 43.200000 288.708000 ;
  END
 END po3[142]
 PIN po3[143]
  DIRECTION INPUT ;
  USE SIGNAL ;
  PORT
   LAYER M6 ;
   RECT 43.008000 288.816000 43.200000 288.848000 ;
  END
 END po3[143]
 PIN po3[144]
  DIRECTION INPUT ;
  USE SIGNAL ;
  PORT
   LAYER M4 ;
   RECT 43.008000 289.020000 43.200000 289.044000 ;
  END
 END po3[144]
 PIN po3[145]
  DIRECTION INPUT ;
  USE SIGNAL ;
  PORT
   LAYER M6 ;
   RECT 43.008000 289.136000 43.200000 289.168000 ;
  END
 END po3[145]
 PIN po3[146]
  DIRECTION INPUT ;
  USE SIGNAL ;
  PORT
   LAYER M4 ;
   RECT 43.008000 289.356000 43.200000 289.380000 ;
  END
 END po3[146]
 PIN po3[147]
  DIRECTION INPUT ;
  USE SIGNAL ;
  PORT
   LAYER M6 ;
   RECT 43.008000 289.456000 43.200000 289.488000 ;
  END
 END po3[147]
 PIN po3[148]
  DIRECTION INPUT ;
  USE SIGNAL ;
  PORT
   LAYER M4 ;
   RECT 43.008000 289.644000 43.200000 289.668000 ;
  END
 END po3[148]
 PIN po3[149]
  DIRECTION INPUT ;
  USE SIGNAL ;
  PORT
   LAYER M6 ;
   RECT 43.008000 289.840000 43.200000 289.872000 ;
  END
 END po3[149]
 PIN po3[150]
  DIRECTION INPUT ;
  USE SIGNAL ;
  PORT
   LAYER M4 ;
   RECT 43.008000 289.980000 43.200000 290.004000 ;
  END
 END po3[150]
 PIN po3[151]
  DIRECTION INPUT ;
  USE SIGNAL ;
  PORT
   LAYER M6 ;
   RECT 43.008000 290.160000 43.200000 290.192000 ;
  END
 END po3[151]
 PIN po3[152]
  DIRECTION INPUT ;
  USE SIGNAL ;
  PORT
   LAYER M4 ;
   RECT 43.008000 290.316000 43.200000 290.340000 ;
  END
 END po3[152]
 PIN po3[153]
  DIRECTION INPUT ;
  USE SIGNAL ;
  PORT
   LAYER M6 ;
   RECT 43.008000 290.480000 43.200000 290.512000 ;
  END
 END po3[153]
 PIN po3[154]
  DIRECTION INPUT ;
  USE SIGNAL ;
  PORT
   LAYER M4 ;
   RECT 43.008000 290.652000 43.200000 290.676000 ;
  END
 END po3[154]
 PIN po3[155]
  DIRECTION INPUT ;
  USE SIGNAL ;
  PORT
   LAYER M6 ;
   RECT 43.008000 290.800000 43.200000 290.832000 ;
  END
 END po3[155]
 PIN po3[156]
  DIRECTION INPUT ;
  USE SIGNAL ;
  PORT
   LAYER M4 ;
   RECT 43.008000 290.988000 43.200000 291.012000 ;
  END
 END po3[156]
 PIN po3[157]
  DIRECTION INPUT ;
  USE SIGNAL ;
  PORT
   LAYER M6 ;
   RECT 43.008000 291.056000 43.200000 291.088000 ;
  END
 END po3[157]
 PIN po3[158]
  DIRECTION INPUT ;
  USE SIGNAL ;
  PORT
   LAYER M4 ;
   RECT 43.008000 291.324000 43.200000 291.348000 ;
  END
 END po3[158]
 PIN po3[159]
  DIRECTION INPUT ;
  USE SIGNAL ;
  PORT
   LAYER M6 ;
   RECT 43.008000 292.080000 43.200000 292.112000 ;
  END
 END po3[159]
 PIN po3[160]
  DIRECTION INPUT ;
  USE SIGNAL ;
  PORT
   LAYER M4 ;
   RECT 43.008000 291.660000 43.200000 291.684000 ;
  END
 END po3[160]
 PIN po3[161]
  DIRECTION INPUT ;
  USE SIGNAL ;
  PORT
   LAYER M6 ;
   RECT 43.008000 292.144000 43.200000 292.176000 ;
  END
 END po3[161]
 PIN po3[162]
  DIRECTION INPUT ;
  USE SIGNAL ;
  PORT
   LAYER M4 ;
   RECT 43.008000 291.996000 43.200000 292.020000 ;
  END
 END po3[162]
 PIN po3[163]
  DIRECTION INPUT ;
  USE SIGNAL ;
  PORT
   LAYER M6 ;
   RECT 43.008000 292.208000 43.200000 292.240000 ;
  END
 END po3[163]
 PIN po3[164]
  DIRECTION INPUT ;
  USE SIGNAL ;
  PORT
   LAYER M4 ;
   RECT 43.008000 292.332000 43.200000 292.356000 ;
  END
 END po3[164]
 PIN po3[165]
  DIRECTION INPUT ;
  USE SIGNAL ;
  PORT
   LAYER M6 ;
   RECT 43.008000 292.464000 43.200000 292.496000 ;
  END
 END po3[165]
 PIN po3[166]
  DIRECTION INPUT ;
  USE SIGNAL ;
  PORT
   LAYER M4 ;
   RECT 43.008000 292.668000 43.200000 292.692000 ;
  END
 END po3[166]
 PIN po3[167]
  DIRECTION INPUT ;
  USE SIGNAL ;
  PORT
   LAYER M6 ;
   RECT 43.008000 292.848000 43.200000 292.880000 ;
  END
 END po3[167]
 PIN po3[168]
  DIRECTION INPUT ;
  USE SIGNAL ;
  PORT
   LAYER M4 ;
   RECT 43.008000 293.004000 43.200000 293.028000 ;
  END
 END po3[168]
 PIN po3[169]
  DIRECTION INPUT ;
  USE SIGNAL ;
  PORT
   LAYER M6 ;
   RECT 43.008000 293.168000 43.200000 293.200000 ;
  END
 END po3[169]
 PIN po3[170]
  DIRECTION INPUT ;
  USE SIGNAL ;
  PORT
   LAYER M4 ;
   RECT 43.008000 293.340000 43.200000 293.364000 ;
  END
 END po3[170]
 PIN po3[171]
  DIRECTION INPUT ;
  USE SIGNAL ;
  PORT
   LAYER M6 ;
   RECT 43.008000 293.488000 43.200000 293.520000 ;
  END
 END po3[171]
 PIN po3[172]
  DIRECTION INPUT ;
  USE SIGNAL ;
  PORT
   LAYER M4 ;
   RECT 43.008000 293.676000 43.200000 293.700000 ;
  END
 END po3[172]
 PIN po3[173]
  DIRECTION INPUT ;
  USE SIGNAL ;
  PORT
   LAYER M6 ;
   RECT 43.008000 293.808000 43.200000 293.840000 ;
  END
 END po3[173]
 PIN po3[174]
  DIRECTION INPUT ;
  USE SIGNAL ;
  PORT
   LAYER M4 ;
   RECT 43.008000 294.012000 43.200000 294.036000 ;
  END
 END po3[174]
 PIN po3[175]
  DIRECTION INPUT ;
  USE SIGNAL ;
  PORT
   LAYER M6 ;
   RECT 43.008000 294.192000 43.200000 294.224000 ;
  END
 END po3[175]
 PIN po3[176]
  DIRECTION INPUT ;
  USE SIGNAL ;
  PORT
   LAYER M4 ;
   RECT 43.008000 294.300000 43.200000 294.324000 ;
  END
 END po3[176]
 PIN po3[177]
  DIRECTION INPUT ;
  USE SIGNAL ;
  PORT
   LAYER M6 ;
   RECT 43.008000 294.512000 43.200000 294.544000 ;
  END
 END po3[177]
 PIN po3[178]
  DIRECTION INPUT ;
  USE SIGNAL ;
  PORT
   LAYER M4 ;
   RECT 43.008000 294.636000 43.200000 294.660000 ;
  END
 END po3[178]
 PIN po3[179]
  DIRECTION INPUT ;
  USE SIGNAL ;
  PORT
   LAYER M6 ;
   RECT 43.008000 294.832000 43.200000 294.864000 ;
  END
 END po3[179]
 PIN po3[180]
  DIRECTION INPUT ;
  USE SIGNAL ;
  PORT
   LAYER M4 ;
   RECT 43.008000 294.972000 43.200000 294.996000 ;
  END
 END po3[180]
 PIN po3[181]
  DIRECTION INPUT ;
  USE SIGNAL ;
  PORT
   LAYER M6 ;
   RECT 43.008000 295.152000 43.200000 295.184000 ;
  END
 END po3[181]
 PIN po3[182]
  DIRECTION INPUT ;
  USE SIGNAL ;
  PORT
   LAYER M4 ;
   RECT 43.008000 295.308000 43.200000 295.332000 ;
  END
 END po3[182]
 PIN po3[183]
  DIRECTION INPUT ;
  USE SIGNAL ;
  PORT
   LAYER M6 ;
   RECT 43.008000 295.344000 43.200000 295.376000 ;
  END
 END po3[183]
 PIN po3[184]
  DIRECTION INPUT ;
  USE SIGNAL ;
  PORT
   LAYER M4 ;
   RECT 43.008000 295.644000 43.200000 295.668000 ;
  END
 END po3[184]
 PIN po3[185]
  DIRECTION INPUT ;
  USE SIGNAL ;
  PORT
   LAYER M6 ;
   RECT 43.008000 295.408000 43.200000 295.440000 ;
  END
 END po3[185]
 PIN po3[186]
  DIRECTION INPUT ;
  USE SIGNAL ;
  PORT
   LAYER M4 ;
   RECT 43.008000 295.980000 43.200000 296.004000 ;
  END
 END po3[186]
 PIN po3[187]
  DIRECTION INPUT ;
  USE SIGNAL ;
  PORT
   LAYER M6 ;
   RECT 43.008000 296.432000 43.200000 296.464000 ;
  END
 END po3[187]
 PIN po3[188]
  DIRECTION INPUT ;
  USE SIGNAL ;
  PORT
   LAYER M4 ;
   RECT 43.008000 296.316000 43.200000 296.340000 ;
  END
 END po3[188]
 PIN po3[189]
  DIRECTION INPUT ;
  USE SIGNAL ;
  PORT
   LAYER M6 ;
   RECT 43.008000 296.496000 43.200000 296.528000 ;
  END
 END po3[189]
 PIN po3[190]
  DIRECTION INPUT ;
  USE SIGNAL ;
  PORT
   LAYER M4 ;
   RECT 43.008000 296.652000 43.200000 296.676000 ;
  END
 END po3[190]
 PIN po3[191]
  DIRECTION INPUT ;
  USE SIGNAL ;
  PORT
   LAYER M6 ;
   RECT 43.008000 296.816000 43.200000 296.848000 ;
  END
 END po3[191]
 PIN po3[192]
  DIRECTION INPUT ;
  USE SIGNAL ;
  PORT
   LAYER M4 ;
   RECT 43.008000 296.988000 43.200000 297.012000 ;
  END
 END po3[192]
 PIN po3[193]
  DIRECTION INPUT ;
  USE SIGNAL ;
  PORT
   LAYER M6 ;
   RECT 43.008000 297.200000 43.200000 297.232000 ;
  END
 END po3[193]
 PIN po3[194]
  DIRECTION INPUT ;
  USE SIGNAL ;
  PORT
   LAYER M4 ;
   RECT 43.008000 297.324000 43.200000 297.348000 ;
  END
 END po3[194]
 PIN po3[195]
  DIRECTION INPUT ;
  USE SIGNAL ;
  PORT
   LAYER M6 ;
   RECT 43.008000 297.520000 43.200000 297.552000 ;
  END
 END po3[195]
 PIN po3[196]
  DIRECTION INPUT ;
  USE SIGNAL ;
  PORT
   LAYER M4 ;
   RECT 43.008000 297.660000 43.200000 297.684000 ;
  END
 END po3[196]
 PIN po3[197]
  DIRECTION INPUT ;
  USE SIGNAL ;
  PORT
   LAYER M6 ;
   RECT 43.008000 297.840000 43.200000 297.872000 ;
  END
 END po3[197]
 PIN po3[198]
  DIRECTION INPUT ;
  USE SIGNAL ;
  PORT
   LAYER M4 ;
   RECT 43.008000 297.996000 43.200000 298.020000 ;
  END
 END po3[198]
 PIN po3[199]
  DIRECTION INPUT ;
  USE SIGNAL ;
  PORT
   LAYER M6 ;
   RECT 43.008000 298.160000 43.200000 298.192000 ;
  END
 END po3[199]
 PIN po3[200]
  DIRECTION INPUT ;
  USE SIGNAL ;
  PORT
   LAYER M4 ;
   RECT 43.008000 298.332000 43.200000 298.356000 ;
  END
 END po3[200]
 PIN po3[201]
  DIRECTION INPUT ;
  USE SIGNAL ;
  PORT
   LAYER M6 ;
   RECT 43.008000 298.480000 43.200000 298.512000 ;
  END
 END po3[201]
 PIN po3[202]
  DIRECTION INPUT ;
  USE SIGNAL ;
  PORT
   LAYER M4 ;
   RECT 43.008000 298.620000 43.200000 298.644000 ;
  END
 END po3[202]
 PIN po3[203]
  DIRECTION INPUT ;
  USE SIGNAL ;
  PORT
   LAYER M6 ;
   RECT 43.008000 298.864000 43.200000 298.896000 ;
  END
 END po3[203]
 PIN po3[204]
  DIRECTION INPUT ;
  USE SIGNAL ;
  PORT
   LAYER M4 ;
   RECT 43.008000 298.956000 43.200000 298.980000 ;
  END
 END po3[204]
 PIN po3[205]
  DIRECTION INPUT ;
  USE SIGNAL ;
  PORT
   LAYER M6 ;
   RECT 43.008000 299.184000 43.200000 299.216000 ;
  END
 END po3[205]
 PIN po3[206]
  DIRECTION INPUT ;
  USE SIGNAL ;
  PORT
   LAYER M4 ;
   RECT 43.008000 299.292000 43.200000 299.316000 ;
  END
 END po3[206]
 PIN po3[207]
  DIRECTION INPUT ;
  USE SIGNAL ;
  PORT
   LAYER M6 ;
   RECT 43.008000 299.504000 43.200000 299.536000 ;
  END
 END po3[207]
 PIN po3[208]
  DIRECTION INPUT ;
  USE SIGNAL ;
  PORT
   LAYER M4 ;
   RECT 43.008000 299.628000 43.200000 299.652000 ;
  END
 END po3[208]
 PIN po3[209]
  DIRECTION INPUT ;
  USE SIGNAL ;
  PORT
   LAYER M6 ;
   RECT 43.008000 299.632000 43.200000 299.664000 ;
  END
 END po3[209]
 PIN po3[210]
  DIRECTION INPUT ;
  USE SIGNAL ;
  PORT
   LAYER M4 ;
   RECT 43.008000 299.964000 43.200000 299.988000 ;
  END
 END po3[210]
 PIN po3[211]
  DIRECTION INPUT ;
  USE SIGNAL ;
  PORT
   LAYER M6 ;
   RECT 43.008000 299.696000 43.200000 299.728000 ;
  END
 END po3[211]
 PIN po3[212]
  DIRECTION INPUT ;
  USE SIGNAL ;
  PORT
   LAYER M4 ;
   RECT 43.008000 300.300000 43.200000 300.324000 ;
  END
 END po3[212]
 PIN po3[213]
  DIRECTION INPUT ;
  USE SIGNAL ;
  PORT
   LAYER M6 ;
   RECT 43.008000 300.720000 43.200000 300.752000 ;
  END
 END po3[213]
 PIN po3[214]
  DIRECTION INPUT ;
  USE SIGNAL ;
  PORT
   LAYER M4 ;
   RECT 43.008000 300.636000 43.200000 300.660000 ;
  END
 END po3[214]
 PIN po3[215]
  DIRECTION INPUT ;
  USE SIGNAL ;
  PORT
   LAYER M6 ;
   RECT 43.008000 300.848000 43.200000 300.880000 ;
  END
 END po3[215]
 PIN po3[216]
  DIRECTION INPUT ;
  USE SIGNAL ;
  PORT
   LAYER M4 ;
   RECT 43.008000 300.972000 43.200000 300.996000 ;
  END
 END po3[216]
 PIN po3[217]
  DIRECTION INPUT ;
  USE SIGNAL ;
  PORT
   LAYER M6 ;
   RECT 43.008000 301.168000 43.200000 301.200000 ;
  END
 END po3[217]
 PIN po3[218]
  DIRECTION INPUT ;
  USE SIGNAL ;
  PORT
   LAYER M4 ;
   RECT 43.008000 301.308000 43.200000 301.332000 ;
  END
 END po3[218]
 PIN po3[219]
  DIRECTION INPUT ;
  USE SIGNAL ;
  PORT
   LAYER M6 ;
   RECT 43.008000 301.552000 43.200000 301.584000 ;
  END
 END po3[219]
 PIN po3[220]
  DIRECTION INPUT ;
  USE SIGNAL ;
  PORT
   LAYER M4 ;
   RECT 43.008000 301.644000 43.200000 301.668000 ;
  END
 END po3[220]
 PIN po3[221]
  DIRECTION INPUT ;
  USE SIGNAL ;
  PORT
   LAYER M6 ;
   RECT 43.008000 301.872000 43.200000 301.904000 ;
  END
 END po3[221]
 PIN po3[222]
  DIRECTION INPUT ;
  USE SIGNAL ;
  PORT
   LAYER M4 ;
   RECT 43.008000 301.980000 43.200000 302.004000 ;
  END
 END po3[222]
 PIN po3[223]
  DIRECTION INPUT ;
  USE SIGNAL ;
  PORT
   LAYER M6 ;
   RECT 43.008000 302.192000 43.200000 302.224000 ;
  END
 END po3[223]
 PIN po3[224]
  DIRECTION INPUT ;
  USE SIGNAL ;
  PORT
   LAYER M4 ;
   RECT 43.008000 302.316000 43.200000 302.340000 ;
  END
 END po3[224]
 PIN po3[225]
  DIRECTION INPUT ;
  USE SIGNAL ;
  PORT
   LAYER M6 ;
   RECT 43.008000 302.512000 43.200000 302.544000 ;
  END
 END po3[225]
 PIN po3[226]
  DIRECTION INPUT ;
  USE SIGNAL ;
  PORT
   LAYER M4 ;
   RECT 43.008000 302.652000 43.200000 302.676000 ;
  END
 END po3[226]
 PIN po3[227]
  DIRECTION INPUT ;
  USE SIGNAL ;
  PORT
   LAYER M6 ;
   RECT 43.008000 302.832000 43.200000 302.864000 ;
  END
 END po3[227]
 PIN po3[228]
  DIRECTION INPUT ;
  USE SIGNAL ;
  PORT
   LAYER M4 ;
   RECT 43.008000 302.988000 43.200000 303.012000 ;
  END
 END po3[228]
 PIN po3[229]
  DIRECTION INPUT ;
  USE SIGNAL ;
  PORT
   LAYER M6 ;
   RECT 43.008000 303.216000 43.200000 303.248000 ;
  END
 END po3[229]
 PIN po3[230]
  DIRECTION INPUT ;
  USE SIGNAL ;
  PORT
   LAYER M4 ;
   RECT 43.008000 303.276000 43.200000 303.300000 ;
  END
 END po3[230]
 PIN po3[231]
  DIRECTION INPUT ;
  USE SIGNAL ;
  PORT
   LAYER M6 ;
   RECT 43.008000 303.536000 43.200000 303.568000 ;
  END
 END po3[231]
 PIN po3[232]
  DIRECTION INPUT ;
  USE SIGNAL ;
  PORT
   LAYER M4 ;
   RECT 43.008000 303.612000 43.200000 303.636000 ;
  END
 END po3[232]
 PIN po3[233]
  DIRECTION INPUT ;
  USE SIGNAL ;
  PORT
   LAYER M6 ;
   RECT 43.008000 303.856000 43.200000 303.888000 ;
  END
 END po3[233]
 PIN po3[234]
  DIRECTION INPUT ;
  USE SIGNAL ;
  PORT
   LAYER M4 ;
   RECT 43.008000 303.948000 43.200000 303.972000 ;
  END
 END po3[234]
 PIN po3[235]
  DIRECTION INPUT ;
  USE SIGNAL ;
  PORT
   LAYER M6 ;
   RECT 43.008000 303.984000 43.200000 304.016000 ;
  END
 END po3[235]
 PIN po3[236]
  DIRECTION INPUT ;
  USE SIGNAL ;
  PORT
   LAYER M4 ;
   RECT 43.008000 304.284000 43.200000 304.308000 ;
  END
 END po3[236]
 PIN po3[237]
  DIRECTION INPUT ;
  USE SIGNAL ;
  PORT
   LAYER M6 ;
   RECT 43.008000 304.048000 43.200000 304.080000 ;
  END
 END po3[237]
 PIN po3[238]
  DIRECTION INPUT ;
  USE SIGNAL ;
  PORT
   LAYER M4 ;
   RECT 43.008000 304.620000 43.200000 304.644000 ;
  END
 END po3[238]
 PIN po3[239]
  DIRECTION INPUT ;
  USE SIGNAL ;
  PORT
   LAYER M6 ;
   RECT 43.008000 305.072000 43.200000 305.104000 ;
  END
 END po3[239]
 PIN po3[240]
  DIRECTION INPUT ;
  USE SIGNAL ;
  PORT
   LAYER M4 ;
   RECT 43.008000 304.956000 43.200000 304.980000 ;
  END
 END po3[240]
 PIN po3[241]
  DIRECTION INPUT ;
  USE SIGNAL ;
  PORT
   LAYER M6 ;
   RECT 43.008000 305.200000 43.200000 305.232000 ;
  END
 END po3[241]
 PIN po3[242]
  DIRECTION INPUT ;
  USE SIGNAL ;
  PORT
   LAYER M4 ;
   RECT 43.008000 305.292000 43.200000 305.316000 ;
  END
 END po3[242]
 PIN po3[243]
  DIRECTION INPUT ;
  USE SIGNAL ;
  PORT
   LAYER M6 ;
   RECT 43.008000 305.520000 43.200000 305.552000 ;
  END
 END po3[243]
 PIN po3[244]
  DIRECTION INPUT ;
  USE SIGNAL ;
  PORT
   LAYER M4 ;
   RECT 43.008000 305.628000 43.200000 305.652000 ;
  END
 END po3[244]
 PIN po3[245]
  DIRECTION INPUT ;
  USE SIGNAL ;
  PORT
   LAYER M6 ;
   RECT 43.008000 305.840000 43.200000 305.872000 ;
  END
 END po3[245]
 PIN po3[246]
  DIRECTION INPUT ;
  USE SIGNAL ;
  PORT
   LAYER M4 ;
   RECT 43.008000 305.964000 43.200000 305.988000 ;
  END
 END po3[246]
 PIN po3[247]
  DIRECTION INPUT ;
  USE SIGNAL ;
  PORT
   LAYER M6 ;
   RECT 43.008000 306.224000 43.200000 306.256000 ;
  END
 END po3[247]
 PIN po3[248]
  DIRECTION INPUT ;
  USE SIGNAL ;
  PORT
   LAYER M4 ;
   RECT 43.008000 306.300000 43.200000 306.324000 ;
  END
 END po3[248]
 PIN po3[249]
  DIRECTION INPUT ;
  USE SIGNAL ;
  PORT
   LAYER M6 ;
   RECT 43.008000 306.544000 43.200000 306.576000 ;
  END
 END po3[249]
 PIN po3[250]
  DIRECTION INPUT ;
  USE SIGNAL ;
  PORT
   LAYER M4 ;
   RECT 43.008000 306.636000 43.200000 306.660000 ;
  END
 END po3[250]
 PIN po3[251]
  DIRECTION INPUT ;
  USE SIGNAL ;
  PORT
   LAYER M6 ;
   RECT 43.008000 306.864000 43.200000 306.896000 ;
  END
 END po3[251]
 PIN po3[252]
  DIRECTION INPUT ;
  USE SIGNAL ;
  PORT
   LAYER M4 ;
   RECT 43.008000 306.972000 43.200000 306.996000 ;
  END
 END po3[252]
 PIN po3[253]
  DIRECTION INPUT ;
  USE SIGNAL ;
  PORT
   LAYER M6 ;
   RECT 43.008000 307.184000 43.200000 307.216000 ;
  END
 END po3[253]
 PIN po3[254]
  DIRECTION INPUT ;
  USE SIGNAL ;
  PORT
   LAYER M4 ;
   RECT 43.008000 307.308000 43.200000 307.332000 ;
  END
 END po3[254]
 PIN po3[255]
  DIRECTION INPUT ;
  USE SIGNAL ;
  PORT
   LAYER M6 ;
   RECT 43.008000 307.568000 43.200000 307.600000 ;
  END
 END po3[255]
 PIN po3[256]
  DIRECTION INPUT ;
  USE SIGNAL ;
  PORT
   LAYER M4 ;
   RECT 43.008000 307.596000 43.200000 307.620000 ;
  END
 END po3[256]
 PIN po3[257]
  DIRECTION INPUT ;
  USE SIGNAL ;
  PORT
   LAYER M6 ;
   RECT 43.008000 307.888000 43.200000 307.920000 ;
  END
 END po3[257]
 PIN po3[258]
  DIRECTION INPUT ;
  USE SIGNAL ;
  PORT
   LAYER M4 ;
   RECT 43.008000 307.932000 43.200000 307.956000 ;
  END
 END po3[258]
 PIN po3[259]
  DIRECTION INPUT ;
  USE SIGNAL ;
  PORT
   LAYER M6 ;
   RECT 43.008000 308.208000 43.200000 308.240000 ;
  END
 END po3[259]
 PIN po3[260]
  DIRECTION INPUT ;
  USE SIGNAL ;
  PORT
   LAYER M4 ;
   RECT 43.008000 308.268000 43.200000 308.292000 ;
  END
 END po3[260]
 PIN po3[261]
  DIRECTION INPUT ;
  USE SIGNAL ;
  PORT
   LAYER M6 ;
   RECT 43.008000 308.272000 43.200000 308.304000 ;
  END
 END po3[261]
 PIN po3[262]
  DIRECTION INPUT ;
  USE SIGNAL ;
  PORT
   LAYER M4 ;
   RECT 43.008000 308.604000 43.200000 308.628000 ;
  END
 END po3[262]
 PIN po3[263]
  DIRECTION INPUT ;
  USE SIGNAL ;
  PORT
   LAYER M6 ;
   RECT 43.008000 308.336000 43.200000 308.368000 ;
  END
 END po3[263]
 PIN po3[264]
  DIRECTION INPUT ;
  USE SIGNAL ;
  PORT
   LAYER M4 ;
   RECT 43.008000 308.940000 43.200000 308.964000 ;
  END
 END po3[264]
 PIN po3[265]
  DIRECTION INPUT ;
  USE SIGNAL ;
  PORT
   LAYER M6 ;
   RECT 43.008000 309.360000 43.200000 309.392000 ;
  END
 END po3[265]
 PIN po3[266]
  DIRECTION INPUT ;
  USE SIGNAL ;
  PORT
   LAYER M4 ;
   RECT 43.008000 309.276000 43.200000 309.300000 ;
  END
 END po3[266]
 PIN po3[267]
  DIRECTION INPUT ;
  USE SIGNAL ;
  PORT
   LAYER M6 ;
   RECT 43.008000 309.552000 43.200000 309.584000 ;
  END
 END po3[267]
 PIN po3[268]
  DIRECTION INPUT ;
  USE SIGNAL ;
  PORT
   LAYER M4 ;
   RECT 43.008000 309.612000 43.200000 309.636000 ;
  END
 END po3[268]
 PIN po3[269]
  DIRECTION INPUT ;
  USE SIGNAL ;
  PORT
   LAYER M6 ;
   RECT 43.008000 309.872000 43.200000 309.904000 ;
  END
 END po3[269]
 PIN po3[270]
  DIRECTION INPUT ;
  USE SIGNAL ;
  PORT
   LAYER M4 ;
   RECT 43.008000 309.948000 43.200000 309.972000 ;
  END
 END po3[270]
 PIN po3[271]
  DIRECTION INPUT ;
  USE SIGNAL ;
  PORT
   LAYER M6 ;
   RECT 43.008000 310.192000 43.200000 310.224000 ;
  END
 END po3[271]
 PIN po3[272]
  DIRECTION INPUT ;
  USE SIGNAL ;
  PORT
   LAYER M4 ;
   RECT 43.008000 310.284000 43.200000 310.308000 ;
  END
 END po3[272]
 PIN po3[273]
  DIRECTION INPUT ;
  USE SIGNAL ;
  PORT
   LAYER M6 ;
   RECT 43.008000 310.576000 43.200000 310.608000 ;
  END
 END po3[273]
 PIN po3[274]
  DIRECTION INPUT ;
  USE SIGNAL ;
  PORT
   LAYER M4 ;
   RECT 43.008000 310.620000 43.200000 310.644000 ;
  END
 END po3[274]
 PIN po3[275]
  DIRECTION INPUT ;
  USE SIGNAL ;
  PORT
   LAYER M6 ;
   RECT 43.008000 310.896000 43.200000 310.928000 ;
  END
 END po3[275]
 PIN po3[276]
  DIRECTION INPUT ;
  USE SIGNAL ;
  PORT
   LAYER M4 ;
   RECT 43.008000 310.956000 43.200000 310.980000 ;
  END
 END po3[276]
 PIN po3[277]
  DIRECTION INPUT ;
  USE SIGNAL ;
  PORT
   LAYER M6 ;
   RECT 43.008000 311.216000 43.200000 311.248000 ;
  END
 END po3[277]
 PIN po3[278]
  DIRECTION INPUT ;
  USE SIGNAL ;
  PORT
   LAYER M4 ;
   RECT 43.008000 311.292000 43.200000 311.316000 ;
  END
 END po3[278]
 PIN po3[279]
  DIRECTION INPUT ;
  USE SIGNAL ;
  PORT
   LAYER M6 ;
   RECT 43.008000 311.536000 43.200000 311.568000 ;
  END
 END po3[279]
 PIN po3[280]
  DIRECTION INPUT ;
  USE SIGNAL ;
  PORT
   LAYER M4 ;
   RECT 43.008000 311.628000 43.200000 311.652000 ;
  END
 END po3[280]
 PIN po3[281]
  DIRECTION INPUT ;
  USE SIGNAL ;
  PORT
   LAYER M6 ;
   RECT 43.008000 311.856000 43.200000 311.888000 ;
  END
 END po3[281]
 PIN po3[282]
  DIRECTION INPUT ;
  USE SIGNAL ;
  PORT
   LAYER M4 ;
   RECT 43.008000 311.916000 43.200000 311.940000 ;
  END
 END po3[282]
 PIN po3[283]
  DIRECTION INPUT ;
  USE SIGNAL ;
  PORT
   LAYER M6 ;
   RECT 43.008000 312.240000 43.200000 312.272000 ;
  END
 END po3[283]
 PIN po3[284]
  DIRECTION INPUT ;
  USE SIGNAL ;
  PORT
   LAYER M4 ;
   RECT 43.008000 312.252000 43.200000 312.276000 ;
  END
 END po3[284]
 PIN po3[285]
  DIRECTION INPUT ;
  USE SIGNAL ;
  PORT
   LAYER M6 ;
   RECT 43.008000 312.560000 43.200000 312.592000 ;
  END
 END po3[285]
 PIN po3[286]
  DIRECTION INPUT ;
  USE SIGNAL ;
  PORT
   LAYER M4 ;
   RECT 43.008000 312.588000 43.200000 312.612000 ;
  END
 END po3[286]
 PIN po3[287]
  DIRECTION INPUT ;
  USE SIGNAL ;
  PORT
   LAYER M6 ;
   RECT 43.008000 312.624000 43.200000 312.656000 ;
  END
 END po3[287]
 PIN po3[288]
  DIRECTION INPUT ;
  USE SIGNAL ;
  PORT
   LAYER M4 ;
   RECT 43.008000 312.924000 43.200000 312.948000 ;
  END
 END po3[288]
 PIN po3[289]
  DIRECTION INPUT ;
  USE SIGNAL ;
  PORT
   LAYER M6 ;
   RECT 43.008000 312.688000 43.200000 312.720000 ;
  END
 END po3[289]
 PIN po3[290]
  DIRECTION INPUT ;
  USE SIGNAL ;
  PORT
   LAYER M4 ;
   RECT 43.008000 313.260000 43.200000 313.284000 ;
  END
 END po3[290]
 PIN po3[291]
  DIRECTION INPUT ;
  USE SIGNAL ;
  PORT
   LAYER M6 ;
   RECT 43.008000 313.712000 43.200000 313.744000 ;
  END
 END po3[291]
 PIN po3[292]
  DIRECTION INPUT ;
  USE SIGNAL ;
  PORT
   LAYER M4 ;
   RECT 43.008000 313.596000 43.200000 313.620000 ;
  END
 END po3[292]
 PIN po3[293]
  DIRECTION INPUT ;
  USE SIGNAL ;
  PORT
   LAYER M6 ;
   RECT 43.008000 313.904000 43.200000 313.936000 ;
  END
 END po3[293]
 PIN po3[294]
  DIRECTION INPUT ;
  USE SIGNAL ;
  PORT
   LAYER M4 ;
   RECT 43.008000 313.932000 43.200000 313.956000 ;
  END
 END po3[294]
 PIN po3[295]
  DIRECTION INPUT ;
  USE SIGNAL ;
  PORT
   LAYER M6 ;
   RECT 43.008000 314.224000 43.200000 314.256000 ;
  END
 END po3[295]
 PIN po3[296]
  DIRECTION INPUT ;
  USE SIGNAL ;
  PORT
   LAYER M4 ;
   RECT 43.008000 314.268000 43.200000 314.292000 ;
  END
 END po3[296]
 PIN po3[297]
  DIRECTION INPUT ;
  USE SIGNAL ;
  PORT
   LAYER M6 ;
   RECT 43.008000 314.544000 43.200000 314.576000 ;
  END
 END po3[297]
 PIN po3[298]
  DIRECTION INPUT ;
  USE SIGNAL ;
  PORT
   LAYER M4 ;
   RECT 43.008000 314.604000 43.200000 314.628000 ;
  END
 END po3[298]
 PIN po3[299]
  DIRECTION INPUT ;
  USE SIGNAL ;
  PORT
   LAYER M6 ;
   RECT 43.008000 314.928000 43.200000 314.960000 ;
  END
 END po3[299]
 PIN po3[300]
  DIRECTION INPUT ;
  USE SIGNAL ;
  PORT
   LAYER M4 ;
   RECT 43.008000 314.940000 43.200000 314.964000 ;
  END
 END po3[300]
 PIN po3[301]
  DIRECTION INPUT ;
  USE SIGNAL ;
  PORT
   LAYER M6 ;
   RECT 43.008000 315.248000 43.200000 315.280000 ;
  END
 END po3[301]
 PIN po3[302]
  DIRECTION INPUT ;
  USE SIGNAL ;
  PORT
   LAYER M4 ;
   RECT 43.008000 315.276000 43.200000 315.300000 ;
  END
 END po3[302]
 PIN po3[303]
  DIRECTION INPUT ;
  USE SIGNAL ;
  PORT
   LAYER M6 ;
   RECT 43.008000 315.568000 43.200000 315.600000 ;
  END
 END po3[303]
 PIN po3[304]
  DIRECTION INPUT ;
  USE SIGNAL ;
  PORT
   LAYER M4 ;
   RECT 43.008000 315.612000 43.200000 315.636000 ;
  END
 END po3[304]
 PIN po3[305]
  DIRECTION INPUT ;
  USE SIGNAL ;
  PORT
   LAYER M6 ;
   RECT 43.008000 315.888000 43.200000 315.920000 ;
  END
 END po3[305]
 PIN po3[306]
  DIRECTION INPUT ;
  USE SIGNAL ;
  PORT
   LAYER M4 ;
   RECT 43.008000 315.948000 43.200000 315.972000 ;
  END
 END po3[306]
 PIN po3[307]
  DIRECTION INPUT ;
  USE SIGNAL ;
  PORT
   LAYER M6 ;
   RECT 43.008000 316.208000 43.200000 316.240000 ;
  END
 END po3[307]
 PIN po3[308]
  DIRECTION INPUT ;
  USE SIGNAL ;
  PORT
   LAYER M4 ;
   RECT 43.008000 316.284000 43.200000 316.308000 ;
  END
 END po3[308]
 PIN po3[309]
  DIRECTION INPUT ;
  USE SIGNAL ;
  PORT
   LAYER M6 ;
   RECT 43.008000 316.592000 43.200000 316.624000 ;
  END
 END po3[309]
 PIN po3[310]
  DIRECTION INPUT ;
  USE SIGNAL ;
  PORT
   LAYER M4 ;
   RECT 43.008000 316.572000 43.200000 316.596000 ;
  END
 END po3[310]
 PIN po3[311]
  DIRECTION INPUT ;
  USE SIGNAL ;
  PORT
   LAYER M6 ;
   RECT 43.008000 316.848000 43.200000 316.880000 ;
  END
 END po3[311]
 PIN po3[312]
  DIRECTION INPUT ;
  USE SIGNAL ;
  PORT
   LAYER M4 ;
   RECT 43.008000 316.908000 43.200000 316.932000 ;
  END
 END po3[312]
 PIN po3[313]
  DIRECTION INPUT ;
  USE SIGNAL ;
  PORT
   LAYER M6 ;
   RECT 43.008000 316.912000 43.200000 316.944000 ;
  END
 END po3[313]
 PIN po3[314]
  DIRECTION INPUT ;
  USE SIGNAL ;
  PORT
   LAYER M4 ;
   RECT 43.008000 317.244000 43.200000 317.268000 ;
  END
 END po3[314]
 PIN po3[315]
  DIRECTION INPUT ;
  USE SIGNAL ;
  PORT
   LAYER M6 ;
   RECT 43.008000 316.976000 43.200000 317.008000 ;
  END
 END po3[315]
 PIN po3[316]
  DIRECTION INPUT ;
  USE SIGNAL ;
  PORT
   LAYER M4 ;
   RECT 43.008000 317.580000 43.200000 317.604000 ;
  END
 END po3[316]
 PIN po3[317]
  DIRECTION INPUT ;
  USE SIGNAL ;
  PORT
   LAYER M6 ;
   RECT 43.008000 318.000000 43.200000 318.032000 ;
  END
 END po3[317]
 PIN po3[318]
  DIRECTION INPUT ;
  USE SIGNAL ;
  PORT
   LAYER M4 ;
   RECT 43.008000 317.916000 43.200000 317.940000 ;
  END
 END po3[318]
 PIN po3[319]
  DIRECTION INPUT ;
  USE SIGNAL ;
  PORT
   LAYER M6 ;
   RECT 43.008000 318.256000 43.200000 318.288000 ;
  END
 END po3[319]
 PIN po3[320]
  DIRECTION INPUT ;
  USE SIGNAL ;
  PORT
   LAYER M4 ;
   RECT 43.008000 318.252000 43.200000 318.276000 ;
  END
 END po3[320]
 PIN po3[321]
  DIRECTION INPUT ;
  USE SIGNAL ;
  PORT
   LAYER M6 ;
   RECT 43.008000 318.576000 43.200000 318.608000 ;
  END
 END po3[321]
 PIN po3[322]
  DIRECTION INPUT ;
  USE SIGNAL ;
  PORT
   LAYER M4 ;
   RECT 43.008000 318.588000 43.200000 318.612000 ;
  END
 END po3[322]
 PIN po3[323]
  DIRECTION INPUT ;
  USE SIGNAL ;
  PORT
   LAYER M6 ;
   RECT 43.008000 318.896000 43.200000 318.928000 ;
  END
 END po3[323]
 PIN po3[324]
  DIRECTION INPUT ;
  USE SIGNAL ;
  PORT
   LAYER M4 ;
   RECT 43.008000 318.924000 43.200000 318.948000 ;
  END
 END po3[324]
 PIN po3[325]
  DIRECTION INPUT ;
  USE SIGNAL ;
  PORT
   LAYER M6 ;
   RECT 43.008000 319.216000 43.200000 319.248000 ;
  END
 END po3[325]
 PIN po3[326]
  DIRECTION INPUT ;
  USE SIGNAL ;
  PORT
   LAYER M4 ;
   RECT 43.008000 319.260000 43.200000 319.284000 ;
  END
 END po3[326]
 PIN po3[327]
  DIRECTION INPUT ;
  USE SIGNAL ;
  PORT
   LAYER M6 ;
   RECT 43.008000 319.600000 43.200000 319.632000 ;
  END
 END po3[327]
 PIN pi3[0]
  DIRECTION OUTPUT ;
  USE SIGNAL ;
  PORT
   LAYER M4 ;
   RECT 43.008000 593.196000 43.200000 593.220000 ;
  END
 END pi3[0]
 PIN pi3[1]
  DIRECTION OUTPUT ;
  USE SIGNAL ;
  PORT
   LAYER M6 ;
   RECT 43.008000 592.560000 43.200000 592.592000 ;
  END
 END pi3[1]
 PIN pi3[2]
  DIRECTION OUTPUT ;
  USE SIGNAL ;
  PORT
   LAYER M4 ;
   RECT 43.008000 593.532000 43.200000 593.556000 ;
  END
 END pi3[2]
 PIN pi3[3]
  DIRECTION OUTPUT ;
  USE SIGNAL ;
  PORT
   LAYER M6 ;
   RECT 43.008000 592.816000 43.200000 592.848000 ;
  END
 END pi3[3]
 PIN pi3[4]
  DIRECTION OUTPUT ;
  USE SIGNAL ;
  PORT
   LAYER M4 ;
   RECT 43.008000 593.820000 43.200000 593.844000 ;
  END
 END pi3[4]
 PIN pi3[5]
  DIRECTION OUTPUT ;
  USE SIGNAL ;
  PORT
   LAYER M6 ;
   RECT 43.008000 593.072000 43.200000 593.104000 ;
  END
 END pi3[5]
 PIN pi3[6]
  DIRECTION OUTPUT ;
  USE SIGNAL ;
  PORT
   LAYER M4 ;
   RECT 43.008000 594.156000 43.200000 594.180000 ;
  END
 END pi3[6]
 PIN pi3[7]
  DIRECTION OUTPUT ;
  USE SIGNAL ;
  PORT
   LAYER M6 ;
   RECT 43.008000 593.328000 43.200000 593.360000 ;
  END
 END pi3[7]
 PIN pi3[8]
  DIRECTION OUTPUT ;
  USE SIGNAL ;
  PORT
   LAYER M4 ;
   RECT 43.008000 594.492000 43.200000 594.516000 ;
  END
 END pi3[8]
 PIN pi3[9]
  DIRECTION OUTPUT ;
  USE SIGNAL ;
  PORT
   LAYER M6 ;
   RECT 43.008000 594.544000 43.200000 594.576000 ;
  END
 END pi3[9]
 PIN pi3[10]
  DIRECTION OUTPUT ;
  USE SIGNAL ;
  PORT
   LAYER M4 ;
   RECT 43.008000 594.828000 43.200000 594.852000 ;
  END
 END pi3[10]
 PIN pi3[11]
  DIRECTION OUTPUT ;
  USE SIGNAL ;
  PORT
   LAYER M6 ;
   RECT 43.008000 594.864000 43.200000 594.896000 ;
  END
 END pi3[11]
 PIN pi3[12]
  DIRECTION OUTPUT ;
  USE SIGNAL ;
  PORT
   LAYER M4 ;
   RECT 43.008000 595.164000 43.200000 595.188000 ;
  END
 END pi3[12]
 PIN pi3[13]
  DIRECTION OUTPUT ;
  USE SIGNAL ;
  PORT
   LAYER M6 ;
   RECT 43.008000 595.120000 43.200000 595.152000 ;
  END
 END pi3[13]
 PIN pi3[14]
  DIRECTION OUTPUT ;
  USE SIGNAL ;
  PORT
   LAYER M4 ;
   RECT 43.008000 595.500000 43.200000 595.524000 ;
  END
 END pi3[14]
 PIN pi3[15]
  DIRECTION OUTPUT ;
  USE SIGNAL ;
  PORT
   LAYER M6 ;
   RECT 43.008000 595.376000 43.200000 595.408000 ;
  END
 END pi3[15]
 PIN pi3[16]
  DIRECTION OUTPUT ;
  USE SIGNAL ;
  PORT
   LAYER M4 ;
   RECT 43.008000 595.836000 43.200000 595.860000 ;
  END
 END pi3[16]
 PIN pi3[17]
  DIRECTION OUTPUT ;
  USE SIGNAL ;
  PORT
   LAYER M6 ;
   RECT 43.008000 595.632000 43.200000 595.664000 ;
  END
 END pi3[17]
 PIN pi3[18]
  DIRECTION OUTPUT ;
  USE SIGNAL ;
  PORT
   LAYER M4 ;
   RECT 43.008000 596.172000 43.200000 596.196000 ;
  END
 END pi3[18]
 PIN pi3[19]
  DIRECTION OUTPUT ;
  USE SIGNAL ;
  PORT
   LAYER M6 ;
   RECT 43.008000 595.888000 43.200000 595.920000 ;
  END
 END pi3[19]
 PIN pi3[20]
  DIRECTION OUTPUT ;
  USE SIGNAL ;
  PORT
   LAYER M4 ;
   RECT 43.008000 596.508000 43.200000 596.532000 ;
  END
 END pi3[20]
 PIN pi3[21]
  DIRECTION OUTPUT ;
  USE SIGNAL ;
  PORT
   LAYER M6 ;
   RECT 43.008000 596.144000 43.200000 596.176000 ;
  END
 END pi3[21]
 PIN pi3[22]
  DIRECTION OUTPUT ;
  USE SIGNAL ;
  PORT
   LAYER M4 ;
   RECT 43.008000 596.844000 43.200000 596.868000 ;
  END
 END pi3[22]
 PIN pi3[23]
  DIRECTION OUTPUT ;
  USE SIGNAL ;
  PORT
   LAYER M6 ;
   RECT 43.008000 596.400000 43.200000 596.432000 ;
  END
 END pi3[23]
 PIN pi3[24]
  DIRECTION OUTPUT ;
  USE SIGNAL ;
  PORT
   LAYER M4 ;
   RECT 43.008000 597.180000 43.200000 597.204000 ;
  END
 END pi3[24]
 PIN pi3[25]
  DIRECTION OUTPUT ;
  USE SIGNAL ;
  PORT
   LAYER M6 ;
   RECT 43.008000 596.656000 43.200000 596.688000 ;
  END
 END pi3[25]
 PIN pi3[26]
  DIRECTION OUTPUT ;
  USE SIGNAL ;
  PORT
   LAYER M4 ;
   RECT 43.008000 597.516000 43.200000 597.540000 ;
  END
 END pi3[26]
 PIN pi3[27]
  DIRECTION OUTPUT ;
  USE SIGNAL ;
  PORT
   LAYER M6 ;
   RECT 43.008000 596.912000 43.200000 596.944000 ;
  END
 END pi3[27]
 PIN pi3[28]
  DIRECTION OUTPUT ;
  USE SIGNAL ;
  PORT
   LAYER M4 ;
   RECT 43.008000 597.852000 43.200000 597.876000 ;
  END
 END pi3[28]
 PIN pi3[29]
  DIRECTION OUTPUT ;
  USE SIGNAL ;
  PORT
   LAYER M6 ;
   RECT 43.008000 597.168000 43.200000 597.200000 ;
  END
 END pi3[29]
 PIN pi3[30]
  DIRECTION OUTPUT ;
  USE SIGNAL ;
  PORT
   LAYER M4 ;
   RECT 43.008000 598.188000 43.200000 598.212000 ;
  END
 END pi3[30]
 PIN pi3[31]
  DIRECTION OUTPUT ;
  USE SIGNAL ;
  PORT
   LAYER M6 ;
   RECT 43.008000 597.488000 43.200000 597.520000 ;
  END
 END pi3[31]
 PIN pi3[32]
  DIRECTION OUTPUT ;
  USE SIGNAL ;
  PORT
   LAYER M4 ;
   RECT 43.008000 598.524000 43.200000 598.548000 ;
  END
 END pi3[32]
 PIN pi3[33]
  DIRECTION OUTPUT ;
  USE SIGNAL ;
  PORT
   LAYER M6 ;
   RECT 43.008000 597.744000 43.200000 597.776000 ;
  END
 END pi3[33]
 PIN pi3[34]
  DIRECTION OUTPUT ;
  USE SIGNAL ;
  PORT
   LAYER M4 ;
   RECT 43.008000 598.860000 43.200000 598.884000 ;
  END
 END pi3[34]
 PIN pi3[35]
  DIRECTION OUTPUT ;
  USE SIGNAL ;
  PORT
   LAYER M6 ;
   RECT 43.008000 598.960000 43.200000 598.992000 ;
  END
 END pi3[35]
 PIN pi3[36]
  DIRECTION OUTPUT ;
  USE SIGNAL ;
  PORT
   LAYER M4 ;
   RECT 43.008000 599.196000 43.200000 599.220000 ;
  END
 END pi3[36]
 PIN pi3[37]
  DIRECTION OUTPUT ;
  USE SIGNAL ;
  PORT
   LAYER M6 ;
   RECT 43.008000 599.216000 43.200000 599.248000 ;
  END
 END pi3[37]
 PIN pi3[38]
  DIRECTION OUTPUT ;
  USE SIGNAL ;
  PORT
   LAYER M4 ;
   RECT 43.008000 599.532000 43.200000 599.556000 ;
  END
 END pi3[38]
 PIN pi3[39]
  DIRECTION OUTPUT ;
  USE SIGNAL ;
  PORT
   LAYER M6 ;
   RECT 43.008000 599.472000 43.200000 599.504000 ;
  END
 END pi3[39]
 PIN pi3[40]
  DIRECTION OUTPUT ;
  USE SIGNAL ;
  PORT
   LAYER M4 ;
   RECT 43.008000 599.820000 43.200000 599.844000 ;
  END
 END pi3[40]
 PIN pi3[41]
  DIRECTION OUTPUT ;
  USE SIGNAL ;
  PORT
   LAYER M6 ;
   RECT 43.008000 599.728000 43.200000 599.760000 ;
  END
 END pi3[41]
 PIN pi3[42]
  DIRECTION OUTPUT ;
  USE SIGNAL ;
  PORT
   LAYER M4 ;
   RECT 43.008000 600.156000 43.200000 600.180000 ;
  END
 END pi3[42]
 PIN pi3[43]
  DIRECTION OUTPUT ;
  USE SIGNAL ;
  PORT
   LAYER M6 ;
   RECT 43.008000 599.984000 43.200000 600.016000 ;
  END
 END pi3[43]
 PIN pi3[44]
  DIRECTION OUTPUT ;
  USE SIGNAL ;
  PORT
   LAYER M4 ;
   RECT 43.008000 600.492000 43.200000 600.516000 ;
  END
 END pi3[44]
 PIN pi3[45]
  DIRECTION OUTPUT ;
  USE SIGNAL ;
  PORT
   LAYER M6 ;
   RECT 43.008000 600.240000 43.200000 600.272000 ;
  END
 END pi3[45]
 PIN pi3[46]
  DIRECTION OUTPUT ;
  USE SIGNAL ;
  PORT
   LAYER M4 ;
   RECT 43.008000 600.828000 43.200000 600.852000 ;
  END
 END pi3[46]
 PIN pi3[47]
  DIRECTION OUTPUT ;
  USE SIGNAL ;
  PORT
   LAYER M6 ;
   RECT 43.008000 600.496000 43.200000 600.528000 ;
  END
 END pi3[47]
 PIN pi3[48]
  DIRECTION OUTPUT ;
  USE SIGNAL ;
  PORT
   LAYER M4 ;
   RECT 43.008000 601.164000 43.200000 601.188000 ;
  END
 END pi3[48]
 PIN pi3[49]
  DIRECTION OUTPUT ;
  USE SIGNAL ;
  PORT
   LAYER M6 ;
   RECT 43.008000 600.752000 43.200000 600.784000 ;
  END
 END pi3[49]
 PIN pi3[50]
  DIRECTION OUTPUT ;
  USE SIGNAL ;
  PORT
   LAYER M4 ;
   RECT 43.008000 601.500000 43.200000 601.524000 ;
  END
 END pi3[50]
 PIN pi3[51]
  DIRECTION OUTPUT ;
  USE SIGNAL ;
  PORT
   LAYER M6 ;
   RECT 43.008000 601.072000 43.200000 601.104000 ;
  END
 END pi3[51]
 PIN pi3[52]
  DIRECTION OUTPUT ;
  USE SIGNAL ;
  PORT
   LAYER M4 ;
   RECT 43.008000 601.836000 43.200000 601.860000 ;
  END
 END pi3[52]
 PIN pi3[53]
  DIRECTION OUTPUT ;
  USE SIGNAL ;
  PORT
   LAYER M6 ;
   RECT 43.008000 601.328000 43.200000 601.360000 ;
  END
 END pi3[53]
 PIN pi3[54]
  DIRECTION OUTPUT ;
  USE SIGNAL ;
  PORT
   LAYER M4 ;
   RECT 43.008000 602.172000 43.200000 602.196000 ;
  END
 END pi3[54]
 PIN pi3[55]
  DIRECTION OUTPUT ;
  USE SIGNAL ;
  PORT
   LAYER M6 ;
   RECT 43.008000 601.584000 43.200000 601.616000 ;
  END
 END pi3[55]
 PIN pi3[56]
  DIRECTION OUTPUT ;
  USE SIGNAL ;
  PORT
   LAYER M4 ;
   RECT 43.008000 602.508000 43.200000 602.532000 ;
  END
 END pi3[56]
 PIN pi3[57]
  DIRECTION OUTPUT ;
  USE SIGNAL ;
  PORT
   LAYER M6 ;
   RECT 43.008000 601.840000 43.200000 601.872000 ;
  END
 END pi3[57]
 PIN pi3[58]
  DIRECTION OUTPUT ;
  USE SIGNAL ;
  PORT
   LAYER M4 ;
   RECT 43.008000 602.844000 43.200000 602.868000 ;
  END
 END pi3[58]
 PIN pi3[59]
  DIRECTION OUTPUT ;
  USE SIGNAL ;
  PORT
   LAYER M6 ;
   RECT 43.008000 602.096000 43.200000 602.128000 ;
  END
 END pi3[59]
 PIN pi3[60]
  DIRECTION OUTPUT ;
  USE SIGNAL ;
  PORT
   LAYER M4 ;
   RECT 43.008000 603.180000 43.200000 603.204000 ;
  END
 END pi3[60]
 PIN pi3[61]
  DIRECTION OUTPUT ;
  USE SIGNAL ;
  PORT
   LAYER M6 ;
   RECT 43.008000 603.312000 43.200000 603.344000 ;
  END
 END pi3[61]
 PIN pi3[62]
  DIRECTION OUTPUT ;
  USE SIGNAL ;
  PORT
   LAYER M4 ;
   RECT 43.008000 603.516000 43.200000 603.540000 ;
  END
 END pi3[62]
 PIN pi3[63]
  DIRECTION OUTPUT ;
  USE SIGNAL ;
  PORT
   LAYER M6 ;
   RECT 43.008000 603.568000 43.200000 603.600000 ;
  END
 END pi3[63]
 PIN pi3[64]
  DIRECTION OUTPUT ;
  USE SIGNAL ;
  PORT
   LAYER M4 ;
   RECT 43.008000 603.852000 43.200000 603.876000 ;
  END
 END pi3[64]
 PIN pi3[65]
  DIRECTION OUTPUT ;
  USE SIGNAL ;
  PORT
   LAYER M6 ;
   RECT 43.008000 603.824000 43.200000 603.856000 ;
  END
 END pi3[65]
 PIN pi3[66]
  DIRECTION OUTPUT ;
  USE SIGNAL ;
  PORT
   LAYER M4 ;
   RECT 43.008000 604.188000 43.200000 604.212000 ;
  END
 END pi3[66]
 PIN pi3[67]
  DIRECTION OUTPUT ;
  USE SIGNAL ;
  PORT
   LAYER M6 ;
   RECT 43.008000 604.080000 43.200000 604.112000 ;
  END
 END pi3[67]
 PIN pi3[68]
  DIRECTION OUTPUT ;
  USE SIGNAL ;
  PORT
   LAYER M4 ;
   RECT 43.008000 604.524000 43.200000 604.548000 ;
  END
 END pi3[68]
 PIN pi3[69]
  DIRECTION OUTPUT ;
  USE SIGNAL ;
  PORT
   LAYER M6 ;
   RECT 43.008000 604.336000 43.200000 604.368000 ;
  END
 END pi3[69]
 PIN pi3[70]
  DIRECTION OUTPUT ;
  USE SIGNAL ;
  PORT
   LAYER M4 ;
   RECT 43.008000 604.860000 43.200000 604.884000 ;
  END
 END pi3[70]
 PIN pi3[71]
  DIRECTION OUTPUT ;
  USE SIGNAL ;
  PORT
   LAYER M6 ;
   RECT 43.008000 604.592000 43.200000 604.624000 ;
  END
 END pi3[71]
 PIN pi3[72]
  DIRECTION OUTPUT ;
  USE SIGNAL ;
  PORT
   LAYER M4 ;
   RECT 43.008000 605.196000 43.200000 605.220000 ;
  END
 END pi3[72]
 PIN pi3[73]
  DIRECTION OUTPUT ;
  USE SIGNAL ;
  PORT
   LAYER M6 ;
   RECT 43.008000 604.912000 43.200000 604.944000 ;
  END
 END pi3[73]
 PIN pi3[74]
  DIRECTION OUTPUT ;
  USE SIGNAL ;
  PORT
   LAYER M4 ;
   RECT 43.008000 605.532000 43.200000 605.556000 ;
  END
 END pi3[74]
 PIN pi3[75]
  DIRECTION OUTPUT ;
  USE SIGNAL ;
  PORT
   LAYER M6 ;
   RECT 43.008000 605.168000 43.200000 605.200000 ;
  END
 END pi3[75]
 PIN pi3[76]
  DIRECTION OUTPUT ;
  USE SIGNAL ;
  PORT
   LAYER M4 ;
   RECT 43.008000 605.868000 43.200000 605.892000 ;
  END
 END pi3[76]
 PIN pi3[77]
  DIRECTION OUTPUT ;
  USE SIGNAL ;
  PORT
   LAYER M6 ;
   RECT 43.008000 605.424000 43.200000 605.456000 ;
  END
 END pi3[77]
 PIN pi3[78]
  DIRECTION OUTPUT ;
  USE SIGNAL ;
  PORT
   LAYER M4 ;
   RECT 43.008000 606.156000 43.200000 606.180000 ;
  END
 END pi3[78]
 PIN pi3[79]
  DIRECTION OUTPUT ;
  USE SIGNAL ;
  PORT
   LAYER M6 ;
   RECT 43.008000 605.680000 43.200000 605.712000 ;
  END
 END pi3[79]
 PIN pi3[80]
  DIRECTION OUTPUT ;
  USE SIGNAL ;
  PORT
   LAYER M4 ;
   RECT 43.008000 606.492000 43.200000 606.516000 ;
  END
 END pi3[80]
 PIN pi3[81]
  DIRECTION OUTPUT ;
  USE SIGNAL ;
  PORT
   LAYER M6 ;
   RECT 43.008000 605.936000 43.200000 605.968000 ;
  END
 END pi3[81]
 PIN pi3[82]
  DIRECTION OUTPUT ;
  USE SIGNAL ;
  PORT
   LAYER M4 ;
   RECT 43.008000 606.828000 43.200000 606.852000 ;
  END
 END pi3[82]
 PIN pi3[83]
  DIRECTION OUTPUT ;
  USE SIGNAL ;
  PORT
   LAYER M6 ;
   RECT 43.008000 606.192000 43.200000 606.224000 ;
  END
 END pi3[83]
 PIN pi3[84]
  DIRECTION OUTPUT ;
  USE SIGNAL ;
  PORT
   LAYER M4 ;
   RECT 43.008000 607.164000 43.200000 607.188000 ;
  END
 END pi3[84]
 PIN pi3[85]
  DIRECTION OUTPUT ;
  USE SIGNAL ;
  PORT
   LAYER M6 ;
   RECT 43.008000 606.448000 43.200000 606.480000 ;
  END
 END pi3[85]
 PIN pi3[86]
  DIRECTION OUTPUT ;
  USE SIGNAL ;
  PORT
   LAYER M4 ;
   RECT 43.008000 607.500000 43.200000 607.524000 ;
  END
 END pi3[86]
 PIN pi3[87]
  DIRECTION OUTPUT ;
  USE SIGNAL ;
  PORT
   LAYER M6 ;
   RECT 43.008000 607.664000 43.200000 607.696000 ;
  END
 END pi3[87]
 PIN pi3[88]
  DIRECTION OUTPUT ;
  USE SIGNAL ;
  PORT
   LAYER M4 ;
   RECT 43.008000 607.836000 43.200000 607.860000 ;
  END
 END pi3[88]
 PIN pi3[89]
  DIRECTION OUTPUT ;
  USE SIGNAL ;
  PORT
   LAYER M6 ;
   RECT 43.008000 607.920000 43.200000 607.952000 ;
  END
 END pi3[89]
 PIN pi3[90]
  DIRECTION OUTPUT ;
  USE SIGNAL ;
  PORT
   LAYER M4 ;
   RECT 43.008000 608.172000 43.200000 608.196000 ;
  END
 END pi3[90]
 PIN pi3[91]
  DIRECTION OUTPUT ;
  USE SIGNAL ;
  PORT
   LAYER M6 ;
   RECT 43.008000 608.176000 43.200000 608.208000 ;
  END
 END pi3[91]
 PIN pi3[92]
  DIRECTION OUTPUT ;
  USE SIGNAL ;
  PORT
   LAYER M4 ;
   RECT 43.008000 608.508000 43.200000 608.532000 ;
  END
 END pi3[92]
 PIN pi3[93]
  DIRECTION OUTPUT ;
  USE SIGNAL ;
  PORT
   LAYER M6 ;
   RECT 43.008000 608.496000 43.200000 608.528000 ;
  END
 END pi3[93]
 PIN pi3[94]
  DIRECTION OUTPUT ;
  USE SIGNAL ;
  PORT
   LAYER M4 ;
   RECT 43.008000 608.844000 43.200000 608.868000 ;
  END
 END pi3[94]
 PIN pi3[95]
  DIRECTION OUTPUT ;
  USE SIGNAL ;
  PORT
   LAYER M6 ;
   RECT 43.008000 608.752000 43.200000 608.784000 ;
  END
 END pi3[95]
 PIN pi3[96]
  DIRECTION OUTPUT ;
  USE SIGNAL ;
  PORT
   LAYER M4 ;
   RECT 43.008000 609.180000 43.200000 609.204000 ;
  END
 END pi3[96]
 PIN pi3[97]
  DIRECTION OUTPUT ;
  USE SIGNAL ;
  PORT
   LAYER M6 ;
   RECT 43.008000 609.008000 43.200000 609.040000 ;
  END
 END pi3[97]
 PIN pi3[98]
  DIRECTION OUTPUT ;
  USE SIGNAL ;
  PORT
   LAYER M4 ;
   RECT 43.008000 609.516000 43.200000 609.540000 ;
  END
 END pi3[98]
 PIN pi3[99]
  DIRECTION OUTPUT ;
  USE SIGNAL ;
  PORT
   LAYER M6 ;
   RECT 43.008000 609.264000 43.200000 609.296000 ;
  END
 END pi3[99]
 PIN pi3[100]
  DIRECTION OUTPUT ;
  USE SIGNAL ;
  PORT
   LAYER M4 ;
   RECT 43.008000 609.852000 43.200000 609.876000 ;
  END
 END pi3[100]
 PIN pi3[101]
  DIRECTION OUTPUT ;
  USE SIGNAL ;
  PORT
   LAYER M6 ;
   RECT 43.008000 609.520000 43.200000 609.552000 ;
  END
 END pi3[101]
 PIN pi3[102]
  DIRECTION OUTPUT ;
  USE SIGNAL ;
  PORT
   LAYER M4 ;
   RECT 43.008000 610.188000 43.200000 610.212000 ;
  END
 END pi3[102]
 PIN pi3[103]
  DIRECTION OUTPUT ;
  USE SIGNAL ;
  PORT
   LAYER M6 ;
   RECT 43.008000 609.776000 43.200000 609.808000 ;
  END
 END pi3[103]
 PIN pi3[104]
  DIRECTION OUTPUT ;
  USE SIGNAL ;
  PORT
   LAYER M4 ;
   RECT 43.008000 610.524000 43.200000 610.548000 ;
  END
 END pi3[104]
 PIN pi3[105]
  DIRECTION OUTPUT ;
  USE SIGNAL ;
  PORT
   LAYER M6 ;
   RECT 43.008000 610.032000 43.200000 610.064000 ;
  END
 END pi3[105]
 PIN pi3[106]
  DIRECTION OUTPUT ;
  USE SIGNAL ;
  PORT
   LAYER M4 ;
   RECT 43.008000 610.860000 43.200000 610.884000 ;
  END
 END pi3[106]
 PIN pi3[107]
  DIRECTION OUTPUT ;
  USE SIGNAL ;
  PORT
   LAYER M6 ;
   RECT 43.008000 610.288000 43.200000 610.320000 ;
  END
 END pi3[107]
 PIN pi3[108]
  DIRECTION OUTPUT ;
  USE SIGNAL ;
  PORT
   LAYER M4 ;
   RECT 43.008000 611.196000 43.200000 611.220000 ;
  END
 END pi3[108]
 PIN pi3[109]
  DIRECTION OUTPUT ;
  USE SIGNAL ;
  PORT
   LAYER M6 ;
   RECT 43.008000 610.544000 43.200000 610.576000 ;
  END
 END pi3[109]
 PIN pi3[110]
  DIRECTION OUTPUT ;
  USE SIGNAL ;
  PORT
   LAYER M4 ;
   RECT 43.008000 611.532000 43.200000 611.556000 ;
  END
 END pi3[110]
 PIN pi3[111]
  DIRECTION OUTPUT ;
  USE SIGNAL ;
  PORT
   LAYER M6 ;
   RECT 43.008000 611.760000 43.200000 611.792000 ;
  END
 END pi3[111]
 PIN pi3[112]
  DIRECTION OUTPUT ;
  USE SIGNAL ;
  PORT
   LAYER M4 ;
   RECT 43.008000 611.868000 43.200000 611.892000 ;
  END
 END pi3[112]
 PIN pi3[113]
  DIRECTION OUTPUT ;
  USE SIGNAL ;
  PORT
   LAYER M6 ;
   RECT 43.008000 612.080000 43.200000 612.112000 ;
  END
 END pi3[113]
 PIN pi3[114]
  DIRECTION OUTPUT ;
  USE SIGNAL ;
  PORT
   LAYER M4 ;
   RECT 43.008000 612.204000 43.200000 612.228000 ;
  END
 END pi3[114]
 PIN pi3[115]
  DIRECTION OUTPUT ;
  USE SIGNAL ;
  PORT
   LAYER M6 ;
   RECT 43.008000 612.336000 43.200000 612.368000 ;
  END
 END pi3[115]
 PIN pi3[116]
  DIRECTION OUTPUT ;
  USE SIGNAL ;
  PORT
   LAYER M4 ;
   RECT 43.008000 612.492000 43.200000 612.516000 ;
  END
 END pi3[116]
 PIN pi3[117]
  DIRECTION OUTPUT ;
  USE SIGNAL ;
  PORT
   LAYER M6 ;
   RECT 43.008000 612.592000 43.200000 612.624000 ;
  END
 END pi3[117]
 PIN pi3[118]
  DIRECTION OUTPUT ;
  USE SIGNAL ;
  PORT
   LAYER M4 ;
   RECT 43.008000 612.828000 43.200000 612.852000 ;
  END
 END pi3[118]
 PIN pi3[119]
  DIRECTION OUTPUT ;
  USE SIGNAL ;
  PORT
   LAYER M6 ;
   RECT 43.008000 612.848000 43.200000 612.880000 ;
  END
 END pi3[119]
 PIN pi3[120]
  DIRECTION OUTPUT ;
  USE SIGNAL ;
  PORT
   LAYER M4 ;
   RECT 43.008000 613.164000 43.200000 613.188000 ;
  END
 END pi3[120]
 PIN pi3[121]
  DIRECTION OUTPUT ;
  USE SIGNAL ;
  PORT
   LAYER M6 ;
   RECT 43.008000 613.104000 43.200000 613.136000 ;
  END
 END pi3[121]
 PIN pi3[122]
  DIRECTION OUTPUT ;
  USE SIGNAL ;
  PORT
   LAYER M4 ;
   RECT 43.008000 613.500000 43.200000 613.524000 ;
  END
 END pi3[122]
 PIN pi3[123]
  DIRECTION OUTPUT ;
  USE SIGNAL ;
  PORT
   LAYER M6 ;
   RECT 43.008000 613.360000 43.200000 613.392000 ;
  END
 END pi3[123]
 PIN pi3[124]
  DIRECTION OUTPUT ;
  USE SIGNAL ;
  PORT
   LAYER M4 ;
   RECT 43.008000 613.836000 43.200000 613.860000 ;
  END
 END pi3[124]
 PIN pi3[125]
  DIRECTION OUTPUT ;
  USE SIGNAL ;
  PORT
   LAYER M6 ;
   RECT 43.008000 613.616000 43.200000 613.648000 ;
  END
 END pi3[125]
 PIN pi3[126]
  DIRECTION OUTPUT ;
  USE SIGNAL ;
  PORT
   LAYER M4 ;
   RECT 43.008000 614.172000 43.200000 614.196000 ;
  END
 END pi3[126]
 PIN pi3[127]
  DIRECTION OUTPUT ;
  USE SIGNAL ;
  PORT
   LAYER M6 ;
   RECT 43.008000 613.872000 43.200000 613.904000 ;
  END
 END pi3[127]
 PIN pi3[128]
  DIRECTION OUTPUT ;
  USE SIGNAL ;
  PORT
   LAYER M4 ;
   RECT 43.008000 614.508000 43.200000 614.532000 ;
  END
 END pi3[128]
 PIN pi3[129]
  DIRECTION OUTPUT ;
  USE SIGNAL ;
  PORT
   LAYER M6 ;
   RECT 43.008000 614.128000 43.200000 614.160000 ;
  END
 END pi3[129]
 PIN pi3[130]
  DIRECTION OUTPUT ;
  USE SIGNAL ;
  PORT
   LAYER M4 ;
   RECT 43.008000 614.844000 43.200000 614.868000 ;
  END
 END pi3[130]
 PIN pi3[131]
  DIRECTION OUTPUT ;
  USE SIGNAL ;
  PORT
   LAYER M6 ;
   RECT 43.008000 614.384000 43.200000 614.416000 ;
  END
 END pi3[131]
 PIN pi3[132]
  DIRECTION OUTPUT ;
  USE SIGNAL ;
  PORT
   LAYER M4 ;
   RECT 43.008000 615.180000 43.200000 615.204000 ;
  END
 END pi3[132]
 PIN pi3[133]
  DIRECTION OUTPUT ;
  USE SIGNAL ;
  PORT
   LAYER M6 ;
   RECT 43.008000 614.704000 43.200000 614.736000 ;
  END
 END pi3[133]
 PIN pi3[134]
  DIRECTION OUTPUT ;
  USE SIGNAL ;
  PORT
   LAYER M4 ;
   RECT 43.008000 615.516000 43.200000 615.540000 ;
  END
 END pi3[134]
 PIN pi3[135]
  DIRECTION OUTPUT ;
  USE SIGNAL ;
  PORT
   LAYER M6 ;
   RECT 43.008000 615.024000 43.200000 615.056000 ;
  END
 END pi3[135]
 PIN pi3[136]
  DIRECTION OUTPUT ;
  USE SIGNAL ;
  PORT
   LAYER M4 ;
   RECT 43.008000 615.852000 43.200000 615.876000 ;
  END
 END pi3[136]
 PIN pi3[137]
  DIRECTION OUTPUT ;
  USE SIGNAL ;
  PORT
   LAYER M6 ;
   RECT 43.008000 616.240000 43.200000 616.272000 ;
  END
 END pi3[137]
 PIN pi3[138]
  DIRECTION OUTPUT ;
  USE SIGNAL ;
  PORT
   LAYER M4 ;
   RECT 43.008000 616.188000 43.200000 616.212000 ;
  END
 END pi3[138]
 PIN pi3[139]
  DIRECTION OUTPUT ;
  USE SIGNAL ;
  PORT
   LAYER M6 ;
   RECT 43.008000 616.496000 43.200000 616.528000 ;
  END
 END pi3[139]
 PIN pi3[140]
  DIRECTION OUTPUT ;
  USE SIGNAL ;
  PORT
   LAYER M4 ;
   RECT 43.008000 616.524000 43.200000 616.548000 ;
  END
 END pi3[140]
 PIN pi3[141]
  DIRECTION OUTPUT ;
  USE SIGNAL ;
  PORT
   LAYER M6 ;
   RECT 43.008000 616.752000 43.200000 616.784000 ;
  END
 END pi3[141]
 PIN pi3[142]
  DIRECTION OUTPUT ;
  USE SIGNAL ;
  PORT
   LAYER M4 ;
   RECT 43.008000 616.860000 43.200000 616.884000 ;
  END
 END pi3[142]
 PIN pi3[143]
  DIRECTION OUTPUT ;
  USE SIGNAL ;
  PORT
   LAYER M6 ;
   RECT 43.008000 617.008000 43.200000 617.040000 ;
  END
 END pi3[143]
 PIN pi3[144]
  DIRECTION OUTPUT ;
  USE SIGNAL ;
  PORT
   LAYER M4 ;
   RECT 43.008000 617.196000 43.200000 617.220000 ;
  END
 END pi3[144]
 PIN pi3[145]
  DIRECTION OUTPUT ;
  USE SIGNAL ;
  PORT
   LAYER M6 ;
   RECT 43.008000 617.264000 43.200000 617.296000 ;
  END
 END pi3[145]
 PIN pi3[146]
  DIRECTION OUTPUT ;
  USE SIGNAL ;
  PORT
   LAYER M4 ;
   RECT 43.008000 617.532000 43.200000 617.556000 ;
  END
 END pi3[146]
 PIN pi3[147]
  DIRECTION OUTPUT ;
  USE SIGNAL ;
  PORT
   LAYER M6 ;
   RECT 43.008000 617.520000 43.200000 617.552000 ;
  END
 END pi3[147]
 PIN pi3[148]
  DIRECTION OUTPUT ;
  USE SIGNAL ;
  PORT
   LAYER M4 ;
   RECT 43.008000 617.868000 43.200000 617.892000 ;
  END
 END pi3[148]
 PIN pi3[149]
  DIRECTION OUTPUT ;
  USE SIGNAL ;
  PORT
   LAYER M6 ;
   RECT 43.008000 617.776000 43.200000 617.808000 ;
  END
 END pi3[149]
 PIN pi3[150]
  DIRECTION OUTPUT ;
  USE SIGNAL ;
  PORT
   LAYER M4 ;
   RECT 43.008000 618.204000 43.200000 618.228000 ;
  END
 END pi3[150]
 PIN pi3[151]
  DIRECTION OUTPUT ;
  USE SIGNAL ;
  PORT
   LAYER M6 ;
   RECT 43.008000 618.032000 43.200000 618.064000 ;
  END
 END pi3[151]
 PIN pi3[152]
  DIRECTION OUTPUT ;
  USE SIGNAL ;
  PORT
   LAYER M4 ;
   RECT 43.008000 618.540000 43.200000 618.564000 ;
  END
 END pi3[152]
 PIN pi3[153]
  DIRECTION OUTPUT ;
  USE SIGNAL ;
  PORT
   LAYER M6 ;
   RECT 43.008000 618.288000 43.200000 618.320000 ;
  END
 END pi3[153]
 PIN pi3[154]
  DIRECTION OUTPUT ;
  USE SIGNAL ;
  PORT
   LAYER M4 ;
   RECT 43.008000 618.828000 43.200000 618.852000 ;
  END
 END pi3[154]
 PIN pi3[155]
  DIRECTION OUTPUT ;
  USE SIGNAL ;
  PORT
   LAYER M6 ;
   RECT 43.008000 618.608000 43.200000 618.640000 ;
  END
 END pi3[155]
 PIN pi3[156]
  DIRECTION OUTPUT ;
  USE SIGNAL ;
  PORT
   LAYER M4 ;
   RECT 43.008000 619.164000 43.200000 619.188000 ;
  END
 END pi3[156]
 PIN pi3[157]
  DIRECTION OUTPUT ;
  USE SIGNAL ;
  PORT
   LAYER M6 ;
   RECT 43.008000 618.864000 43.200000 618.896000 ;
  END
 END pi3[157]
 PIN pi3[158]
  DIRECTION OUTPUT ;
  USE SIGNAL ;
  PORT
   LAYER M4 ;
   RECT 43.008000 619.500000 43.200000 619.524000 ;
  END
 END pi3[158]
 PIN pi3[159]
  DIRECTION OUTPUT ;
  USE SIGNAL ;
  PORT
   LAYER M6 ;
   RECT 43.008000 619.120000 43.200000 619.152000 ;
  END
 END pi3[159]
 PIN pi3[160]
  DIRECTION OUTPUT ;
  USE SIGNAL ;
  PORT
   LAYER M4 ;
   RECT 43.008000 619.836000 43.200000 619.860000 ;
  END
 END pi3[160]
 PIN pi3[161]
  DIRECTION OUTPUT ;
  USE SIGNAL ;
  PORT
   LAYER M6 ;
   RECT 43.008000 619.376000 43.200000 619.408000 ;
  END
 END pi3[161]
 PIN pi3[162]
  DIRECTION OUTPUT ;
  USE SIGNAL ;
  PORT
   LAYER M4 ;
   RECT 43.008000 620.172000 43.200000 620.196000 ;
  END
 END pi3[162]
 PIN pi3[163]
  DIRECTION OUTPUT ;
  USE SIGNAL ;
  PORT
   LAYER M6 ;
   RECT 43.008000 620.592000 43.200000 620.624000 ;
  END
 END pi3[163]
 PIN pi3[164]
  DIRECTION OUTPUT ;
  USE SIGNAL ;
  PORT
   LAYER M4 ;
   RECT 43.008000 620.508000 43.200000 620.532000 ;
  END
 END pi3[164]
 PIN pi3[165]
  DIRECTION OUTPUT ;
  USE SIGNAL ;
  PORT
   LAYER M6 ;
   RECT 43.008000 620.848000 43.200000 620.880000 ;
  END
 END pi3[165]
 PIN pi3[166]
  DIRECTION OUTPUT ;
  USE SIGNAL ;
  PORT
   LAYER M4 ;
   RECT 43.008000 620.844000 43.200000 620.868000 ;
  END
 END pi3[166]
 PIN pi3[167]
  DIRECTION OUTPUT ;
  USE SIGNAL ;
  PORT
   LAYER M6 ;
   RECT 43.008000 621.104000 43.200000 621.136000 ;
  END
 END pi3[167]
 PIN pi3[168]
  DIRECTION OUTPUT ;
  USE SIGNAL ;
  PORT
   LAYER M4 ;
   RECT 43.008000 621.180000 43.200000 621.204000 ;
  END
 END pi3[168]
 PIN pi3[169]
  DIRECTION OUTPUT ;
  USE SIGNAL ;
  PORT
   LAYER M6 ;
   RECT 43.008000 621.360000 43.200000 621.392000 ;
  END
 END pi3[169]
 PIN pi3[170]
  DIRECTION OUTPUT ;
  USE SIGNAL ;
  PORT
   LAYER M4 ;
   RECT 43.008000 621.516000 43.200000 621.540000 ;
  END
 END pi3[170]
 PIN pi3[171]
  DIRECTION OUTPUT ;
  USE SIGNAL ;
  PORT
   LAYER M6 ;
   RECT 43.008000 621.616000 43.200000 621.648000 ;
  END
 END pi3[171]
 PIN pi3[172]
  DIRECTION OUTPUT ;
  USE SIGNAL ;
  PORT
   LAYER M4 ;
   RECT 43.008000 621.852000 43.200000 621.876000 ;
  END
 END pi3[172]
 PIN pi3[173]
  DIRECTION OUTPUT ;
  USE SIGNAL ;
  PORT
   LAYER M6 ;
   RECT 43.008000 621.872000 43.200000 621.904000 ;
  END
 END pi3[173]
 PIN pi3[174]
  DIRECTION OUTPUT ;
  USE SIGNAL ;
  PORT
   LAYER M4 ;
   RECT 43.008000 622.188000 43.200000 622.212000 ;
  END
 END pi3[174]
 PIN pi3[175]
  DIRECTION OUTPUT ;
  USE SIGNAL ;
  PORT
   LAYER M6 ;
   RECT 43.008000 622.192000 43.200000 622.224000 ;
  END
 END pi3[175]
 PIN pi3[176]
  DIRECTION OUTPUT ;
  USE SIGNAL ;
  PORT
   LAYER M4 ;
   RECT 43.008000 622.524000 43.200000 622.548000 ;
  END
 END pi3[176]
 PIN pi3[177]
  DIRECTION OUTPUT ;
  USE SIGNAL ;
  PORT
   LAYER M6 ;
   RECT 43.008000 622.448000 43.200000 622.480000 ;
  END
 END pi3[177]
 PIN pi3[178]
  DIRECTION OUTPUT ;
  USE SIGNAL ;
  PORT
   LAYER M4 ;
   RECT 43.008000 622.860000 43.200000 622.884000 ;
  END
 END pi3[178]
 PIN pi3[179]
  DIRECTION OUTPUT ;
  USE SIGNAL ;
  PORT
   LAYER M6 ;
   RECT 43.008000 622.704000 43.200000 622.736000 ;
  END
 END pi3[179]
 PIN pi3[180]
  DIRECTION OUTPUT ;
  USE SIGNAL ;
  PORT
   LAYER M4 ;
   RECT 43.008000 623.196000 43.200000 623.220000 ;
  END
 END pi3[180]
 PIN pi3[181]
  DIRECTION OUTPUT ;
  USE SIGNAL ;
  PORT
   LAYER M6 ;
   RECT 43.008000 622.960000 43.200000 622.992000 ;
  END
 END pi3[181]
 PIN pi3[182]
  DIRECTION OUTPUT ;
  USE SIGNAL ;
  PORT
   LAYER M4 ;
   RECT 43.008000 623.532000 43.200000 623.556000 ;
  END
 END pi3[182]
 PIN pi3[183]
  DIRECTION OUTPUT ;
  USE SIGNAL ;
  PORT
   LAYER M6 ;
   RECT 43.008000 623.216000 43.200000 623.248000 ;
  END
 END pi3[183]
 PIN pi3[184]
  DIRECTION OUTPUT ;
  USE SIGNAL ;
  PORT
   LAYER M4 ;
   RECT 43.008000 623.868000 43.200000 623.892000 ;
  END
 END pi3[184]
 PIN pi3[185]
  DIRECTION OUTPUT ;
  USE SIGNAL ;
  PORT
   LAYER M6 ;
   RECT 43.008000 623.472000 43.200000 623.504000 ;
  END
 END pi3[185]
 PIN pi3[186]
  DIRECTION OUTPUT ;
  USE SIGNAL ;
  PORT
   LAYER M4 ;
   RECT 43.008000 624.204000 43.200000 624.228000 ;
  END
 END pi3[186]
 PIN pi3[187]
  DIRECTION OUTPUT ;
  USE SIGNAL ;
  PORT
   LAYER M6 ;
   RECT 43.008000 623.728000 43.200000 623.760000 ;
  END
 END pi3[187]
 PIN pi3[188]
  DIRECTION OUTPUT ;
  USE SIGNAL ;
  PORT
   LAYER M4 ;
   RECT 43.008000 624.540000 43.200000 624.564000 ;
  END
 END pi3[188]
 PIN pi3[189]
  DIRECTION OUTPUT ;
  USE SIGNAL ;
  PORT
   LAYER M6 ;
   RECT 43.008000 624.944000 43.200000 624.976000 ;
  END
 END pi3[189]
 PIN pi3[190]
  DIRECTION OUTPUT ;
  USE SIGNAL ;
  PORT
   LAYER M4 ;
   RECT 43.008000 624.876000 43.200000 624.900000 ;
  END
 END pi3[190]
 PIN pi3[191]
  DIRECTION OUTPUT ;
  USE SIGNAL ;
  PORT
   LAYER M6 ;
   RECT 43.008000 625.200000 43.200000 625.232000 ;
  END
 END pi3[191]
 PIN pi3[192]
  DIRECTION OUTPUT ;
  USE SIGNAL ;
  PORT
   LAYER M4 ;
   RECT 43.008000 625.164000 43.200000 625.188000 ;
  END
 END pi3[192]
 PIN pi3[193]
  DIRECTION OUTPUT ;
  USE SIGNAL ;
  PORT
   LAYER M6 ;
   RECT 43.008000 625.456000 43.200000 625.488000 ;
  END
 END pi3[193]
 PIN pi3[194]
  DIRECTION OUTPUT ;
  USE SIGNAL ;
  PORT
   LAYER M4 ;
   RECT 43.008000 625.500000 43.200000 625.524000 ;
  END
 END pi3[194]
 PIN pi3[195]
  DIRECTION OUTPUT ;
  USE SIGNAL ;
  PORT
   LAYER M6 ;
   RECT 43.008000 625.776000 43.200000 625.808000 ;
  END
 END pi3[195]
 PIN pi3[196]
  DIRECTION OUTPUT ;
  USE SIGNAL ;
  PORT
   LAYER M4 ;
   RECT 43.008000 625.836000 43.200000 625.860000 ;
  END
 END pi3[196]
 PIN pi3[197]
  DIRECTION OUTPUT ;
  USE SIGNAL ;
  PORT
   LAYER M6 ;
   RECT 43.008000 626.032000 43.200000 626.064000 ;
  END
 END pi3[197]
 PIN pi3[198]
  DIRECTION OUTPUT ;
  USE SIGNAL ;
  PORT
   LAYER M4 ;
   RECT 43.008000 626.172000 43.200000 626.196000 ;
  END
 END pi3[198]
 PIN pi3[199]
  DIRECTION OUTPUT ;
  USE SIGNAL ;
  PORT
   LAYER M6 ;
   RECT 43.008000 626.288000 43.200000 626.320000 ;
  END
 END pi3[199]
 PIN pi3[200]
  DIRECTION OUTPUT ;
  USE SIGNAL ;
  PORT
   LAYER M4 ;
   RECT 43.008000 626.508000 43.200000 626.532000 ;
  END
 END pi3[200]
 PIN pi3[201]
  DIRECTION OUTPUT ;
  USE SIGNAL ;
  PORT
   LAYER M6 ;
   RECT 43.008000 626.544000 43.200000 626.576000 ;
  END
 END pi3[201]
 PIN pi3[202]
  DIRECTION OUTPUT ;
  USE SIGNAL ;
  PORT
   LAYER M4 ;
   RECT 43.008000 626.844000 43.200000 626.868000 ;
  END
 END pi3[202]
 PIN pi3[203]
  DIRECTION OUTPUT ;
  USE SIGNAL ;
  PORT
   LAYER M6 ;
   RECT 43.008000 626.800000 43.200000 626.832000 ;
  END
 END pi3[203]
 PIN pi3[204]
  DIRECTION OUTPUT ;
  USE SIGNAL ;
  PORT
   LAYER M4 ;
   RECT 43.008000 627.180000 43.200000 627.204000 ;
  END
 END pi3[204]
 PIN pi3[205]
  DIRECTION OUTPUT ;
  USE SIGNAL ;
  PORT
   LAYER M6 ;
   RECT 43.008000 627.056000 43.200000 627.088000 ;
  END
 END pi3[205]
 PIN pi3[206]
  DIRECTION OUTPUT ;
  USE SIGNAL ;
  PORT
   LAYER M4 ;
   RECT 43.008000 627.516000 43.200000 627.540000 ;
  END
 END pi3[206]
 PIN pi3[207]
  DIRECTION OUTPUT ;
  USE SIGNAL ;
  PORT
   LAYER M6 ;
   RECT 43.008000 627.312000 43.200000 627.344000 ;
  END
 END pi3[207]
 PIN pi3[208]
  DIRECTION OUTPUT ;
  USE SIGNAL ;
  PORT
   LAYER M4 ;
   RECT 43.008000 627.852000 43.200000 627.876000 ;
  END
 END pi3[208]
 PIN pi3[209]
  DIRECTION OUTPUT ;
  USE SIGNAL ;
  PORT
   LAYER M6 ;
   RECT 43.008000 627.568000 43.200000 627.600000 ;
  END
 END pi3[209]
 PIN pi3[210]
  DIRECTION OUTPUT ;
  USE SIGNAL ;
  PORT
   LAYER M4 ;
   RECT 43.008000 628.188000 43.200000 628.212000 ;
  END
 END pi3[210]
 PIN pi3[211]
  DIRECTION OUTPUT ;
  USE SIGNAL ;
  PORT
   LAYER M6 ;
   RECT 43.008000 627.824000 43.200000 627.856000 ;
  END
 END pi3[211]
 PIN pi3[212]
  DIRECTION OUTPUT ;
  USE SIGNAL ;
  PORT
   LAYER M4 ;
   RECT 43.008000 628.524000 43.200000 628.548000 ;
  END
 END pi3[212]
 PIN pi3[213]
  DIRECTION OUTPUT ;
  USE SIGNAL ;
  PORT
   LAYER M6 ;
   RECT 43.008000 629.040000 43.200000 629.072000 ;
  END
 END pi3[213]
 PIN pi3[214]
  DIRECTION OUTPUT ;
  USE SIGNAL ;
  PORT
   LAYER M4 ;
   RECT 43.008000 628.860000 43.200000 628.884000 ;
  END
 END pi3[214]
 PIN pi3[215]
  DIRECTION OUTPUT ;
  USE SIGNAL ;
  PORT
   LAYER M6 ;
   RECT 43.008000 629.296000 43.200000 629.328000 ;
  END
 END pi3[215]
 PIN pi3[216]
  DIRECTION OUTPUT ;
  USE SIGNAL ;
  PORT
   LAYER M4 ;
   RECT 43.008000 629.196000 43.200000 629.220000 ;
  END
 END pi3[216]
 PIN pi3[217]
  DIRECTION OUTPUT ;
  USE SIGNAL ;
  PORT
   LAYER M6 ;
   RECT 43.008000 629.616000 43.200000 629.648000 ;
  END
 END pi3[217]
 PIN pi3[218]
  DIRECTION OUTPUT ;
  USE SIGNAL ;
  PORT
   LAYER M4 ;
   RECT 43.008000 629.532000 43.200000 629.556000 ;
  END
 END pi3[218]
 PIN pi3[219]
  DIRECTION OUTPUT ;
  USE SIGNAL ;
  PORT
   LAYER M6 ;
   RECT 43.008000 629.872000 43.200000 629.904000 ;
  END
 END pi3[219]
 PIN pi3[220]
  DIRECTION OUTPUT ;
  USE SIGNAL ;
  PORT
   LAYER M4 ;
   RECT 43.008000 629.868000 43.200000 629.892000 ;
  END
 END pi3[220]
 PIN pi3[221]
  DIRECTION OUTPUT ;
  USE SIGNAL ;
  PORT
   LAYER M6 ;
   RECT 43.008000 630.128000 43.200000 630.160000 ;
  END
 END pi3[221]
 PIN pi3[222]
  DIRECTION OUTPUT ;
  USE SIGNAL ;
  PORT
   LAYER M4 ;
   RECT 43.008000 630.204000 43.200000 630.228000 ;
  END
 END pi3[222]
 PIN pi3[223]
  DIRECTION OUTPUT ;
  USE SIGNAL ;
  PORT
   LAYER M6 ;
   RECT 43.008000 630.384000 43.200000 630.416000 ;
  END
 END pi3[223]
 PIN pi3[224]
  DIRECTION OUTPUT ;
  USE SIGNAL ;
  PORT
   LAYER M4 ;
   RECT 43.008000 630.540000 43.200000 630.564000 ;
  END
 END pi3[224]
 PIN pi3[225]
  DIRECTION OUTPUT ;
  USE SIGNAL ;
  PORT
   LAYER M6 ;
   RECT 43.008000 630.640000 43.200000 630.672000 ;
  END
 END pi3[225]
 PIN pi3[226]
  DIRECTION OUTPUT ;
  USE SIGNAL ;
  PORT
   LAYER M4 ;
   RECT 43.008000 630.876000 43.200000 630.900000 ;
  END
 END pi3[226]
 PIN pi3[227]
  DIRECTION OUTPUT ;
  USE SIGNAL ;
  PORT
   LAYER M6 ;
   RECT 43.008000 630.896000 43.200000 630.928000 ;
  END
 END pi3[227]
 PIN pi3[228]
  DIRECTION OUTPUT ;
  USE SIGNAL ;
  PORT
   LAYER M4 ;
   RECT 43.008000 631.212000 43.200000 631.236000 ;
  END
 END pi3[228]
 PIN pi3[229]
  DIRECTION OUTPUT ;
  USE SIGNAL ;
  PORT
   LAYER M6 ;
   RECT 43.008000 631.152000 43.200000 631.184000 ;
  END
 END pi3[229]
 PIN pi3[230]
  DIRECTION OUTPUT ;
  USE SIGNAL ;
  PORT
   LAYER M4 ;
   RECT 43.008000 631.500000 43.200000 631.524000 ;
  END
 END pi3[230]
 PIN pi3[231]
  DIRECTION OUTPUT ;
  USE SIGNAL ;
  PORT
   LAYER M6 ;
   RECT 43.008000 631.408000 43.200000 631.440000 ;
  END
 END pi3[231]
 PIN pi3[232]
  DIRECTION OUTPUT ;
  USE SIGNAL ;
  PORT
   LAYER M4 ;
   RECT 43.008000 631.836000 43.200000 631.860000 ;
  END
 END pi3[232]
 PIN pi3[233]
  DIRECTION OUTPUT ;
  USE SIGNAL ;
  PORT
   LAYER M6 ;
   RECT 43.008000 631.664000 43.200000 631.696000 ;
  END
 END pi3[233]
 PIN pi3[234]
  DIRECTION OUTPUT ;
  USE SIGNAL ;
  PORT
   LAYER M4 ;
   RECT 43.008000 632.172000 43.200000 632.196000 ;
  END
 END pi3[234]
 PIN pi3[235]
  DIRECTION OUTPUT ;
  USE SIGNAL ;
  PORT
   LAYER M6 ;
   RECT 43.008000 631.920000 43.200000 631.952000 ;
  END
 END pi3[235]
 PIN pi3[236]
  DIRECTION OUTPUT ;
  USE SIGNAL ;
  PORT
   LAYER M4 ;
   RECT 43.008000 632.508000 43.200000 632.532000 ;
  END
 END pi3[236]
 PIN pi3[237]
  DIRECTION OUTPUT ;
  USE SIGNAL ;
  PORT
   LAYER M6 ;
   RECT 43.008000 632.240000 43.200000 632.272000 ;
  END
 END pi3[237]
 PIN pi3[238]
  DIRECTION OUTPUT ;
  USE SIGNAL ;
  PORT
   LAYER M4 ;
   RECT 43.008000 632.844000 43.200000 632.868000 ;
  END
 END pi3[238]
 PIN pi3[239]
  DIRECTION OUTPUT ;
  USE SIGNAL ;
  PORT
   LAYER M6 ;
   RECT 43.008000 633.456000 43.200000 633.488000 ;
  END
 END pi3[239]
 PIN pi3[240]
  DIRECTION OUTPUT ;
  USE SIGNAL ;
  PORT
   LAYER M4 ;
   RECT 43.008000 633.180000 43.200000 633.204000 ;
  END
 END pi3[240]
 PIN pi3[241]
  DIRECTION OUTPUT ;
  USE SIGNAL ;
  PORT
   LAYER M6 ;
   RECT 43.008000 633.712000 43.200000 633.744000 ;
  END
 END pi3[241]
 PIN pi3[242]
  DIRECTION OUTPUT ;
  USE SIGNAL ;
  PORT
   LAYER M4 ;
   RECT 43.008000 633.516000 43.200000 633.540000 ;
  END
 END pi3[242]
 PIN pi3[243]
  DIRECTION OUTPUT ;
  USE SIGNAL ;
  PORT
   LAYER M6 ;
   RECT 43.008000 633.968000 43.200000 634.000000 ;
  END
 END pi3[243]
 PIN pi3[244]
  DIRECTION OUTPUT ;
  USE SIGNAL ;
  PORT
   LAYER M4 ;
   RECT 43.008000 633.852000 43.200000 633.876000 ;
  END
 END pi3[244]
 PIN pi3[245]
  DIRECTION OUTPUT ;
  USE SIGNAL ;
  PORT
   LAYER M6 ;
   RECT 43.008000 634.224000 43.200000 634.256000 ;
  END
 END pi3[245]
 PIN pi3[246]
  DIRECTION OUTPUT ;
  USE SIGNAL ;
  PORT
   LAYER M4 ;
   RECT 43.008000 634.188000 43.200000 634.212000 ;
  END
 END pi3[246]
 PIN pi3[247]
  DIRECTION OUTPUT ;
  USE SIGNAL ;
  PORT
   LAYER M6 ;
   RECT 43.008000 634.480000 43.200000 634.512000 ;
  END
 END pi3[247]
 PIN pi3[248]
  DIRECTION OUTPUT ;
  USE SIGNAL ;
  PORT
   LAYER M4 ;
   RECT 43.008000 634.524000 43.200000 634.548000 ;
  END
 END pi3[248]
 PIN pi3[249]
  DIRECTION OUTPUT ;
  USE SIGNAL ;
  PORT
   LAYER M6 ;
   RECT 43.008000 634.736000 43.200000 634.768000 ;
  END
 END pi3[249]
 PIN pi3[250]
  DIRECTION OUTPUT ;
  USE SIGNAL ;
  PORT
   LAYER M4 ;
   RECT 43.008000 634.860000 43.200000 634.884000 ;
  END
 END pi3[250]
 PIN pi3[251]
  DIRECTION OUTPUT ;
  USE SIGNAL ;
  PORT
   LAYER M6 ;
   RECT 43.008000 634.992000 43.200000 635.024000 ;
  END
 END pi3[251]
 PIN pi3[252]
  DIRECTION OUTPUT ;
  USE SIGNAL ;
  PORT
   LAYER M4 ;
   RECT 43.008000 635.196000 43.200000 635.220000 ;
  END
 END pi3[252]
 PIN pi3[253]
  DIRECTION OUTPUT ;
  USE SIGNAL ;
  PORT
   LAYER M6 ;
   RECT 43.008000 635.248000 43.200000 635.280000 ;
  END
 END pi3[253]
 PIN pi3[254]
  DIRECTION OUTPUT ;
  USE SIGNAL ;
  PORT
   LAYER M4 ;
   RECT 43.008000 635.532000 43.200000 635.556000 ;
  END
 END pi3[254]
 PIN pi3[255]
  DIRECTION OUTPUT ;
  USE SIGNAL ;
  PORT
   LAYER M6 ;
   RECT 43.008000 635.504000 43.200000 635.536000 ;
  END
 END pi3[255]
 PIN pi3[256]
  DIRECTION OUTPUT ;
  USE SIGNAL ;
  PORT
   LAYER M4 ;
   RECT 43.008000 635.868000 43.200000 635.892000 ;
  END
 END pi3[256]
 PIN pi3[257]
  DIRECTION OUTPUT ;
  USE SIGNAL ;
  PORT
   LAYER M6 ;
   RECT 43.008000 635.824000 43.200000 635.856000 ;
  END
 END pi3[257]
 PIN pi3[258]
  DIRECTION OUTPUT ;
  USE SIGNAL ;
  PORT
   LAYER M4 ;
   RECT 43.008000 636.204000 43.200000 636.228000 ;
  END
 END pi3[258]
 PIN pi3[259]
  DIRECTION OUTPUT ;
  USE SIGNAL ;
  PORT
   LAYER M6 ;
   RECT 43.008000 636.080000 43.200000 636.112000 ;
  END
 END pi3[259]
 PIN pi3[260]
  DIRECTION OUTPUT ;
  USE SIGNAL ;
  PORT
   LAYER M4 ;
   RECT 43.008000 636.540000 43.200000 636.564000 ;
  END
 END pi3[260]
 PIN pi3[261]
  DIRECTION OUTPUT ;
  USE SIGNAL ;
  PORT
   LAYER M6 ;
   RECT 43.008000 636.336000 43.200000 636.368000 ;
  END
 END pi3[261]
 PIN pi3[262]
  DIRECTION OUTPUT ;
  USE SIGNAL ;
  PORT
   LAYER M4 ;
   RECT 43.008000 636.876000 43.200000 636.900000 ;
  END
 END pi3[262]
 PIN pi3[263]
  DIRECTION OUTPUT ;
  USE SIGNAL ;
  PORT
   LAYER M6 ;
   RECT 43.008000 636.592000 43.200000 636.624000 ;
  END
 END pi3[263]
 PIN pi3[264]
  DIRECTION OUTPUT ;
  USE SIGNAL ;
  PORT
   LAYER M4 ;
   RECT 43.008000 637.212000 43.200000 637.236000 ;
  END
 END pi3[264]
 PIN pi3[265]
  DIRECTION OUTPUT ;
  USE SIGNAL ;
  PORT
   LAYER M6 ;
   RECT 43.008000 637.808000 43.200000 637.840000 ;
  END
 END pi3[265]
 PIN pi3[266]
  DIRECTION OUTPUT ;
  USE SIGNAL ;
  PORT
   LAYER M4 ;
   RECT 43.008000 637.548000 43.200000 637.572000 ;
  END
 END pi3[266]
 PIN pi3[267]
  DIRECTION OUTPUT ;
  USE SIGNAL ;
  PORT
   LAYER M6 ;
   RECT 43.008000 638.064000 43.200000 638.096000 ;
  END
 END pi3[267]
 PIN pi3[268]
  DIRECTION OUTPUT ;
  USE SIGNAL ;
  PORT
   LAYER M4 ;
   RECT 43.008000 637.836000 43.200000 637.860000 ;
  END
 END pi3[268]
 PIN pi3[269]
  DIRECTION OUTPUT ;
  USE SIGNAL ;
  PORT
   LAYER M6 ;
   RECT 43.008000 638.320000 43.200000 638.352000 ;
  END
 END pi3[269]
 PIN pi3[270]
  DIRECTION OUTPUT ;
  USE SIGNAL ;
  PORT
   LAYER M4 ;
   RECT 43.008000 638.172000 43.200000 638.196000 ;
  END
 END pi3[270]
 PIN pi3[271]
  DIRECTION OUTPUT ;
  USE SIGNAL ;
  PORT
   LAYER M6 ;
   RECT 43.008000 638.576000 43.200000 638.608000 ;
  END
 END pi3[271]
 PIN pi3[272]
  DIRECTION OUTPUT ;
  USE SIGNAL ;
  PORT
   LAYER M4 ;
   RECT 43.008000 638.508000 43.200000 638.532000 ;
  END
 END pi3[272]
 PIN pi3[273]
  DIRECTION OUTPUT ;
  USE SIGNAL ;
  PORT
   LAYER M6 ;
   RECT 43.008000 638.832000 43.200000 638.864000 ;
  END
 END pi3[273]
 PIN pi3[274]
  DIRECTION OUTPUT ;
  USE SIGNAL ;
  PORT
   LAYER M4 ;
   RECT 43.008000 638.844000 43.200000 638.868000 ;
  END
 END pi3[274]
 PIN pi3[275]
  DIRECTION OUTPUT ;
  USE SIGNAL ;
  PORT
   LAYER M6 ;
   RECT 43.008000 639.088000 43.200000 639.120000 ;
  END
 END pi3[275]
 PIN pi3[276]
  DIRECTION OUTPUT ;
  USE SIGNAL ;
  PORT
   LAYER M4 ;
   RECT 43.008000 639.180000 43.200000 639.204000 ;
  END
 END pi3[276]
 PIN pi3[277]
  DIRECTION OUTPUT ;
  USE SIGNAL ;
  PORT
   LAYER M4 ;
   RECT 43.008000 1061.292000 43.200000 1061.316000 ;
  END
 END pi3[277]
 PIN pi3[278]
  DIRECTION OUTPUT ;
  USE SIGNAL ;
  PORT
   LAYER M6 ;
   RECT 43.008000 1061.296000 43.200000 1061.328000 ;
  END
 END pi3[278]
 PIN pi3[279]
  DIRECTION OUTPUT ;
  USE SIGNAL ;
  PORT
   LAYER M4 ;
   RECT 43.008000 1061.580000 43.200000 1061.604000 ;
  END
 END pi3[279]
 PIN pi3[280]
  DIRECTION OUTPUT ;
  USE SIGNAL ;
  PORT
   LAYER M6 ;
   RECT 43.008000 1061.680000 43.200000 1061.712000 ;
  END
 END pi3[280]
 PIN pi3[281]
  DIRECTION OUTPUT ;
  USE SIGNAL ;
  PORT
   LAYER M4 ;
   RECT 43.008000 1061.916000 43.200000 1061.940000 ;
  END
 END pi3[281]
 PIN pi3[282]
  DIRECTION OUTPUT ;
  USE SIGNAL ;
  PORT
   LAYER M6 ;
   RECT 43.008000 1062.000000 43.200000 1062.032000 ;
  END
 END pi3[282]
 PIN pi3[283]
  DIRECTION OUTPUT ;
  USE SIGNAL ;
  PORT
   LAYER M4 ;
   RECT 43.008000 1062.252000 43.200000 1062.276000 ;
  END
 END pi3[283]
 PIN pi3[284]
  DIRECTION OUTPUT ;
  USE SIGNAL ;
  PORT
   LAYER M6 ;
   RECT 43.008000 1062.384000 43.200000 1062.416000 ;
  END
 END pi3[284]
 PIN pi3[285]
  DIRECTION OUTPUT ;
  USE SIGNAL ;
  PORT
   LAYER M4 ;
   RECT 43.008000 1062.540000 43.200000 1062.564000 ;
  END
 END pi3[285]
 PIN pi3[286]
  DIRECTION OUTPUT ;
  USE SIGNAL ;
  PORT
   LAYER M6 ;
   RECT 43.008000 1062.704000 43.200000 1062.736000 ;
  END
 END pi3[286]
 PIN pi3[287]
  DIRECTION OUTPUT ;
  USE SIGNAL ;
  PORT
   LAYER M4 ;
   RECT 43.008000 1062.876000 43.200000 1062.900000 ;
  END
 END pi3[287]
 PIN pi3[288]
  DIRECTION OUTPUT ;
  USE SIGNAL ;
  PORT
   LAYER M6 ;
   RECT 43.008000 1063.088000 43.200000 1063.120000 ;
  END
 END pi3[288]
 PIN fh3[0]
  DIRECTION OUTPUT ;
  USE SIGNAL ;
  PORT
   LAYER M4 ;
   RECT 43.008000 592.524000 43.200000 592.548000 ;
  END
 END fh3[0]
 PIN fh3[1]
  DIRECTION OUTPUT ;
  USE SIGNAL ;
  PORT
   LAYER M6 ;
   RECT 43.008000 592.048000 43.200000 592.080000 ;
  END
 END fh3[1]
 PIN fh3[2]
  DIRECTION OUTPUT ;
  USE SIGNAL ;
  PORT
   LAYER M4 ;
   RECT 43.008000 592.860000 43.200000 592.884000 ;
  END
 END fh3[2]
 PIN fh3[3]
  DIRECTION OUTPUT ;
  USE SIGNAL ;
  PORT
   LAYER M6 ;
   RECT 43.008000 592.304000 43.200000 592.336000 ;
  END
 END fh3[3]
 PIN rh3[0]
  DIRECTION OUTPUT ;
  USE SIGNAL ;
  PORT
   LAYER M4 ;
   RECT 43.008000 1063.164000 43.200000 1063.188000 ;
  END
 END rh3[0]
 PIN rh3[1]
  DIRECTION OUTPUT ;
  USE SIGNAL ;
  PORT
   LAYER M6 ;
   RECT 43.008000 1063.408000 43.200000 1063.440000 ;
  END
 END rh3[1]
 PIN rh3[2]
  DIRECTION OUTPUT ;
  USE SIGNAL ;
  PORT
   LAYER M4 ;
   RECT 43.008000 1063.500000 43.200000 1063.524000 ;
  END
 END rh3[2]
 PIN rh3[3]
  DIRECTION OUTPUT ;
  USE SIGNAL ;
  PORT
   LAYER M6 ;
   RECT 43.008000 1063.792000 43.200000 1063.824000 ;
  END
 END rh3[3]
 PIN VDD
  DIRECTION INOUT ;
  USE POWER ;
  PORT
   LAYER M6 ;
   RECT 4.32 4.32 38.88 4.608 ;
  END
 END VDD
 PIN VSS
  DIRECTION INOUT ;
  USE GROUND ;
  PORT
   LAYER M6 ;
   RECT 4.32 6.72 38.88 7.008 ;
  END
 END VSS
 OBS
  LAYER M1 ;
   RECT 0.4 0.4 42.8 1511.6 ;
  LAYER M2 ;
   RECT 0.4 0.4 42.8 1511.6 ;
  LAYER M3 ;
   RECT 0.4 0.4 42.8 1511.6 ;
 END
END qkd_hbm3e_phy_pc4
END LIBRARY
